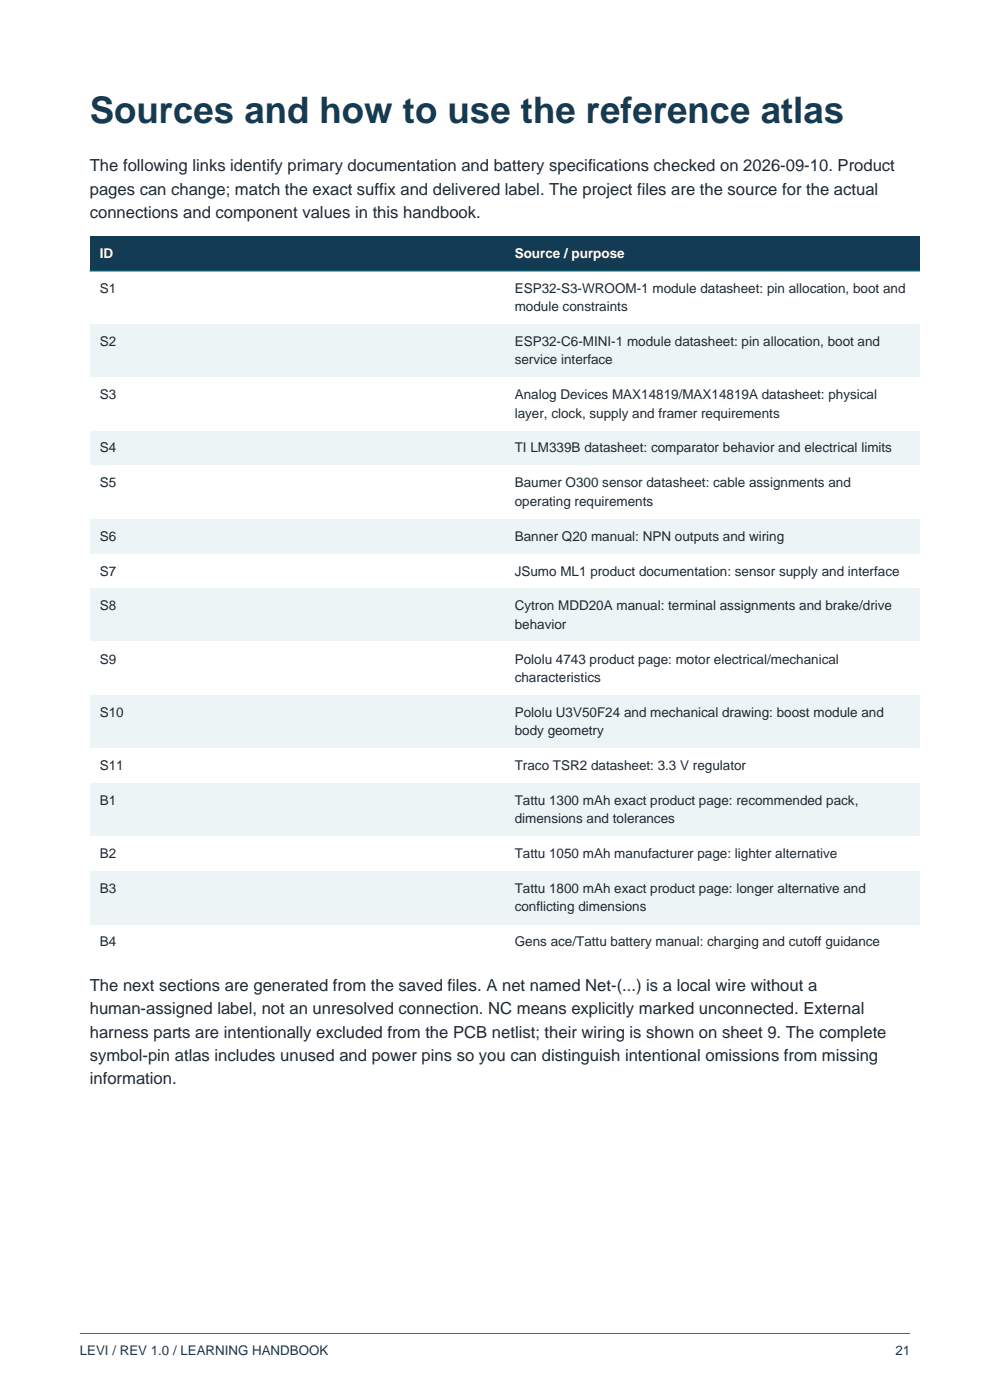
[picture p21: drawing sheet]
<svg xmlns="http://www.w3.org/2000/svg" width="210mm" height="297mm" viewBox="0 0 210 297" stroke-linecap="round" stroke-linejoin="round" font-family="sans-serif">
<defs><g id="words">
<text font-size="7.8" fill="#133b53" x="19" y="26.1">Sources and how to use the reference atlas</text>
<g font-size="3.5" fill="#1f2933">
<text x="19" y="36.3">The following links identify primary documentation and battery specifications checked on 2026-09-10. Product</text>
<text x="19" y="41.3">pages can change; match the exact suffix and delivered label. The project files are the source for the actual</text>
<text x="19" y="46.2">connections and component values in this handbook.</text>
<text x="19" y="210.3">The next sections are generated from the saved files. A net named Net-(...) is a local wire without a</text>
<text x="19" y="215.2">human-assigned label, not an unresolved connection. NC means explicitly marked unconnected. External</text>
<text x="19" y="220.1">harness parts are intentionally excluded from the PCB netlist; their wiring is shown on sheet 9. The complete</text>
<text x="19" y="225.1">symbol-pin atlas includes unused and power pins so you can distinguish intentional omissions from missing</text>
<text x="19" y="230">information.</text>
</g>
<g font-size="2.9" fill="#fff">
<text x="21.2" y="54.7">ID</text>
<text x="109.2" y="54.7">Source / purpose</text>
</g>
<g font-size="2.9" fill="#1f2933">
<text x="21.2" y="62.1">S1</text>
<text x="109.2" y="62.1">ESP32-S3-WROOM-1 module datasheet: pin allocation, boot and</text>
<text x="109.2" y="66">module constraints</text>
<text x="21.2" y="73.4">S2</text>
<text x="109.2" y="73.4">ESP32-C6-MINI-1 module datasheet: pin allocation, boot and</text>
<text x="109.2" y="77.3">service interface</text>
<text x="21.2" y="84.7">S3</text>
<text x="109.2" y="84.7">Analog Devices MAX14819/MAX14819A datasheet: physical</text>
<text x="109.2" y="88.6">layer, clock, supply and framer requirements</text>
<text x="21.2" y="96">S4</text>
<text x="109.2" y="96">TI LM339B datasheet: comparator behavior and electrical limits</text>
<text x="21.2" y="103.4">S5</text>
<text x="109.2" y="103.4">Baumer O300 sensor datasheet: cable assignments and</text>
<text x="109.2" y="107.3">operating requirements</text>
<text x="21.2" y="114.7">S6</text>
<text x="109.2" y="114.7">Banner Q20 manual: NPN outputs and wiring</text>
<text x="21.2" y="122.1">S7</text>
<text x="109.2" y="122.1">JSumo ML1 product documentation: sensor supply and interface</text>
<text x="21.2" y="129.5">S8</text>
<text x="109.2" y="129.5">Cytron MDD20A manual: terminal assignments and brake/drive</text>
<text x="109.2" y="133.4">behavior</text>
<text x="21.2" y="140.8">S9</text>
<text x="109.2" y="140.8">Pololu 4743 product page: motor electrical/mechanical</text>
<text x="109.2" y="144.7">characteristics</text>
<text x="21.2" y="152.1">S10</text>
<text x="109.2" y="152.1">Pololu U3V50F24 and mechanical drawing: boost module and</text>
<text x="109.2" y="156">body geometry</text>
<text x="21.2" y="163.4">S11</text>
<text x="109.2" y="163.4">Traco TSR2 datasheet: 3.3 V regulator</text>
<text x="21.2" y="170.8">B1</text>
<text x="109.2" y="170.8">Tattu 1300 mAh exact product page: recommended pack,</text>
<text x="109.2" y="174.7">dimensions and tolerances</text>
<text x="21.2" y="182.1">B2</text>
<text x="109.2" y="182.1">Tattu 1050 mAh manufacturer page: lighter alternative</text>
<text x="21.2" y="189.5">B3</text>
<text x="109.2" y="189.5">Tattu 1800 mAh exact product page: longer alternative and</text>
<text x="109.2" y="193.4">conflicting dimensions</text>
<text x="21.2" y="200.8">B4</text>
<text x="109.2" y="200.8">Gens ace/Tattu battery manual: charging and cutoff guidance</text>
</g>
<g font-size="2.8" fill="#133b53">
<text x="16.9" y="287.5">LEVI / REV 1.0 / LEARNING HANDBOOK</text>
<text x="189.9" y="287.5">21</text>
</g>
</g></defs>
<path d="M16.9 282.9h176.2" fill="none" stroke="#087f8c" stroke-width=".21"/>
<path d="M19 50.1h176.1v7.4h-176.1z" fill-rule="evenodd" fill="#133b53"/>
<path d="M19 57.5h176.1v11.3h-176.1z" fill-rule="evenodd" fill="#fff"/>
<path d="M19 68.8h176.1v11.3h-176.1z" fill-rule="evenodd" fill="#edf4f6"/>
<path d="M19 80.1h176.1v11.3h-176.1z" fill-rule="evenodd" fill="#fff"/>
<path d="M19 91.4h176.1v7.4h-176.1z" fill-rule="evenodd" fill="#edf4f6"/>
<path d="M19 98.8h176.1v11.3h-176.1z" fill-rule="evenodd" fill="#fff"/>
<path d="M19 110.1h176.1v7.4h-176.1z" fill-rule="evenodd" fill="#edf4f6"/>
<path d="M19 117.5h176.1v7.4h-176.1z" fill-rule="evenodd" fill="#fff"/>
<path d="M19 124.9h176.1v11.3h-176.1z" fill-rule="evenodd" fill="#edf4f6"/>
<path d="M19 136.2h176.1v11.3h-176.1z" fill-rule="evenodd" fill="#fff"/>
<path d="M19 147.5h176.1v11.2h-176.1z" fill-rule="evenodd" fill="#edf4f6"/>
<path d="M19 158.7h176.1v7.5h-176.1z" fill-rule="evenodd" fill="#fff"/>
<path d="M19 166.2h176.1v11.2h-176.1z" fill-rule="evenodd" fill="#edf4f6"/>
<path d="M19 177.4h176.1v7.5h-176.1z" fill-rule="evenodd" fill="#fff"/>
<path d="M19 184.9h176.1v11.2h-176.1z" fill-rule="evenodd" fill="#edf4f6"/>
<path d="M19 196.1h176.1v7.5h-176.1z" fill-rule="evenodd" fill="#fff"/>
<path d="M19 57.5h176.1" fill="none" stroke="#087f8c" stroke-width=".21"/>
<use href="#words"/>
</svg>
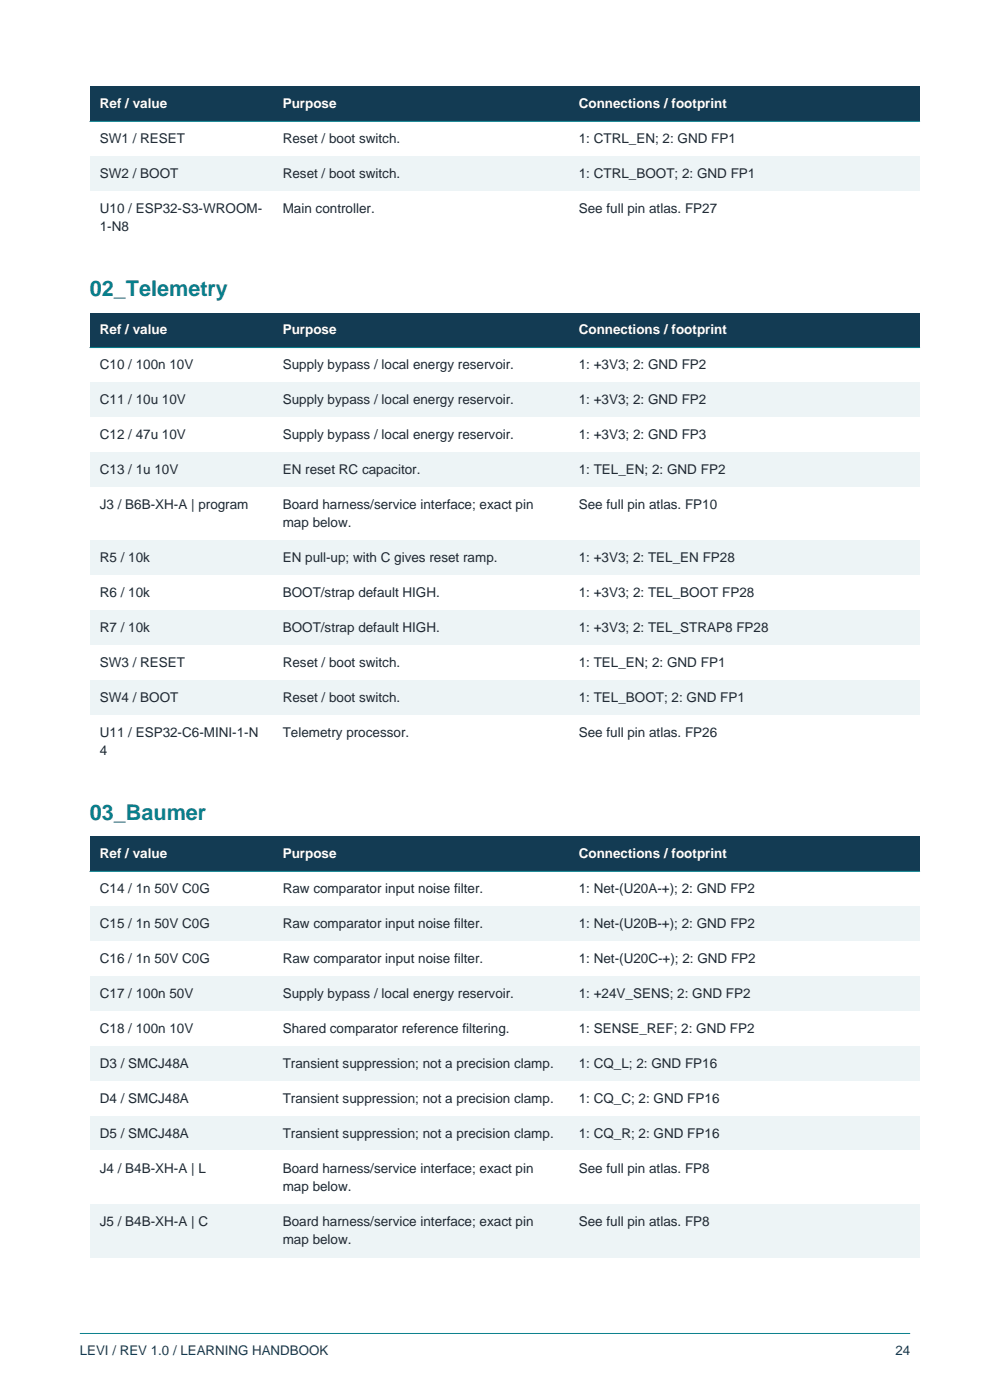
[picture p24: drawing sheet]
<svg xmlns="http://www.w3.org/2000/svg" width="210mm" height="297mm" viewBox="0 0 210 297" stroke-linecap="round" stroke-linejoin="round" font-family="sans-serif">
<defs><g id="words">
<g font-size="4.6" fill="#087f8c">
<text x="19" y="62.8">02_Telemetry</text>
<text x="19" y="173.9">03_Baumer</text>
</g>
<g font-size="2.9" fill="#fff">
<text x="21.2" y="23">Ref / value</text>
<text x="60" y="23">Purpose</text>
<text x="122.8" y="23">Connections / footprint</text>
<text x="21.2" y="70.9">Ref / value</text>
<text x="60" y="70.9">Purpose</text>
<text x="122.8" y="70.9">Connections / footprint</text>
<text x="21.2" y="182.1">Ref / value</text>
<text x="60" y="182.1">Purpose</text>
<text x="122.8" y="182.1">Connections / footprint</text>
</g>
<g font-size="2.9" fill="#1f2933">
<text x="21.2" y="30.4">SW1 / RESET</text>
<text x="60" y="30.4">Reset / boot switch.</text>
<text x="122.8" y="30.4">1: CTRL_EN; 2: GND FP1</text>
<text x="21.2" y="37.8">SW2 / BOOT</text>
<text x="60" y="37.8">Reset / boot switch.</text>
<text x="122.8" y="37.8">1: CTRL_BOOT; 2: GND FP1</text>
<text x="21.2" y="45.2">U10 / ESP32-S3-WROOM-</text>
<text x="60" y="45.2">Main controller.</text>
<text x="122.8" y="45.2">See full pin atlas. FP27</text>
<text x="21.2" y="49.1">1-N8</text>
<text x="21.2" y="78.4">C10 / 100n 10V</text>
<text x="60" y="78.4">Supply bypass / local energy reservoir.</text>
<text x="122.8" y="78.4">1: +3V3; 2: GND FP2</text>
<text x="21.2" y="85.8">C11 / 10u 10V</text>
<text x="60" y="85.8">Supply bypass / local energy reservoir.</text>
<text x="122.8" y="85.8">1: +3V3; 2: GND FP2</text>
<text x="21.2" y="93.2">C12 / 47u 10V</text>
<text x="60" y="93.2">Supply bypass / local energy reservoir.</text>
<text x="122.8" y="93.2">1: +3V3; 2: GND FP3</text>
<text x="21.2" y="100.6">C13 / 1u 10V</text>
<text x="60" y="100.6">EN reset RC capacitor.</text>
<text x="122.8" y="100.6">1: TEL_EN; 2: GND FP2</text>
<text x="21.2" y="108">J3 / B6B-XH-A | program</text>
<text x="60" y="108">Board harness/service interface; exact pin</text>
<text x="122.8" y="108">See full pin atlas. FP10</text>
<text x="60" y="111.9">map below.</text>
<text x="21.2" y="119.3">R5 / 10k</text>
<text x="60" y="119.3">EN pull-up; with C gives reset ramp.</text>
<text x="122.8" y="119.3">1: +3V3; 2: TEL_EN FP28</text>
<text x="21.2" y="126.7">R6 / 10k</text>
<text x="60" y="126.7">BOOT/strap default HIGH.</text>
<text x="122.8" y="126.7">1: +3V3; 2: TEL_BOOT FP28</text>
<text x="21.2" y="134.1">R7 / 10k</text>
<text x="60" y="134.1">BOOT/strap default HIGH.</text>
<text x="122.8" y="134.1">1: +3V3; 2: TEL_STRAP8 FP28</text>
<text x="21.2" y="141.5">SW3 / RESET</text>
<text x="60" y="141.5">Reset / boot switch.</text>
<text x="122.8" y="141.5">1: TEL_EN; 2: GND FP1</text>
<text x="21.2" y="148.9">SW4 / BOOT</text>
<text x="60" y="148.9">Reset / boot switch.</text>
<text x="122.8" y="148.9">1: TEL_BOOT; 2: GND FP1</text>
<text x="21.2" y="156.3">U11 / ESP32-C6-MINI-1-N</text>
<text x="21.2" y="160.2">4</text>
<text x="60" y="156.3">Telemetry processor.</text>
<text x="122.8" y="156.3">See full pin atlas. FP26</text>
<text x="21.2" y="189.5">C14 / 1n 50V C0G</text>
<text x="60" y="189.5">Raw comparator input noise filter.</text>
<text x="122.8" y="189.5">1: Net-(U20A-+); 2: GND FP2</text>
<text x="21.2" y="196.9">C15 / 1n 50V C0G</text>
<text x="60" y="196.9">Raw comparator input noise filter.</text>
<text x="122.8" y="196.9">1: Net-(U20B-+); 2: GND FP2</text>
<text x="21.2" y="204.3">C16 / 1n 50V C0G</text>
<text x="60" y="204.3">Raw comparator input noise filter.</text>
<text x="122.8" y="204.3">1: Net-(U20C-+); 2: GND FP2</text>
<text x="21.2" y="211.7">C17 / 100n 50V</text>
<text x="60" y="211.7">Supply bypass / local energy reservoir.</text>
<text x="122.8" y="211.7">1: +24V_SENS; 2: GND FP2</text>
<text x="21.2" y="219.1">C18 / 100n 10V</text>
<text x="60" y="219.1">Shared comparator reference filtering.</text>
<text x="122.8" y="219.1">1: SENSE_REF; 2: GND FP2</text>
<text x="21.2" y="226.5">D3 / SMCJ48A</text>
<text x="60" y="226.5">Transient suppression; not a precision clamp.</text>
<text x="122.8" y="226.5">1: CQ_L; 2: GND FP16</text>
<text x="21.2" y="233.9">D4 / SMCJ48A</text>
<text x="60" y="233.9">Transient suppression; not a precision clamp.</text>
<text x="122.8" y="233.9">1: CQ_C; 2: GND FP16</text>
<text x="21.2" y="241.3">D5 / SMCJ48A</text>
<text x="60" y="241.3">Transient suppression; not a precision clamp.</text>
<text x="122.8" y="241.3">1: CQ_R; 2: GND FP16</text>
<text x="21.2" y="248.7">J4 / B4B-XH-A | L</text>
<text x="60" y="248.7">Board harness/service interface; exact pin</text>
<text x="122.8" y="248.7">See full pin atlas. FP8</text>
<text x="60" y="252.6">map below.</text>
<text x="21.2" y="260">J5 / B4B-XH-A | C</text>
<text x="60" y="260">Board harness/service interface; exact pin</text>
<text x="60" y="263.9">map below.</text>
<text x="122.8" y="260">See full pin atlas. FP8</text>
</g>
<g font-size="2.8" fill="#133b53">
<text x="16.9" y="287.5">LEVI / REV 1.0 / LEARNING HANDBOOK</text>
<text x="189.9" y="287.5">24</text>
</g>
</g></defs>
<path d="M16.9 282.9h176.2" fill="none" stroke="#087f8c" stroke-width=".21"/>
<path d="M19 18.3h176.1v7.5h-176.1z" fill-rule="evenodd" fill="#133b53"/>
<path d="M19 25.8h176.1v7.4h-176.1z" fill-rule="evenodd" fill="#fff"/>
<path d="M19 33.2h176.1v7.4h-176.1z" fill-rule="evenodd" fill="#edf4f6"/>
<path d="M19 40.6h176.1v11.3h-176.1z" fill-rule="evenodd" fill="#fff"/>
<path d="M19 25.8h176.1" fill="none" stroke="#087f8c" stroke-width=".21"/>
<path d="M19 66.3h176.1v7.4h-176.1z" fill-rule="evenodd" fill="#133b53"/>
<path d="M19 73.7h176.1v7.4h-176.1z" fill-rule="evenodd" fill="#fff"/>
<path d="M19 81.1h176.1v7.4h-176.1z" fill-rule="evenodd" fill="#edf4f6"/>
<path d="M19 88.5h176.1v7.5h-176.1z" fill-rule="evenodd" fill="#fff"/>
<path d="M19 96h176.1v7.4h-176.1z" fill-rule="evenodd" fill="#edf4f6"/>
<path d="M19 103.4h176.1v11.3h-176.1z" fill-rule="evenodd" fill="#fff"/>
<path d="M19 114.7h176.1v7.4h-176.1z" fill-rule="evenodd" fill="#edf4f6"/>
<path d="M19 122.1h176.1v7.4h-176.1z" fill-rule="evenodd" fill="#fff"/>
<path d="M19 129.5h176.1v7.4h-176.1z" fill-rule="evenodd" fill="#edf4f6"/>
<path d="M19 136.9h176.1v7.4h-176.1z" fill-rule="evenodd" fill="#fff"/>
<path d="M19 144.3h176.1v7.4h-176.1z" fill-rule="evenodd" fill="#edf4f6"/>
<path d="M19 151.7h176.1v11.3h-176.1z" fill-rule="evenodd" fill="#fff"/>
<path d="M19 73.7h176.1" fill="none" stroke="#087f8c" stroke-width=".21"/>
<path d="M19 177.4h176.1v7.5h-176.1z" fill-rule="evenodd" fill="#133b53"/>
<path d="M19 184.9h176.1v7.4h-176.1z" fill-rule="evenodd" fill="#fff"/>
<path d="M19 192.3h176.1v7.4h-176.1z" fill-rule="evenodd" fill="#edf4f6"/>
<path d="M19 199.7h176.1v7.4h-176.1z" fill-rule="evenodd" fill="#fff"/>
<path d="M19 207.1h176.1v7.4h-176.1z" fill-rule="evenodd" fill="#edf4f6"/>
<path d="M19 214.5h176.1v7.4h-176.1z" fill-rule="evenodd" fill="#fff"/>
<path d="M19 221.9h176.1v7.4h-176.1z" fill-rule="evenodd" fill="#edf4f6"/>
<path d="M19 229.3h176.1v7.4h-176.1z" fill-rule="evenodd" fill="#fff"/>
<path d="M19 236.7h176.1v7.4h-176.1z" fill-rule="evenodd" fill="#edf4f6"/>
<path d="M19 244.1h176.1v11.3h-176.1z" fill-rule="evenodd" fill="#fff"/>
<path d="M19 255.4h176.1v11.3h-176.1z" fill-rule="evenodd" fill="#edf4f6"/>
<path d="M19 184.9h176.1" fill="none" stroke="#087f8c" stroke-width=".21"/>
<use href="#words"/>
</svg>
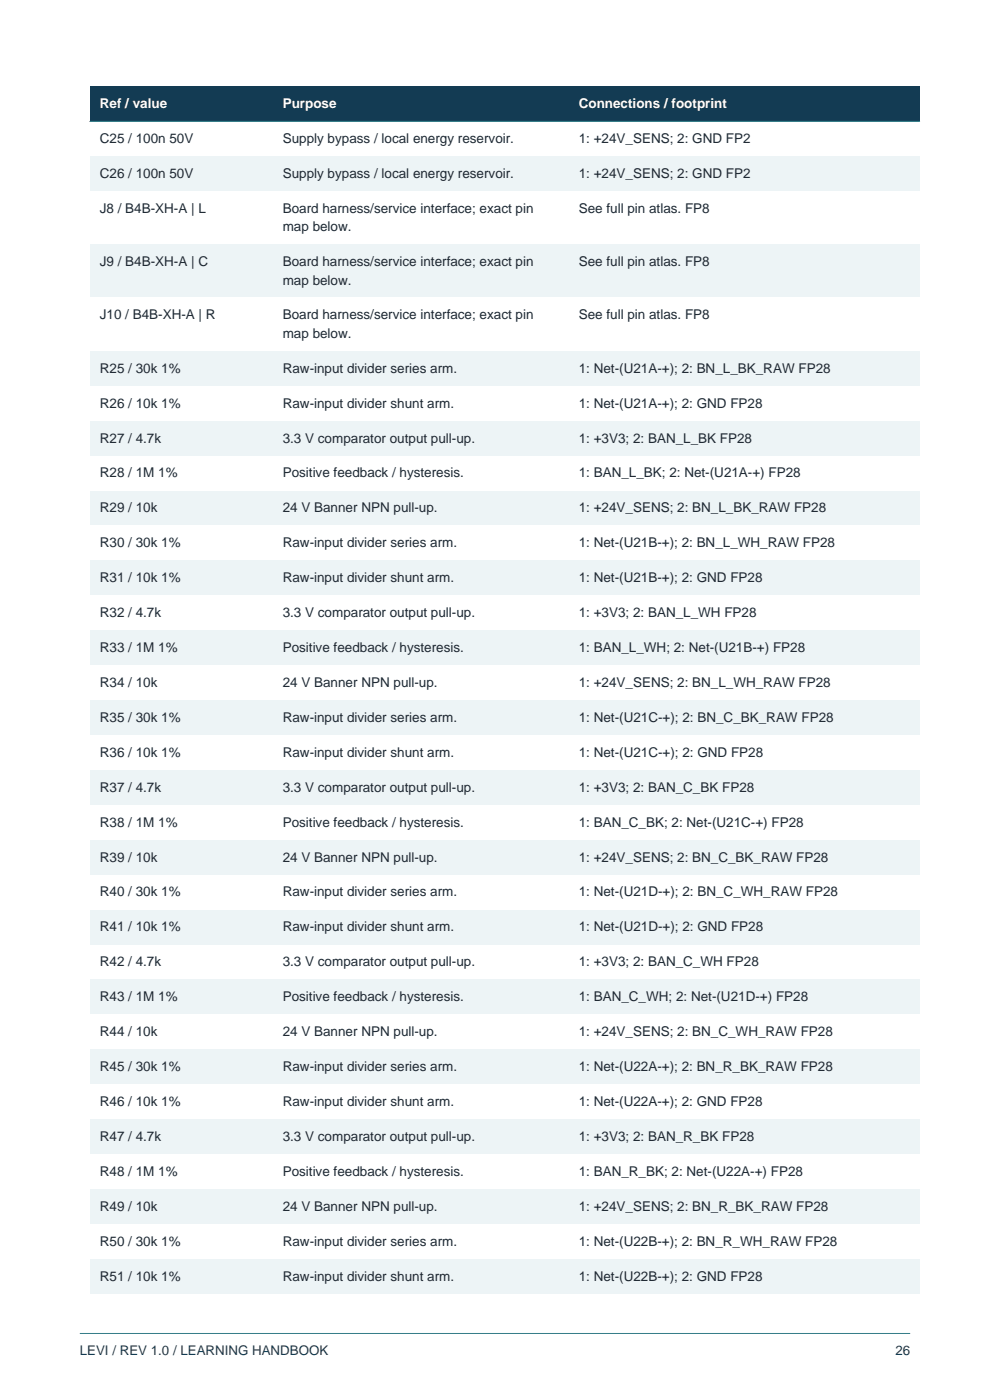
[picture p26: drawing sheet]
<svg xmlns="http://www.w3.org/2000/svg" width="210mm" height="297mm" viewBox="0 0 210 297" stroke-linecap="round" stroke-linejoin="round" font-family="sans-serif">
<defs><g id="words">
<g font-size="2.9" fill="#fff">
<text x="21.2" y="23">Ref / value</text>
<text x="60" y="23">Purpose</text>
<text x="122.8" y="23">Connections / footprint</text>
</g>
<g font-size="2.9" fill="#1f2933">
<text x="21.2" y="30.4">C25 / 100n 50V</text>
<text x="60" y="30.4">Supply bypass / local energy reservoir.</text>
<text x="122.8" y="30.4">1: +24V_SENS; 2: GND FP2</text>
<text x="21.2" y="37.8">C26 / 100n 50V</text>
<text x="60" y="37.8">Supply bypass / local energy reservoir.</text>
<text x="122.8" y="37.8">1: +24V_SENS; 2: GND FP2</text>
<text x="21.2" y="45.2">J8 / B4B-XH-A | L</text>
<text x="60" y="45.2">Board harness/service interface; exact pin</text>
<text x="122.8" y="45.2">See full pin atlas. FP8</text>
<text x="60" y="49.1">map below.</text>
<text x="21.2" y="56.5">J9 / B4B-XH-A | C</text>
<text x="60" y="56.5">Board harness/service interface; exact pin</text>
<text x="122.8" y="56.5">See full pin atlas. FP8</text>
<text x="60" y="60.4">map below.</text>
<text x="21.2" y="67.8">J10 / B4B-XH-A | R</text>
<text x="60" y="67.8">Board harness/service interface; exact pin</text>
<text x="60" y="71.6">map below.</text>
<text x="122.8" y="67.8">See full pin atlas. FP8</text>
<text x="21.2" y="79.1">R25 / 30k 1%</text>
<text x="60" y="79.1">Raw-input divider series arm.</text>
<text x="122.8" y="79.1">1: Net-(U21A-+); 2: BN_L_BK_RAW FP28</text>
<text x="21.2" y="86.5">R26 / 10k 1%</text>
<text x="60" y="86.5">Raw-input divider shunt arm.</text>
<text x="122.8" y="86.5">1: Net-(U21A-+); 2: GND FP28</text>
<text x="21.2" y="93.9">R27 / 4.7k</text>
<text x="60" y="93.9">3.3 V comparator output pull-up.</text>
<text x="122.8" y="93.9">1: +3V3; 2: BAN_L_BK FP28</text>
<text x="21.2" y="101.3">R28 / 1M 1%</text>
<text x="60" y="101.3">Positive feedback / hysteresis.</text>
<text x="122.8" y="101.3">1: BAN_L_BK; 2: Net-(U21A-+) FP28</text>
<text x="21.2" y="108.7">R29 / 10k</text>
<text x="60" y="108.7">24 V Banner NPN pull-up.</text>
<text x="122.8" y="108.7">1: +24V_SENS; 2: BN_L_BK_RAW FP28</text>
<text x="21.2" y="116.1">R30 / 30k 1%</text>
<text x="60" y="116.1">Raw-input divider series arm.</text>
<text x="122.8" y="116.1">1: Net-(U21B-+); 2: BN_L_WH_RAW FP28</text>
<text x="21.2" y="123.5">R31 / 10k 1%</text>
<text x="60" y="123.5">Raw-input divider shunt arm.</text>
<text x="122.8" y="123.5">1: Net-(U21B-+); 2: GND FP28</text>
<text x="21.2" y="130.9">R32 / 4.7k</text>
<text x="60" y="130.9">3.3 V comparator output pull-up.</text>
<text x="122.8" y="130.9">1: +3V3; 2: BAN_L_WH FP28</text>
<text x="21.2" y="138.3">R33 / 1M 1%</text>
<text x="60" y="138.3">Positive feedback / hysteresis.</text>
<text x="122.8" y="138.3">1: BAN_L_WH; 2: Net-(U21B-+) FP28</text>
<text x="21.2" y="145.7">R34 / 10k</text>
<text x="60" y="145.7">24 V Banner NPN pull-up.</text>
<text x="122.8" y="145.7">1: +24V_SENS; 2: BN_L_WH_RAW FP28</text>
<text x="21.2" y="153.1">R35 / 30k 1%</text>
<text x="60" y="153.1">Raw-input divider series arm.</text>
<text x="122.8" y="153.1">1: Net-(U21C-+); 2: BN_C_BK_RAW FP28</text>
<text x="21.2" y="160.5">R36 / 10k 1%</text>
<text x="60" y="160.5">Raw-input divider shunt arm.</text>
<text x="122.8" y="160.5">1: Net-(U21C-+); 2: GND FP28</text>
<text x="21.2" y="168">R37 / 4.7k</text>
<text x="60" y="168">3.3 V comparator output pull-up.</text>
<text x="122.8" y="168">1: +3V3; 2: BAN_C_BK FP28</text>
<text x="21.2" y="175.4">R38 / 1M 1%</text>
<text x="60" y="175.4">Positive feedback / hysteresis.</text>
<text x="122.8" y="175.4">1: BAN_C_BK; 2: Net-(U21C-+) FP28</text>
<text x="21.2" y="182.8">R39 / 10k</text>
<text x="60" y="182.8">24 V Banner NPN pull-up.</text>
<text x="122.8" y="182.8">1: +24V_SENS; 2: BN_C_BK_RAW FP28</text>
<text x="21.2" y="190.2">R40 / 30k 1%</text>
<text x="60" y="190.2">Raw-input divider series arm.</text>
<text x="122.8" y="190.2">1: Net-(U21D-+); 2: BN_C_WH_RAW FP28</text>
<text x="21.2" y="197.6">R41 / 10k 1%</text>
<text x="60" y="197.6">Raw-input divider shunt arm.</text>
<text x="122.8" y="197.6">1: Net-(U21D-+); 2: GND FP28</text>
<text x="21.2" y="205">R42 / 4.7k</text>
<text x="60" y="205">3.3 V comparator output pull-up.</text>
<text x="122.8" y="205">1: +3V3; 2: BAN_C_WH FP28</text>
<text x="21.2" y="212.4">R43 / 1M 1%</text>
<text x="60" y="212.4">Positive feedback / hysteresis.</text>
<text x="122.8" y="212.4">1: BAN_C_WH; 2: Net-(U21D-+) FP28</text>
<text x="21.2" y="219.8">R44 / 10k</text>
<text x="60" y="219.8">24 V Banner NPN pull-up.</text>
<text x="122.8" y="219.8">1: +24V_SENS; 2: BN_C_WH_RAW FP28</text>
<text x="21.2" y="227.2">R45 / 30k 1%</text>
<text x="60" y="227.2">Raw-input divider series arm.</text>
<text x="122.8" y="227.2">1: Net-(U22A-+); 2: BN_R_BK_RAW FP28</text>
<text x="21.2" y="234.6">R46 / 10k 1%</text>
<text x="60" y="234.6">Raw-input divider shunt arm.</text>
<text x="122.8" y="234.6">1: Net-(U22A-+); 2: GND FP28</text>
<text x="21.2" y="242">R47 / 4.7k</text>
<text x="60" y="242">3.3 V comparator output pull-up.</text>
<text x="122.8" y="242">1: +3V3; 2: BAN_R_BK FP28</text>
<text x="21.2" y="249.4">R48 / 1M 1%</text>
<text x="60" y="249.4">Positive feedback / hysteresis.</text>
<text x="122.8" y="249.4">1: BAN_R_BK; 2: Net-(U22A-+) FP28</text>
<text x="21.2" y="256.9">R49 / 10k</text>
<text x="60" y="256.9">24 V Banner NPN pull-up.</text>
<text x="122.8" y="256.9">1: +24V_SENS; 2: BN_R_BK_RAW FP28</text>
<text x="21.2" y="264.3">R50 / 30k 1%</text>
<text x="60" y="264.3">Raw-input divider series arm.</text>
<text x="122.8" y="264.3">1: Net-(U22B-+); 2: BN_R_WH_RAW FP28</text>
<text x="21.2" y="271.7">R51 / 10k 1%</text>
<text x="60" y="271.7">Raw-input divider shunt arm.</text>
<text x="122.8" y="271.7">1: Net-(U22B-+); 2: GND FP28</text>
</g>
<g font-size="2.8" fill="#133b53">
<text x="16.9" y="287.5">LEVI / REV 1.0 / LEARNING HANDBOOK</text>
<text x="189.9" y="287.5">26</text>
</g>
</g></defs>
<path d="M16.9 282.9h176.2" fill="none" stroke="#087f8c" stroke-width=".21"/>
<path d="M19 18.3h176.1v7.5h-176.1z" fill-rule="evenodd" fill="#133b53"/>
<path d="M19 25.8h176.1v7.4h-176.1z" fill-rule="evenodd" fill="#fff"/>
<path d="M19 33.2h176.1v7.4h-176.1z" fill-rule="evenodd" fill="#edf4f6"/>
<path d="M19 40.6h176.1v11.3h-176.1z" fill-rule="evenodd" fill="#fff"/>
<path d="M19 51.9h176.1v11.2h-176.1z" fill-rule="evenodd" fill="#edf4f6"/>
<path d="M19 63.1h176.1v11.3h-176.1z" fill-rule="evenodd" fill="#fff"/>
<path d="M19 74.4h176.1v7.4h-176.1z" fill-rule="evenodd" fill="#edf4f6"/>
<path d="M19 81.8h176.1v7.5h-176.1z" fill-rule="evenodd" fill="#fff"/>
<path d="M19 89.3h176.1v7.4h-176.1z" fill-rule="evenodd" fill="#edf4f6"/>
<path d="M19 96.7h176.1v7.4h-176.1z" fill-rule="evenodd" fill="#fff"/>
<path d="M19 104.1h176.1v7.4h-176.1z" fill-rule="evenodd" fill="#edf4f6"/>
<path d="M19 111.5h176.1v7.4h-176.1z" fill-rule="evenodd" fill="#fff"/>
<path d="M19 118.9h176.1v7.4h-176.1z" fill-rule="evenodd" fill="#edf4f6"/>
<path d="M19 126.3h176.1v7.4h-176.1z" fill-rule="evenodd" fill="#fff"/>
<path d="M19 133.7h176.1v7.4h-176.1z" fill-rule="evenodd" fill="#edf4f6"/>
<path d="M19 141.1h176.1v7.4h-176.1z" fill-rule="evenodd" fill="#fff"/>
<path d="M19 148.5h176.1v7.4h-176.1z" fill-rule="evenodd" fill="#edf4f6"/>
<path d="M19 155.9h176.1v7.4h-176.1z" fill-rule="evenodd" fill="#fff"/>
<path d="M19 163.3h176.1v7.4h-176.1z" fill-rule="evenodd" fill="#edf4f6"/>
<path d="M19 170.7h176.1v7.5h-176.1z" fill-rule="evenodd" fill="#fff"/>
<path d="M19 178.2h176.1v7.4h-176.1z" fill-rule="evenodd" fill="#edf4f6"/>
<path d="M19 185.6h176.1v7.4h-176.1z" fill-rule="evenodd" fill="#fff"/>
<path d="M19 193h176.1v7.4h-176.1z" fill-rule="evenodd" fill="#edf4f6"/>
<path d="M19 200.4h176.1v7.4h-176.1z" fill-rule="evenodd" fill="#fff"/>
<path d="M19 207.8h176.1v7.4h-176.1z" fill-rule="evenodd" fill="#edf4f6"/>
<path d="M19 215.2h176.1v7.4h-176.1z" fill-rule="evenodd" fill="#fff"/>
<path d="M19 222.6h176.1v7.4h-176.1z" fill-rule="evenodd" fill="#edf4f6"/>
<path d="M19 230h176.1v7.4h-176.1z" fill-rule="evenodd" fill="#fff"/>
<path d="M19 237.4h176.1v7.4h-176.1z" fill-rule="evenodd" fill="#edf4f6"/>
<path d="M19 244.8h176.1v7.4h-176.1z" fill-rule="evenodd" fill="#fff"/>
<path d="M19 252.2h176.1v7.4h-176.1z" fill-rule="evenodd" fill="#edf4f6"/>
<path d="M19 259.6h176.1v7.5h-176.1z" fill-rule="evenodd" fill="#fff"/>
<path d="M19 267.1h176.1v7.4h-176.1z" fill-rule="evenodd" fill="#edf4f6"/>
<path d="M19 25.8h176.1" fill="none" stroke="#087f8c" stroke-width=".21"/>
<use href="#words"/>
</svg>
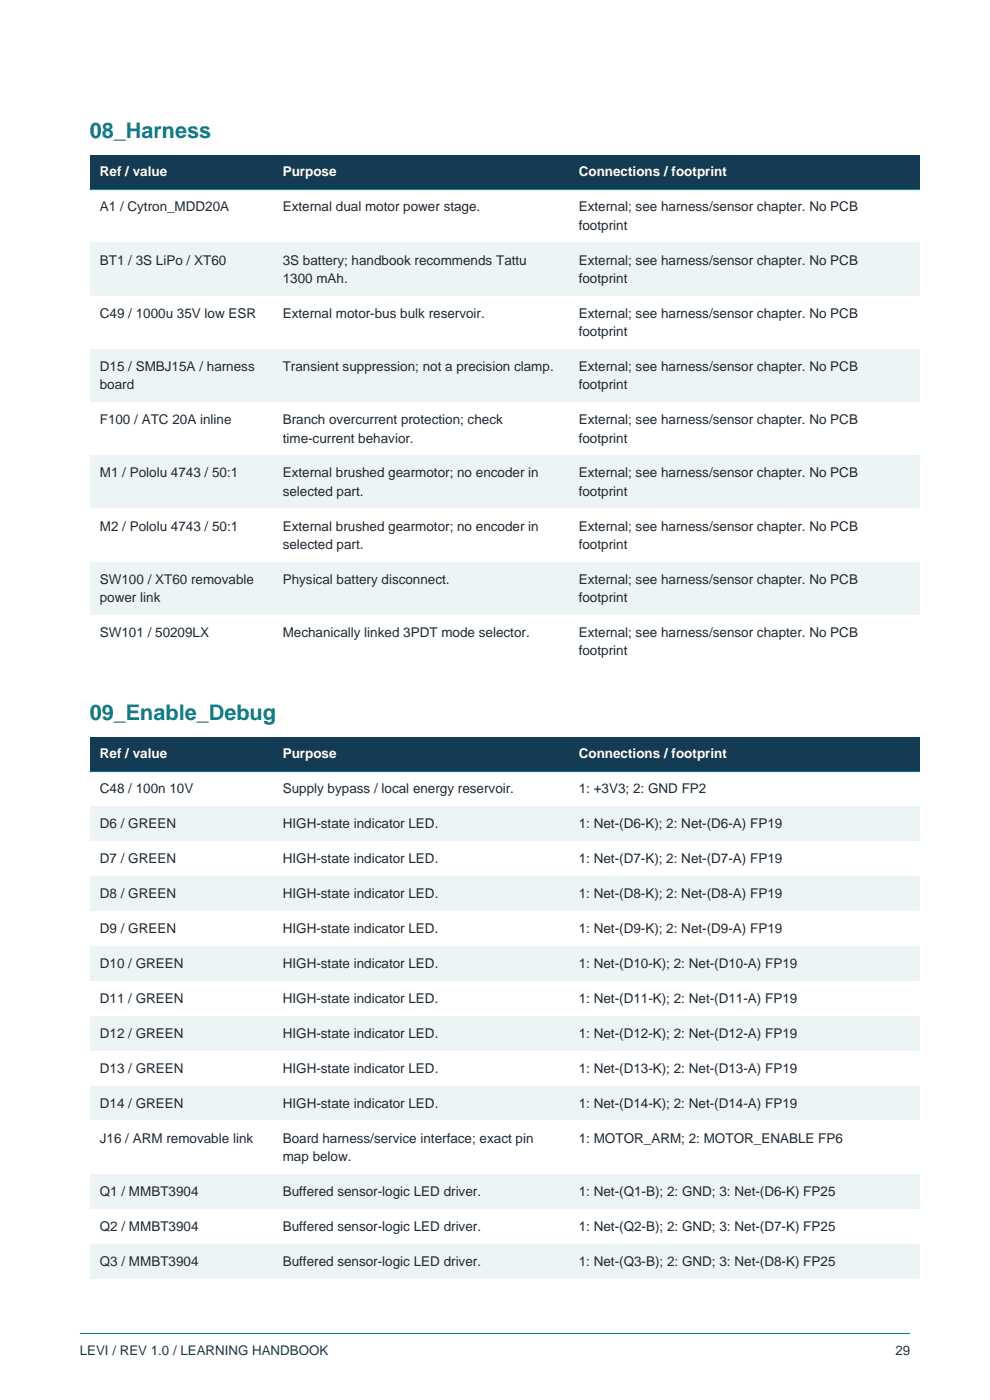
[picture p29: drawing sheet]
<svg xmlns="http://www.w3.org/2000/svg" width="210mm" height="297mm" viewBox="0 0 210 297" stroke-linecap="round" stroke-linejoin="round" font-family="sans-serif">
<defs><g id="words">
<g font-size="4.6" fill="#087f8c">
<text x="19" y="29.3">08_Harness</text>
<text x="19" y="152.8">09_Enable_Debug</text>
</g>
<g font-size="2.9" fill="#fff">
<text x="21.2" y="37.4">Ref / value</text>
<text x="60" y="37.4">Purpose</text>
<text x="122.8" y="37.4">Connections / footprint</text>
<text x="21.2" y="160.9">Ref / value</text>
<text x="60" y="160.9">Purpose</text>
<text x="122.8" y="160.9">Connections / footprint</text>
</g>
<g font-size="2.9" fill="#1f2933">
<text x="21.2" y="44.8">A1 / Cytron_MDD20A</text>
<text x="60" y="44.8">External dual motor power stage.</text>
<text x="122.8" y="44.8">External; see harness/sensor chapter. No PCB</text>
<text x="122.8" y="48.7">footprint</text>
<text x="21.2" y="56.1">BT1 / 3S LiPo / XT60</text>
<text x="60" y="56.1">3S battery; handbook recommends Tattu</text>
<text x="122.8" y="56.1">External; see harness/sensor chapter. No PCB</text>
<text x="60" y="60">1300 mAh.</text>
<text x="122.8" y="60">footprint</text>
<text x="21.2" y="67.4">C49 / 1000u 35V low ESR</text>
<text x="60" y="67.4">External motor-bus bulk reservoir.</text>
<text x="122.8" y="67.4">External; see harness/sensor chapter. No PCB</text>
<text x="122.8" y="71.3">footprint</text>
<text x="21.2" y="78.7">D15 / SMBJ15A / harness</text>
<text x="21.2" y="82.6">board</text>
<text x="60" y="78.7">Transient suppression; not a precision clamp.</text>
<text x="122.8" y="78.7">External; see harness/sensor chapter. No PCB</text>
<text x="122.8" y="82.6">footprint</text>
<text x="21.2" y="90">F100 / ATC 20A inline</text>
<text x="60" y="90">Branch overcurrent protection; check</text>
<text x="122.8" y="90">External; see harness/sensor chapter. No PCB</text>
<text x="60" y="93.9">time-current behavior.</text>
<text x="122.8" y="93.9">footprint</text>
<text x="21.2" y="101.3">M1 / Pololu 4743 / 50:1</text>
<text x="60" y="101.3">External brushed gearmotor; no encoder in</text>
<text x="122.8" y="101.3">External; see harness/sensor chapter. No PCB</text>
<text x="60" y="105.2">selected part.</text>
<text x="122.8" y="105.2">footprint</text>
<text x="21.2" y="112.6">M2 / Pololu 4743 / 50:1</text>
<text x="60" y="112.6">External brushed gearmotor; no encoder in</text>
<text x="122.8" y="112.6">External; see harness/sensor chapter. No PCB</text>
<text x="60" y="116.5">selected part.</text>
<text x="122.8" y="116.5">footprint</text>
<text x="21.2" y="123.9">SW100 / XT60 removable</text>
<text x="60" y="123.9">Physical battery disconnect.</text>
<text x="122.8" y="123.9">External; see harness/sensor chapter. No PCB</text>
<text x="21.2" y="127.7">power link</text>
<text x="122.8" y="127.7">footprint</text>
<text x="21.2" y="135.1">SW101 / 50209LX</text>
<text x="60" y="135.1">Mechanically linked 3PDT mode selector.</text>
<text x="122.8" y="135.1">External; see harness/sensor chapter. No PCB</text>
<text x="122.8" y="139">footprint</text>
<text x="21.2" y="168.3">C48 / 100n 10V</text>
<text x="60" y="168.3">Supply bypass / local energy reservoir.</text>
<text x="122.8" y="168.3">1: +3V3; 2: GND FP2</text>
<text x="21.2" y="175.7">D6 / GREEN</text>
<text x="60" y="175.7">HIGH-state indicator LED.</text>
<text x="122.8" y="175.7">1: Net-(D6-K); 2: Net-(D6-A) FP19</text>
<text x="21.2" y="183.1">D7 / GREEN</text>
<text x="60" y="183.1">HIGH-state indicator LED.</text>
<text x="122.8" y="183.1">1: Net-(D7-K); 2: Net-(D7-A) FP19</text>
<text x="21.2" y="190.5">D8 / GREEN</text>
<text x="60" y="190.5">HIGH-state indicator LED.</text>
<text x="122.8" y="190.5">1: Net-(D8-K); 2: Net-(D8-A) FP19</text>
<text x="21.2" y="197.9">D9 / GREEN</text>
<text x="60" y="197.9">HIGH-state indicator LED.</text>
<text x="122.8" y="197.9">1: Net-(D9-K); 2: Net-(D9-A) FP19</text>
<text x="21.2" y="205.4">D10 / GREEN</text>
<text x="60" y="205.4">HIGH-state indicator LED.</text>
<text x="122.8" y="205.4">1: Net-(D10-K); 2: Net-(D10-A) FP19</text>
<text x="21.2" y="212.8">D11 / GREEN</text>
<text x="60" y="212.8">HIGH-state indicator LED.</text>
<text x="122.8" y="212.8">1: Net-(D11-K); 2: Net-(D11-A) FP19</text>
<text x="21.2" y="220.2">D12 / GREEN</text>
<text x="60" y="220.2">HIGH-state indicator LED.</text>
<text x="122.8" y="220.2">1: Net-(D12-K); 2: Net-(D12-A) FP19</text>
<text x="21.2" y="227.6">D13 / GREEN</text>
<text x="60" y="227.6">HIGH-state indicator LED.</text>
<text x="122.8" y="227.6">1: Net-(D13-K); 2: Net-(D13-A) FP19</text>
<text x="21.2" y="235">D14 / GREEN</text>
<text x="60" y="235">HIGH-state indicator LED.</text>
<text x="122.8" y="235">1: Net-(D14-K); 2: Net-(D14-A) FP19</text>
<text x="21.2" y="242.4">J16 / ARM removable link</text>
<text x="60" y="242.4">Board harness/service interface; exact pin</text>
<text x="122.8" y="242.4">1: MOTOR_ARM; 2: MOTOR_ENABLE FP6</text>
<text x="60" y="246.3">map below.</text>
<text x="21.2" y="253.7">Q1 / MMBT3904</text>
<text x="60" y="253.7">Buffered sensor-logic LED driver.</text>
<text x="122.8" y="253.7">1: Net-(Q1-B); 2: GND; 3: Net-(D6-K) FP25</text>
<text x="21.2" y="261.1">Q2 / MMBT3904</text>
<text x="60" y="261.1">Buffered sensor-logic LED driver.</text>
<text x="122.8" y="261.1">1: Net-(Q2-B); 2: GND; 3: Net-(D7-K) FP25</text>
<text x="21.2" y="268.5">Q3 / MMBT3904</text>
<text x="60" y="268.5">Buffered sensor-logic LED driver.</text>
<text x="122.8" y="268.5">1: Net-(Q3-B); 2: GND; 3: Net-(D8-K) FP25</text>
</g>
<g font-size="2.8" fill="#133b53">
<text x="16.9" y="287.5">LEVI / REV 1.0 / LEARNING HANDBOOK</text>
<text x="189.9" y="287.5">29</text>
</g>
</g></defs>
<path d="M16.9 282.9h176.2" fill="none" stroke="#087f8c" stroke-width=".21"/>
<path d="M19 32.8h176.1v7.4h-176.1z" fill-rule="evenodd" fill="#133b53"/>
<path d="M19 40.2h176.1v11.3h-176.1z" fill-rule="evenodd" fill="#fff"/>
<path d="M19 51.5h176.1v11.3h-176.1z" fill-rule="evenodd" fill="#edf4f6"/>
<path d="M19 62.8h176.1v11.3h-176.1z" fill-rule="evenodd" fill="#fff"/>
<path d="M19 74.1h176.1v11.3h-176.1z" fill-rule="evenodd" fill="#edf4f6"/>
<path d="M19 85.4h176.1v11.3h-176.1z" fill-rule="evenodd" fill="#fff"/>
<path d="M19 96.7h176.1v11.2h-176.1z" fill-rule="evenodd" fill="#edf4f6"/>
<path d="M19 107.9h176.1v11.3h-176.1z" fill-rule="evenodd" fill="#fff"/>
<path d="M19 119.2h176.1v11.3h-176.1z" fill-rule="evenodd" fill="#edf4f6"/>
<path d="M19 130.5h176.1v11.3h-176.1z" fill-rule="evenodd" fill="#fff"/>
<path d="M19 40.2h176.1" fill="none" stroke="#087f8c" stroke-width=".21"/>
<path d="M19 156.3h176.1v7.4h-176.1z" fill-rule="evenodd" fill="#133b53"/>
<path d="M19 163.7h176.1v7.4h-176.1z" fill-rule="evenodd" fill="#fff"/>
<path d="M19 171.1h176.1v7.4h-176.1z" fill-rule="evenodd" fill="#edf4f6"/>
<path d="M19 178.5h176.1v7.4h-176.1z" fill-rule="evenodd" fill="#fff"/>
<path d="M19 185.9h176.1v7.4h-176.1z" fill-rule="evenodd" fill="#edf4f6"/>
<path d="M19 193.3h176.1v7.4h-176.1z" fill-rule="evenodd" fill="#fff"/>
<path d="M19 200.7h176.1v7.4h-176.1z" fill-rule="evenodd" fill="#edf4f6"/>
<path d="M19 208.1h176.1v7.4h-176.1z" fill-rule="evenodd" fill="#fff"/>
<path d="M19 215.5h176.1v7.5h-176.1z" fill-rule="evenodd" fill="#edf4f6"/>
<path d="M19 223h176.1v7.4h-176.1z" fill-rule="evenodd" fill="#fff"/>
<path d="M19 230.4h176.1v7.4h-176.1z" fill-rule="evenodd" fill="#edf4f6"/>
<path d="M19 237.8h176.1v11.3h-176.1z" fill-rule="evenodd" fill="#fff"/>
<path d="M19 249.1h176.1v7.4h-176.1z" fill-rule="evenodd" fill="#edf4f6"/>
<path d="M19 256.5h176.1v7.4h-176.1z" fill-rule="evenodd" fill="#fff"/>
<path d="M19 263.9h176.1v7.4h-176.1z" fill-rule="evenodd" fill="#edf4f6"/>
<path d="M19 163.7h176.1" fill="none" stroke="#087f8c" stroke-width=".21"/>
<use href="#words"/>
</svg>
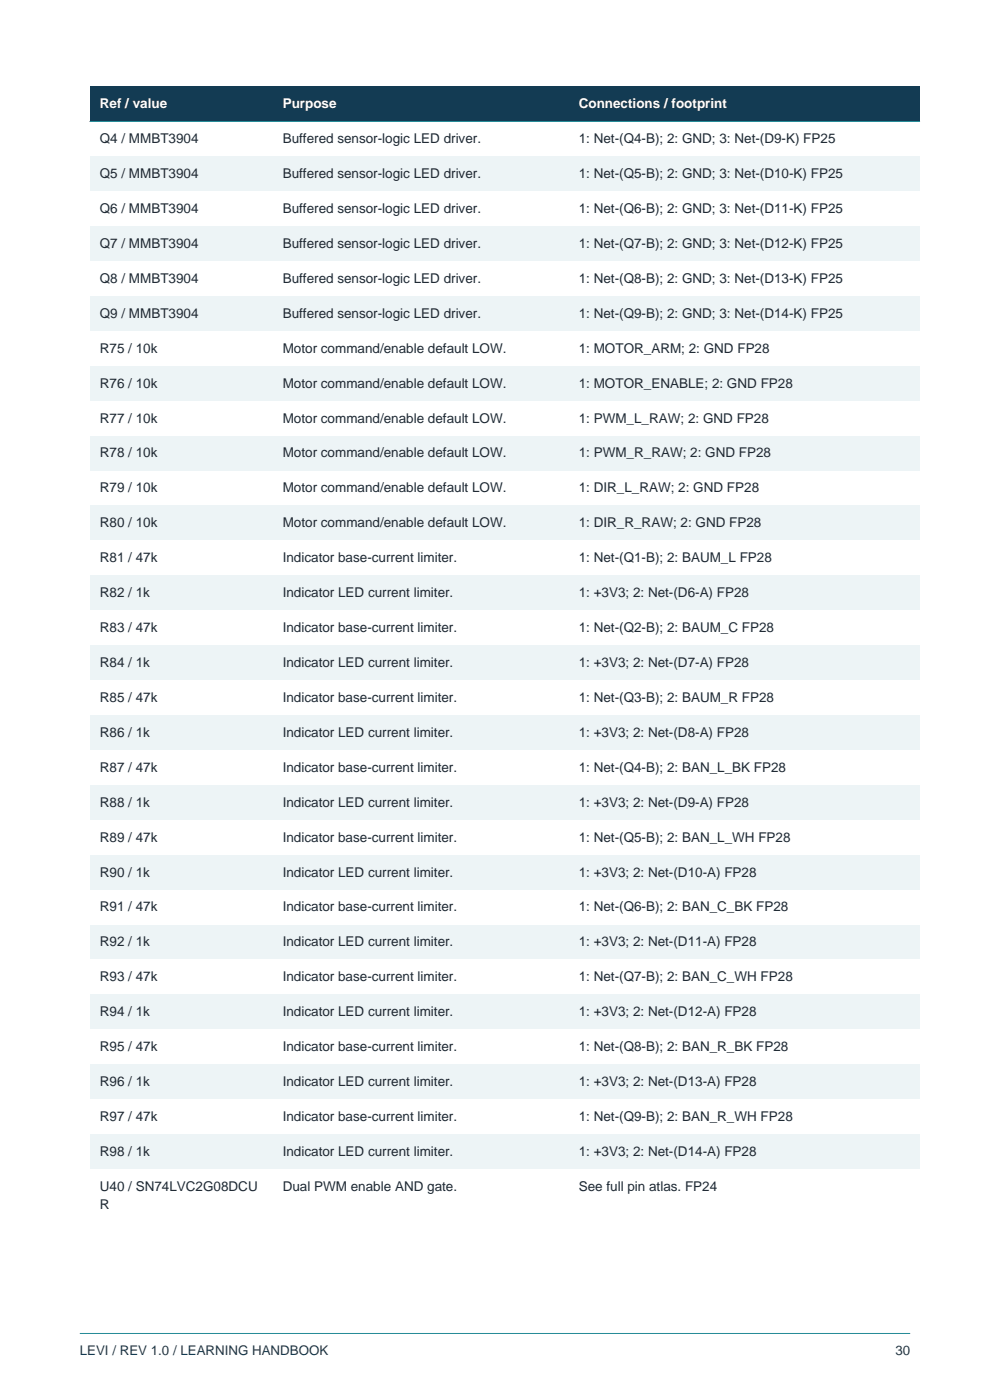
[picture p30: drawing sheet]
<svg xmlns="http://www.w3.org/2000/svg" width="210mm" height="297mm" viewBox="0 0 210 297" stroke-linecap="round" stroke-linejoin="round" font-family="sans-serif">
<defs><g id="words">
<g font-size="2.9" fill="#fff">
<text x="21.2" y="23">Ref / value</text>
<text x="60" y="23">Purpose</text>
<text x="122.8" y="23">Connections / footprint</text>
</g>
<g font-size="2.9" fill="#1f2933">
<text x="21.2" y="30.4">Q4 / MMBT3904</text>
<text x="60" y="30.4">Buffered sensor-logic LED driver.</text>
<text x="122.8" y="30.4">1: Net-(Q4-B); 2: GND; 3: Net-(D9-K) FP25</text>
<text x="21.2" y="37.8">Q5 / MMBT3904</text>
<text x="60" y="37.8">Buffered sensor-logic LED driver.</text>
<text x="122.8" y="37.8">1: Net-(Q5-B); 2: GND; 3: Net-(D10-K) FP25</text>
<text x="21.2" y="45.2">Q6 / MMBT3904</text>
<text x="60" y="45.2">Buffered sensor-logic LED driver.</text>
<text x="122.8" y="45.2">1: Net-(Q6-B); 2: GND; 3: Net-(D11-K) FP25</text>
<text x="21.2" y="52.6">Q7 / MMBT3904</text>
<text x="60" y="52.6">Buffered sensor-logic LED driver.</text>
<text x="122.8" y="52.6">1: Net-(Q7-B); 2: GND; 3: Net-(D12-K) FP25</text>
<text x="21.2" y="60">Q8 / MMBT3904</text>
<text x="60" y="60">Buffered sensor-logic LED driver.</text>
<text x="122.8" y="60">1: Net-(Q8-B); 2: GND; 3: Net-(D13-K) FP25</text>
<text x="21.2" y="67.4">Q9 / MMBT3904</text>
<text x="60" y="67.4">Buffered sensor-logic LED driver.</text>
<text x="122.8" y="67.4">1: Net-(Q9-B); 2: GND; 3: Net-(D14-K) FP25</text>
<text x="21.2" y="74.8">R75 / 10k</text>
<text x="60" y="74.8">Motor command/enable default LOW.</text>
<text x="122.8" y="74.8">1: MOTOR_ARM; 2: GND FP28</text>
<text x="21.2" y="82.2">R76 / 10k</text>
<text x="60" y="82.2">Motor command/enable default LOW.</text>
<text x="122.8" y="82.2">1: MOTOR_ENABLE; 2: GND FP28</text>
<text x="21.2" y="89.6">R77 / 10k</text>
<text x="60" y="89.6">Motor command/enable default LOW.</text>
<text x="122.8" y="89.6">1: PWM_L_RAW; 2: GND FP28</text>
<text x="21.2" y="97">R78 / 10k</text>
<text x="60" y="97">Motor command/enable default LOW.</text>
<text x="122.8" y="97">1: PWM_R_RAW; 2: GND FP28</text>
<text x="21.2" y="104.5">R79 / 10k</text>
<text x="60" y="104.5">Motor command/enable default LOW.</text>
<text x="122.8" y="104.5">1: DIR_L_RAW; 2: GND FP28</text>
<text x="21.2" y="111.9">R80 / 10k</text>
<text x="60" y="111.9">Motor command/enable default LOW.</text>
<text x="122.8" y="111.9">1: DIR_R_RAW; 2: GND FP28</text>
<text x="21.2" y="119.3">R81 / 47k</text>
<text x="60" y="119.3">Indicator base-current limiter.</text>
<text x="122.8" y="119.3">1: Net-(Q1-B); 2: BAUM_L FP28</text>
<text x="21.2" y="126.7">R82 / 1k</text>
<text x="60" y="126.7">Indicator LED current limiter.</text>
<text x="122.8" y="126.7">1: +3V3; 2: Net-(D6-A) FP28</text>
<text x="21.2" y="134.1">R83 / 47k</text>
<text x="60" y="134.1">Indicator base-current limiter.</text>
<text x="122.8" y="134.1">1: Net-(Q2-B); 2: BAUM_C FP28</text>
<text x="21.2" y="141.5">R84 / 1k</text>
<text x="60" y="141.5">Indicator LED current limiter.</text>
<text x="122.8" y="141.5">1: +3V3; 2: Net-(D7-A) FP28</text>
<text x="21.2" y="148.9">R85 / 47k</text>
<text x="60" y="148.9">Indicator base-current limiter.</text>
<text x="122.8" y="148.9">1: Net-(Q3-B); 2: BAUM_R FP28</text>
<text x="21.2" y="156.3">R86 / 1k</text>
<text x="60" y="156.3">Indicator LED current limiter.</text>
<text x="122.8" y="156.3">1: +3V3; 2: Net-(D8-A) FP28</text>
<text x="21.2" y="163.7">R87 / 47k</text>
<text x="60" y="163.7">Indicator base-current limiter.</text>
<text x="122.8" y="163.7">1: Net-(Q4-B); 2: BAN_L_BK FP28</text>
<text x="21.2" y="171.1">R88 / 1k</text>
<text x="60" y="171.1">Indicator LED current limiter.</text>
<text x="122.8" y="171.1">1: +3V3; 2: Net-(D9-A) FP28</text>
<text x="21.2" y="178.5">R89 / 47k</text>
<text x="60" y="178.5">Indicator base-current limiter.</text>
<text x="122.8" y="178.5">1: Net-(Q5-B); 2: BAN_L_WH FP28</text>
<text x="21.2" y="185.9">R90 / 1k</text>
<text x="60" y="185.9">Indicator LED current limiter.</text>
<text x="122.8" y="185.9">1: +3V3; 2: Net-(D10-A) FP28</text>
<text x="21.2" y="193.4">R91 / 47k</text>
<text x="60" y="193.4">Indicator base-current limiter.</text>
<text x="122.8" y="193.4">1: Net-(Q6-B); 2: BAN_C_BK FP28</text>
<text x="21.2" y="200.8">R92 / 1k</text>
<text x="60" y="200.8">Indicator LED current limiter.</text>
<text x="122.8" y="200.8">1: +3V3; 2: Net-(D11-A) FP28</text>
<text x="21.2" y="208.2">R93 / 47k</text>
<text x="60" y="208.2">Indicator base-current limiter.</text>
<text x="122.8" y="208.2">1: Net-(Q7-B); 2: BAN_C_WH FP28</text>
<text x="21.2" y="215.6">R94 / 1k</text>
<text x="60" y="215.6">Indicator LED current limiter.</text>
<text x="122.8" y="215.6">1: +3V3; 2: Net-(D12-A) FP28</text>
<text x="21.2" y="223">R95 / 47k</text>
<text x="60" y="223">Indicator base-current limiter.</text>
<text x="122.8" y="223">1: Net-(Q8-B); 2: BAN_R_BK FP28</text>
<text x="21.2" y="230.4">R96 / 1k</text>
<text x="60" y="230.4">Indicator LED current limiter.</text>
<text x="122.8" y="230.4">1: +3V3; 2: Net-(D13-A) FP28</text>
<text x="21.2" y="237.8">R97 / 47k</text>
<text x="60" y="237.8">Indicator base-current limiter.</text>
<text x="122.8" y="237.8">1: Net-(Q9-B); 2: BAN_R_WH FP28</text>
<text x="21.2" y="245.2">R98 / 1k</text>
<text x="60" y="245.2">Indicator LED current limiter.</text>
<text x="122.8" y="245.2">1: +3V3; 2: Net-(D14-A) FP28</text>
<text x="21.2" y="252.6">U40 / SN74LVC2G08DCU</text>
<text x="21.2" y="256.5">R</text>
<text x="60" y="252.6">Dual PWM enable AND gate.</text>
<text x="122.8" y="252.6">See full pin atlas. FP24</text>
</g>
<g font-size="2.8" fill="#133b53">
<text x="16.9" y="287.5">LEVI / REV 1.0 / LEARNING HANDBOOK</text>
<text x="189.9" y="287.5">30</text>
</g>
</g></defs>
<path d="M16.9 282.9h176.2" fill="none" stroke="#087f8c" stroke-width=".21"/>
<path d="M19 18.3h176.1v7.5h-176.1z" fill-rule="evenodd" fill="#133b53"/>
<path d="M19 25.8h176.1v7.4h-176.1z" fill-rule="evenodd" fill="#fff"/>
<path d="M19 33.2h176.1v7.4h-176.1z" fill-rule="evenodd" fill="#edf4f6"/>
<path d="M19 40.6h176.1v7.4h-176.1z" fill-rule="evenodd" fill="#fff"/>
<path d="M19 48h176.1v7.4h-176.1z" fill-rule="evenodd" fill="#edf4f6"/>
<path d="M19 55.4h176.1v7.4h-176.1z" fill-rule="evenodd" fill="#fff"/>
<path d="M19 62.8h176.1v7.4h-176.1z" fill-rule="evenodd" fill="#edf4f6"/>
<path d="M19 70.2h176.1v7.4h-176.1z" fill-rule="evenodd" fill="#fff"/>
<path d="M19 77.6h176.1v7.4h-176.1z" fill-rule="evenodd" fill="#edf4f6"/>
<path d="M19 85h176.1v7.4h-176.1z" fill-rule="evenodd" fill="#fff"/>
<path d="M19 92.4h176.1v7.4h-176.1z" fill-rule="evenodd" fill="#edf4f6"/>
<path d="M19 99.8h176.1v7.4h-176.1z" fill-rule="evenodd" fill="#fff"/>
<path d="M19 107.2h176.1v7.5h-176.1z" fill-rule="evenodd" fill="#edf4f6"/>
<path d="M19 114.7h176.1v7.4h-176.1z" fill-rule="evenodd" fill="#fff"/>
<path d="M19 122.1h176.1v7.4h-176.1z" fill-rule="evenodd" fill="#edf4f6"/>
<path d="M19 129.5h176.1v7.4h-176.1z" fill-rule="evenodd" fill="#fff"/>
<path d="M19 136.9h176.1v7.4h-176.1z" fill-rule="evenodd" fill="#edf4f6"/>
<path d="M19 144.3h176.1v7.4h-176.1z" fill-rule="evenodd" fill="#fff"/>
<path d="M19 151.7h176.1v7.4h-176.1z" fill-rule="evenodd" fill="#edf4f6"/>
<path d="M19 159.1h176.1v7.4h-176.1z" fill-rule="evenodd" fill="#fff"/>
<path d="M19 166.5h176.1v7.4h-176.1z" fill-rule="evenodd" fill="#edf4f6"/>
<path d="M19 173.9h176.1v7.4h-176.1z" fill-rule="evenodd" fill="#fff"/>
<path d="M19 181.3h176.1v7.4h-176.1z" fill-rule="evenodd" fill="#edf4f6"/>
<path d="M19 188.7h176.1v7.4h-176.1z" fill-rule="evenodd" fill="#fff"/>
<path d="M19 196.1h176.1v7.5h-176.1z" fill-rule="evenodd" fill="#edf4f6"/>
<path d="M19 203.6h176.1v7.4h-176.1z" fill-rule="evenodd" fill="#fff"/>
<path d="M19 211h176.1v7.4h-176.1z" fill-rule="evenodd" fill="#edf4f6"/>
<path d="M19 218.4h176.1v7.4h-176.1z" fill-rule="evenodd" fill="#fff"/>
<path d="M19 225.8h176.1v7.4h-176.1z" fill-rule="evenodd" fill="#edf4f6"/>
<path d="M19 233.2h176.1v7.4h-176.1z" fill-rule="evenodd" fill="#fff"/>
<path d="M19 240.6h176.1v7.4h-176.1z" fill-rule="evenodd" fill="#edf4f6"/>
<path d="M19 248h176.1v11.3h-176.1z" fill-rule="evenodd" fill="#fff"/>
<path d="M19 25.8h176.1" fill="none" stroke="#087f8c" stroke-width=".21"/>
<use href="#words"/>
</svg>
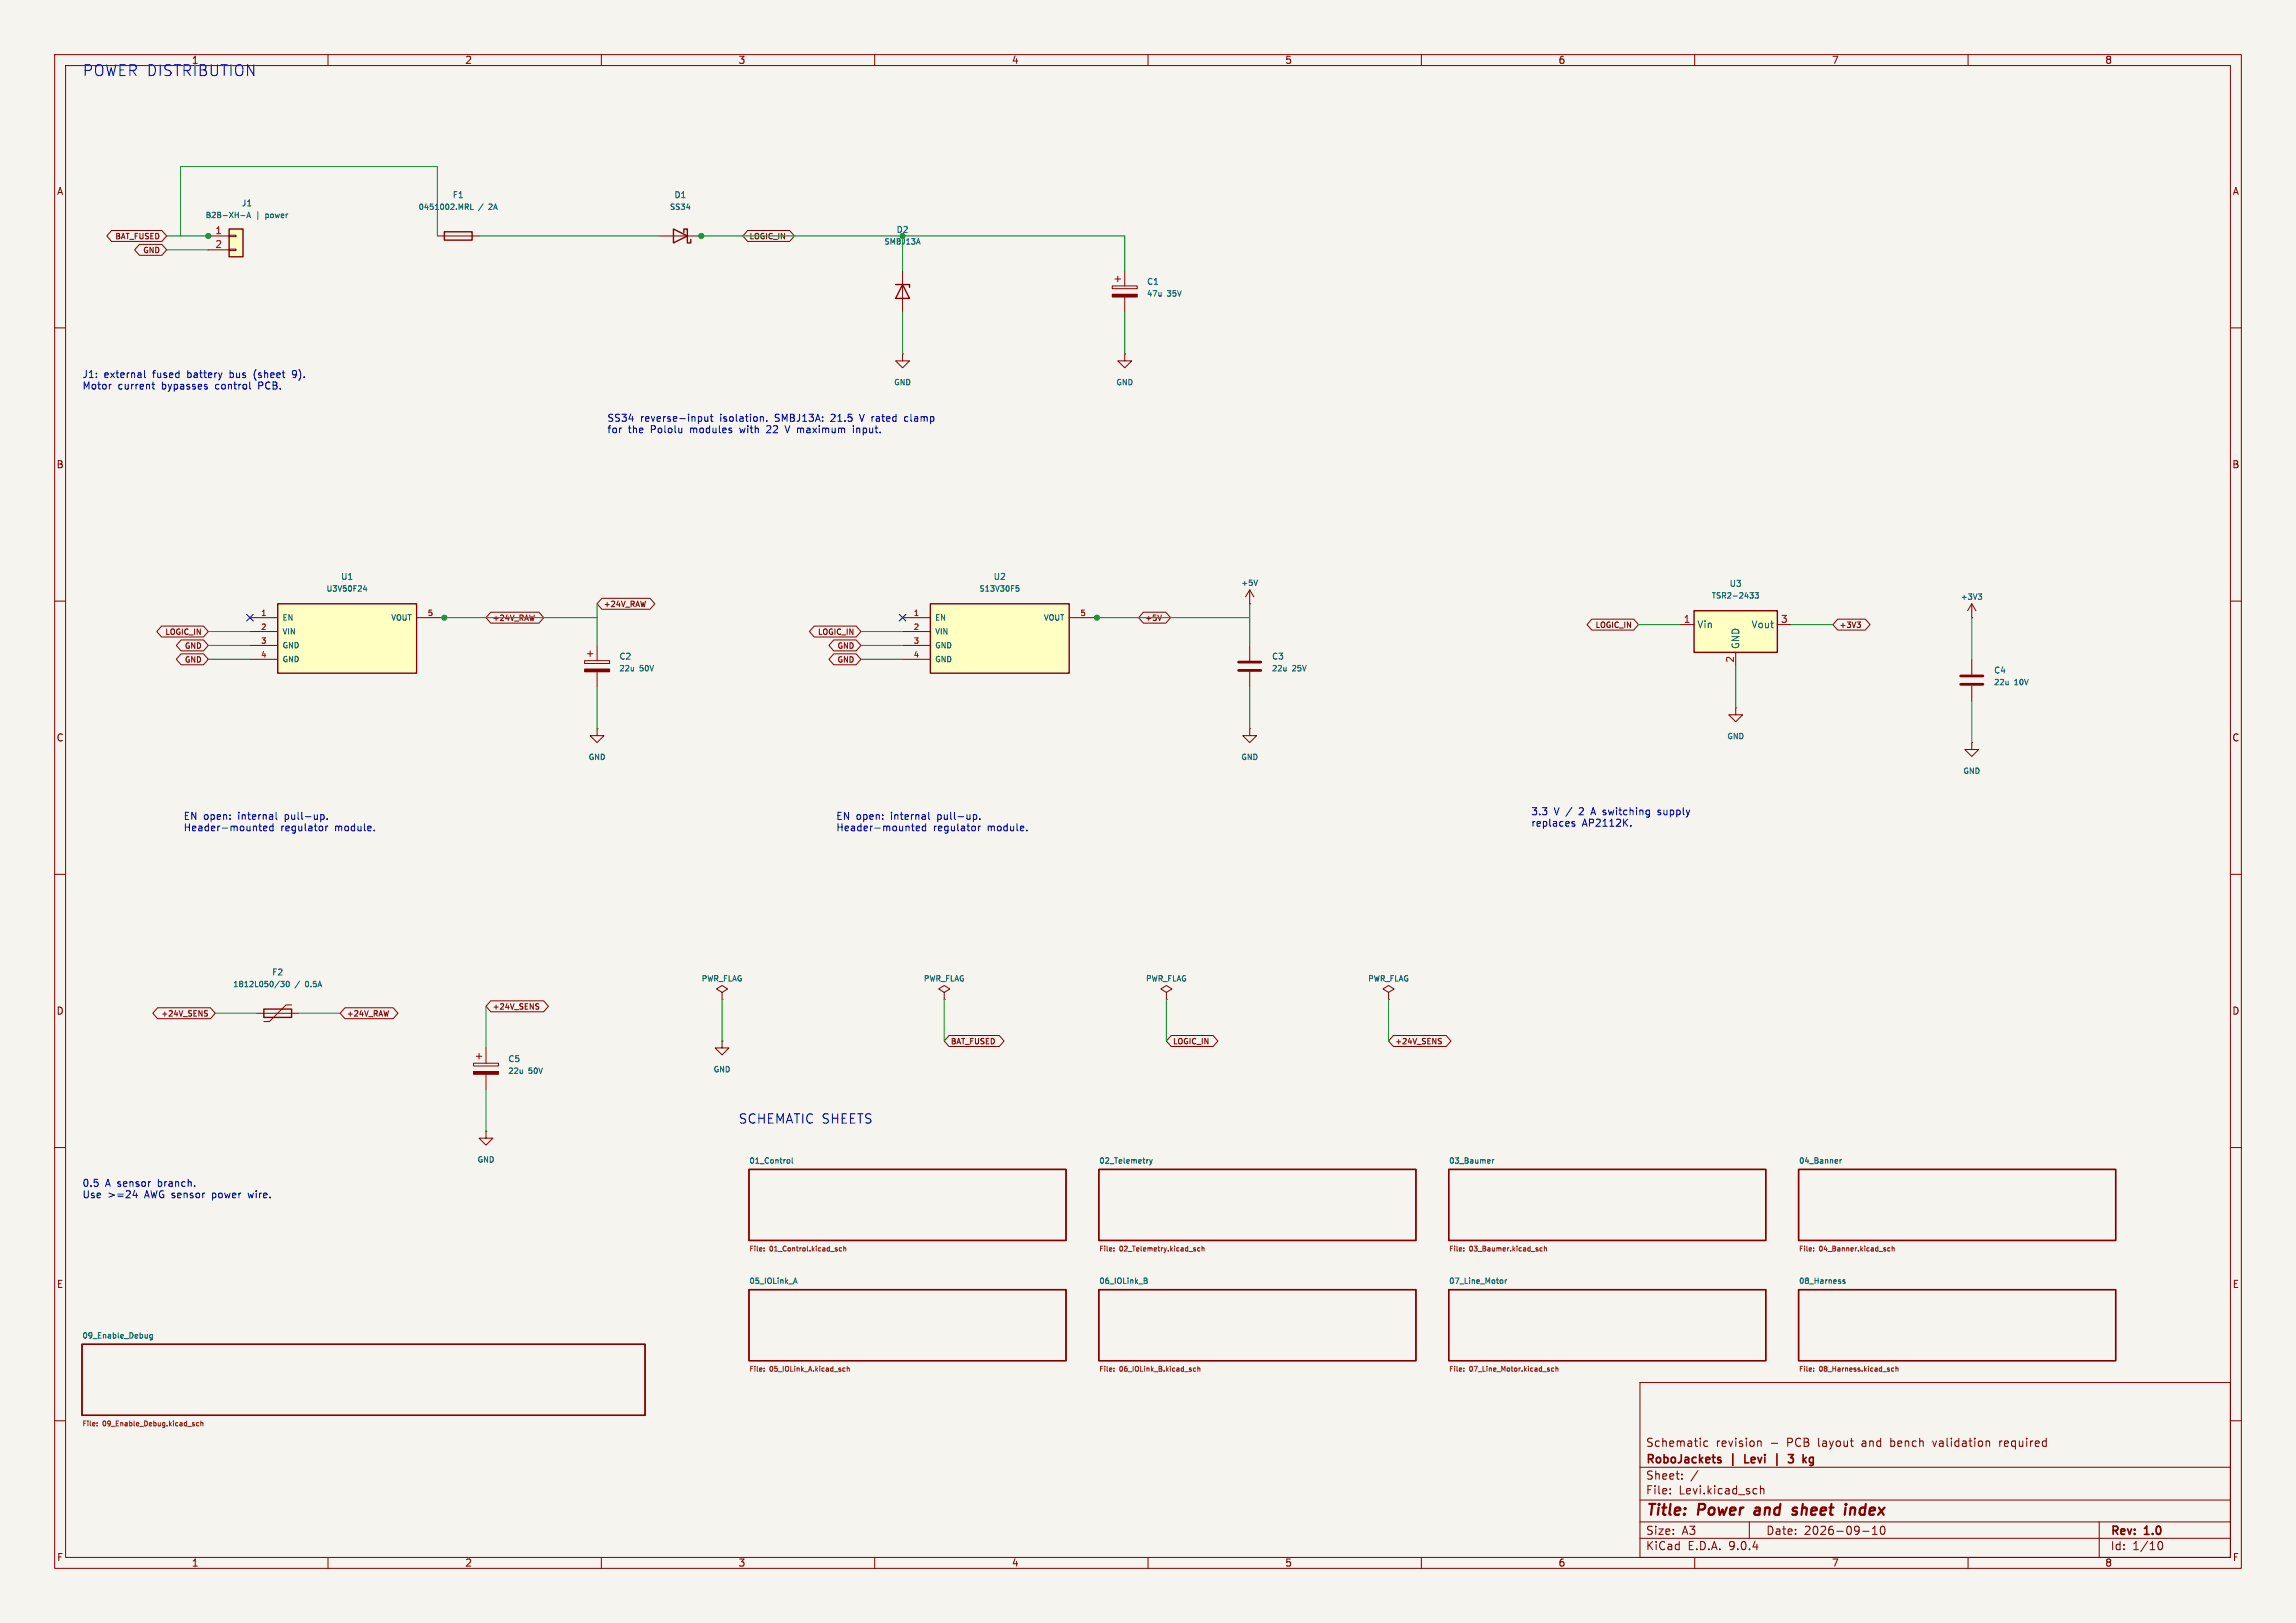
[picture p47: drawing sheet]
(kicad_sch
 (version 20250114)
 (generator "eeschema")
 (generator_version "9.0")
 (paper "A3")
 (title_block
  (title "Power and sheet index")
  (date "2026-09-10")
  (rev "1.0")
  (company "RoboJackets | Levi | 3 kg")
  (comment 1 "Schematic revision - PCB layout and bench validation required"))
 (lib_symbols
  (symbol "Connector_Generic:Conn_01x02"
   (pin_names
    (offset 1.016) (hide yes)) (exclude_from_sim no) (in_bom yes) (on_board yes)
   (property "Reference" "J" (at 0 2.54 0) (effects (font (size 1.27 1.27))))
   (property "Value" "Conn_01x02" (at 0 -5.08 0) (effects (font (size 1.27 1.27))))
   (property "Footprint" "" (at 0 0 0) (effects (font (size 1.27 1.27)) (hide yes)))
   (property "Datasheet" "~" (at 0 0 0) (effects (font (size 1.27 1.27)) (hide yes)))
   (property "Description" "Generic connector, single row, 01x02, script generated (kicad-library-utils/schlib/autogen/connector/)" (at 0 0 0) (effects (font (size 1.27 1.27)) (hide yes)))
   (symbol "Conn_01x02_1_1"
    (rectangle (start -1.27 1.27) (end 1.27 -3.81) (stroke (width 0.254) (type default)) (fill (type background)))
    (rectangle (start -1.27 0.127) (end 0 -0.127) (stroke (width 0.1524) (type default)) (fill (type none)))
    (rectangle (start -1.27 -2.413) (end 0 -2.667) (stroke (width 0.1524) (type default)) (fill (type none)))
    (pin passive line (at -5.08 0 0) (length 3.81) (name "Pin_1" (effects (font (size 1.27 1.27)))) (number "1" (effects (font (size 1.27 1.27)))))
    (pin passive line (at -5.08 -2.54 0) (length 3.81) (name "Pin_2" (effects (font (size 1.27 1.27)))) (number "2" (effects (font (size 1.27 1.27))))))
   (embedded_fonts no))
  (symbol "Device:C"
   (pin_numbers (hide yes))
   (pin_names
    (offset 0.254)) (exclude_from_sim no) (in_bom yes) (on_board yes)
   (property "Reference" "C" (at 0.635 2.54 0) (effects (font (size 1.27 1.27)) (justify left)))
   (property "Value" "C" (at 0.635 -2.54 0) (effects (font (size 1.27 1.27)) (justify left)))
   (property "Footprint" "" (at 0.9652 -3.81 0) (effects (font (size 1.27 1.27)) (hide yes)))
   (property "Datasheet" "~" (at 0 0 0) (effects (font (size 1.27 1.27)) (hide yes)))
   (property "Description" "Unpolarized capacitor" (at 0 0 0) (effects (font (size 1.27 1.27)) (hide yes)))
   (symbol "C_0_1"
    (polyline (pts (xy -2.032 0.762) (xy 2.032 0.762)) (stroke (width 0.508) (type default)) (fill (type none)))
    (polyline (pts (xy -2.032 -0.762) (xy 2.032 -0.762)) (stroke (width 0.508) (type default)) (fill (type none))))
   (symbol "C_1_1"
    (pin passive line (at 0 3.81 270) (length 2.794) (name "~" (effects (font (size 1.27 1.27)))) (number "1" (effects (font (size 1.27 1.27)))))
    (pin passive line (at 0 -3.81 90) (length 2.794) (name "~" (effects (font (size 1.27 1.27)))) (number "2" (effects (font (size 1.27 1.27))))))
   (embedded_fonts no))
  (symbol "Device:C_Polarized"
   (pin_numbers (hide yes))
   (pin_names
    (offset 0.254)) (exclude_from_sim no) (in_bom yes) (on_board yes)
   (property "Reference" "C" (at 0.635 2.54 0) (effects (font (size 1.27 1.27)) (justify left)))
   (property "Value" "C_Polarized" (at 0.635 -2.54 0) (effects (font (size 1.27 1.27)) (justify left)))
   (property "Footprint" "" (at 0.9652 -3.81 0) (effects (font (size 1.27 1.27)) (hide yes)))
   (property "Datasheet" "~" (at 0 0 0) (effects (font (size 1.27 1.27)) (hide yes)))
   (property "Description" "Polarized capacitor" (at 0 0 0) (effects (font (size 1.27 1.27)) (hide yes)))
   (symbol "C_Polarized_0_1"
    (rectangle (start -2.286 0.508) (end 2.286 1.016) (stroke (width 0) (type default)) (fill (type none)))
    (polyline (pts (xy -1.778 2.286) (xy -0.762 2.286)) (stroke (width 0) (type default)) (fill (type none)))
    (polyline (pts (xy -1.27 2.794) (xy -1.27 1.778)) (stroke (width 0) (type default)) (fill (type none)))
    (rectangle (start 2.286 -0.508) (end -2.286 -1.016) (stroke (width 0) (type default)) (fill (type outline))))
   (symbol "C_Polarized_1_1"
    (pin passive line (at 0 3.81 270) (length 2.794) (name "~" (effects (font (size 1.27 1.27)))) (number "1" (effects (font (size 1.27 1.27)))))
    (pin passive line (at 0 -3.81 90) (length 2.794) (name "~" (effects (font (size 1.27 1.27)))) (number "2" (effects (font (size 1.27 1.27))))))
   (embedded_fonts no))
  (symbol "Device:D_Schottky"
   (pin_numbers (hide yes))
   (pin_names
    (offset 1.016) (hide yes)) (exclude_from_sim no) (in_bom yes) (on_board yes)
   (property "Reference" "D" (at 0 2.54 0) (effects (font (size 1.27 1.27))))
   (property "Value" "D_Schottky" (at 0 -2.54 0) (effects (font (size 1.27 1.27))))
   (property "Footprint" "" (at 0 0 0) (effects (font (size 1.27 1.27)) (hide yes)))
   (property "Datasheet" "~" (at 0 0 0) (effects (font (size 1.27 1.27)) (hide yes)))
   (property "Description" "Schottky diode" (at 0 0 0) (effects (font (size 1.27 1.27)) (hide yes)))
   (symbol "D_Schottky_0_1"
    (polyline (pts (xy -1.905 0.635) (xy -1.905 1.27) (xy -1.27 1.27) (xy -1.27 -1.27) (xy -0.635 -1.27) (xy -0.635 -0.635)) (stroke (width 0.254) (type default)) (fill (type none)))
    (polyline (pts (xy 1.27 1.27) (xy 1.27 -1.27) (xy -1.27 0) (xy 1.27 1.27)) (stroke (width 0.254) (type default)) (fill (type none)))
    (polyline (pts (xy 1.27 0) (xy -1.27 0)) (stroke (width 0) (type default)) (fill (type none))))
   (symbol "D_Schottky_1_1"
    (pin passive line (at -3.81 0 0) (length 2.54) (name "K" (effects (font (size 1.27 1.27)))) (number "1" (effects (font (size 1.27 1.27)))))
    (pin passive line (at 3.81 0 180) (length 2.54) (name "A" (effects (font (size 1.27 1.27)))) (number "2" (effects (font (size 1.27 1.27))))))
   (embedded_fonts no))
  (symbol "Device:D_Zener"
   (pin_numbers (hide yes))
   (pin_names
    (offset 1.016) (hide yes)) (exclude_from_sim no) (in_bom yes) (on_board yes)
   (property "Reference" "D" (at 0 2.54 0) (effects (font (size 1.27 1.27))))
   (property "Value" "D_Zener" (at 0 -2.54 0) (effects (font (size 1.27 1.27))))
   (property "Footprint" "" (at 0 0 0) (effects (font (size 1.27 1.27)) (hide yes)))
   (property "Datasheet" "~" (at 0 0 0) (effects (font (size 1.27 1.27)) (hide yes)))
   (property "Description" "Zener diode" (at 0 0 0) (effects (font (size 1.27 1.27)) (hide yes)))
   (symbol "D_Zener_0_1"
    (polyline (pts (xy -1.27 -1.27) (xy -1.27 1.27) (xy -0.762 1.27)) (stroke (width 0.254) (type default)) (fill (type none)))
    (polyline (pts (xy 1.27 0) (xy -1.27 0)) (stroke (width 0) (type default)) (fill (type none)))
    (polyline (pts (xy 1.27 -1.27) (xy 1.27 1.27) (xy -1.27 0) (xy 1.27 -1.27)) (stroke (width 0.254) (type default)) (fill (type none))))
   (symbol "D_Zener_1_1"
    (pin passive line (at -3.81 0 0) (length 2.54) (name "K" (effects (font (size 1.27 1.27)))) (number "1" (effects (font (size 1.27 1.27)))))
    (pin passive line (at 3.81 0 180) (length 2.54) (name "A" (effects (font (size 1.27 1.27)))) (number "2" (effects (font (size 1.27 1.27))))))
   (embedded_fonts no))
  (symbol "Device:Fuse"
   (pin_numbers (hide yes))
   (pin_names
    (offset 0)) (exclude_from_sim no) (in_bom yes) (on_board yes)
   (property "Reference" "F" (at 2.032 0 90) (effects (font (size 1.27 1.27))))
   (property "Value" "Fuse" (at -1.905 0 90) (effects (font (size 1.27 1.27))))
   (property "Footprint" "" (at -1.778 0 90) (effects (font (size 1.27 1.27)) (hide yes)))
   (property "Datasheet" "~" (at 0 0 0) (effects (font (size 1.27 1.27)) (hide yes)))
   (property "Description" "Fuse" (at 0 0 0) (effects (font (size 1.27 1.27)) (hide yes)))
   (symbol "Fuse_0_1"
    (rectangle (start -0.762 -2.54) (end 0.762 2.54) (stroke (width 0.254) (type default)) (fill (type none)))
    (polyline (pts (xy 0 2.54) (xy 0 -2.54)) (stroke (width 0) (type default)) (fill (type none))))
   (symbol "Fuse_1_1"
    (pin passive line (at 0 3.81 270) (length 1.27) (name "~" (effects (font (size 1.27 1.27)))) (number "1" (effects (font (size 1.27 1.27)))))
    (pin passive line (at 0 -3.81 90) (length 1.27) (name "~" (effects (font (size 1.27 1.27)))) (number "2" (effects (font (size 1.27 1.27))))))
   (embedded_fonts no))
  (symbol "Device:Polyfuse"
   (pin_numbers (hide yes))
   (pin_names
    (offset 0)) (exclude_from_sim no) (in_bom yes) (on_board yes)
   (property "Reference" "F" (at -2.54 0 90) (effects (font (size 1.27 1.27))))
   (property "Value" "Polyfuse" (at 2.54 0 90) (effects (font (size 1.27 1.27))))
   (property "Footprint" "" (at 1.27 -5.08 0) (effects (font (size 1.27 1.27)) (justify left) (hide yes)))
   (property "Datasheet" "~" (at 0 0 0) (effects (font (size 1.27 1.27)) (hide yes)))
   (property "Description" "Resettable fuse, polymeric positive temperature coefficient" (at 0 0 0) (effects (font (size 1.27 1.27)) (hide yes)))
   (symbol "Polyfuse_0_1"
    (polyline (pts (xy -1.524 2.54) (xy -1.524 1.524) (xy 1.524 -1.524) (xy 1.524 -2.54)) (stroke (width 0) (type default)) (fill (type none)))
    (rectangle (start -0.762 2.54) (end 0.762 -2.54) (stroke (width 0.254) (type default)) (fill (type none)))
    (polyline (pts (xy 0 2.54) (xy 0 -2.54)) (stroke (width 0) (type default)) (fill (type none))))
   (symbol "Polyfuse_1_1"
    (pin passive line (at 0 3.81 270) (length 1.27) (name "~" (effects (font (size 1.27 1.27)))) (number "1" (effects (font (size 1.27 1.27)))))
    (pin passive line (at 0 -3.81 90) (length 1.27) (name "~" (effects (font (size 1.27 1.27)))) (number "2" (effects (font (size 1.27 1.27))))))
   (embedded_fonts no))
  (symbol "Levi:S13V30F5"
   (pin_names
    (offset 0.8)) (in_bom yes) (on_board yes)
   (property "Reference" "U" (at 0 0 0) (effects (font (size 1.1 1.1))))
   (property "Value" "S13V30F5" (at 0 0 0) (effects (font (size 1.1 1.1))))
   (property "Footprint" "Levi:Pololu_S13V_5pin" (at 0 0 0) (effects (font (size 1.1 1.1))))
   (property "Datasheet" "https://www.pololu.com/product/4082" (at 0 0 0) (effects (font (size 1.1 1.1))))
   (property "Description" "Pololu module: EN VIN GND GND VOUT; duplicate same-net header pads." (at 0 0 0) (effects (font (size 1.1 1.1))))
   (symbol "S13V30F5_1_1"
    (rectangle (start -12.7 6.35) (end 12.7 -6.35) (stroke (width 0.254) (type default)) (fill (type background)))
    (pin input line (at -17.78 3.81 0) (length 5.08) (name "EN" (effects (font (size 1 1)))) (number "1" (effects (font (size 1 1)))))
    (pin power_in line (at -17.78 1.27 0) (length 5.08) (name "VIN" (effects (font (size 1 1)))) (number "2" (effects (font (size 1 1)))))
    (pin power_in line (at -17.78 -1.27 0) (length 5.08) (name "GND" (effects (font (size 1 1)))) (number "3" (effects (font (size 1 1)))))
    (pin passive line (at -17.78 -3.81 0) (length 5.08) (name "GND" (effects (font (size 1 1)))) (number "4" (effects (font (size 1 1)))))
    (pin power_out line (at 17.78 3.81 180) (length 5.08) (name "VOUT" (effects (font (size 1 1)))) (number "5" (effects (font (size 1 1)))))))
  (symbol "Levi:U3V50F24"
   (pin_names
    (offset 0.8)) (in_bom yes) (on_board yes)
   (property "Reference" "U" (at 0 0 0) (effects (font (size 1.1 1.1))))
   (property "Value" "U3V50F24" (at 0 0 0) (effects (font (size 1.1 1.1))))
   (property "Footprint" "Levi:Pololu_U3V50" (at 0 0 0) (effects (font (size 1.1 1.1))))
   (property "Datasheet" "https://www.pololu.com/product/2569" (at 0 0 0) (effects (font (size 1.1 1.1))))
   (property "Description" "Pololu module: EN VIN GND GND VOUT; duplicate same-net header pads." (at 0 0 0) (effects (font (size 1.1 1.1))))
   (symbol "U3V50F24_1_1"
    (rectangle (start -12.7 6.35) (end 12.7 -6.35) (stroke (width 0.254) (type default)) (fill (type background)))
    (pin input line (at -17.78 3.81 0) (length 5.08) (name "EN" (effects (font (size 1 1)))) (number "1" (effects (font (size 1 1)))))
    (pin power_in line (at -17.78 1.27 0) (length 5.08) (name "VIN" (effects (font (size 1 1)))) (number "2" (effects (font (size 1 1)))))
    (pin power_in line (at -17.78 -1.27 0) (length 5.08) (name "GND" (effects (font (size 1 1)))) (number "3" (effects (font (size 1 1)))))
    (pin passive line (at -17.78 -3.81 0) (length 5.08) (name "GND" (effects (font (size 1 1)))) (number "4" (effects (font (size 1 1)))))
    (pin power_out line (at 17.78 3.81 180) (length 5.08) (name "VOUT" (effects (font (size 1 1)))) (number "5" (effects (font (size 1 1)))))))
  (symbol "Regulator_Switching:TSR2-2433"
   (property "Reference" "U" (at -7.62 6.35 0) (effects (font (size 1.27 1.27)) (justify left)))
   (property "Value" "TSR2-2433" (at 2.032 6.35 0) (effects (font (size 1.27 1.27))))
   (property "Footprint" "Converter_DCDC:Converter_DCDC_TRACO_TSR2-xxxx_THT" (at 0 -6.096 0) (effects (font (size 1.27 1.27)
    (italic yes)) (hide yes)))
   (property "Datasheet" "https://www.tracopower.com/products/tsr2.pdf" (at 0 -3.81 0) (effects (font (size 1.27 1.27)) (hide yes)))
   (property "Description" "2A step-down regulator, fixed 3.3V output voltage, 4.75-36V input voltage, TO-220 compatible LM78xx replacement, SIP-3" (at 0 0 0) (effects (font (size 1.27 1.27)) (hide yes)))
   (symbol "TSR2-2433_0_1"
    (rectangle (start -7.62 5.08) (end 7.62 -2.54) (stroke (width 0.254) (type default)) (fill (type background))))
   (symbol "TSR2-2433_1_1"
    (pin power_in line (at -10.16 2.54 0) (length 2.54) (name "Vin" (effects (font (size 1.27 1.27)))) (number "1" (effects (font (size 1.27 1.27)))))
    (pin power_in line (at 0 -5.08 90) (length 2.54) (name "GND" (effects (font (size 1.27 1.27)))) (number "2" (effects (font (size 1.27 1.27)))))
    (pin power_out line (at 10.16 2.54 180) (length 2.54) (name "Vout" (effects (font (size 1.27 1.27)))) (number "3" (effects (font (size 1.27 1.27))))))
   (embedded_fonts no))
  (symbol "power:+3V3"
   (power)
   (pin_numbers (hide yes))
   (pin_names
    (offset 0) (hide yes)) (exclude_from_sim no) (in_bom yes) (on_board yes)
   (property "Reference" "#PWR" (at 0 -3.81 0) (effects (font (size 1.27 1.27)) (hide yes)))
   (property "Value" "+3V3" (at 0 3.556 0) (effects (font (size 1.27 1.27))))
   (property "Footprint" "" (at 0 0 0) (effects (font (size 1.27 1.27)) (hide yes)))
   (property "Datasheet" "" (at 0 0 0) (effects (font (size 1.27 1.27)) (hide yes)))
   (property "Description" "Power symbol creates a global label with name \"+3V3\"" (at 0 0 0) (effects (font (size 1.27 1.27)) (hide yes)))
   (symbol "+3V3_0_1"
    (polyline (pts (xy -0.762 1.27) (xy 0 2.54)) (stroke (width 0) (type default)) (fill (type none)))
    (polyline (pts (xy 0 2.54) (xy 0.762 1.27)) (stroke (width 0) (type default)) (fill (type none)))
    (polyline (pts (xy 0 0) (xy 0 2.54)) (stroke (width 0) (type default)) (fill (type none))))
   (symbol "+3V3_1_1"
    (pin power_in line (at 0 0 90) (length 0) (name "~" (effects (font (size 1.27 1.27)))) (number "1" (effects (font (size 1.27 1.27))))))
   (embedded_fonts no))
  (symbol "power:+5V"
   (power)
   (pin_numbers (hide yes))
   (pin_names
    (offset 0) (hide yes)) (exclude_from_sim no) (in_bom yes) (on_board yes)
   (property "Reference" "#PWR" (at 0 -3.81 0) (effects (font (size 1.27 1.27)) (hide yes)))
   (property "Value" "+5V" (at 0 3.556 0) (effects (font (size 1.27 1.27))))
   (property "Footprint" "" (at 0 0 0) (effects (font (size 1.27 1.27)) (hide yes)))
   (property "Datasheet" "" (at 0 0 0) (effects (font (size 1.27 1.27)) (hide yes)))
   (property "Description" "Power symbol creates a global label with name \"+5V\"" (at 0 0 0) (effects (font (size 1.27 1.27)) (hide yes)))
   (symbol "+5V_0_1"
    (polyline (pts (xy -0.762 1.27) (xy 0 2.54)) (stroke (width 0) (type default)) (fill (type none)))
    (polyline (pts (xy 0 2.54) (xy 0.762 1.27)) (stroke (width 0) (type default)) (fill (type none)))
    (polyline (pts (xy 0 0) (xy 0 2.54)) (stroke (width 0) (type default)) (fill (type none))))
   (symbol "+5V_1_1"
    (pin power_in line (at 0 0 90) (length 0) (name "~" (effects (font (size 1.27 1.27)))) (number "1" (effects (font (size 1.27 1.27))))))
   (embedded_fonts no))
  (symbol "power:GND"
   (power)
   (pin_numbers (hide yes))
   (pin_names
    (offset 0) (hide yes)) (exclude_from_sim no) (in_bom yes) (on_board yes)
   (property "Reference" "#PWR" (at 0 -6.35 0) (effects (font (size 1.27 1.27)) (hide yes)))
   (property "Value" "GND" (at 0 -3.81 0) (effects (font (size 1.27 1.27))))
   (property "Footprint" "" (at 0 0 0) (effects (font (size 1.27 1.27)) (hide yes)))
   (property "Datasheet" "" (at 0 0 0) (effects (font (size 1.27 1.27)) (hide yes)))
   (property "Description" "Power symbol creates a global label with name \"GND\" , ground" (at 0 0 0) (effects (font (size 1.27 1.27)) (hide yes)))
   (symbol "GND_0_1"
    (polyline (pts (xy 0 0) (xy 0 -1.27) (xy 1.27 -1.27) (xy 0 -2.54) (xy -1.27 -1.27) (xy 0 -1.27)) (stroke (width 0) (type default)) (fill (type none))))
   (symbol "GND_1_1"
    (pin power_in line (at 0 0 270) (length 0) (name "~" (effects (font (size 1.27 1.27)))) (number "1" (effects (font (size 1.27 1.27))))))
   (embedded_fonts no))
  (symbol "power:PWR_FLAG"
   (power)
   (pin_numbers (hide yes))
   (pin_names
    (offset 0) (hide yes)) (exclude_from_sim no) (in_bom yes) (on_board yes)
   (property "Reference" "#FLG" (at 0 1.905 0) (effects (font (size 1.27 1.27)) (hide yes)))
   (property "Value" "PWR_FLAG" (at 0 3.81 0) (effects (font (size 1.27 1.27))))
   (property "Footprint" "" (at 0 0 0) (effects (font (size 1.27 1.27)) (hide yes)))
   (property "Datasheet" "~" (at 0 0 0) (effects (font (size 1.27 1.27)) (hide yes)))
   (property "Description" "Special symbol for telling ERC where power comes from" (at 0 0 0) (effects (font (size 1.27 1.27)) (hide yes)))
   (symbol "PWR_FLAG_0_0"
    (pin power_out line (at 0 0 90) (length 0) (name "~" (effects (font (size 1.27 1.27)))) (number "1" (effects (font (size 1.27 1.27))))))
   (symbol "PWR_FLAG_0_1"
    (polyline (pts (xy 0 0) (xy 0 1.27) (xy -1.016 1.905) (xy 0 2.54) (xy 1.016 1.905) (xy 0 1.27)) (stroke (width 0) (type default)) (fill (type none))))
   (embedded_fonts no)))
 (text "POWER DISTRIBUTION"
  (at 15 12 0)
  (effects (font (size 2 2)) (justify left top)))
 (global_label "GND"
  (shape bidirectional)
  (at 30.48 45.72 180)
  (effects (font (size 1 1)) (justify right))
  (property "Intersheetrefs" "${INTERSHEET_REFS}" (at 30.48 45.72 0) (effects (font (size 1 1)) (hide yes))))
 (global_label "BAT_FUSED"
  (shape bidirectional)
  (at 30.48 43.18 180)
  (effects (font (size 1 1)) (justify right))
  (property "Intersheetrefs" "${INTERSHEET_REFS}" (at 30.48 43.18 0) (effects (font (size 1 1)) (hide yes))))
 (junction
  (at 38.1 43.18)
  (diameter 0)
  (color 0 0 0 0))
 (global_label "LOGIC_IN"
  (shape bidirectional)
  (at 135.89 43.18 0)
  (effects (font (size 1 1)) (justify left))
  (property "Intersheetrefs" "${INTERSHEET_REFS}" (at 135.89 43.18 0) (effects (font (size 1 1)) (hide yes))))
 (junction
  (at 128.27 43.18)
  (diameter 0)
  (color 0 0 0 0))
 (junction
  (at 165.1 43.18)
  (diameter 0)
  (color 0 0 0 0))
 (text "J1: external fused battery bus (sheet 9).\nMotor current bypasses control PCB."
  (at 15 68 0)
  (effects (font (size 1.3 1.3)) (justify left top)))
 (text "SS34 reverse-input isolation. SMBJ13A: 21.5 V rated clamp\nfor the Pololu modules with 22 V maximum input."
  (at 111 76 0)
  (effects (font (size 1.3 1.3)) (justify left top)))
 (no_connect
  (at 45.72 113.03))
 (global_label "LOGIC_IN"
  (shape bidirectional)
  (at 38.1 115.57 180)
  (effects (font (size 1 1)) (justify right))
  (property "Intersheetrefs" "${INTERSHEET_REFS}" (at 38.1 115.57 0) (effects (font (size 1 1)) (hide yes))))
 (global_label "GND"
  (shape bidirectional)
  (at 38.1 118.11 180)
  (effects (font (size 1 1)) (justify right))
  (property "Intersheetrefs" "${INTERSHEET_REFS}" (at 38.1 118.11 0) (effects (font (size 1 1)) (hide yes))))
 (global_label "GND"
  (shape bidirectional)
  (at 38.1 120.65 180)
  (effects (font (size 1 1)) (justify right))
  (property "Intersheetrefs" "${INTERSHEET_REFS}" (at 38.1 120.65 0) (effects (font (size 1 1)) (hide yes))))
 (global_label "+24V_RAW"
  (shape bidirectional)
  (at 88.9 113.03 0)
  (effects (font (size 1 1)) (justify left))
  (property "Intersheetrefs" "${INTERSHEET_REFS}" (at 88.9 113.03 0) (effects (font (size 1 1)) (hide yes))))
 (global_label "+24V_RAW"
  (shape bidirectional)
  (at 109.22 110.49 0)
  (effects (font (size 1 1)) (justify left))
  (property "Intersheetrefs" "${INTERSHEET_REFS}" (at 109.22 110.49 0) (effects (font (size 1 1)) (hide yes))))
 (junction
  (at 81.28 113.03)
  (diameter 0)
  (color 0 0 0 0))
 (text "EN open: internal pull-up.\nHeader-mounted regulator module."
  (at 33.5 148.84 0)
  (effects (font (size 1.3 1.3)) (justify left top)))
 (no_connect
  (at 165.1 113.03))
 (global_label "LOGIC_IN"
  (shape bidirectional)
  (at 157.48 115.57 180)
  (effects (font (size 1 1)) (justify right))
  (property "Intersheetrefs" "${INTERSHEET_REFS}" (at 157.48 115.57 0) (effects (font (size 1 1)) (hide yes))))
 (global_label "GND"
  (shape bidirectional)
  (at 157.48 118.11 180)
  (effects (font (size 1 1)) (justify right))
  (property "Intersheetrefs" "${INTERSHEET_REFS}" (at 157.48 118.11 0) (effects (font (size 1 1)) (hide yes))))
 (global_label "GND"
  (shape bidirectional)
  (at 157.48 120.65 180)
  (effects (font (size 1 1)) (justify right))
  (property "Intersheetrefs" "${INTERSHEET_REFS}" (at 157.48 120.65 0) (effects (font (size 1 1)) (hide yes))))
 (global_label "+5V"
  (shape bidirectional)
  (at 208.28 113.03 0)
  (effects (font (size 1 1)) (justify left))
  (property "Intersheetrefs" "${INTERSHEET_REFS}" (at 208.28 113.03 0) (effects (font (size 1 1)) (hide yes))))
 (junction
  (at 200.66 113.03)
  (diameter 0)
  (color 0 0 0 0))
 (text "EN open: internal pull-up.\nHeader-mounted regulator module."
  (at 152.88 148.84 0)
  (effects (font (size 1.3 1.3)) (justify left top)))
 (global_label "LOGIC_IN"
  (shape bidirectional)
  (at 299.72 114.3 180)
  (effects (font (size 1 1)) (justify right))
  (property "Intersheetrefs" "${INTERSHEET_REFS}" (at 299.72 114.3 0) (effects (font (size 1 1)) (hide yes))))
 (global_label "+3V3"
  (shape bidirectional)
  (at 335.28 114.3 0)
  (effects (font (size 1 1)) (justify left))
  (property "Intersheetrefs" "${INTERSHEET_REFS}" (at 335.28 114.3 0) (effects (font (size 1 1)) (hide yes))))
 (text "3.3 V / 2 A switching supply\nreplaces AP2112K."
  (at 280 148 0)
  (effects (font (size 1.3 1.3)) (justify left top)))
 (global_label "+24V_RAW"
  (shape bidirectional)
  (at 62.23 185.42 0)
  (effects (font (size 1 1)) (justify left))
  (property "Intersheetrefs" "${INTERSHEET_REFS}" (at 62.23 185.42 0) (effects (font (size 1 1)) (hide yes))))
 (global_label "+24V_SENS"
  (shape bidirectional)
  (at 39.37 185.42 180)
  (effects (font (size 1 1)) (justify right))
  (property "Intersheetrefs" "${INTERSHEET_REFS}" (at 39.37 185.42 0) (effects (font (size 1 1)) (hide yes))))
 (global_label "+24V_SENS"
  (shape bidirectional)
  (at 88.9 184.15 0)
  (effects (font (size 1 1)) (justify left))
  (property "Intersheetrefs" "${INTERSHEET_REFS}" (at 88.9 184.15 0) (effects (font (size 1 1)) (hide yes))))
 (text "0.5 A sensor branch.\nUse >=24 AWG sensor power wire."
  (at 15 216 0)
  (effects (font (size 1.3 1.3)) (justify left top)))
 (global_label "BAT_FUSED"
  (shape bidirectional)
  (at 172.72 190.5 0)
  (effects (font (size 1 1)) (justify left))
  (property "Intersheetrefs" "${INTERSHEET_REFS}" (at 172.72 190.5 0) (effects (font (size 1 1)) (hide yes))))
 (global_label "LOGIC_IN"
  (shape bidirectional)
  (at 213.36 190.5 0)
  (effects (font (size 1 1)) (justify left))
  (property "Intersheetrefs" "${INTERSHEET_REFS}" (at 213.36 190.5 0) (effects (font (size 1 1)) (hide yes))))
 (global_label "+24V_SENS"
  (shape bidirectional)
  (at 254 190.5 0)
  (effects (font (size 1 1)) (justify left))
  (property "Intersheetrefs" "${INTERSHEET_REFS}" (at 254 190.5 0) (effects (font (size 1 1)) (hide yes))))
 (text "SCHEMATIC SHEETS"
  (at 135 204 0)
  (effects (font (size 1.7 1.7)) (justify left top)))
 (sheet
  (at 137 214)
  (size 58 13)
  (stroke (width 0.254) (type default))
  (fill (color 0 0 0 0))
  (property "Sheetname" "01_Control" (at 137 213 0) (effects (font (size 1 1)) (justify left bottom)))
  (property "Sheetfile" "01_Control.kicad_sch" (at 137 228 0) (effects (font (size 0.9 0.9)) (justify left top))))
 (sheet
  (at 201 214)
  (size 58 13)
  (stroke (width 0.254) (type default))
  (fill (color 0 0 0 0))
  (property "Sheetname" "02_Telemetry" (at 201 213 0) (effects (font (size 1 1)) (justify left bottom)))
  (property "Sheetfile" "02_Telemetry.kicad_sch" (at 201 228 0) (effects (font (size 0.9 0.9)) (justify left top))))
 (sheet
  (at 265 214)
  (size 58 13)
  (stroke (width 0.254) (type default))
  (fill (color 0 0 0 0))
  (property "Sheetname" "03_Baumer" (at 265 213 0) (effects (font (size 1 1)) (justify left bottom)))
  (property "Sheetfile" "03_Baumer.kicad_sch" (at 265 228 0) (effects (font (size 0.9 0.9)) (justify left top))))
 (sheet
  (at 329 214)
  (size 58 13)
  (stroke (width 0.254) (type default))
  (fill (color 0 0 0 0))
  (property "Sheetname" "04_Banner" (at 329 213 0) (effects (font (size 1 1)) (justify left bottom)))
  (property "Sheetfile" "04_Banner.kicad_sch" (at 329 228 0) (effects (font (size 0.9 0.9)) (justify left top))))
 (sheet
  (at 137 236)
  (size 58 13)
  (stroke (width 0.254) (type default))
  (fill (color 0 0 0 0))
  (property "Sheetname" "05_IOLink_A" (at 137 235 0) (effects (font (size 1 1)) (justify left bottom)))
  (property "Sheetfile" "05_IOLink_A.kicad_sch" (at 137 250 0) (effects (font (size 0.9 0.9)) (justify left top))))
 (sheet
  (at 201 236)
  (size 58 13)
  (stroke (width 0.254) (type default))
  (fill (color 0 0 0 0))
  (property "Sheetname" "06_IOLink_B" (at 201 235 0) (effects (font (size 1 1)) (justify left bottom)))
  (property "Sheetfile" "06_IOLink_B.kicad_sch" (at 201 250 0) (effects (font (size 0.9 0.9)) (justify left top))))
 (sheet
  (at 265 236)
  (size 58 13)
  (stroke (width 0.254) (type default))
  (fill (color 0 0 0 0))
  (property "Sheetname" "07_Line_Motor" (at 265 235 0) (effects (font (size 1 1)) (justify left bottom)))
  (property "Sheetfile" "07_Line_Motor.kicad_sch" (at 265 250 0) (effects (font (size 0.9 0.9)) (justify left top))))
 (sheet
  (at 329 236)
  (size 58 13)
  (stroke (width 0.254) (type default))
  (fill (color 0 0 0 0))
  (property "Sheetname" "08_Harness" (at 329 235 0) (effects (font (size 1 1)) (justify left bottom)))
  (property "Sheetfile" "08_Harness.kicad_sch" (at 329 250 0) (effects (font (size 0.9 0.9)) (justify left top))))
 (sheet
  (at 15 246)
  (size 103 13)
  (stroke (width 0.254) (type default))
  (fill (color 0 0 0 0))
  (property "Sheetname" "09_Enable_Debug" (at 15 245 0) (effects (font (size 1 1)) (justify left bottom)))
  (property "Sheetfile" "09_Enable_Debug.kicad_sch" (at 15 260 0) (effects (font (size 0.9 0.9)) (justify left top))))
 (wire
  (pts (xy 38.1 45.72) (xy 30.48 45.72))
  (stroke (width 0) (type default)))
 (wire
  (pts (xy 38.1 43.18) (xy 33.02 43.18))
  (stroke (width 0) (type default)))
 (wire
  (pts (xy 33.02 43.18) (xy 30.48 43.18))
  (stroke (width 0) (type default)))
 (wire
  (pts (xy 33.02 43.18) (xy 33.02 30.48))
  (stroke (width 0) (type default)))
 (wire
  (pts (xy 33.02 30.48) (xy 80.01 30.48))
  (stroke (width 0) (type default)))
 (wire
  (pts (xy 80.01 30.48) (xy 80.01 43.18))
  (stroke (width 0) (type default)))
 (wire
  (pts (xy 87.63 43.18) (xy 120.65 43.18))
  (stroke (width 0) (type default)))
 (wire
  (pts (xy 128.27 43.18) (xy 135.89 43.18))
  (stroke (width 0) (type default)))
 (wire
  (pts (xy 165.1 57.15) (xy 165.1 64.77))
  (stroke (width 0) (type default)))
 (wire
  (pts (xy 135.89 43.18) (xy 165.1 43.18))
  (stroke (width 0) (type default)))
 (wire
  (pts (xy 165.1 43.18) (xy 165.1 49.53))
  (stroke (width 0) (type default)))
 (wire
  (pts (xy 205.74 57.15) (xy 205.74 64.77))
  (stroke (width 0) (type default)))
 (wire
  (pts (xy 165.1 43.18) (xy 205.74 43.18))
  (stroke (width 0) (type default)))
 (wire
  (pts (xy 205.74 43.18) (xy 205.74 49.53))
  (stroke (width 0) (type default)))
 (wire
  (pts (xy 45.72 115.57) (xy 38.1 115.57))
  (stroke (width 0) (type default)))
 (wire
  (pts (xy 45.72 118.11) (xy 38.1 118.11))
  (stroke (width 0) (type default)))
 (wire
  (pts (xy 45.72 120.65) (xy 38.1 120.65))
  (stroke (width 0) (type default)))
 (wire
  (pts (xy 81.28 113.03) (xy 88.9 113.03))
  (stroke (width 0) (type default)))
 (wire
  (pts (xy 109.22 118.11) (xy 109.22 113.03))
  (stroke (width 0) (type default)))
 (wire
  (pts (xy 109.22 113.03) (xy 109.22 110.49))
  (stroke (width 0) (type default)))
 (wire
  (pts (xy 109.22 125.73) (xy 109.22 133.35))
  (stroke (width 0) (type default)))
 (wire
  (pts (xy 88.9 113.03) (xy 109.22 113.03))
  (stroke (width 0) (type default)))
 (wire
  (pts (xy 165.1 115.57) (xy 157.48 115.57))
  (stroke (width 0) (type default)))
 (wire
  (pts (xy 165.1 118.11) (xy 157.48 118.11))
  (stroke (width 0) (type default)))
 (wire
  (pts (xy 165.1 120.65) (xy 157.48 120.65))
  (stroke (width 0) (type default)))
 (wire
  (pts (xy 200.66 113.03) (xy 208.28 113.03))
  (stroke (width 0) (type default)))
 (wire
  (pts (xy 228.6 118.11) (xy 228.6 113.03))
  (stroke (width 0) (type default)))
 (wire
  (pts (xy 228.6 113.03) (xy 228.6 110.49))
  (stroke (width 0) (type default)))
 (wire
  (pts (xy 228.6 125.73) (xy 228.6 133.35))
  (stroke (width 0) (type default)))
 (wire
  (pts (xy 208.28 113.03) (xy 228.6 113.03))
  (stroke (width 0) (type default)))
 (wire
  (pts (xy 307.34 114.3) (xy 299.72 114.3))
  (stroke (width 0) (type default)))
 (wire
  (pts (xy 317.5 121.92) (xy 317.5 129.54))
  (stroke (width 0) (type default)))
 (wire
  (pts (xy 327.66 114.3) (xy 335.28 114.3))
  (stroke (width 0) (type default)))
 (wire
  (pts (xy 360.68 120.65) (xy 360.68 113.03))
  (stroke (width 0) (type default)))
 (wire
  (pts (xy 360.68 128.27) (xy 360.68 135.89))
  (stroke (width 0) (type default)))
 (wire
  (pts (xy 54.61 185.42) (xy 62.23 185.42))
  (stroke (width 0) (type default)))
 (wire
  (pts (xy 46.99 185.42) (xy 39.37 185.42))
  (stroke (width 0) (type default)))
 (wire
  (pts (xy 88.9 191.77) (xy 88.9 184.15))
  (stroke (width 0) (type default)))
 (wire
  (pts (xy 88.9 199.39) (xy 88.9 207.01))
  (stroke (width 0) (type default)))
 (wire
  (pts (xy 132.08 182.88) (xy 132.08 190.5))
  (stroke (width 0) (type default)))
 (wire
  (pts (xy 172.72 182.88) (xy 172.72 190.5))
  (stroke (width 0) (type default)))
 (wire
  (pts (xy 213.36 182.88) (xy 213.36 190.5))
  (stroke (width 0) (type default)))
 (wire
  (pts (xy 254 182.88) (xy 254 190.5))
  (stroke (width 0) (type default)))
 (symbol
  (lib_id "Connector_Generic:Conn_01x02")
  (at 43.18 43.18 0)
  (unit 1)
  (exclude_from_sim no)
  (in_bom yes)
  (on_board yes)
  (dnp no)
  (property "Reference" "J1" (at 45.18 37.18 0) (effects (font (size 1.1 1.1))))
  (property "Value" "B2B-XH-A | power" (at 45.18 39.38 0) (effects (font (size 1 1))))
  (property "Footprint" "Connector_JST:JST_XH_B2B-XH-A_1x02_P2.50mm_Vertical" (at 43.18 43.18 0) (effects (font (size 1.1 1.1)) (hide yes)))
  (property "Datasheet" "~" (at 43.18 43.18 0) (effects (font (size 1.1 1.1)) (hide yes)))
  (pin "1")
  (pin "2"))
 (symbol
  (lib_id "Device:Fuse")
  (at 83.82 43.18 270)
  (unit 1)
  (exclude_from_sim no)
  (in_bom yes)
  (on_board yes)
  (dnp no)
  (property "Reference" "F1" (at 83.82 35.68 90) (effects (font (size 1.1 1.1))))
  (property "Value" "0451002.MRL / 2A" (at 83.82 37.88 90) (effects (font (size 1 1))))
  (property "Footprint" "Fuse:Fuse_Littelfuse-NANO2-451_453" (at 83.82 43.18 90) (effects (font (size 1.1 1.1)) (hide yes)))
  (property "Datasheet" "~" (at 83.82 43.18 90) (effects (font (size 1.1 1.1)) (hide yes)))
  (pin "1")
  (pin "2"))
 (symbol
  (lib_id "Device:D_Schottky")
  (at 124.46 43.18 180)
  (unit 1)
  (exclude_from_sim no)
  (in_bom yes)
  (on_board yes)
  (dnp no)
  (property "Reference" "D1" (at 124.46 35.68 0) (effects (font (size 1.1 1.1))))
  (property "Value" "SS34" (at 124.46 37.88 0) (effects (font (size 1 1))))
  (property "Footprint" "Diode_SMD:D_SMA" (at 124.46 43.18 0) (effects (font (size 1.1 1.1)) (hide yes)))
  (property "Datasheet" "~" (at 124.46 43.18 0) (effects (font (size 1.1 1.1)) (hide yes)))
  (pin "1")
  (pin "2"))
 (symbol
  (lib_id "Device:D_Zener")
  (at 165.1 53.34 270)
  (unit 1)
  (exclude_from_sim no)
  (in_bom yes)
  (on_board yes)
  (dnp no)
  (property "Reference" "D2" (at 165.1 42.03 90) (effects (font (size 1.1 1.1))))
  (property "Value" "SMBJ13A" (at 165.1 44.23 90) (effects (font (size 1 1))))
  (property "Footprint" "Diode_SMD:D_SMB" (at 165.1 53.34 90) (effects (font (size 1.1 1.1)) (hide yes)))
  (property "Datasheet" "~" (at 165.1 53.34 90) (effects (font (size 1.1 1.1)) (hide yes)))
  (pin "1")
  (pin "2"))
 (symbol
  (lib_id "power:GND")
  (at 165.1 64.77 0)
  (unit 1)
  (exclude_from_sim no)
  (in_bom no)
  (on_board no)
  (dnp no)
  (property "Reference" "#PWR1" (at 165.1 67.77 0) (effects (font (size 1.1 1.1)) (hide yes)))
  (property "Value" "GND" (at 165.1 69.97 0) (effects (font (size 1 1))))
  (property "Footprint" "" (at 165.1 64.77 0) (effects (font (size 1.1 1.1)) (hide yes)))
  (property "Datasheet" "" (at 165.1 64.77 0) (effects (font (size 1.1 1.1)) (hide yes)))
  (pin "1"))
 (symbol
  (lib_id "Device:C_Polarized")
  (at 205.74 53.34 0)
  (unit 1)
  (exclude_from_sim no)
  (in_bom yes)
  (on_board yes)
  (dnp no)
  (property "Reference" "C1" (at 209.74 51.54 0) (effects (font (size 1.1 1.1)) (justify left)))
  (property "Value" "47u 35V" (at 209.74 53.74 0) (effects (font (size 1 1)) (justify left)))
  (property "Footprint" "Capacitor_THT:CP_Radial_D6.3mm_P2.50mm" (at 205.74 53.34 0) (effects (font (size 1.1 1.1)) (hide yes) (justify left)))
  (property "Datasheet" "~" (at 205.74 53.34 0) (effects (font (size 1.1 1.1)) (hide yes) (justify left)))
  (pin "1")
  (pin "2"))
 (symbol
  (lib_id "power:GND")
  (at 205.74 64.77 0)
  (unit 1)
  (exclude_from_sim no)
  (in_bom no)
  (on_board no)
  (dnp no)
  (property "Reference" "#PWR2" (at 205.74 67.77 0) (effects (font (size 1.1 1.1)) (hide yes)))
  (property "Value" "GND" (at 205.74 69.97 0) (effects (font (size 1 1))))
  (property "Footprint" "" (at 205.74 64.77 0) (effects (font (size 1.1 1.1)) (hide yes)))
  (property "Datasheet" "" (at 205.74 64.77 0) (effects (font (size 1.1 1.1)) (hide yes)))
  (pin "1"))
 (symbol
  (lib_id "Levi:U3V50F24")
  (at 63.5 116.84 0)
  (unit 1)
  (exclude_from_sim no)
  (in_bom yes)
  (on_board yes)
  (dnp no)
  (property "Reference" "U1" (at 63.5 105.53 0) (effects (font (size 1.1 1.1))))
  (property "Value" "U3V50F24" (at 63.5 107.73 0) (effects (font (size 1 1))))
  (property "Footprint" "Levi:Pololu_U3V50" (at 63.5 116.84 0) (effects (font (size 1.1 1.1)) (hide yes)))
  (property "Datasheet" "https://www.pololu.com/product/2569" (at 63.5 116.84 0) (effects (font (size 1.1 1.1)) (hide yes)))
  (pin "1")
  (pin "2")
  (pin "3")
  (pin "4")
  (pin "5"))
 (symbol
  (lib_id "Device:C_Polarized")
  (at 109.22 121.92 0)
  (unit 1)
  (exclude_from_sim no)
  (in_bom yes)
  (on_board yes)
  (dnp no)
  (property "Reference" "C2" (at 113.22 120.12 0) (effects (font (size 1.1 1.1)) (justify left)))
  (property "Value" "22u 50V" (at 113.22 122.32 0) (effects (font (size 1 1)) (justify left)))
  (property "Footprint" "Capacitor_THT:CP_Radial_D8.0mm_P3.50mm" (at 109.22 121.92 0) (effects (font (size 1.1 1.1)) (hide yes) (justify left)))
  (property "Datasheet" "~" (at 109.22 121.92 0) (effects (font (size 1.1 1.1)) (hide yes) (justify left)))
  (pin "1")
  (pin "2"))
 (symbol
  (lib_id "power:GND")
  (at 109.22 133.35 0)
  (unit 1)
  (exclude_from_sim no)
  (in_bom no)
  (on_board no)
  (dnp no)
  (property "Reference" "#PWR3" (at 109.22 136.35 0) (effects (font (size 1.1 1.1)) (hide yes)))
  (property "Value" "GND" (at 109.22 138.55 0) (effects (font (size 1 1))))
  (property "Footprint" "" (at 109.22 133.35 0) (effects (font (size 1.1 1.1)) (hide yes)))
  (property "Datasheet" "" (at 109.22 133.35 0) (effects (font (size 1.1 1.1)) (hide yes)))
  (pin "1"))
 (symbol
  (lib_id "Levi:S13V30F5")
  (at 182.88 116.84 0)
  (unit 1)
  (exclude_from_sim no)
  (in_bom yes)
  (on_board yes)
  (dnp no)
  (property "Reference" "U2" (at 182.88 105.53 0) (effects (font (size 1.1 1.1))))
  (property "Value" "S13V30F5" (at 182.88 107.73 0) (effects (font (size 1 1))))
  (property "Footprint" "Levi:Pololu_S13V_5pin" (at 182.88 116.84 0) (effects (font (size 1.1 1.1)) (hide yes)))
  (property "Datasheet" "https://www.pololu.com/product/4082" (at 182.88 116.84 0) (effects (font (size 1.1 1.1)) (hide yes)))
  (pin "1")
  (pin "2")
  (pin "3")
  (pin "4")
  (pin "5"))
 (symbol
  (lib_id "Device:C")
  (at 228.6 121.92 0)
  (unit 1)
  (exclude_from_sim no)
  (in_bom yes)
  (on_board yes)
  (dnp no)
  (property "Reference" "C3" (at 232.6 120.12 0) (effects (font (size 1.1 1.1)) (justify left)))
  (property "Value" "22u 25V" (at 232.6 122.32 0) (effects (font (size 1 1)) (justify left)))
  (property "Footprint" "Capacitor_SMD:C_0805_2012Metric" (at 228.6 121.92 0) (effects (font (size 1.1 1.1)) (hide yes) (justify left)))
  (property "Datasheet" "~" (at 228.6 121.92 0) (effects (font (size 1.1 1.1)) (hide yes) (justify left)))
  (pin "1")
  (pin "2"))
 (symbol
  (lib_id "power:+5V")
  (at 228.6 110.49 0)
  (unit 1)
  (exclude_from_sim no)
  (in_bom no)
  (on_board no)
  (dnp no)
  (property "Reference" "#PWR4" (at 228.6 104.49 0) (effects (font (size 1.1 1.1)) (hide yes)))
  (property "Value" "+5V" (at 228.6 106.69 0) (effects (font (size 1 1))))
  (property "Footprint" "" (at 228.6 110.49 0) (effects (font (size 1.1 1.1)) (hide yes)))
  (property "Datasheet" "" (at 228.6 110.49 0) (effects (font (size 1.1 1.1)) (hide yes)))
  (pin "1"))
 (symbol
  (lib_id "power:GND")
  (at 228.6 133.35 0)
  (unit 1)
  (exclude_from_sim no)
  (in_bom no)
  (on_board no)
  (dnp no)
  (property "Reference" "#PWR5" (at 228.6 136.35 0) (effects (font (size 1.1 1.1)) (hide yes)))
  (property "Value" "GND" (at 228.6 138.55 0) (effects (font (size 1 1))))
  (property "Footprint" "" (at 228.6 133.35 0) (effects (font (size 1.1 1.1)) (hide yes)))
  (property "Datasheet" "" (at 228.6 133.35 0) (effects (font (size 1.1 1.1)) (hide yes)))
  (pin "1"))
 (symbol
  (lib_id "Regulator_Switching:TSR2-2433")
  (at 317.5 116.84 0)
  (unit 1)
  (exclude_from_sim no)
  (in_bom yes)
  (on_board yes)
  (dnp no)
  (property "Reference" "U3" (at 317.5 106.8 0) (effects (font (size 1.1 1.1))))
  (property "Value" "TSR2-2433" (at 317.5 109 0) (effects (font (size 1 1))))
  (property "Footprint" "Converter_DCDC:Converter_DCDC_TRACO_TSR2-xxxx_THT" (at 317.5 116.84 0) (effects (font (size 1.1 1.1)) (hide yes)))
  (property "Datasheet" "https://www.tracopower.com/sites/default/files/products/datasheets/tsr2_datasheet.pdf" (at 317.5 116.84 0) (effects (font (size 1.1 1.1)) (hide yes)))
  (pin "1")
  (pin "2")
  (pin "3"))
 (symbol
  (lib_id "power:GND")
  (at 317.5 129.54 0)
  (unit 1)
  (exclude_from_sim no)
  (in_bom no)
  (on_board no)
  (dnp no)
  (property "Reference" "#PWR6" (at 317.5 132.54 0) (effects (font (size 1.1 1.1)) (hide yes)))
  (property "Value" "GND" (at 317.5 134.74 0) (effects (font (size 1 1))))
  (property "Footprint" "" (at 317.5 129.54 0) (effects (font (size 1.1 1.1)) (hide yes)))
  (property "Datasheet" "" (at 317.5 129.54 0) (effects (font (size 1.1 1.1)) (hide yes)))
  (pin "1"))
 (symbol
  (lib_id "Device:C")
  (at 360.68 124.46 0)
  (unit 1)
  (exclude_from_sim no)
  (in_bom yes)
  (on_board yes)
  (dnp no)
  (property "Reference" "C4" (at 364.68 122.66 0) (effects (font (size 1.1 1.1)) (justify left)))
  (property "Value" "22u 10V" (at 364.68 124.86 0) (effects (font (size 1 1)) (justify left)))
  (property "Footprint" "Capacitor_SMD:C_0805_2012Metric" (at 360.68 124.46 0) (effects (font (size 1.1 1.1)) (hide yes) (justify left)))
  (property "Datasheet" "~" (at 360.68 124.46 0) (effects (font (size 1.1 1.1)) (hide yes) (justify left)))
  (pin "1")
  (pin "2"))
 (symbol
  (lib_id "power:+3V3")
  (at 360.68 113.03 0)
  (unit 1)
  (exclude_from_sim no)
  (in_bom no)
  (on_board no)
  (dnp no)
  (property "Reference" "#PWR7" (at 360.68 107.03 0) (effects (font (size 1.1 1.1)) (hide yes)))
  (property "Value" "+3V3" (at 360.68 109.23 0) (effects (font (size 1 1))))
  (property "Footprint" "" (at 360.68 113.03 0) (effects (font (size 1.1 1.1)) (hide yes)))
  (property "Datasheet" "" (at 360.68 113.03 0) (effects (font (size 1.1 1.1)) (hide yes)))
  (pin "1"))
 (symbol
  (lib_id "power:GND")
  (at 360.68 135.89 0)
  (unit 1)
  (exclude_from_sim no)
  (in_bom no)
  (on_board no)
  (dnp no)
  (property "Reference" "#PWR8" (at 360.68 138.89 0) (effects (font (size 1.1 1.1)) (hide yes)))
  (property "Value" "GND" (at 360.68 141.09 0) (effects (font (size 1 1))))
  (property "Footprint" "" (at 360.68 135.89 0) (effects (font (size 1.1 1.1)) (hide yes)))
  (property "Datasheet" "" (at 360.68 135.89 0) (effects (font (size 1.1 1.1)) (hide yes)))
  (pin "1"))
 (symbol
  (lib_id "Device:Polyfuse")
  (at 50.8 185.42 270)
  (unit 1)
  (exclude_from_sim no)
  (in_bom yes)
  (on_board yes)
  (dnp no)
  (property "Reference" "F2" (at 50.8 177.92 90) (effects (font (size 1.1 1.1))))
  (property "Value" "1812L050/30 / 0.5A" (at 50.8 180.12 90) (effects (font (size 1 1))))
  (property "Footprint" "Fuse:Fuse_1812_4532Metric" (at 50.8 185.42 90) (effects (font (size 1.1 1.1)) (hide yes)))
  (property "Datasheet" "~" (at 50.8 185.42 90) (effects (font (size 1.1 1.1)) (hide yes)))
  (pin "1")
  (pin "2"))
 (symbol
  (lib_id "Device:C_Polarized")
  (at 88.9 195.58 0)
  (unit 1)
  (exclude_from_sim no)
  (in_bom yes)
  (on_board yes)
  (dnp no)
  (property "Reference" "C5" (at 92.9 193.78 0) (effects (font (size 1.1 1.1)) (justify left)))
  (property "Value" "22u 50V" (at 92.9 195.98 0) (effects (font (size 1 1)) (justify left)))
  (property "Footprint" "Capacitor_THT:CP_Radial_D8.0mm_P3.50mm" (at 88.9 195.58 0) (effects (font (size 1.1 1.1)) (hide yes) (justify left)))
  (property "Datasheet" "~" (at 88.9 195.58 0) (effects (font (size 1.1 1.1)) (hide yes) (justify left)))
  (pin "1")
  (pin "2"))
 (symbol
  (lib_id "power:GND")
  (at 88.9 207.01 0)
  (unit 1)
  (exclude_from_sim no)
  (in_bom no)
  (on_board no)
  (dnp no)
  (property "Reference" "#PWR9" (at 88.9 210.01 0) (effects (font (size 1.1 1.1)) (hide yes)))
  (property "Value" "GND" (at 88.9 212.21 0) (effects (font (size 1 1))))
  (property "Footprint" "" (at 88.9 207.01 0) (effects (font (size 1.1 1.1)) (hide yes)))
  (property "Datasheet" "" (at 88.9 207.01 0) (effects (font (size 1.1 1.1)) (hide yes)))
  (pin "1"))
 (symbol
  (lib_id "power:PWR_FLAG")
  (at 132.08 182.88 0)
  (unit 1)
  (exclude_from_sim no)
  (in_bom no)
  (on_board no)
  (dnp no)
  (property "Reference" "#FLG1" (at 132.08 176.88 0) (effects (font (size 1.1 1.1)) (hide yes)))
  (property "Value" "PWR_FLAG" (at 132.08 179.08 0) (effects (font (size 1 1))))
  (property "Footprint" "" (at 132.08 182.88 0) (effects (font (size 1.1 1.1)) (hide yes)))
  (property "Datasheet" "~" (at 132.08 182.88 0) (effects (font (size 1.1 1.1)) (hide yes)))
  (pin "1"))
 (symbol
  (lib_id "power:GND")
  (at 132.08 190.5 0)
  (unit 1)
  (exclude_from_sim no)
  (in_bom no)
  (on_board no)
  (dnp no)
  (property "Reference" "#PWR10" (at 132.08 193.5 0) (effects (font (size 1.1 1.1)) (hide yes)))
  (property "Value" "GND" (at 132.08 195.7 0) (effects (font (size 1 1))))
  (property "Footprint" "" (at 132.08 190.5 0) (effects (font (size 1.1 1.1)) (hide yes)))
  (property "Datasheet" "" (at 132.08 190.5 0) (effects (font (size 1.1 1.1)) (hide yes)))
  (pin "1"))
 (symbol
  (lib_id "power:PWR_FLAG")
  (at 172.72 182.88 0)
  (unit 1)
  (exclude_from_sim no)
  (in_bom no)
  (on_board no)
  (dnp no)
  (property "Reference" "#FLG2" (at 172.72 176.88 0) (effects (font (size 1.1 1.1)) (hide yes)))
  (property "Value" "PWR_FLAG" (at 172.72 179.08 0) (effects (font (size 1 1))))
  (property "Footprint" "" (at 172.72 182.88 0) (effects (font (size 1.1 1.1)) (hide yes)))
  (property "Datasheet" "~" (at 172.72 182.88 0) (effects (font (size 1.1 1.1)) (hide yes)))
  (pin "1"))
 (symbol
  (lib_id "power:PWR_FLAG")
  (at 213.36 182.88 0)
  (unit 1)
  (exclude_from_sim no)
  (in_bom no)
  (on_board no)
  (dnp no)
  (property "Reference" "#FLG3" (at 213.36 176.88 0) (effects (font (size 1.1 1.1)) (hide yes)))
  (property "Value" "PWR_FLAG" (at 213.36 179.08 0) (effects (font (size 1 1))))
  (property "Footprint" "" (at 213.36 182.88 0) (effects (font (size 1.1 1.1)) (hide yes)))
  (property "Datasheet" "~" (at 213.36 182.88 0) (effects (font (size 1.1 1.1)) (hide yes)))
  (pin "1"))
 (symbol
  (lib_id "power:PWR_FLAG")
  (at 254 182.88 0)
  (unit 1)
  (exclude_from_sim no)
  (in_bom no)
  (on_board no)
  (dnp no)
  (property "Reference" "#FLG4" (at 254 176.88 0) (effects (font (size 1.1 1.1)) (hide yes)))
  (property "Value" "PWR_FLAG" (at 254 179.08 0) (effects (font (size 1 1))))
  (property "Footprint" "" (at 254 182.88 0) (effects (font (size 1.1 1.1)) (hide yes)))
  (property "Datasheet" "~" (at 254 182.88 0) (effects (font (size 1.1 1.1)) (hide yes)))
  (pin "1"))
 (sheet_instances
  (path ""
   (page "1")))
 (embedded_fonts no))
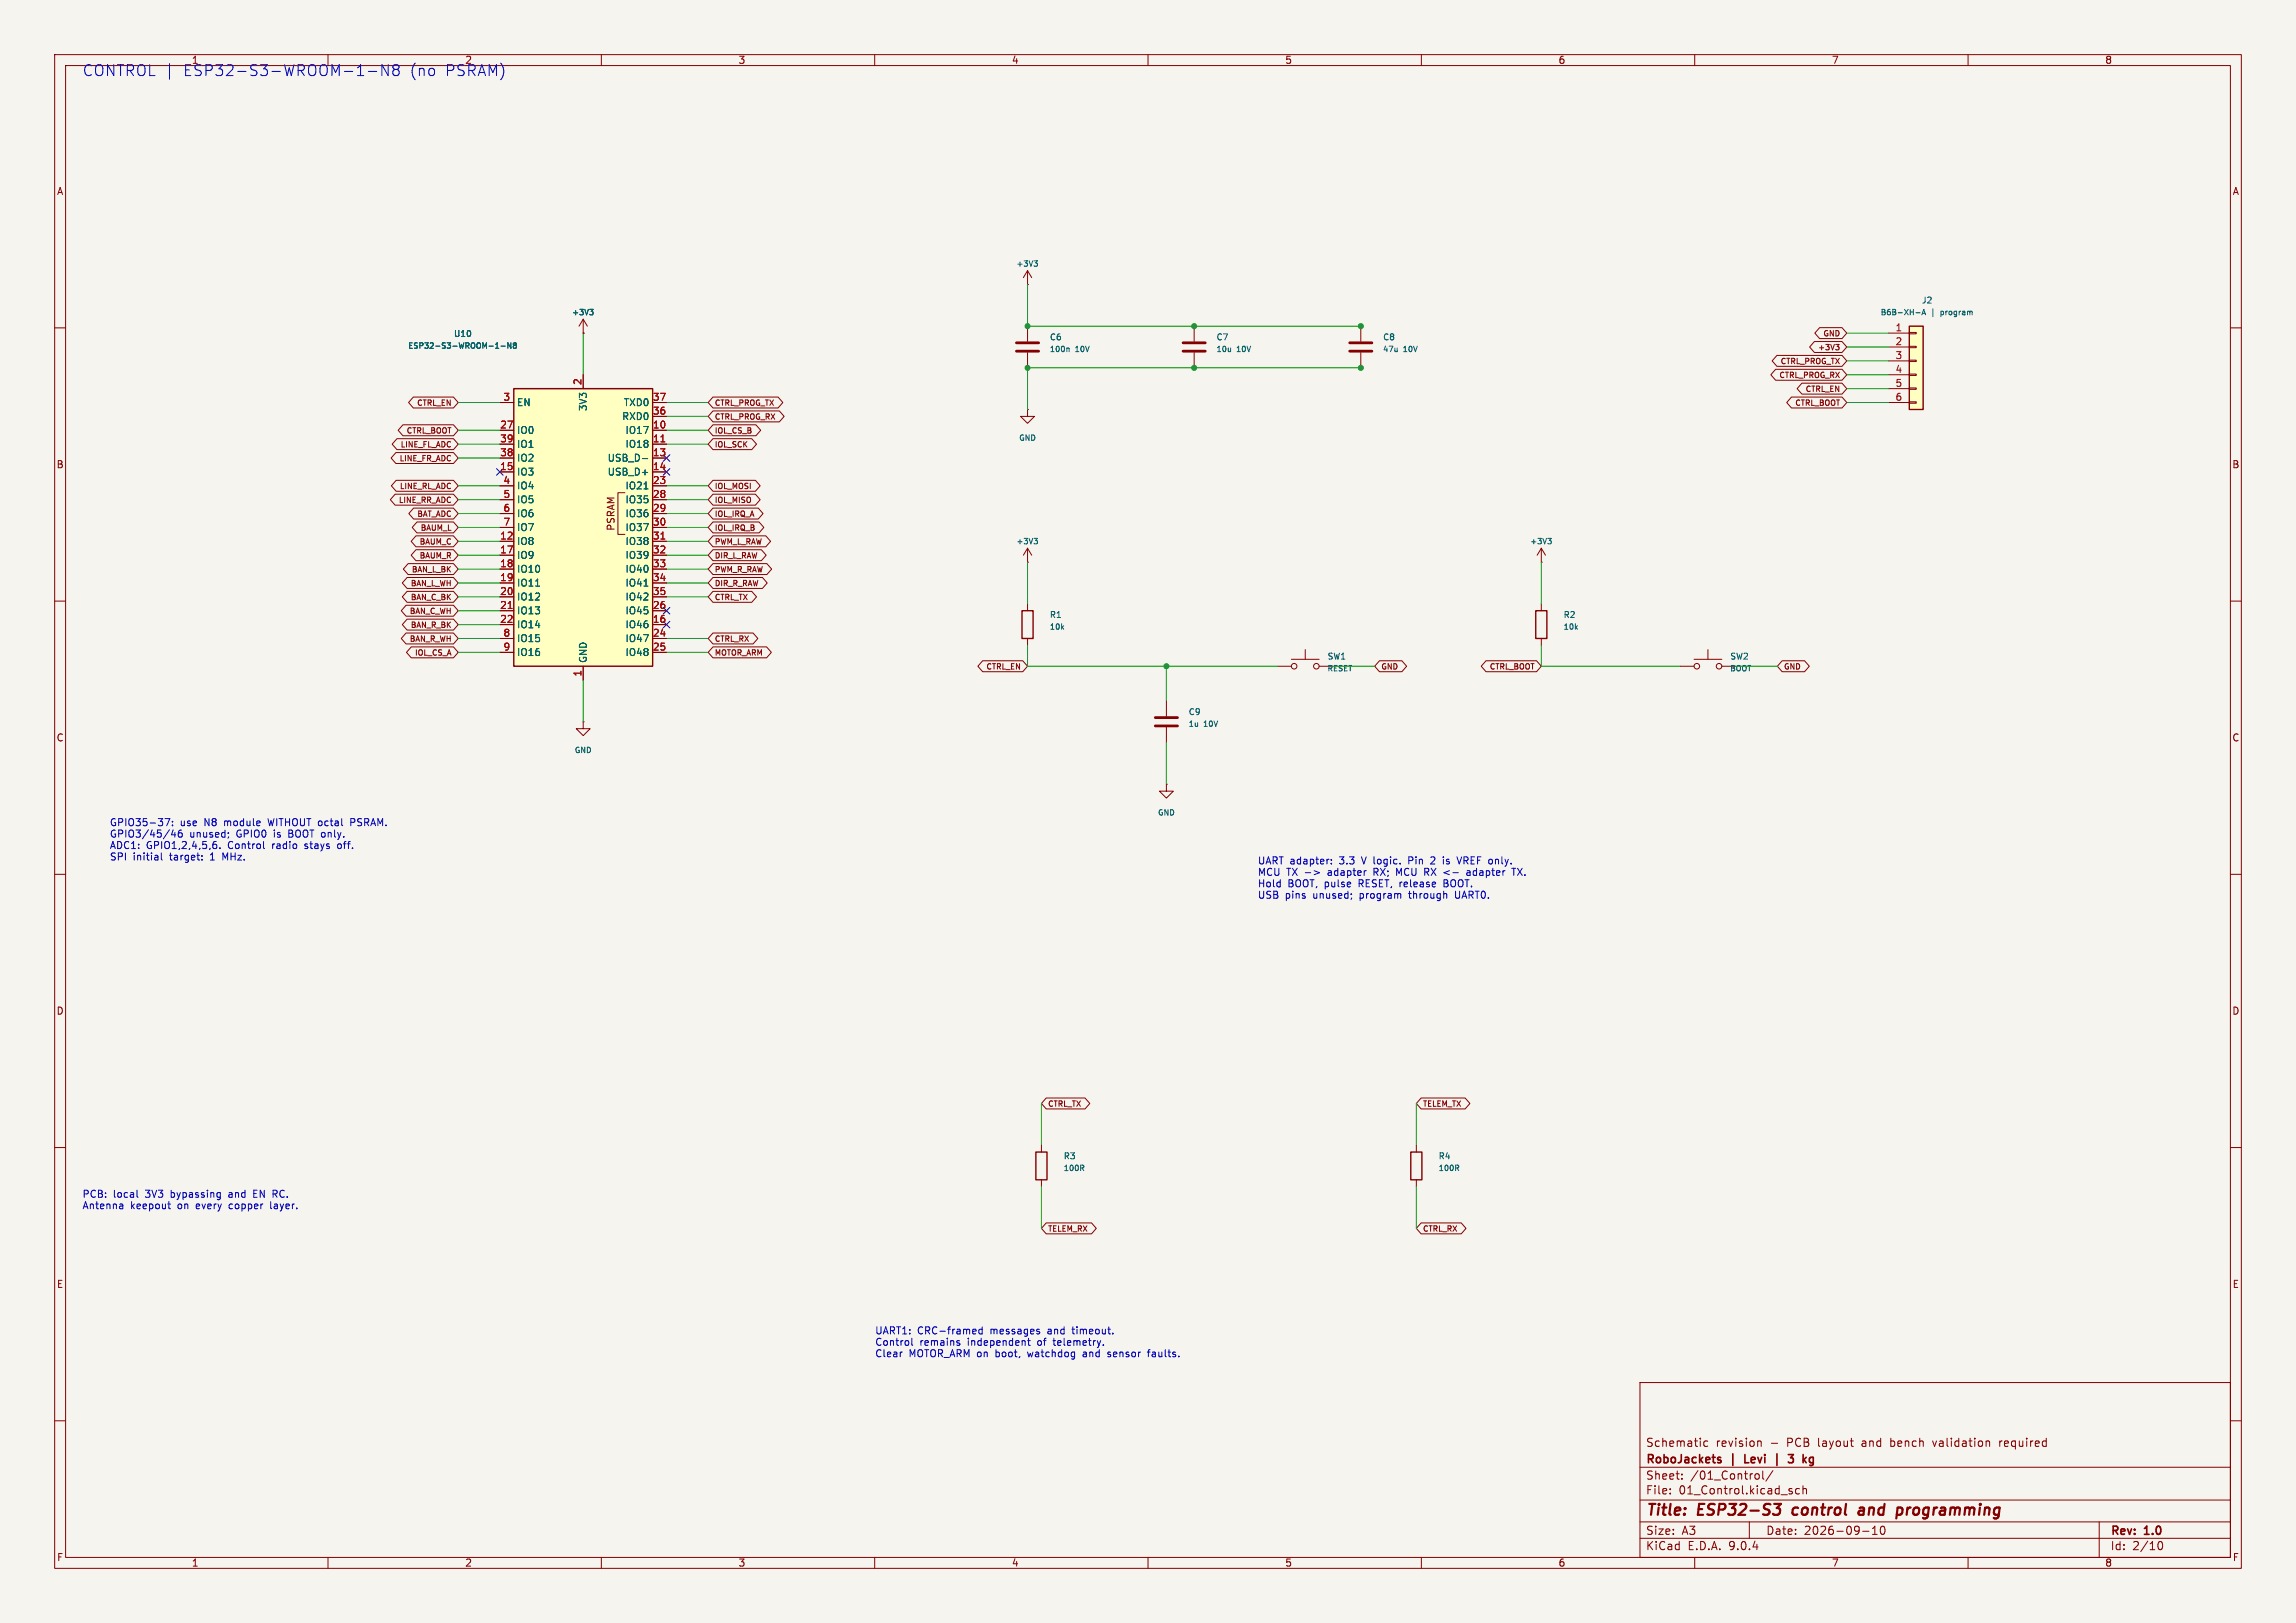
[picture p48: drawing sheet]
(kicad_sch
 (version 20250114)
 (generator "eeschema")
 (generator_version "9.0")
 (paper "A3")
 (title_block
  (title "ESP32-S3 control and programming")
  (date "2026-09-10")
  (rev "1.0")
  (company "RoboJackets | Levi | 3 kg")
  (comment 1 "Schematic revision - PCB layout and bench validation required"))
 (lib_symbols
  (symbol "Connector_Generic:Conn_01x06"
   (pin_names
    (offset 1.016) (hide yes)) (exclude_from_sim no) (in_bom yes) (on_board yes)
   (property "Reference" "J" (at 0 7.62 0) (effects (font (size 1.27 1.27))))
   (property "Value" "Conn_01x06" (at 0 -10.16 0) (effects (font (size 1.27 1.27))))
   (property "Footprint" "" (at 0 0 0) (effects (font (size 1.27 1.27)) (hide yes)))
   (property "Datasheet" "~" (at 0 0 0) (effects (font (size 1.27 1.27)) (hide yes)))
   (property "Description" "Generic connector, single row, 01x06, script generated (kicad-library-utils/schlib/autogen/connector/)" (at 0 0 0) (effects (font (size 1.27 1.27)) (hide yes)))
   (symbol "Conn_01x06_1_1"
    (rectangle (start -1.27 6.35) (end 1.27 -8.89) (stroke (width 0.254) (type default)) (fill (type background)))
    (rectangle (start -1.27 5.207) (end 0 4.953) (stroke (width 0.1524) (type default)) (fill (type none)))
    (rectangle (start -1.27 2.667) (end 0 2.413) (stroke (width 0.1524) (type default)) (fill (type none)))
    (rectangle (start -1.27 0.127) (end 0 -0.127) (stroke (width 0.1524) (type default)) (fill (type none)))
    (rectangle (start -1.27 -2.413) (end 0 -2.667) (stroke (width 0.1524) (type default)) (fill (type none)))
    (rectangle (start -1.27 -4.953) (end 0 -5.207) (stroke (width 0.1524) (type default)) (fill (type none)))
    (rectangle (start -1.27 -7.493) (end 0 -7.747) (stroke (width 0.1524) (type default)) (fill (type none)))
    (pin passive line (at -5.08 5.08 0) (length 3.81) (name "Pin_1" (effects (font (size 1.27 1.27)))) (number "1" (effects (font (size 1.27 1.27)))))
    (pin passive line (at -5.08 2.54 0) (length 3.81) (name "Pin_2" (effects (font (size 1.27 1.27)))) (number "2" (effects (font (size 1.27 1.27)))))
    (pin passive line (at -5.08 0 0) (length 3.81) (name "Pin_3" (effects (font (size 1.27 1.27)))) (number "3" (effects (font (size 1.27 1.27)))))
    (pin passive line (at -5.08 -2.54 0) (length 3.81) (name "Pin_4" (effects (font (size 1.27 1.27)))) (number "4" (effects (font (size 1.27 1.27)))))
    (pin passive line (at -5.08 -5.08 0) (length 3.81) (name "Pin_5" (effects (font (size 1.27 1.27)))) (number "5" (effects (font (size 1.27 1.27)))))
    (pin passive line (at -5.08 -7.62 0) (length 3.81) (name "Pin_6" (effects (font (size 1.27 1.27)))) (number "6" (effects (font (size 1.27 1.27))))))
   (embedded_fonts no))
  (symbol "Device:C"
   (pin_numbers (hide yes))
   (pin_names
    (offset 0.254)) (exclude_from_sim no) (in_bom yes) (on_board yes)
   (property "Reference" "C" (at 0.635 2.54 0) (effects (font (size 1.27 1.27)) (justify left)))
   (property "Value" "C" (at 0.635 -2.54 0) (effects (font (size 1.27 1.27)) (justify left)))
   (property "Footprint" "" (at 0.9652 -3.81 0) (effects (font (size 1.27 1.27)) (hide yes)))
   (property "Datasheet" "~" (at 0 0 0) (effects (font (size 1.27 1.27)) (hide yes)))
   (property "Description" "Unpolarized capacitor" (at 0 0 0) (effects (font (size 1.27 1.27)) (hide yes)))
   (symbol "C_0_1"
    (polyline (pts (xy -2.032 0.762) (xy 2.032 0.762)) (stroke (width 0.508) (type default)) (fill (type none)))
    (polyline (pts (xy -2.032 -0.762) (xy 2.032 -0.762)) (stroke (width 0.508) (type default)) (fill (type none))))
   (symbol "C_1_1"
    (pin passive line (at 0 3.81 270) (length 2.794) (name "~" (effects (font (size 1.27 1.27)))) (number "1" (effects (font (size 1.27 1.27)))))
    (pin passive line (at 0 -3.81 90) (length 2.794) (name "~" (effects (font (size 1.27 1.27)))) (number "2" (effects (font (size 1.27 1.27))))))
   (embedded_fonts no))
  (symbol "Device:R"
   (pin_numbers (hide yes))
   (pin_names
    (offset 0)) (exclude_from_sim no) (in_bom yes) (on_board yes)
   (property "Reference" "R" (at 2.032 0 90) (effects (font (size 1.27 1.27))))
   (property "Value" "R" (at 0 0 90) (effects (font (size 1.27 1.27))))
   (property "Footprint" "" (at -1.778 0 90) (effects (font (size 1.27 1.27)) (hide yes)))
   (property "Datasheet" "~" (at 0 0 0) (effects (font (size 1.27 1.27)) (hide yes)))
   (property "Description" "Resistor" (at 0 0 0) (effects (font (size 1.27 1.27)) (hide yes)))
   (symbol "R_0_1"
    (rectangle (start -1.016 -2.54) (end 1.016 2.54) (stroke (width 0.254) (type default)) (fill (type none))))
   (symbol "R_1_1"
    (pin passive line (at 0 3.81 270) (length 1.27) (name "~" (effects (font (size 1.27 1.27)))) (number "1" (effects (font (size 1.27 1.27)))))
    (pin passive line (at 0 -3.81 90) (length 1.27) (name "~" (effects (font (size 1.27 1.27)))) (number "2" (effects (font (size 1.27 1.27))))))
   (embedded_fonts no))
  (symbol "RF_Module:ESP32-S3-WROOM-1" (exclude_from_sim no) (in_bom yes) (on_board yes)
   (property "Reference" "U" (at -12.7 26.67 0) (effects (font (size 1.27 1.27))))
   (property "Value" "ESP32-S3-WROOM-1" (at 12.7 26.67 0) (effects (font (size 1.27 1.27))))
   (property "Footprint" "RF_Module:ESP32-S3-WROOM-1" (at 0 2.54 0) (effects (font (size 1.27 1.27)) (hide yes)))
   (property "Datasheet" "https://www.espressif.com/sites/default/files/documentation/esp32-s3-wroom-1_wroom-1u_datasheet_en.pdf" (at 0 0 0) (effects (font (size 1.27 1.27)) (hide yes)))
   (property "Description" "RF Module, ESP32-S3 SoC, Wi-Fi 802.11b/g/n, Bluetooth, BLE, 32-bit, 3.3V, onboard antenna, SMD" (at 0 0 0) (effects (font (size 1.27 1.27)) (hide yes)))
   (symbol "ESP32-S3-WROOM-1_0_0"
    (rectangle (start -12.7 25.4) (end 12.7 -25.4) (stroke (width 0.254) (type default)) (fill (type background)))
    (text "PSRAM" (at 5.08 2.54 900) (effects (font (size 1.27 1.27)))))
   (symbol "ESP32-S3-WROOM-1_0_1"
    (polyline (pts (xy 7.62 -1.27) (xy 6.35 -1.27) (xy 6.35 6.35) (xy 7.62 6.35)) (stroke (width 0) (type default)) (fill (type none))))
   (symbol "ESP32-S3-WROOM-1_1_1"
    (pin input line (at -15.24 22.86 0) (length 2.54) (name "EN" (effects (font (size 1.27 1.27)))) (number "3" (effects (font (size 1.27 1.27)))))
    (pin bidirectional line (at -15.24 17.78 0) (length 2.54) (name "IO0" (effects (font (size 1.27 1.27)))) (number "27" (effects (font (size 1.27 1.27)))))
    (pin bidirectional line (at -15.24 15.24 0) (length 2.54) (name "IO1" (effects (font (size 1.27 1.27)))) (number "39" (effects (font (size 1.27 1.27)))))
    (pin bidirectional line (at -15.24 12.7 0) (length 2.54) (name "IO2" (effects (font (size 1.27 1.27)))) (number "38" (effects (font (size 1.27 1.27)))))
    (pin bidirectional line (at -15.24 10.16 0) (length 2.54) (name "IO3" (effects (font (size 1.27 1.27)))) (number "15" (effects (font (size 1.27 1.27)))))
    (pin bidirectional line (at -15.24 7.62 0) (length 2.54) (name "IO4" (effects (font (size 1.27 1.27)))) (number "4" (effects (font (size 1.27 1.27)))))
    (pin bidirectional line (at -15.24 5.08 0) (length 2.54) (name "IO5" (effects (font (size 1.27 1.27)))) (number "5" (effects (font (size 1.27 1.27)))))
    (pin bidirectional line (at -15.24 2.54 0) (length 2.54) (name "IO6" (effects (font (size 1.27 1.27)))) (number "6" (effects (font (size 1.27 1.27)))))
    (pin bidirectional line (at -15.24 0 0) (length 2.54) (name "IO7" (effects (font (size 1.27 1.27)))) (number "7" (effects (font (size 1.27 1.27)))))
    (pin bidirectional line (at -15.24 -2.54 0) (length 2.54) (name "IO8" (effects (font (size 1.27 1.27)))) (number "12" (effects (font (size 1.27 1.27)))))
    (pin bidirectional line (at -15.24 -5.08 0) (length 2.54) (name "IO9" (effects (font (size 1.27 1.27)))) (number "17" (effects (font (size 1.27 1.27)))))
    (pin bidirectional line (at -15.24 -7.62 0) (length 2.54) (name "IO10" (effects (font (size 1.27 1.27)))) (number "18" (effects (font (size 1.27 1.27)))))
    (pin bidirectional line (at -15.24 -10.16 0) (length 2.54) (name "IO11" (effects (font (size 1.27 1.27)))) (number "19" (effects (font (size 1.27 1.27)))))
    (pin bidirectional line (at -15.24 -12.7 0) (length 2.54) (name "IO12" (effects (font (size 1.27 1.27)))) (number "20" (effects (font (size 1.27 1.27)))))
    (pin bidirectional line (at -15.24 -15.24 0) (length 2.54) (name "IO13" (effects (font (size 1.27 1.27)))) (number "21" (effects (font (size 1.27 1.27)))))
    (pin bidirectional line (at -15.24 -17.78 0) (length 2.54) (name "IO14" (effects (font (size 1.27 1.27)))) (number "22" (effects (font (size 1.27 1.27)))))
    (pin bidirectional line (at -15.24 -20.32 0) (length 2.54) (name "IO15" (effects (font (size 1.27 1.27)))) (number "8" (effects (font (size 1.27 1.27)))))
    (pin bidirectional line (at -15.24 -22.86 0) (length 2.54) (name "IO16" (effects (font (size 1.27 1.27)))) (number "9" (effects (font (size 1.27 1.27)))))
    (pin power_in line (at 0 27.94 270) (length 2.54) (name "3V3" (effects (font (size 1.27 1.27)))) (number "2" (effects (font (size 1.27 1.27)))))
    (pin power_in line (at 0 -27.94 90) (length 2.54) (name "GND" (effects (font (size 1.27 1.27)))) (number "1" (effects (font (size 1.27 1.27)))))
    (pin passive line (at 0 -27.94 90) (length 2.54) (hide yes) (name "GND" (effects (font (size 1.27 1.27)))) (number "40" (effects (font (size 1.27 1.27)))))
    (pin passive line (at 0 -27.94 90) (length 2.54) (hide yes) (name "GND" (effects (font (size 1.27 1.27)))) (number "41" (effects (font (size 1.27 1.27)))))
    (pin bidirectional line (at 15.24 22.86 180) (length 2.54) (name "TXD0" (effects (font (size 1.27 1.27)))) (number "37" (effects (font (size 1.27 1.27)))))
    (pin bidirectional line (at 15.24 20.32 180) (length 2.54) (name "RXD0" (effects (font (size 1.27 1.27)))) (number "36" (effects (font (size 1.27 1.27)))))
    (pin bidirectional line (at 15.24 17.78 180) (length 2.54) (name "IO17" (effects (font (size 1.27 1.27)))) (number "10" (effects (font (size 1.27 1.27)))))
    (pin bidirectional line (at 15.24 15.24 180) (length 2.54) (name "IO18" (effects (font (size 1.27 1.27)))) (number "11" (effects (font (size 1.27 1.27)))))
    (pin bidirectional line (at 15.24 12.7 180) (length 2.54) (name "USB_D-" (effects (font (size 1.27 1.27)))) (number "13" (effects (font (size 1.27 1.27))))
    (alternate "IO19" bidirectional line))
    (pin bidirectional line (at 15.24 10.16 180) (length 2.54) (name "USB_D+" (effects (font (size 1.27 1.27)))) (number "14" (effects (font (size 1.27 1.27))))
    (alternate "IO20" bidirectional line))
    (pin bidirectional line (at 15.24 7.62 180) (length 2.54) (name "IO21" (effects (font (size 1.27 1.27)))) (number "23" (effects (font (size 1.27 1.27)))))
    (pin bidirectional line (at 15.24 5.08 180) (length 2.54) (name "IO35" (effects (font (size 1.27 1.27)))) (number "28" (effects (font (size 1.27 1.27)))))
    (pin bidirectional line (at 15.24 2.54 180) (length 2.54) (name "IO36" (effects (font (size 1.27 1.27)))) (number "29" (effects (font (size 1.27 1.27)))))
    (pin bidirectional line (at 15.24 0 180) (length 2.54) (name "IO37" (effects (font (size 1.27 1.27)))) (number "30" (effects (font (size 1.27 1.27)))))
    (pin bidirectional line (at 15.24 -2.54 180) (length 2.54) (name "IO38" (effects (font (size 1.27 1.27)))) (number "31" (effects (font (size 1.27 1.27)))))
    (pin bidirectional line (at 15.24 -5.08 180) (length 2.54) (name "IO39" (effects (font (size 1.27 1.27)))) (number "32" (effects (font (size 1.27 1.27)))))
    (pin bidirectional line (at 15.24 -7.62 180) (length 2.54) (name "IO40" (effects (font (size 1.27 1.27)))) (number "33" (effects (font (size 1.27 1.27)))))
    (pin bidirectional line (at 15.24 -10.16 180) (length 2.54) (name "IO41" (effects (font (size 1.27 1.27)))) (number "34" (effects (font (size 1.27 1.27)))))
    (pin bidirectional line (at 15.24 -12.7 180) (length 2.54) (name "IO42" (effects (font (size 1.27 1.27)))) (number "35" (effects (font (size 1.27 1.27)))))
    (pin bidirectional line (at 15.24 -15.24 180) (length 2.54) (name "IO45" (effects (font (size 1.27 1.27)))) (number "26" (effects (font (size 1.27 1.27)))))
    (pin bidirectional line (at 15.24 -17.78 180) (length 2.54) (name "IO46" (effects (font (size 1.27 1.27)))) (number "16" (effects (font (size 1.27 1.27)))))
    (pin bidirectional line (at 15.24 -20.32 180) (length 2.54) (name "IO47" (effects (font (size 1.27 1.27)))) (number "24" (effects (font (size 1.27 1.27)))))
    (pin bidirectional line (at 15.24 -22.86 180) (length 2.54) (name "IO48" (effects (font (size 1.27 1.27)))) (number "25" (effects (font (size 1.27 1.27))))))
   (embedded_fonts no))
  (symbol "Switch:SW_Push"
   (pin_numbers (hide yes))
   (pin_names
    (offset 1.016) (hide yes)) (exclude_from_sim no) (in_bom yes) (on_board yes)
   (property "Reference" "SW" (at 1.27 2.54 0) (effects (font (size 1.27 1.27)) (justify left)))
   (property "Value" "SW_Push" (at 0 -1.524 0) (effects (font (size 1.27 1.27))))
   (property "Footprint" "" (at 0 5.08 0) (effects (font (size 1.27 1.27)) (hide yes)))
   (property "Datasheet" "~" (at 0 5.08 0) (effects (font (size 1.27 1.27)) (hide yes)))
   (property "Description" "Push button switch, generic, two pins" (at 0 0 0) (effects (font (size 1.27 1.27)) (hide yes)))
   (symbol "SW_Push_0_1"
    (circle (center -2.032 0) (radius 0.508) (stroke (width 0) (type default)) (fill (type none)))
    (polyline (pts (xy 0 1.27) (xy 0 3.048)) (stroke (width 0) (type default)) (fill (type none)))
    (circle (center 2.032 0) (radius 0.508) (stroke (width 0) (type default)) (fill (type none)))
    (polyline (pts (xy 2.54 1.27) (xy -2.54 1.27)) (stroke (width 0) (type default)) (fill (type none)))
    (pin passive line (at -5.08 0 0) (length 2.54) (name "1" (effects (font (size 1.27 1.27)))) (number "1" (effects (font (size 1.27 1.27)))))
    (pin passive line (at 5.08 0 180) (length 2.54) (name "2" (effects (font (size 1.27 1.27)))) (number "2" (effects (font (size 1.27 1.27))))))
   (embedded_fonts no))
  (symbol "power:+3V3"
   (power)
   (pin_numbers (hide yes))
   (pin_names
    (offset 0) (hide yes)) (exclude_from_sim no) (in_bom yes) (on_board yes)
   (property "Reference" "#PWR" (at 0 -3.81 0) (effects (font (size 1.27 1.27)) (hide yes)))
   (property "Value" "+3V3" (at 0 3.556 0) (effects (font (size 1.27 1.27))))
   (property "Footprint" "" (at 0 0 0) (effects (font (size 1.27 1.27)) (hide yes)))
   (property "Datasheet" "" (at 0 0 0) (effects (font (size 1.27 1.27)) (hide yes)))
   (property "Description" "Power symbol creates a global label with name \"+3V3\"" (at 0 0 0) (effects (font (size 1.27 1.27)) (hide yes)))
   (symbol "+3V3_0_1"
    (polyline (pts (xy -0.762 1.27) (xy 0 2.54)) (stroke (width 0) (type default)) (fill (type none)))
    (polyline (pts (xy 0 2.54) (xy 0.762 1.27)) (stroke (width 0) (type default)) (fill (type none)))
    (polyline (pts (xy 0 0) (xy 0 2.54)) (stroke (width 0) (type default)) (fill (type none))))
   (symbol "+3V3_1_1"
    (pin power_in line (at 0 0 90) (length 0) (name "~" (effects (font (size 1.27 1.27)))) (number "1" (effects (font (size 1.27 1.27))))))
   (embedded_fonts no))
  (symbol "power:GND"
   (power)
   (pin_numbers (hide yes))
   (pin_names
    (offset 0) (hide yes)) (exclude_from_sim no) (in_bom yes) (on_board yes)
   (property "Reference" "#PWR" (at 0 -6.35 0) (effects (font (size 1.27 1.27)) (hide yes)))
   (property "Value" "GND" (at 0 -3.81 0) (effects (font (size 1.27 1.27))))
   (property "Footprint" "" (at 0 0 0) (effects (font (size 1.27 1.27)) (hide yes)))
   (property "Datasheet" "" (at 0 0 0) (effects (font (size 1.27 1.27)) (hide yes)))
   (property "Description" "Power symbol creates a global label with name \"GND\" , ground" (at 0 0 0) (effects (font (size 1.27 1.27)) (hide yes)))
   (symbol "GND_0_1"
    (polyline (pts (xy 0 0) (xy 0 -1.27) (xy 1.27 -1.27) (xy 0 -2.54) (xy -1.27 -1.27) (xy 0 -1.27)) (stroke (width 0) (type default)) (fill (type none))))
   (symbol "GND_1_1"
    (pin power_in line (at 0 0 270) (length 0) (name "~" (effects (font (size 1.27 1.27)))) (number "1" (effects (font (size 1.27 1.27))))))
   (embedded_fonts no)))
 (text "CONTROL | ESP32-S3-WROOM-1-N8 (no PSRAM)"
  (at 15 12 0)
  (effects (font (size 2 2)) (justify left top)))
 (global_label "CTRL_EN"
  (shape bidirectional)
  (at 83.82 73.66 180)
  (effects (font (size 1 1)) (justify right))
  (property "Intersheetrefs" "${INTERSHEET_REFS}" (at 83.82 73.66 0) (effects (font (size 1 1)) (hide yes))))
 (global_label "CTRL_BOOT"
  (shape bidirectional)
  (at 83.82 78.74 180)
  (effects (font (size 1 1)) (justify right))
  (property "Intersheetrefs" "${INTERSHEET_REFS}" (at 83.82 78.74 0) (effects (font (size 1 1)) (hide yes))))
 (global_label "LINE_FL_ADC"
  (shape bidirectional)
  (at 83.82 81.28 180)
  (effects (font (size 1 1)) (justify right))
  (property "Intersheetrefs" "${INTERSHEET_REFS}" (at 83.82 81.28 0) (effects (font (size 1 1)) (hide yes))))
 (global_label "LINE_FR_ADC"
  (shape bidirectional)
  (at 83.82 83.82 180)
  (effects (font (size 1 1)) (justify right))
  (property "Intersheetrefs" "${INTERSHEET_REFS}" (at 83.82 83.82 0) (effects (font (size 1 1)) (hide yes))))
 (no_connect
  (at 91.44 86.36))
 (global_label "LINE_RL_ADC"
  (shape bidirectional)
  (at 83.82 88.9 180)
  (effects (font (size 1 1)) (justify right))
  (property "Intersheetrefs" "${INTERSHEET_REFS}" (at 83.82 88.9 0) (effects (font (size 1 1)) (hide yes))))
 (global_label "LINE_RR_ADC"
  (shape bidirectional)
  (at 83.82 91.44 180)
  (effects (font (size 1 1)) (justify right))
  (property "Intersheetrefs" "${INTERSHEET_REFS}" (at 83.82 91.44 0) (effects (font (size 1 1)) (hide yes))))
 (global_label "BAT_ADC"
  (shape bidirectional)
  (at 83.82 93.98 180)
  (effects (font (size 1 1)) (justify right))
  (property "Intersheetrefs" "${INTERSHEET_REFS}" (at 83.82 93.98 0) (effects (font (size 1 1)) (hide yes))))
 (global_label "BAUM_L"
  (shape bidirectional)
  (at 83.82 96.52 180)
  (effects (font (size 1 1)) (justify right))
  (property "Intersheetrefs" "${INTERSHEET_REFS}" (at 83.82 96.52 0) (effects (font (size 1 1)) (hide yes))))
 (global_label "BAUM_C"
  (shape bidirectional)
  (at 83.82 99.06 180)
  (effects (font (size 1 1)) (justify right))
  (property "Intersheetrefs" "${INTERSHEET_REFS}" (at 83.82 99.06 0) (effects (font (size 1 1)) (hide yes))))
 (global_label "BAUM_R"
  (shape bidirectional)
  (at 83.82 101.6 180)
  (effects (font (size 1 1)) (justify right))
  (property "Intersheetrefs" "${INTERSHEET_REFS}" (at 83.82 101.6 0) (effects (font (size 1 1)) (hide yes))))
 (global_label "BAN_L_BK"
  (shape bidirectional)
  (at 83.82 104.14 180)
  (effects (font (size 1 1)) (justify right))
  (property "Intersheetrefs" "${INTERSHEET_REFS}" (at 83.82 104.14 0) (effects (font (size 1 1)) (hide yes))))
 (global_label "BAN_L_WH"
  (shape bidirectional)
  (at 83.82 106.68 180)
  (effects (font (size 1 1)) (justify right))
  (property "Intersheetrefs" "${INTERSHEET_REFS}" (at 83.82 106.68 0) (effects (font (size 1 1)) (hide yes))))
 (global_label "BAN_C_BK"
  (shape bidirectional)
  (at 83.82 109.22 180)
  (effects (font (size 1 1)) (justify right))
  (property "Intersheetrefs" "${INTERSHEET_REFS}" (at 83.82 109.22 0) (effects (font (size 1 1)) (hide yes))))
 (global_label "BAN_C_WH"
  (shape bidirectional)
  (at 83.82 111.76 180)
  (effects (font (size 1 1)) (justify right))
  (property "Intersheetrefs" "${INTERSHEET_REFS}" (at 83.82 111.76 0) (effects (font (size 1 1)) (hide yes))))
 (global_label "BAN_R_BK"
  (shape bidirectional)
  (at 83.82 114.3 180)
  (effects (font (size 1 1)) (justify right))
  (property "Intersheetrefs" "${INTERSHEET_REFS}" (at 83.82 114.3 0) (effects (font (size 1 1)) (hide yes))))
 (global_label "BAN_R_WH"
  (shape bidirectional)
  (at 83.82 116.84 180)
  (effects (font (size 1 1)) (justify right))
  (property "Intersheetrefs" "${INTERSHEET_REFS}" (at 83.82 116.84 0) (effects (font (size 1 1)) (hide yes))))
 (global_label "IOL_CS_A"
  (shape bidirectional)
  (at 83.82 119.38 180)
  (effects (font (size 1 1)) (justify right))
  (property "Intersheetrefs" "${INTERSHEET_REFS}" (at 83.82 119.38 0) (effects (font (size 1 1)) (hide yes))))
 (global_label "CTRL_PROG_TX"
  (shape bidirectional)
  (at 129.54 73.66 0)
  (effects (font (size 1 1)) (justify left))
  (property "Intersheetrefs" "${INTERSHEET_REFS}" (at 129.54 73.66 0) (effects (font (size 1 1)) (hide yes))))
 (global_label "CTRL_PROG_RX"
  (shape bidirectional)
  (at 129.54 76.2 0)
  (effects (font (size 1 1)) (justify left))
  (property "Intersheetrefs" "${INTERSHEET_REFS}" (at 129.54 76.2 0) (effects (font (size 1 1)) (hide yes))))
 (global_label "IOL_CS_B"
  (shape bidirectional)
  (at 129.54 78.74 0)
  (effects (font (size 1 1)) (justify left))
  (property "Intersheetrefs" "${INTERSHEET_REFS}" (at 129.54 78.74 0) (effects (font (size 1 1)) (hide yes))))
 (global_label "IOL_SCK"
  (shape bidirectional)
  (at 129.54 81.28 0)
  (effects (font (size 1 1)) (justify left))
  (property "Intersheetrefs" "${INTERSHEET_REFS}" (at 129.54 81.28 0) (effects (font (size 1 1)) (hide yes))))
 (no_connect
  (at 121.92 83.82))
 (no_connect
  (at 121.92 86.36))
 (global_label "IOL_MOSI"
  (shape bidirectional)
  (at 129.54 88.9 0)
  (effects (font (size 1 1)) (justify left))
  (property "Intersheetrefs" "${INTERSHEET_REFS}" (at 129.54 88.9 0) (effects (font (size 1 1)) (hide yes))))
 (global_label "IOL_MISO"
  (shape bidirectional)
  (at 129.54 91.44 0)
  (effects (font (size 1 1)) (justify left))
  (property "Intersheetrefs" "${INTERSHEET_REFS}" (at 129.54 91.44 0) (effects (font (size 1 1)) (hide yes))))
 (global_label "IOL_IRQ_A"
  (shape bidirectional)
  (at 129.54 93.98 0)
  (effects (font (size 1 1)) (justify left))
  (property "Intersheetrefs" "${INTERSHEET_REFS}" (at 129.54 93.98 0) (effects (font (size 1 1)) (hide yes))))
 (global_label "IOL_IRQ_B"
  (shape bidirectional)
  (at 129.54 96.52 0)
  (effects (font (size 1 1)) (justify left))
  (property "Intersheetrefs" "${INTERSHEET_REFS}" (at 129.54 96.52 0) (effects (font (size 1 1)) (hide yes))))
 (global_label "PWM_L_RAW"
  (shape bidirectional)
  (at 129.54 99.06 0)
  (effects (font (size 1 1)) (justify left))
  (property "Intersheetrefs" "${INTERSHEET_REFS}" (at 129.54 99.06 0) (effects (font (size 1 1)) (hide yes))))
 (global_label "DIR_L_RAW"
  (shape bidirectional)
  (at 129.54 101.6 0)
  (effects (font (size 1 1)) (justify left))
  (property "Intersheetrefs" "${INTERSHEET_REFS}" (at 129.54 101.6 0) (effects (font (size 1 1)) (hide yes))))
 (global_label "PWM_R_RAW"
  (shape bidirectional)
  (at 129.54 104.14 0)
  (effects (font (size 1 1)) (justify left))
  (property "Intersheetrefs" "${INTERSHEET_REFS}" (at 129.54 104.14 0) (effects (font (size 1 1)) (hide yes))))
 (global_label "DIR_R_RAW"
  (shape bidirectional)
  (at 129.54 106.68 0)
  (effects (font (size 1 1)) (justify left))
  (property "Intersheetrefs" "${INTERSHEET_REFS}" (at 129.54 106.68 0) (effects (font (size 1 1)) (hide yes))))
 (global_label "CTRL_TX"
  (shape bidirectional)
  (at 129.54 109.22 0)
  (effects (font (size 1 1)) (justify left))
  (property "Intersheetrefs" "${INTERSHEET_REFS}" (at 129.54 109.22 0) (effects (font (size 1 1)) (hide yes))))
 (no_connect
  (at 121.92 111.76))
 (no_connect
  (at 121.92 114.3))
 (global_label "CTRL_RX"
  (shape bidirectional)
  (at 129.54 116.84 0)
  (effects (font (size 1 1)) (justify left))
  (property "Intersheetrefs" "${INTERSHEET_REFS}" (at 129.54 116.84 0) (effects (font (size 1 1)) (hide yes))))
 (global_label "MOTOR_ARM"
  (shape bidirectional)
  (at 129.54 119.38 0)
  (effects (font (size 1 1)) (justify left))
  (property "Intersheetrefs" "${INTERSHEET_REFS}" (at 129.54 119.38 0) (effects (font (size 1 1)) (hide yes))))
 (text "GPIO35-37: use N8 module WITHOUT octal PSRAM.\nGPIO3/45/46 unused; GPIO0 is BOOT only.\nADC1: GPIO1,2,4,5,6. Control radio stays off.\nSPI initial target: 1 MHz."
  (at 20 150 0)
  (effects (font (size 1.3 1.3)) (justify left top)))
 (junction
  (at 218.44 59.69)
  (diameter 0)
  (color 0 0 0 0))
 (junction
  (at 248.92 59.69)
  (diameter 0)
  (color 0 0 0 0))
 (junction
  (at 218.44 67.31)
  (diameter 0)
  (color 0 0 0 0))
 (junction
  (at 248.92 67.31)
  (diameter 0)
  (color 0 0 0 0))
 (junction
  (at 187.96 59.69)
  (diameter 0)
  (color 0 0 0 0))
 (junction
  (at 187.96 67.31)
  (diameter 0)
  (color 0 0 0 0))
 (global_label "GND"
  (shape bidirectional)
  (at 251.46 121.92 0)
  (effects (font (size 1 1)) (justify left))
  (property "Intersheetrefs" "${INTERSHEET_REFS}" (at 251.46 121.92 0) (effects (font (size 1 1)) (hide yes))))
 (junction
  (at 213.36 121.92)
  (diameter 0)
  (color 0 0 0 0))
 (global_label "CTRL_EN"
  (shape bidirectional)
  (at 187.96 121.92 180)
  (effects (font (size 1 1)) (justify right))
  (property "Intersheetrefs" "${INTERSHEET_REFS}" (at 187.96 121.92 0) (effects (font (size 1 1)) (hide yes))))
 (global_label "GND"
  (shape bidirectional)
  (at 325.12 121.92 0)
  (effects (font (size 1 1)) (justify left))
  (property "Intersheetrefs" "${INTERSHEET_REFS}" (at 325.12 121.92 0) (effects (font (size 1 1)) (hide yes))))
 (global_label "CTRL_BOOT"
  (shape bidirectional)
  (at 281.94 121.92 180)
  (effects (font (size 1 1)) (justify right))
  (property "Intersheetrefs" "${INTERSHEET_REFS}" (at 281.94 121.92 0) (effects (font (size 1 1)) (hide yes))))
 (global_label "GND"
  (shape bidirectional)
  (at 337.82 60.96 180)
  (effects (font (size 1 1)) (justify right))
  (property "Intersheetrefs" "${INTERSHEET_REFS}" (at 337.82 60.96 0) (effects (font (size 1 1)) (hide yes))))
 (global_label "+3V3"
  (shape bidirectional)
  (at 337.82 63.5 180)
  (effects (font (size 1 1)) (justify right))
  (property "Intersheetrefs" "${INTERSHEET_REFS}" (at 337.82 63.5 0) (effects (font (size 1 1)) (hide yes))))
 (global_label "CTRL_PROG_TX"
  (shape bidirectional)
  (at 337.82 66.04 180)
  (effects (font (size 1 1)) (justify right))
  (property "Intersheetrefs" "${INTERSHEET_REFS}" (at 337.82 66.04 0) (effects (font (size 1 1)) (hide yes))))
 (global_label "CTRL_PROG_RX"
  (shape bidirectional)
  (at 337.82 68.58 180)
  (effects (font (size 1 1)) (justify right))
  (property "Intersheetrefs" "${INTERSHEET_REFS}" (at 337.82 68.58 0) (effects (font (size 1 1)) (hide yes))))
 (global_label "CTRL_EN"
  (shape bidirectional)
  (at 337.82 71.12 180)
  (effects (font (size 1 1)) (justify right))
  (property "Intersheetrefs" "${INTERSHEET_REFS}" (at 337.82 71.12 0) (effects (font (size 1 1)) (hide yes))))
 (global_label "CTRL_BOOT"
  (shape bidirectional)
  (at 337.82 73.66 180)
  (effects (font (size 1 1)) (justify right))
  (property "Intersheetrefs" "${INTERSHEET_REFS}" (at 337.82 73.66 0) (effects (font (size 1 1)) (hide yes))))
 (text "UART adapter: 3.3 V logic. Pin 2 is VREF only.\nMCU TX -> adapter RX; MCU RX <- adapter TX.\nHold BOOT, pulse RESET, release BOOT.\nUSB pins unused; program through UART0."
  (at 230 157 0)
  (effects (font (size 1.3 1.3)) (justify left top)))
 (global_label "CTRL_TX"
  (shape bidirectional)
  (at 190.5 201.93 0)
  (effects (font (size 1 1)) (justify left))
  (property "Intersheetrefs" "${INTERSHEET_REFS}" (at 190.5 201.93 0) (effects (font (size 1 1)) (hide yes))))
 (global_label "TELEM_RX"
  (shape bidirectional)
  (at 190.5 224.79 0)
  (effects (font (size 1 1)) (justify left))
  (property "Intersheetrefs" "${INTERSHEET_REFS}" (at 190.5 224.79 0) (effects (font (size 1 1)) (hide yes))))
 (global_label "TELEM_TX"
  (shape bidirectional)
  (at 259.08 201.93 0)
  (effects (font (size 1 1)) (justify left))
  (property "Intersheetrefs" "${INTERSHEET_REFS}" (at 259.08 201.93 0) (effects (font (size 1 1)) (hide yes))))
 (global_label "CTRL_RX"
  (shape bidirectional)
  (at 259.08 224.79 0)
  (effects (font (size 1 1)) (justify left))
  (property "Intersheetrefs" "${INTERSHEET_REFS}" (at 259.08 224.79 0) (effects (font (size 1 1)) (hide yes))))
 (text "UART1: CRC-framed messages and timeout.\nControl remains independent of telemetry.\nClear MOTOR_ARM on boot, watchdog and sensor faults."
  (at 160 243 0)
  (effects (font (size 1.3 1.3)) (justify left top)))
 (text "PCB: local 3V3 bypassing and EN RC.\nAntenna keepout on every copper layer."
  (at 15 218 0)
  (effects (font (size 1.3 1.3)) (justify left top)))
 (wire
  (pts (xy 91.44 73.66) (xy 83.82 73.66))
  (stroke (width 0) (type default)))
 (wire
  (pts (xy 91.44 78.74) (xy 83.82 78.74))
  (stroke (width 0) (type default)))
 (wire
  (pts (xy 91.44 81.28) (xy 83.82 81.28))
  (stroke (width 0) (type default)))
 (wire
  (pts (xy 91.44 83.82) (xy 83.82 83.82))
  (stroke (width 0) (type default)))
 (wire
  (pts (xy 91.44 88.9) (xy 83.82 88.9))
  (stroke (width 0) (type default)))
 (wire
  (pts (xy 91.44 91.44) (xy 83.82 91.44))
  (stroke (width 0) (type default)))
 (wire
  (pts (xy 91.44 93.98) (xy 83.82 93.98))
  (stroke (width 0) (type default)))
 (wire
  (pts (xy 91.44 96.52) (xy 83.82 96.52))
  (stroke (width 0) (type default)))
 (wire
  (pts (xy 91.44 99.06) (xy 83.82 99.06))
  (stroke (width 0) (type default)))
 (wire
  (pts (xy 91.44 101.6) (xy 83.82 101.6))
  (stroke (width 0) (type default)))
 (wire
  (pts (xy 91.44 104.14) (xy 83.82 104.14))
  (stroke (width 0) (type default)))
 (wire
  (pts (xy 91.44 106.68) (xy 83.82 106.68))
  (stroke (width 0) (type default)))
 (wire
  (pts (xy 91.44 109.22) (xy 83.82 109.22))
  (stroke (width 0) (type default)))
 (wire
  (pts (xy 91.44 111.76) (xy 83.82 111.76))
  (stroke (width 0) (type default)))
 (wire
  (pts (xy 91.44 114.3) (xy 83.82 114.3))
  (stroke (width 0) (type default)))
 (wire
  (pts (xy 91.44 116.84) (xy 83.82 116.84))
  (stroke (width 0) (type default)))
 (wire
  (pts (xy 91.44 119.38) (xy 83.82 119.38))
  (stroke (width 0) (type default)))
 (wire
  (pts (xy 106.68 68.58) (xy 106.68 60.96))
  (stroke (width 0) (type default)))
 (wire
  (pts (xy 106.68 124.46) (xy 106.68 132.08))
  (stroke (width 0) (type default)))
 (wire
  (pts (xy 121.92 73.66) (xy 129.54 73.66))
  (stroke (width 0) (type default)))
 (wire
  (pts (xy 121.92 76.2) (xy 129.54 76.2))
  (stroke (width 0) (type default)))
 (wire
  (pts (xy 121.92 78.74) (xy 129.54 78.74))
  (stroke (width 0) (type default)))
 (wire
  (pts (xy 121.92 81.28) (xy 129.54 81.28))
  (stroke (width 0) (type default)))
 (wire
  (pts (xy 121.92 88.9) (xy 129.54 88.9))
  (stroke (width 0) (type default)))
 (wire
  (pts (xy 121.92 91.44) (xy 129.54 91.44))
  (stroke (width 0) (type default)))
 (wire
  (pts (xy 121.92 93.98) (xy 129.54 93.98))
  (stroke (width 0) (type default)))
 (wire
  (pts (xy 121.92 96.52) (xy 129.54 96.52))
  (stroke (width 0) (type default)))
 (wire
  (pts (xy 121.92 99.06) (xy 129.54 99.06))
  (stroke (width 0) (type default)))
 (wire
  (pts (xy 121.92 101.6) (xy 129.54 101.6))
  (stroke (width 0) (type default)))
 (wire
  (pts (xy 121.92 104.14) (xy 129.54 104.14))
  (stroke (width 0) (type default)))
 (wire
  (pts (xy 121.92 106.68) (xy 129.54 106.68))
  (stroke (width 0) (type default)))
 (wire
  (pts (xy 121.92 109.22) (xy 129.54 109.22))
  (stroke (width 0) (type default)))
 (wire
  (pts (xy 121.92 116.84) (xy 129.54 116.84))
  (stroke (width 0) (type default)))
 (wire
  (pts (xy 121.92 119.38) (xy 129.54 119.38))
  (stroke (width 0) (type default)))
 (wire
  (pts (xy 187.96 59.69) (xy 218.44 59.69))
  (stroke (width 0) (type default)))
 (wire
  (pts (xy 218.44 59.69) (xy 248.92 59.69))
  (stroke (width 0) (type default)))
 (wire
  (pts (xy 187.96 67.31) (xy 218.44 67.31))
  (stroke (width 0) (type default)))
 (wire
  (pts (xy 218.44 67.31) (xy 248.92 67.31))
  (stroke (width 0) (type default)))
 (wire
  (pts (xy 187.96 59.69) (xy 187.96 52.07))
  (stroke (width 0) (type default)))
 (wire
  (pts (xy 187.96 67.31) (xy 187.96 74.93))
  (stroke (width 0) (type default)))
 (wire
  (pts (xy 187.96 110.49) (xy 187.96 102.87))
  (stroke (width 0) (type default)))
 (wire
  (pts (xy 213.36 135.89) (xy 213.36 143.51))
  (stroke (width 0) (type default)))
 (wire
  (pts (xy 243.84 121.92) (xy 251.46 121.92))
  (stroke (width 0) (type default)))
 (wire
  (pts (xy 187.96 118.11) (xy 187.96 121.92))
  (stroke (width 0) (type default)))
 (wire
  (pts (xy 187.96 121.92) (xy 213.36 121.92))
  (stroke (width 0) (type default)))
 (wire
  (pts (xy 213.36 121.92) (xy 233.68 121.92))
  (stroke (width 0) (type default)))
 (wire
  (pts (xy 213.36 121.92) (xy 213.36 128.27))
  (stroke (width 0) (type default)))
 (wire
  (pts (xy 281.94 110.49) (xy 281.94 102.87))
  (stroke (width 0) (type default)))
 (wire
  (pts (xy 317.5 121.92) (xy 325.12 121.92))
  (stroke (width 0) (type default)))
 (wire
  (pts (xy 281.94 118.11) (xy 281.94 121.92))
  (stroke (width 0) (type default)))
 (wire
  (pts (xy 281.94 121.92) (xy 307.34 121.92))
  (stroke (width 0) (type default)))
 (wire
  (pts (xy 345.44 60.96) (xy 337.82 60.96))
  (stroke (width 0) (type default)))
 (wire
  (pts (xy 345.44 63.5) (xy 337.82 63.5))
  (stroke (width 0) (type default)))
 (wire
  (pts (xy 345.44 66.04) (xy 337.82 66.04))
  (stroke (width 0) (type default)))
 (wire
  (pts (xy 345.44 68.58) (xy 337.82 68.58))
  (stroke (width 0) (type default)))
 (wire
  (pts (xy 345.44 71.12) (xy 337.82 71.12))
  (stroke (width 0) (type default)))
 (wire
  (pts (xy 345.44 73.66) (xy 337.82 73.66))
  (stroke (width 0) (type default)))
 (wire
  (pts (xy 190.5 209.55) (xy 190.5 201.93))
  (stroke (width 0) (type default)))
 (wire
  (pts (xy 190.5 217.17) (xy 190.5 224.79))
  (stroke (width 0) (type default)))
 (wire
  (pts (xy 259.08 209.55) (xy 259.08 201.93))
  (stroke (width 0) (type default)))
 (wire
  (pts (xy 259.08 217.17) (xy 259.08 224.79))
  (stroke (width 0) (type default)))
 (symbol
  (lib_id "RF_Module:ESP32-S3-WROOM-1")
  (at 106.68 96.52 0)
  (unit 1)
  (exclude_from_sim no)
  (in_bom yes)
  (on_board yes)
  (dnp no)
  (property "Reference" "U10" (at 84.68 61.08 0) (effects (font (size 1.1 1.1))))
  (property "Value" "ESP32-S3-WROOM-1-N8" (at 84.68 63.28 0) (effects (font (size 1 1))))
  (property "Footprint" "RF_Module:ESP32-S3-WROOM-1" (at 106.68 96.52 0) (effects (font (size 1.1 1.1)) (hide yes)))
  (property "Datasheet" "https://www.espressif.com/sites/default/files/documentation/esp32-s3-wroom-1_wroom-1u_datasheet_en.pdf" (at 106.68 96.52 0) (effects (font (size 1.1 1.1)) (hide yes)))
  (pin "3")
  (pin "27")
  (pin "39")
  (pin "38")
  (pin "15")
  (pin "4")
  (pin "5")
  (pin "6")
  (pin "7")
  (pin "12")
  (pin "17")
  (pin "18")
  (pin "19")
  (pin "20")
  (pin "21")
  (pin "22")
  (pin "8")
  (pin "9")
  (pin "2")
  (pin "1")
  (pin "40")
  (pin "41")
  (pin "37")
  (pin "36")
  (pin "10")
  (pin "11")
  (pin "13")
  (pin "14")
  (pin "23")
  (pin "28")
  (pin "29")
  (pin "30")
  (pin "31")
  (pin "32")
  (pin "33")
  (pin "34")
  (pin "35")
  (pin "26")
  (pin "16")
  (pin "24")
  (pin "25"))
 (symbol
  (lib_id "power:+3V3")
  (at 106.68 60.96 0)
  (unit 1)
  (exclude_from_sim no)
  (in_bom no)
  (on_board no)
  (dnp no)
  (property "Reference" "#PWR11" (at 106.68 54.96 0) (effects (font (size 1.1 1.1)) (hide yes)))
  (property "Value" "+3V3" (at 106.68 57.16 0) (effects (font (size 1 1))))
  (property "Footprint" "" (at 106.68 60.96 0) (effects (font (size 1.1 1.1)) (hide yes)))
  (property "Datasheet" "" (at 106.68 60.96 0) (effects (font (size 1.1 1.1)) (hide yes)))
  (pin "1"))
 (symbol
  (lib_id "power:GND")
  (at 106.68 132.08 0)
  (unit 1)
  (exclude_from_sim no)
  (in_bom no)
  (on_board no)
  (dnp no)
  (property "Reference" "#PWR12" (at 106.68 135.08 0) (effects (font (size 1.1 1.1)) (hide yes)))
  (property "Value" "GND" (at 106.68 137.28 0) (effects (font (size 1 1))))
  (property "Footprint" "" (at 106.68 132.08 0) (effects (font (size 1.1 1.1)) (hide yes)))
  (property "Datasheet" "" (at 106.68 132.08 0) (effects (font (size 1.1 1.1)) (hide yes)))
  (pin "1"))
 (symbol
  (lib_id "Device:C")
  (at 187.96 63.5 0)
  (unit 1)
  (exclude_from_sim no)
  (in_bom yes)
  (on_board yes)
  (dnp no)
  (property "Reference" "C6" (at 191.96 61.7 0) (effects (font (size 1.1 1.1)) (justify left)))
  (property "Value" "100n 10V" (at 191.96 63.9 0) (effects (font (size 1 1)) (justify left)))
  (property "Footprint" "Capacitor_SMD:C_0805_2012Metric" (at 187.96 63.5 0) (effects (font (size 1.1 1.1)) (hide yes) (justify left)))
  (property "Datasheet" "~" (at 187.96 63.5 0) (effects (font (size 1.1 1.1)) (hide yes) (justify left)))
  (pin "1")
  (pin "2"))
 (symbol
  (lib_id "Device:C")
  (at 218.44 63.5 0)
  (unit 1)
  (exclude_from_sim no)
  (in_bom yes)
  (on_board yes)
  (dnp no)
  (property "Reference" "C7" (at 222.44 61.7 0) (effects (font (size 1.1 1.1)) (justify left)))
  (property "Value" "10u 10V" (at 222.44 63.9 0) (effects (font (size 1 1)) (justify left)))
  (property "Footprint" "Capacitor_SMD:C_0805_2012Metric" (at 218.44 63.5 0) (effects (font (size 1.1 1.1)) (hide yes) (justify left)))
  (property "Datasheet" "~" (at 218.44 63.5 0) (effects (font (size 1.1 1.1)) (hide yes) (justify left)))
  (pin "1")
  (pin "2"))
 (symbol
  (lib_id "Device:C")
  (at 248.92 63.5 0)
  (unit 1)
  (exclude_from_sim no)
  (in_bom yes)
  (on_board yes)
  (dnp no)
  (property "Reference" "C8" (at 252.92 61.7 0) (effects (font (size 1.1 1.1)) (justify left)))
  (property "Value" "47u 10V" (at 252.92 63.9 0) (effects (font (size 1 1)) (justify left)))
  (property "Footprint" "Capacitor_SMD:C_1210_3225Metric" (at 248.92 63.5 0) (effects (font (size 1.1 1.1)) (hide yes) (justify left)))
  (property "Datasheet" "~" (at 248.92 63.5 0) (effects (font (size 1.1 1.1)) (hide yes) (justify left)))
  (pin "1")
  (pin "2"))
 (symbol
  (lib_id "power:+3V3")
  (at 187.96 52.07 0)
  (unit 1)
  (exclude_from_sim no)
  (in_bom no)
  (on_board no)
  (dnp no)
  (property "Reference" "#PWR13" (at 187.96 46.07 0) (effects (font (size 1.1 1.1)) (hide yes)))
  (property "Value" "+3V3" (at 187.96 48.27 0) (effects (font (size 1 1))))
  (property "Footprint" "" (at 187.96 52.07 0) (effects (font (size 1.1 1.1)) (hide yes)))
  (property "Datasheet" "" (at 187.96 52.07 0) (effects (font (size 1.1 1.1)) (hide yes)))
  (pin "1"))
 (symbol
  (lib_id "power:GND")
  (at 187.96 74.93 0)
  (unit 1)
  (exclude_from_sim no)
  (in_bom no)
  (on_board no)
  (dnp no)
  (property "Reference" "#PWR14" (at 187.96 77.93 0) (effects (font (size 1.1 1.1)) (hide yes)))
  (property "Value" "GND" (at 187.96 80.13 0) (effects (font (size 1 1))))
  (property "Footprint" "" (at 187.96 74.93 0) (effects (font (size 1.1 1.1)) (hide yes)))
  (property "Datasheet" "" (at 187.96 74.93 0) (effects (font (size 1.1 1.1)) (hide yes)))
  (pin "1"))
 (symbol
  (lib_id "Device:R")
  (at 187.96 114.3 0)
  (unit 1)
  (exclude_from_sim no)
  (in_bom yes)
  (on_board yes)
  (dnp no)
  (property "Reference" "R1" (at 191.96 112.5 0) (effects (font (size 1.1 1.1)) (justify left)))
  (property "Value" "10k" (at 191.96 114.7 0) (effects (font (size 1 1)) (justify left)))
  (property "Footprint" "Resistor_SMD:R_0805_2012Metric" (at 187.96 114.3 0) (effects (font (size 1.1 1.1)) (hide yes) (justify left)))
  (property "Datasheet" "~" (at 187.96 114.3 0) (effects (font (size 1.1 1.1)) (hide yes) (justify left)))
  (pin "1")
  (pin "2"))
 (symbol
  (lib_id "power:+3V3")
  (at 187.96 102.87 0)
  (unit 1)
  (exclude_from_sim no)
  (in_bom no)
  (on_board no)
  (dnp no)
  (property "Reference" "#PWR15" (at 187.96 96.87 0) (effects (font (size 1.1 1.1)) (hide yes)))
  (property "Value" "+3V3" (at 187.96 99.07 0) (effects (font (size 1 1))))
  (property "Footprint" "" (at 187.96 102.87 0) (effects (font (size 1.1 1.1)) (hide yes)))
  (property "Datasheet" "" (at 187.96 102.87 0) (effects (font (size 1.1 1.1)) (hide yes)))
  (pin "1"))
 (symbol
  (lib_id "Device:C")
  (at 213.36 132.08 0)
  (unit 1)
  (exclude_from_sim no)
  (in_bom yes)
  (on_board yes)
  (dnp no)
  (property "Reference" "C9" (at 217.36 130.28 0) (effects (font (size 1.1 1.1)) (justify left)))
  (property "Value" "1u 10V" (at 217.36 132.48 0) (effects (font (size 1 1)) (justify left)))
  (property "Footprint" "Capacitor_SMD:C_0805_2012Metric" (at 213.36 132.08 0) (effects (font (size 1.1 1.1)) (hide yes) (justify left)))
  (property "Datasheet" "~" (at 213.36 132.08 0) (effects (font (size 1.1 1.1)) (hide yes) (justify left)))
  (pin "1")
  (pin "2"))
 (symbol
  (lib_id "power:GND")
  (at 213.36 143.51 0)
  (unit 1)
  (exclude_from_sim no)
  (in_bom no)
  (on_board no)
  (dnp no)
  (property "Reference" "#PWR16" (at 213.36 146.51 0) (effects (font (size 1.1 1.1)) (hide yes)))
  (property "Value" "GND" (at 213.36 148.71 0) (effects (font (size 1 1))))
  (property "Footprint" "" (at 213.36 143.51 0) (effects (font (size 1.1 1.1)) (hide yes)))
  (property "Datasheet" "" (at 213.36 143.51 0) (effects (font (size 1.1 1.1)) (hide yes)))
  (pin "1"))
 (symbol
  (lib_id "Switch:SW_Push")
  (at 238.76 121.92 0)
  (unit 1)
  (exclude_from_sim no)
  (in_bom yes)
  (on_board yes)
  (dnp no)
  (property "Reference" "SW1" (at 242.76 120.12 0) (effects (font (size 1.1 1.1)) (justify left)))
  (property "Value" "RESET" (at 242.76 122.32 0) (effects (font (size 1 1)) (justify left)))
  (property "Footprint" "Button_Switch_SMD:SW_SPST_TL3342" (at 238.76 121.92 0) (effects (font (size 1.1 1.1)) (hide yes) (justify left)))
  (property "Datasheet" "~" (at 238.76 121.92 0) (effects (font (size 1.1 1.1)) (hide yes) (justify left)))
  (pin "1")
  (pin "2"))
 (symbol
  (lib_id "Device:R")
  (at 281.94 114.3 0)
  (unit 1)
  (exclude_from_sim no)
  (in_bom yes)
  (on_board yes)
  (dnp no)
  (property "Reference" "R2" (at 285.94 112.5 0) (effects (font (size 1.1 1.1)) (justify left)))
  (property "Value" "10k" (at 285.94 114.7 0) (effects (font (size 1 1)) (justify left)))
  (property "Footprint" "Resistor_SMD:R_0805_2012Metric" (at 281.94 114.3 0) (effects (font (size 1.1 1.1)) (hide yes) (justify left)))
  (property "Datasheet" "~" (at 281.94 114.3 0) (effects (font (size 1.1 1.1)) (hide yes) (justify left)))
  (pin "1")
  (pin "2"))
 (symbol
  (lib_id "power:+3V3")
  (at 281.94 102.87 0)
  (unit 1)
  (exclude_from_sim no)
  (in_bom no)
  (on_board no)
  (dnp no)
  (property "Reference" "#PWR17" (at 281.94 96.87 0) (effects (font (size 1.1 1.1)) (hide yes)))
  (property "Value" "+3V3" (at 281.94 99.07 0) (effects (font (size 1 1))))
  (property "Footprint" "" (at 281.94 102.87 0) (effects (font (size 1.1 1.1)) (hide yes)))
  (property "Datasheet" "" (at 281.94 102.87 0) (effects (font (size 1.1 1.1)) (hide yes)))
  (pin "1"))
 (symbol
  (lib_id "Switch:SW_Push")
  (at 312.42 121.92 0)
  (unit 1)
  (exclude_from_sim no)
  (in_bom yes)
  (on_board yes)
  (dnp no)
  (property "Reference" "SW2" (at 316.42 120.12 0) (effects (font (size 1.1 1.1)) (justify left)))
  (property "Value" "BOOT" (at 316.42 122.32 0) (effects (font (size 1 1)) (justify left)))
  (property "Footprint" "Button_Switch_SMD:SW_SPST_TL3342" (at 312.42 121.92 0) (effects (font (size 1.1 1.1)) (hide yes) (justify left)))
  (property "Datasheet" "~" (at 312.42 121.92 0) (effects (font (size 1.1 1.1)) (hide yes) (justify left)))
  (pin "1")
  (pin "2"))
 (symbol
  (lib_id "Connector_Generic:Conn_01x06")
  (at 350.52 66.04 0)
  (unit 1)
  (exclude_from_sim no)
  (in_bom yes)
  (on_board yes)
  (dnp no)
  (property "Reference" "J2" (at 352.52 54.96 0) (effects (font (size 1.1 1.1))))
  (property "Value" "B6B-XH-A | program" (at 352.52 57.16 0) (effects (font (size 1 1))))
  (property "Footprint" "Connector_JST:JST_XH_B6B-XH-A_1x06_P2.50mm_Vertical" (at 350.52 66.04 0) (effects (font (size 1.1 1.1)) (hide yes)))
  (property "Datasheet" "~" (at 350.52 66.04 0) (effects (font (size 1.1 1.1)) (hide yes)))
  (pin "1")
  (pin "2")
  (pin "3")
  (pin "4")
  (pin "5")
  (pin "6"))
 (symbol
  (lib_id "Device:R")
  (at 190.5 213.36 0)
  (unit 1)
  (exclude_from_sim no)
  (in_bom yes)
  (on_board yes)
  (dnp no)
  (property "Reference" "R3" (at 194.5 211.56 0) (effects (font (size 1.1 1.1)) (justify left)))
  (property "Value" "100R" (at 194.5 213.76 0) (effects (font (size 1 1)) (justify left)))
  (property "Footprint" "Resistor_SMD:R_0805_2012Metric" (at 190.5 213.36 0) (effects (font (size 1.1 1.1)) (hide yes) (justify left)))
  (property "Datasheet" "~" (at 190.5 213.36 0) (effects (font (size 1.1 1.1)) (hide yes) (justify left)))
  (pin "1")
  (pin "2"))
 (symbol
  (lib_id "Device:R")
  (at 259.08 213.36 0)
  (unit 1)
  (exclude_from_sim no)
  (in_bom yes)
  (on_board yes)
  (dnp no)
  (property "Reference" "R4" (at 263.08 211.56 0) (effects (font (size 1.1 1.1)) (justify left)))
  (property "Value" "100R" (at 263.08 213.76 0) (effects (font (size 1 1)) (justify left)))
  (property "Footprint" "Resistor_SMD:R_0805_2012Metric" (at 259.08 213.36 0) (effects (font (size 1.1 1.1)) (hide yes) (justify left)))
  (property "Datasheet" "~" (at 259.08 213.36 0) (effects (font (size 1.1 1.1)) (hide yes) (justify left)))
  (pin "1")
  (pin "2"))
 (embedded_fonts no))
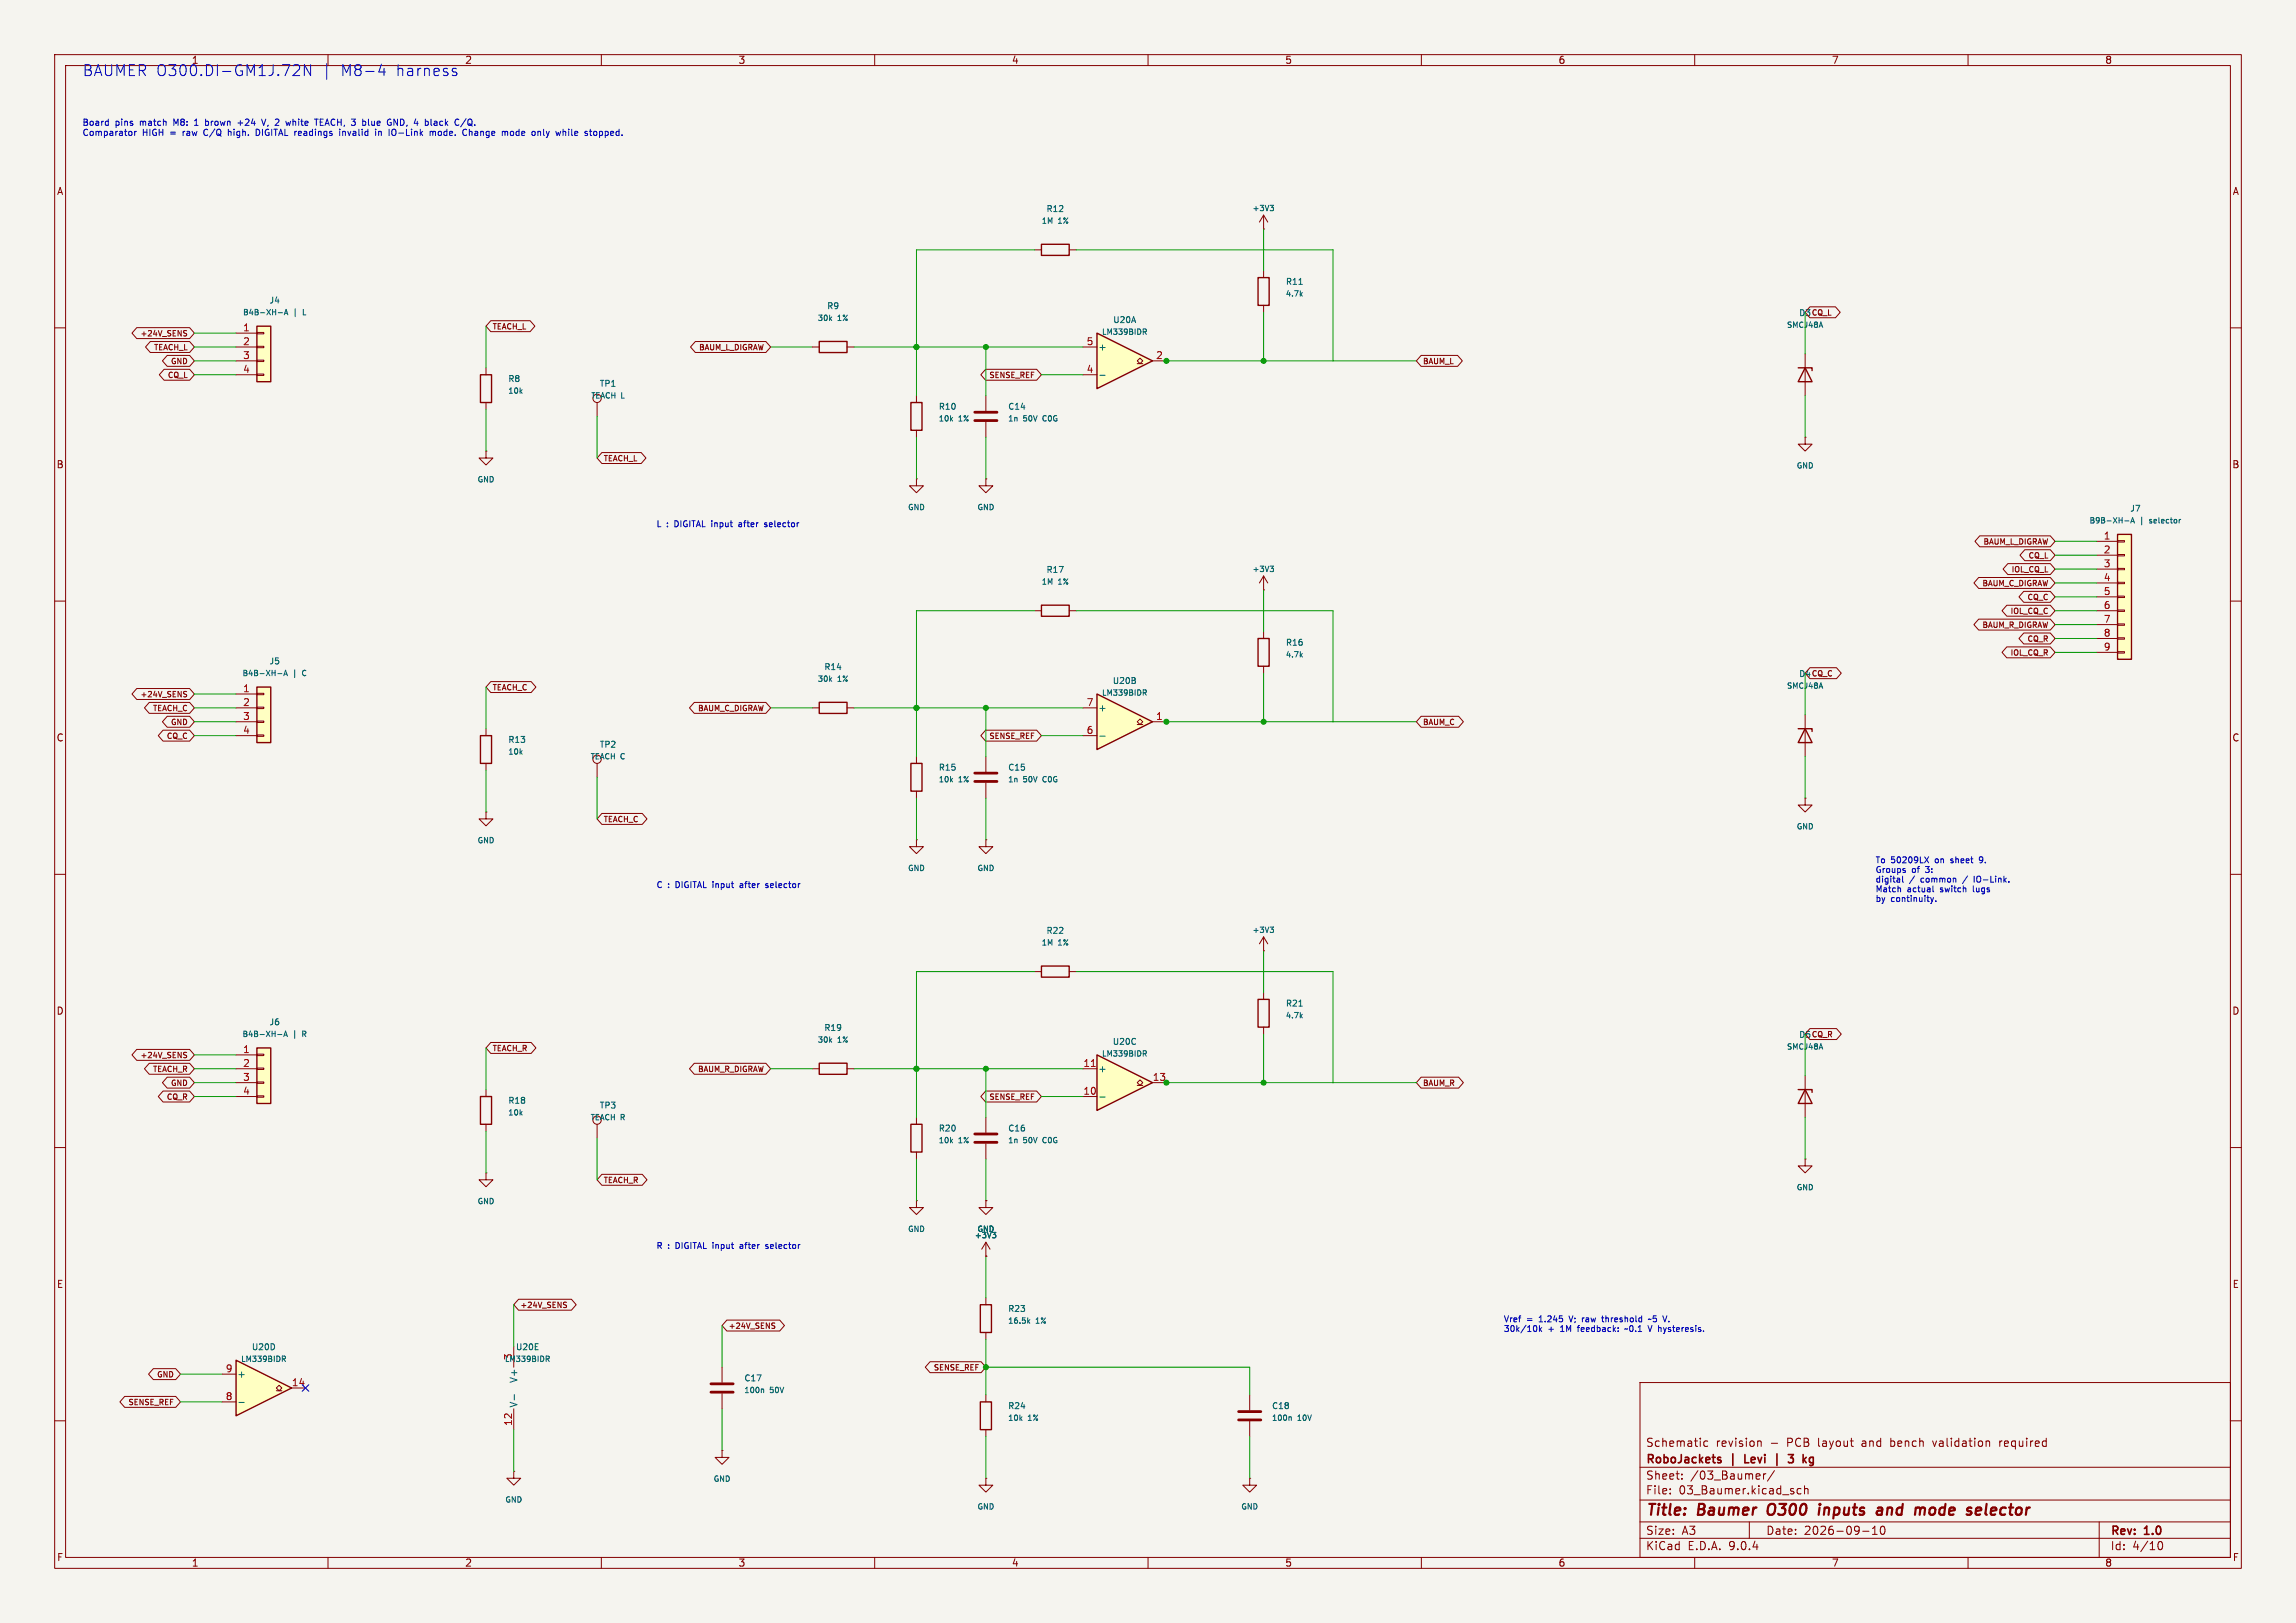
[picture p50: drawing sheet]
<svg xmlns="http://www.w3.org/2000/svg" width="420mm" height="297mm" viewBox="0 0 420 297" stroke-linecap="round" stroke-linejoin="round" font-family="sans-serif">
<defs><g id="words">
<text font-size="2.7" fill="#0000c2" x="15" y="13.8">BAUMER O300.DI-GM1J.72N | M8-4 harness</text>
<text font-size="2.7" fill="#840000" x="301" y="277.3">Title: Baumer O300 inputs and mode selector</text>
<g font-size="2" fill="#840000">
<text x="301" y="267.8">RoboJackets | Levi | 3 kg</text>
<text x="301" y="264.8">Schematic revision - PCB layout and bench validation required</text>
<text x="301" y="273.5">File: 03_Baumer.kicad_sch</text>
<text x="301" y="270.8">Sheet: /03_Baumer/</text>
<text x="301" y="280.9">Size: A3</text>
<text x="323" y="280.9">Date: 2026-09-10</text>
<text x="386" y="280.9">Rev: 1.0</text>
<text x="301" y="283.7">KiCad E.D.A. 9.0.4</text>
<text x="386" y="283.7">Id: 4/10</text>
</g>
<text font-size="1.7" fill="#0000c2" x="35" y="11.6">1</text>
<g font-size="1.7" fill="#840000">
<text x="85" y="11.6">2</text>
<text x="135" y="11.6">3</text>
<text x="185" y="11.6">4</text>
<text x="235" y="11.6">5</text>
<text x="285" y="11.6">6</text>
<text x="335" y="11.6">7</text>
<text x="385" y="11.6">8</text>
<text x="10.4" y="35.6">A</text>
<text x="408.4" y="35.6">A</text>
<text x="10.4" y="85.7">B</text>
<text x="408.4" y="85.7">B</text>
<text x="10.4" y="135.6">C</text>
<text x="408.4" y="135.6">C</text>
<text x="10.4" y="185.6">D</text>
<text x="408.4" y="185.6">D</text>
<text x="10.5" y="235.6">E</text>
<text x="408.5" y="235.6">E</text>
<text x="10.5" y="285.6">F</text>
<text x="35" y="286.7">1</text>
<text x="85" y="286.7">2</text>
<text x="135" y="286.7">3</text>
<text x="185" y="286.7">4</text>
<text x="235" y="286.7">5</text>
<text x="285" y="286.7">6</text>
<text x="335" y="286.7">7</text>
<text x="385" y="286.7">8</text>
<text x="408.5" y="285.6">F</text>
</g>
<g font-size="1.7" fill="#a90000">
<text x="44.7" y="60.7">1</text>
<text x="44.7" y="63.2">2</text>
<text x="44.7" y="65.8">3</text>
<text x="199" y="63.2">5</text>
<text x="211.7" y="65.8">2</text>
<text x="44.7" y="68.3">4</text>
<text x="199" y="68.3">4</text>
<text x="385" y="98.8">1</text>
<text x="385" y="101.3">2</text>
<text x="385" y="103.9">3</text>
<text x="385" y="106.4">4</text>
<text x="385" y="109">5</text>
<text x="385" y="111.5">6</text>
<text x="385" y="114">7</text>
<text x="385" y="116.6">8</text>
<text x="385" y="119.1">9</text>
<text x="44.7" y="126.7">1</text>
<text x="44.7" y="129.3">2</text>
<text x="44.7" y="131.8">3</text>
<text x="199" y="129.3">7</text>
<text x="211.7" y="131.8">1</text>
<text x="44.7" y="134.4">4</text>
<text x="199" y="134.4">6</text>
<text x="44.7" y="192.8">1</text>
<text x="44.7" y="195.3">2</text>
<text x="44.7" y="197.9">3</text>
<text x="198.5" y="195.3">11</text>
<text x="211.2" y="197.9">13</text>
<text x="44.7" y="200.4">4</text>
<text x="198.5" y="200.4">10</text>
<text x="41.5" y="251.2">9</text>
<text x="41.5" y="256.3">8</text>
<text x="53.8" y="253.7">14</text>
<text x="93.7" y="260.6" transform="rotate(-90 93.7 260.6)">12</text>
</g>
<g font-size="1.7" fill="#006464">
<text x="200.8" y="64.1">+</text>
<text x="200.8" y="130.2">+</text>
<text x="200.8" y="196.2">+</text>
<text x="93.7" y="248.7" transform="rotate(-90 93.7 248.7)">3</text>
<text x="43.3" y="252.1">+</text>
<text x="94.6" y="257.7" transform="rotate(-90 94.6 257.7)">V-</text>
<text x="94.6" y="252.5" transform="rotate(-90 94.6 252.5)">V+</text>
</g>
<g font-size="1.5" fill="#0000c2">
<text x="15" y="22.9">Board pins match M8: 1 brown +24 V, 2 white TEACH, 3 blue GND, 4 black C/Q.</text>
<text x="15" y="24.8">Comparator HIGH = raw C/Q high. DIGITAL readings invalid in IO-Link mode. Change mode only while stopped.</text>
<text x="120" y="96.4">L : DIGITAL input after selector</text>
<text x="343" y="157.9">To 50209LX on sheet 9.</text>
<text x="343" y="159.6">Groups of 3:</text>
<text x="343" y="161.4">digital / common / IO-Link.</text>
<text x="120" y="162.4">C : DIGITAL input after selector</text>
<text x="343" y="163.2">Match actual switch lugs</text>
<text x="343" y="164.9">by continuity.</text>
<text x="120" y="228.4">R : DIGITAL input after selector</text>
<text x="275" y="241.9">Vref = 1.245 V; raw threshold ~5 V.</text>
<text x="275" y="243.6">30k/10k + 1M feedback: ~0.1 V hysteresis.</text>
</g>
<g font-size="1.5" fill="#006464">
<text x="191.8" y="38.8">R12</text>
<text x="235.6" y="52.1">R11</text>
<text x="49.6" y="55.5">J4</text>
<text x="151.5" y="56.5">R9</text>
<text x="203.9" y="59.1">U20A</text>
<text x="93.2" y="69.9">R8</text>
<text x="110" y="70.7">TP1</text>
<text x="172.1" y="74.9">R10</text>
<text x="184.8" y="74.9">C14</text>
<text x="390" y="93.6">J7</text>
<text x="191.8" y="104.8">R17</text>
<text x="235.6" y="118.1">R16</text>
<text x="49.6" y="121.6">J5</text>
<text x="151.2" y="122.6">R14</text>
<text x="204" y="125.1">U20B</text>
<text x="93.4" y="135.9">R13</text>
<text x="110" y="136.8">TP2</text>
<text x="172.1" y="141">R15</text>
<text x="184.8" y="141">C15</text>
<text x="191.8" y="170.9">R22</text>
<text x="235.6" y="184.2">R21</text>
<text x="49.6" y="187.6">J6</text>
<text x="151.2" y="188.6">R19</text>
<text x="204" y="191.2">U20C</text>
<text x="93.4" y="202">R18</text>
<text x="110" y="202.8">TP3</text>
<text x="172.1" y="207">R20</text>
<text x="184.8" y="207">C16</text>
<text x="184.8" y="240.1">R23</text>
<text x="46.5" y="247">U20D</text>
<text x="94.8" y="247.1">U20E</text>
<text x="136.6" y="252.7">C17</text>
<text x="184.8" y="257.8">R24</text>
<text x="233.1" y="257.8">C18</text>
</g>
<g font-size="1.5" fill="#840000">
<text x="329.3" y="57.8">D3 CQ_L</text>
<text x="329.3" y="123.9">D4 CQ_C</text>
<text x="329.3" y="189.9">D5 CQ_R</text>
</g>
<g font-size="1.3" fill="#006464">
<text x="191.1" y="40.9">1M 1%</text>
<text x="229.6" y="38.6">+3V3</text>
<text x="46.3" y="57.7">B4B-XH-A | L</text>
<text x="150.3" y="58.7">30k 1%</text>
<text x="235.7" y="54.2">4.7k</text>
<text x="327.4" y="60">SMCJ48A</text>
<text x="202.1" y="61.2">LM339BIDR</text>
<text x="93.3" y="72">10k</text>
<text x="108.4" y="72.9">TEACH L</text>
<text x="172.5" y="77.1">10k 1%</text>
<text x="185.6" y="77.1">1n 50V C0G</text>
<text x="87.5" y="88.2">GND</text>
<text x="328.8" y="85.7">GND</text>
<text x="166.2" y="93.3">GND</text>
<text x="178.9" y="93.3">GND</text>
<text x="385" y="95.8">B9B-XH-A | selector</text>
<text x="191.1" y="107">1M 1%</text>
<text x="229.6" y="104.6">+3V3</text>
<text x="46.2" y="123.7">B4B-XH-A | C</text>
<text x="150.3" y="124.7">30k 1%</text>
<text x="235.7" y="120.3">4.7k</text>
<text x="202.1" y="127.3">LM339BIDR</text>
<text x="327.4" y="126">SMCJ48A</text>
<text x="93.3" y="138.1">10k</text>
<text x="108.4" y="138.9">TEACH C</text>
<text x="172.5" y="143.1">10k 1%</text>
<text x="185.6" y="143.1">1n 50V C0G</text>
<text x="87.5" y="154.3">GND</text>
<text x="328.8" y="151.7">GND</text>
<text x="166.2" y="159.4">GND</text>
<text x="178.9" y="159.4">GND</text>
<text x="191.1" y="173">1M 1%</text>
<text x="229.6" y="170.7">+3V3</text>
<text x="46.2" y="189.7">B4B-XH-A | R</text>
<text x="150.3" y="190.8">30k 1%</text>
<text x="235.7" y="186.3">4.7k</text>
<text x="202.1" y="193.3">LM339BIDR</text>
<text x="327.4" y="192">SMCJ48A</text>
<text x="93.3" y="204.1">10k</text>
<text x="108.4" y="205">TEACH R</text>
<text x="172.5" y="209.2">10k 1%</text>
<text x="185.6" y="209.2">1n 50V C0G</text>
<text x="87.5" y="220.3">GND</text>
<text x="328.8" y="217.8">GND</text>
<text x="166.2" y="225.4">GND</text>
<text x="178.8" y="226.6">+3V3</text>
<text x="178.9" y="225.4">GND</text>
<text x="185.4" y="242.2">16.5k 1%</text>
<text x="44.7" y="249.2">LM339BIDR</text>
<text x="92.9" y="249.2">LM339BIDR</text>
<text x="137.2" y="254.9">100n 50V</text>
<text x="185.2" y="260">10k 1%</text>
<text x="233.7" y="260">100n 10V</text>
<text x="92.5" y="274.9">GND</text>
<text x="130.6" y="271.1">GND</text>
<text x="178.9" y="276.2">GND</text>
<text x="227.2" y="276.2">GND</text>
</g>
<g font-size="1.3" fill="#840000">
<text x="27.5" y="61.5">+24V_SENS</text>
<text x="28.5" y="64.1">TEACH_L</text>
<text x="90" y="60.3">TEACH_L</text>
<text x="128.2" y="64.1">BAUM_L_DIGRAW</text>
<text x="31.1" y="69.2">CQ_L</text>
<text x="31.5" y="66.6">GND</text>
<text x="182.2" y="69.2">SENSE_REF</text>
<text x="260.2" y="66.6">BAUM_L</text>
<text x="110.3" y="84.4">TEACH_L</text>
<text x="363.2" y="99.6">BAUM_L_DIGRAW</text>
<text x="363.1" y="107.3">BAUM_C_DIGRAW</text>
<text x="368.6" y="104.7">IOL_CQ_L</text>
<text x="371.5" y="102.2">CQ_L</text>
<text x="368.5" y="112.3">IOL_CQ_C</text>
<text x="371.4" y="109.8">CQ_C</text>
<text x="363.1" y="114.9">BAUM_R_DIGRAW</text>
<text x="368.5" y="120">IOL_CQ_R</text>
<text x="371.4" y="117.4">CQ_R</text>
<text x="27.5" y="127.6">+24V_SENS</text>
<text x="28.4" y="130.1">TEACH_C</text>
<text x="90" y="126.3">TEACH_C</text>
<text x="128.1" y="130.1">BAUM_C_DIGRAW</text>
<text x="31" y="135.2">CQ_C</text>
<text x="31.5" y="132.7">GND</text>
<text x="182.2" y="135.2">SENSE_REF</text>
<text x="260.2" y="132.7">BAUM_C</text>
<text x="110.3" y="150.4">TEACH_C</text>
<text x="27.5" y="193.6">+24V_SENS</text>
<text x="28.4" y="196.2">TEACH_R</text>
<text x="90" y="192.3">TEACH_R</text>
<text x="128.1" y="196.2">BAUM_R_DIGRAW</text>
<text x="31" y="201.2">CQ_R</text>
<text x="31.5" y="198.7">GND</text>
<text x="182.2" y="201.2">SENSE_REF</text>
<text x="260.2" y="198.7">BAUM_R</text>
<text x="110.3" y="216.5">TEACH_R</text>
<text x="95.1" y="239.3">+24V_SENS</text>
<text x="133.2" y="243.1">+24V_SENS</text>
<text x="172" y="250.8">SENSE_REF</text>
<text x="24.7" y="257.1">SENSE_REF</text>
<text x="29" y="252">GND</text>
</g>
</g></defs>
<path d="M0 0h420v297h-420z" fill="#f5f4ef"/>
<path d="M0 0h420v297h-420z" fill="none" stroke="#f5f4ef" stroke-width=".18"/>
<g fill="none" stroke="#840000" stroke-width=".18">
<path d="M10 10h400v277h-400zM12 12h396v273h-396zM60 10v2M110 10v2M160 10v2M210 10v2M260 10v2M310 10v2M360 10v2M10 60h2M408 60h2M148.6 63.5h1.3"/>
<path d="M154.9 63.5h1.3M10 110h2M408 110h2M10 160h2M180.3 153.7v1.2h1.3l-1.3 1.3-1.2-1.3h1.2M180.3 153.7h.1M408 160h2M10 210h2M408 210h2M10 260h2M300 253h108v32h-108zM408 260h2"/>
<path d="M180.3 270.5v1.3h1.3l-1.3 1.2-1.2-1.2h1.2M180.3 270.5h.1M300 278.5h108M300 274.5h108M300 268.5h108M308.2 279.3l.5 1.5M309.1 279.3h.9l-.5 .6 .4 .1v.6l-.2 .2h-.4l-.2-.2M317.9 269.7l.1 .9 .4 .1 .2-.2M318.6 269.7v1M319.3 269.8l.4-.1 .2 .2M319.3 269.7v1M319.9 269.9l.3-.2 .3 .1 .1 .9"/>
<path d="M319.9 269.9v.8M320 278.5v3M321.2 270.2l.7-.2v-.2l-.5-.1-.2 .2 .1 .7h.6M322.6 269.7v1M323 269.7l-.3 .1-.1 .2M323.7 273.2l.2 .2 .5-.1M323.7 272.5h.6l.1 .9M324.4 272.7l-.5 .1-.2 .2M324.6 269.1l-1.3 1.9M325.7 272.5l-.4-.1-.3 .3v.4l.2 .2h.5M325.7 271.9v1.5M326.1 273.5h1.1"/>
<path d="M328.1 272.5l-.4-.1-.2 .2 .1 .2 .5 .2v.3h-.6M329.4 272.5l-.4-.1-.3 .3v.4l.2 .2h.5M330.1 272.5l.2-.1 .4 .1v.9M330.1 271.9v1.5M337.8 279.9l.1-.5 .3-.1a.8 .8 0 0 1 .5 .7 .8 .8 0 0 1-.5 .8l-.3-.2-.1-.4M340.1 279.9l-.3 .3h-.3l-.3-.3 .2-.5 .4-.1 .2 .1a.99 .99 0 0 1-.3 1.4h-.3M342.5 279.7l.4-.4v1.5M344.1 279.4l.2-.1a.8 .8 0 0 1 .5 .7 .8 .8 0 0 1-.5 .8l-.2-.2-.2-.4zM353.5 263.7l.4 1 .3-1M354.8 263.8h.6v.9M355.4 264l-.5 .1a.29 .29 0 0 0-.2 .3 .29 .29 0 0 0 .2 .3l.5-.1M356.2 263.2v1.3l.2 .2"/>
<path d="M356.9 263.2v.1M356.9 263.7v1M358.3 263.8l-.4-.1-.3 .3v.4l.1 .2h.6M358.3 263.2v1.5M359 263.8h.6l.1 .9M359.7 264l-.5 .1a.29 .29 0 0 0-.3 .3 .29 .29 0 0 0 .3 .3l.5-.1M360.2 263.7h.5M360.4 263.2v1.3l.3 .2M361.2 263.2v.1M361.2 263.7v1M361.9 263.8l.3-.1 .4 .1 .1 .6-.2 .2-.3 .1-.3-.2zM363.3 263.8l.2-.1 .4 .1v.9"/>
<path d="M363.3 263.7v1M365.8 263.7v1M366.2 263.7l-.3 .1-.1 .2M366.7 264.2l.7-.2-.1-.2-.4-.1-.2 .2v.7h.6M368.7 263.8l-.5-.1-.3 .3v.4l.2 .2h.6M368.7 263.7v1.5M369.4 263.7v.9l.4 .1 .2-.2M370 263.7v1M370.7 263.2v.1M370.7 263.7v1M371.4 263.7v1M371.9 263.7l-.3 .1-.2 .2"/>
<path d="M372.3 264.2l.7-.2-.1-.2-.4-.1-.2 .2 .1 .7h.5M374.3 263.8l-.4-.1-.3 .3v.4l.1 .2h.6M374.3 263.2v1.5M384 278.5v6.5M60 285v2M110 285v2M160 285v2M210 285v2M260 285v2M300 281.5h108M307.9 280.4h.7M310 285v2"/>
<path d="M317.9 283.4v.2M318.7 282.2l.2-.1a.8 .8 0 0 1 .5 .7 .8 .8 0 0 1-.5 .8l-.2-.2-.2-.4zM320 283.4v.2M321 282l-.3 1.1h.9M321.4 282.6v1M340.7 280.2h1.2M342.5 280.8h.9M360 285v2M393.3 283.6h.9M393.3 282.5l.4-.4v1.5M394.9 282.2l.2-.1a.8 .8 0 0 1 .5 .7 .8 .8 0 0 1-.5 .8l-.2-.2-.2-.4z"/>
</g>
<path d="M321.5 266.7l.4 1 .4-1M322.8 266.2v.1M322.8 266.7v1M325 266v2.2M327.1 266.2h.9l-.5 .6 .5 .1v.6l-.2 .2h-.5l-.2-.2M329.8 266.2v1.5M330 267.1l.4 .6M330.4 266.7l-.6 .6M331.7 266.8l-.4-.1-.3 .3v.4l.1 .2h.6M331.7 266.7v1.2l-.3 .3-.4-.1M394.5 279.4l.3-.1a.8 .8 0 0 1 .5 .7 .8 .8 0 0 1-.5 .8l-.3-.2-.1-.4zM393.8 280.6v.2" fill="none" stroke="#840000" stroke-width=".3"/>
<g fill="none" stroke="#840000" stroke-width=".4">
<path d="M350.5 276l.5-.1 .3 .3M351.3 276.2a.5 .5 0 0 1 .8-.2l-.1 1.2M351.3 276.2l-.2 1M353.1 276.1a.52 .52 0 0 1 .5-.2 .52 .52 0 0 1 .4 .4v.5a.55 .55 0 0 1-.6 .4 .55 .55 0 0 1-.5-.4zM355.8 276a.66 .66 0 0 0-1 .3l-.1 .5 .2 .3 .1 .1 .6-.1M355.9 275.2l-.3 2M356.6 276.5l.9-.2v-.3l-.2-.1-.6 .1-.2 .9 .3 .3 .5-.1M360.6 276a.49 .49 0 0 0-.8 .3l.1 .1 .6 .2 .1 .3-.3 .3-.6-.1M361.4 276.5l1-.2-.1-.3-.1-.1-.6 .1-.2 .9 .2 .3 .6-.1M363.4 275.2l-.2 1.7 .2 .3M364.2 276.5l1-.2-.1-.3-.2-.1-.6 .1-.2 .9 .3 .3 .6-.1M366.9 276a.66 .66 0 0 0-1 .3v.5l.1 .3 .2 .1 .6-.1"/>
<path d="M367.5 275.9h.8M367.9 275.2l-.2 1.7v.2l.4 .1M368.9 276.1a.52 .52 0 0 1 .5-.2 .52 .52 0 0 1 .4 .4v.5a.55 .55 0 0 1-.6 .4 .55 .55 0 0 1-.5-.4zM370.7 275.9l-.1 1.3M371.3 275.9l-.4 .1-.2 .3"/>
</g>
<path d="M149.9 62.5h5v2h-5z" fill="none" stroke="#840000" stroke-width=".25"/>
<path d="M149.8 57.7h.6M149.8 58.6l.4 .1M154.8 58.4l.2 .1-.2 .1M155 57.7l-.8 1" fill="none" stroke="#006464" stroke-width=".18"/>
<path d="M43.2 248.9l10.1 5.1-10.1 5.1z" fill="#ffffc2"/>
<path d="M230.1 50.8h2.1v5.1h-2.1zM43.2 248.9l10.1 5.1-10.1 5.1zM179.3 256.5h2.1v5.1h-2.1z" fill="none" stroke="#840000" stroke-width=".25"/>
<path d="M231.1 49.5v1.3M231.1 55.9v1.2M40.6 251.5h2.6M40.6 256.5h2.6M50.5 254.5h.6l-.6-.5 .6-.5 .5 .5-.5 .5h.5M53.3 254h2.6M180.3 255.3v1.2M180.3 261.6v1.3" fill="none" stroke="#840000" stroke-width=".18"/>
<path d="M43.7 256.6h1M184.6 259.9h.6M184.9 258.9l-.3 .3M189.6 259.7l.2 .1-.2 .1M189.8 258.9l-.8 1" fill="none" stroke="#006464" stroke-width=".18"/>
<path d="M200.7 61l10.1 5-10.1 5.1z" fill="#ffffc2"/>
<path d="M200.7 61l10.1 5-10.1 5.1z" fill="none" stroke="#840000" stroke-width=".25"/>
<path d="M198.1 63.5h2.6M198.1 68.6h2.6M208 66.5h.5l-.5-.5 .5-.5 .5 .5-.5 .5h.5M210.8 66h2.6" fill="none" stroke="#840000" stroke-width=".18"/>
<path d="M201.2 68.7h1" fill="none" stroke="#006464" stroke-width=".18"/>
<path d="M387.3 97.8h2.6v22.8h-2.6z" fill="#ffffc2"/>
<path d="M190.5 44.7h5.1v2h-5.1zM387.3 97.8h2.6v22.8h-2.6z" fill="none" stroke="#840000" stroke-width=".25"/>
<g fill="none" stroke="#840000" stroke-width=".18">
<path d="M231.1 39.4l-.7 1.2M231.1 39.4l.8 1.2M231.1 39.4v2.5M189.2 45.7h1.3M195.6 45.7h1.2M231.1 41.9h.1M109.2 73.7v2.5M180.3 72.4v2.8M180.3 77.2v2.8M180.3 87.6v1.3h1.3l-1.3 1.3-1.2-1.3h1.2M180.3 87.6h.1M383.5 99.1h3.8"/>
<path d="M387.3 98.9h1.3v.3h-1.3zM231.1 107.9h.1M231.1 105.4v2.5M231.1 105.4l-.7 1.3M231.1 105.4l.8 1.3M383.5 101.6h3.8M383.5 104.1h3.8M383.5 106.7h3.8M383.5 109.2h3.8M383.5 111.8h3.8M383.5 114.3h3.8M383.5 116.8h3.8"/>
<path d="M383.5 119.4h3.8M387.3 101.5h1.3v.2h-1.3zM387.3 104h1.3v.3h-1.3zM387.3 106.6h1.3v.2h-1.3zM387.3 109.1h1.3v.2h-1.3zM387.3 111.6h1.3v.3h-1.3zM387.3 114.2h1.3v.2h-1.3zM387.3 116.7h1.3v.3h-1.3zM387.3 119.3h1.3v.2h-1.3z"/>
<circle cx="109.2" cy="72.9" r=".76"/>
</g>
<g fill="none" stroke="#006464" stroke-width=".18">
<path d="M184.6 77.1h.6M184.6 76.3l.3-.2v1M193.1 76.6h.2v.4l-.3 .1-.2-.2M193.3 76.1h-.3l-.2 .1M382.5 94.7h.3l.2 .2-.2 .3 .2 .1v.2l-.1 .2h-.4zM382.5 95.2h.3M384 95.1l-.2 .2h-.3v-.5l.3-.1 .2 .2v.6l-.2 .2h-.3M384.4 95.2h.4M384.8 94.7h-.4v1h.4M397 95h.4M397.1 94.7v.9l.3 .1M397.7 95.1l.2-.1 .2 .1v.6l-.4-.1z"/>
<path d="M398.6 95v.7M398.9 95l-.3 .2"/>
</g>
<path d="M178.3 75.4h4.1M178.3 77h4.1" fill="none" stroke="#840000" stroke-width=".51"/>
<path d="M200.7 127l10.1 5.1-10.1 5.1z" fill="#ffffc2"/>
<path d="M87.9 68.6h2v5.1h-2zM166.6 73.7h2.1v5h-2.1zM328.9 67.3h2.6v.5M330.2 67.3l1.3 2.5h-2.6zM190.5 110.7h5.1v2.1h-5.1zM230.1 116.8h2.1v5.1h-2.1zM200.7 127l10.1 5.1-10.1 5.1zM149.9 194.6h5v2h-5zM328.9 199.4h2.6v.5M330.2 199.4l1.3 2.5h-2.6z" fill="none" stroke="#840000" stroke-width=".25"/>
<g fill="none" stroke="#840000" stroke-width=".18">
<path d="M88.9 67.3v1.3M88.9 73.7v1.2M167.6 72.4v1.3M167.6 78.7v1.3M330.2 64.8v7.6M88.9 82.5v1.3h1.3l-1.3 1.3-1.3-1.3h1.3M88.9 82.5h.1M167.6 87.6v1.3h1.3l-1.3 1.3-1.2-1.3h1.2M167.6 87.6h.1M330.2 80v1.3h1.3l-1.3 1.2-1.3-1.2h1.3M330.2 80h.1M189.2 111.8h1.3"/>
<path d="M195.6 111.8h1.2M231.1 115.6v1.2M180.3 138.4v2.8M198.1 129.5h2.6M198.1 134.6h2.6M208 132.6h.5l-.5-.5 .5-.5 .5 .5-.5 .5h.5M210.8 132.1h2.6M231.1 121.9v1.3M180.3 143.3v2.7M330.2 146v1.3h1.3l-1.3 1.3-1.3-1.3h1.3M330.2 146h.1M148.6 195.6h1.3"/>
<path d="M154.9 195.6h1.3M330.2 196.8v7.7M109.2 205.7v2.6M330.2 212.1v1.3h1.3l-1.3 1.2-1.3-1.2h1.3M330.2 212.1h.1M94 246.4v3.8M94 257.8v3.8M132.1 250.2v2.8M132.1 255v2.8M94 269.2v1.3h1.2l-1.2 1.3-1.3-1.3h1.3M94 269.2h.1M132.1 265.4v1.3h1.2l-1.2 1.3-1.3-1.3h1.3"/>
<path d="M132.1 265.4h.1"/>
<circle cx="109.2" cy="205" r=".76"/>
</g>
<g fill="none" stroke="#006464" stroke-width=".18">
<path d="M171.9 77.1h.6M172.2 76.1l-.3 .2M176.9 76.8l.2 .1-.2 .1M177.1 76.1l-.8 1M201.2 134.7h1M184.6 143.1h.6M184.6 142.4l.3-.3v1M193.1 142.7h.2v.3l-.3 .1-.2-.1M193.3 142.1h-.3l-.2 .1M149.8 189.7h.6M149.8 190.6l.4 .1M154.8 190.5l.2 .1-.2 .1"/>
<path d="M155 189.7l-.8 1M94.1 255.2v1M136.4 254.9h.5M136.4 254.1l.2-.2v1M142.7 253.9l.3 1 .4-1"/>
</g>
<path d="M178.3 141.5h4.1M178.3 143h4.1M130 253.2h4.1M130 254.8h4.1" fill="none" stroke="#840000" stroke-width=".51"/>
<path d="M47 125.7h2.5v10.2h-2.5z" fill="#ffffc2"/>
<path d="M47 125.7h2.5v10.2h-2.5zM87.9 134.6h2v5.1h-2zM149.9 128.5h5v2.1h-5zM166.6 139.7h2.1v5.1h-2.1zM166.6 205.7h2.1v5.1h-2.1z" fill="none" stroke="#840000" stroke-width=".25"/>
<g fill="none" stroke="#840000" stroke-width=".18">
<path d="M43.2 127h3.8M43.2 129.5h3.8M43.2 132.1h3.8M43.2 134.6h3.8M47 126.9h1.3v.2h-1.3zM47 129.4h1.3v.3h-1.3zM47 132h1.3v.2h-1.3zM47 134.5h1.3v.2h-1.3zM88.9 133.4v1.2M88.9 139.7v1.3M109.2 139.7v2.5M148.6 129.5h1.3"/>
<path d="M154.9 129.5h1.3M167.6 138.4v1.3M88.9 148.6v1.3h1.3l-1.3 1.2-1.3-1.2h1.3M88.9 148.6h.1M167.6 144.8v1.3M167.6 219.7v1.3h1.3l-1.3 1.3-1.2-1.3h1.2M167.6 219.7h.1M167.6 204.5v1.2M167.6 210.8v1.3M180.3 204.5v2.8M180.3 209.3v2.8M180.3 229.9h.1"/>
<path d="M180.3 227.3v2.6M180.3 227.3l-.7 1.3M180.3 227.3l.8 1.3"/>
<circle cx="109.2" cy="138.9" r=".76"/>
</g>
<g fill="none" stroke="#006464" stroke-width=".18">
<path d="M44.6 122.7h.4l.1 .1-.1 .3 .1 .1 .1 .3-.2 .2h-.4zM44.6 123.1h.4M45.8 122.6l-.2 .7h.6M56 122.7a.44 .44 0 0 0-.7 .5 .44 .44 0 0 0 .7 .4M149.8 123.7h.6M149.8 124.6l.4 .1M154.8 124.5l.2 .1h-.2M155 123.7l-.8 1M171.9 143.1h.6M172.2 142.1l-.3 .3M176.9 142.9l.2 .1h-.2M177.1 142.1l-.8 1"/>
<path d="M171.9 209.1h.6M172.2 208.1l-.3 .3M176.9 208.9l.2 .1-.2 .1M177.1 208.1l-.8 1M184.6 209.1h.6M184.6 208.4l.3-.3v1M193.1 208.7h.2v.4h-.3l-.2-.1M193.3 208.2l-.3-.1-.2 .2"/>
</g>
<path d="M178.3 207.5h4.1M178.3 209h4.1" fill="none" stroke="#840000" stroke-width=".51"/>
<path d="M47 59.7h2.5v10.2h-2.5z" fill="#ffffc2"/>
<path d="M47 59.7h2.5v10.2h-2.5z" fill="none" stroke="#840000" stroke-width=".25"/>
<path d="M43.2 61h3.8M43.2 63.5h3.8M43.2 66h3.8M43.2 68.6h3.8M47 60.8h1.3v.3h-1.3zM47 63.4h1.3v.2h-1.3zM47 65.9h1.3v.3h-1.3zM47 68.5h1.3v.2h-1.3z" fill="none" stroke="#840000" stroke-width=".18"/>
<path d="M44.7 56.6h.3l.2 .2-.2 .3 .2 .1 .1 .2-.2 .2h-.4zM44.7 57.1h.3M45.9 56.6l-.2 .7h.6M55.5 56.6v1h.5" fill="none" stroke="#006464" stroke-width=".18"/>
<path d="M47 191.8h2.5v10.1h-2.5z" fill="#ffffc2"/>
<path d="M328.9 133.4h2.6v.5M330.2 133.4l1.3 2.5h-2.6zM190.5 176.8h5.1v2h-5.1zM47 191.8h2.5v10.1h-2.5zM230.1 182.9h2.1v5.1h-2.1zM87.9 200.7h2v5h-2zM179.3 238.8h2.1v5h-2.1z" fill="none" stroke="#840000" stroke-width=".25"/>
<g fill="none" stroke="#840000" stroke-width=".18">
<path d="M330.2 130.8v7.6M167.6 153.7v1.2h1.3l-1.3 1.3-1.2-1.3h1.2M167.6 153.7h.1M189.2 177.8h1.3M195.6 177.8h1.2M231.1 174h.1M231.1 171.5l-.7 1.2M231.1 171.5l.8 1.2M231.1 171.5v2.5M43.2 193h3.8M43.2 195.6h3.8M43.2 198.1h3.8"/>
<path d="M47 192.9h1.3v.3h-1.3zM47 195.5h1.3v.2h-1.3zM47 198h1.3v.2h-1.3zM88.9 199.4v1.3M231.1 181.6v1.3M231.1 188v1.2M43.2 200.7h3.8M47 200.5h1.3v.3h-1.3zM88.9 214.6v1.3h1.3l-1.3 1.3-1.3-1.3h1.3M88.9 214.6h.1M88.9 205.7v1.3M180.3 219.7v1.3h1.3l-1.3 1.3-1.2-1.3h1.2"/>
<path d="M180.3 219.7h.1M180.3 237.5v1.3M180.3 243.8v1.3M228.6 255.3v2.8M228.6 270.5v1.3h1.3l-1.3 1.2-1.3-1.2h1.3M228.6 270.5h.1M228.6 260.1v2.8"/>
</g>
<g fill="none" stroke="#006464" stroke-width=".18">
<path d="M44.6 188.7h.4l.1 .2-.1 .3 .1 .1 .1 .2-.2 .2h-.4zM44.6 189.2h.4M45.8 188.6l-.2 .8h.6M55.4 189.2h.5v-.4l-.5-.1v1M55.6 189.2l.4 .5M184.6 242.2h.6M184.6 241.4l.3-.2v1M191.2 241.2l-.7 1M232.9 259.9h.5M232.9 259.2l.3-.3v1M239.2 258.9l.3 1 .4-1"/>
<circle cx="191.1" cy="242" r=".14"/>
</g>
<path d="M226.6 258.3h4M226.6 259.8h4" fill="none" stroke="#840000" stroke-width=".51"/>
<path d="M200.7 193l10.1 5.1-10.1 5.1z" fill="#ffffc2"/>
<path d="M200.7 193l10.1 5.1-10.1 5.1z" fill="none" stroke="#840000" stroke-width=".25"/>
<g fill="none" stroke="#840000" stroke-width=".18">
<path d="M25 60h9.7l.9 1-.9 1h-9.7l-.9-1zM89.8 58.7h7.2l.8 1-.8 1h-7.2l-.9-1zM331.1 56.1h4.6l.9 1.1-.9 1h-4.6l-.9-1zM26 61.1h.7M26.3 60.7v.8M27.5 62.5h7.2l.9 1-.9 1h-7.2l-.9-1zM30 67.6h4.7l.9 1-.9 1h-4.7l-.9-1zM30.6 65h4.1l.9 1-.9 1h-4.1l-.9-1zM127.2 62.5h12.9l.9 1-.9 1h-12.9l-.9-1zM180.3 67.6h9.3l.9 1-.9 1h-9.3l-.9-1zM181.8 68.2h-.6v.3l.5 .2 .1 .2-.2 .2h-.4M260 65h6.6l.9 1-.9 1h-6.6l-.9-1z"/>
<path d="M110.1 82.8h7.2l.9 1-.9 1h-7.2l-.9-1zM362.1 98.1h12.9l.9 1-.9 1h-12.9l-.8-1zM361.9 105.7h13.1l.9 1-.9 1h-13.1l-.8-1zM361.9 113.3h13.1l.9 1-.9 1h-13.1l-.8-1zM367.1 110.8h7.9l.9 1-.9 1h-7.9l-.9-1zM367.1 118.4h7.9l.9 1-.9 1h-7.9l-.9-1zM367.3 103.1h7.7l.9 1-.9 1h-7.7l-.9-1zM368 111.3v1M368 118.9v1M370.2 108.2h4.8l.9 1-.9 1h-4.8l-.9-1zM370.2 115.8h4.8l.9 1-.9 1h-4.8l-.9-1zM370.4 100.6h4.6l.9 1-.9 1h-4.6l-.9-1z"/>
<path d="M25 126h9.7l.9 1-.9 1h-9.7l-.9-1zM26 127.1h.7M26.3 126.8v.7M27.3 128.5h7.4l.9 1-.9 1h-7.4l-.9-1zM29.8 133.6h4.9l.9 1-.9 1h-4.9l-.8-1zM30.6 131.1h4.1l.9 1-.9 1h-4.1l-.9-1zM89.8 124.7h7.4l.8 1-.8 1h-7.4l-.9-1zM127 128.5h13.1l.9 1-.9 1h-13.1l-.9-1zM180.3 133.6h9.3l.9 1-.9 1h-9.3l-.9-1zM181.8 134.2h-.6v.3l.5 .2 .1 .3-.2 .1h-.4M260 131.1h6.8l.9 1-.9 1h-6.8l-.9-1zM331.1 122.2h4.8l.9 1-.9 1h-4.8l-.9-1z"/>
<path d="M110.1 148.9h7.4l.9 1-.9 1h-7.4l-.9-1zM25 192h9.7l.9 1-.9 1h-9.7l-.9-1zM26 193.2h.7M26.3 192.8v.8M27.3 194.6h7.4l.9 1-.9 1h-7.4l-.9-1zM29.8 199.7h4.9l.9 1-.9 1h-4.9l-.8-1zM30.6 197.1h4.1l.9 1-.9 1h-4.1l-.9-1zM89.8 190.8h7.4l.8 1-.8 1h-7.4l-.9-1zM127 194.6h13.1l.9 1-.9 1h-13.1l-.9-1zM180.3 199.7h9.3l.9 1-.9 1h-9.3l-.9-1zM198.1 195.6h2.6M208 198.6h.5l-.5-.5 .5-.5 .5 .5-.5 .5h.5"/>
<path d="M210.8 198.1h2.6M260 197.1h6.8l.9 1-.9 1h-6.8l-.9-1zM331.1 188.2h4.8l.9 1-.9 1h-4.8l-.9-1zM110.1 214.9h7.4l.9 1-.9 1h-7.4l-.9-1zM180.3 219.7h.1M181.8 200.2l-.6 .1v.3l.5 .2 .1 .2-.2 .2-.4-.1M198.1 200.7h2.6M94.9 237.8h9.6l.9 1-.9 1h-9.6l-.9-1zM102.1 238.3l.5 1v-1M103.6 238.3l-.5 .1v.3l.4 .2 .1 .2-.2 .2-.3-.1M180.3 229.9h.1M22.8 255.5h9.3l.9 1-.9 1h-9.3l-.9-1z"/>
<path d="M24.3 256.1l-.6 .1v.2l.5 .2 .1 .3-.2 .2-.4-.1M28 250.5h4.1l.9 1-.9 1h-4.1l-.8-1zM133 241.6h9.6l.9 1-.9 1h-9.6l-.9-1zM140.2 242.1l.5 1v-1M141.7 242.1l-.5 .1v.3l.4 .2 .1 .2-.2 .2-.3-.1M170.1 249.2h9.4l.8 1-.8 1h-9.4l-.8-1zM171.6 249.8h-.5v.3l.4 .2 .1 .2-.2 .2h-.4"/>
</g>
<path d="M201.2 200.8h1" fill="none" stroke="#006464" stroke-width=".18"/>
<g fill="none" stroke="#009600" stroke-width=".18">
<path d="M88.9 59.7v7.6M189.2 45.7h-21.6v26.7M196.8 45.7h47v20.3M231.1 41.9v7.6M231.1 57.2v8.8M330.2 57.2v7.6M35.6 68.6h7.6M35.6 63.5h7.6M35.6 66h7.6M35.6 61h7.6M88.9 74.9v7.7M109.2 76.2v7.6"/>
<path d="M141 63.5h7.6M156.2 63.5h41.9M180.3 63.5v8.9M190.5 68.6h7.6M213.4 66h45.7M330.2 72.4v7.6M167.6 80v7.6M180.3 80v7.6M375.9 99.1h7.6M189.2 111.8h-21.6v26.6M196.8 111.8h47v20.3M231.1 108v7.6"/>
<path d="M375.9 101.6h7.6M375.9 104.1h7.6M375.9 106.7h7.6M375.9 109.2h7.6M375.9 111.8h7.6M375.9 114.3h7.6M375.9 116.8h7.6M375.9 119.4h7.6M35.6 127h7.6M35.6 129.5h7.6M35.6 132.1h7.6M35.6 134.6h7.6"/>
<path d="M88.9 125.7v7.7M141 129.5h7.6M156.2 129.5h41.9M180.3 129.5v8.9M190.5 134.6h7.6M213.4 132.1h45.7M231.1 123.2v8.9M330.2 123.2v7.6M330.2 138.4v7.7M88.9 141v7.6M109.2 142.2v7.7M167.6 146.1v7.6"/>
<path d="M180.3 146.1v7.6M189.2 177.8h-21.6v26.7M196.8 177.8h47v20.3M231.1 174v7.6M35.6 198.1h7.6M35.6 193h7.6M35.6 195.6h7.6M88.9 191.8v7.6M141 195.6h7.6M156.2 195.6h41.9M180.3 195.6v8.9M213.4 198.1h45.7"/>
<path d="M231.1 189.2v8.9M330.2 189.2v7.7M35.6 200.7h7.6M88.9 207v7.6M109.2 208.3v7.6M167.6 212.1v7.6M180.3 212.1v7.6M190.5 200.7h7.6M330.2 204.5v7.6M94 238.8v7.6M180.3 229.9v7.6M33 251.5h7.6"/>
<path d="M33 256.5h7.6M132.1 242.6v7.6M132.1 257.8v7.6M180.3 245.1v10.2M180.3 250.2h48.3v5.1M94 261.6v7.6M180.3 262.9v7.6M228.6 262.9v7.6"/>
</g>
<path d="M55.3 253.4l1.2 1.2M56.5 253.4l-1.2 1.2" fill="none" stroke="#000084" stroke-width=".18"/>
<g fill="none" stroke="#0000c2" stroke-width=".18">
<path d="M66.9 13.1h1.5M69.8 11.7l-.5 1.5h1.2M70.2 12.5v1.3M72.8 11.8v2M72.8 12.7a.5 .5 0 0 1 .9 .1v1M74.6 12.6l.2-.1 .6 .1 .1 1.2M75.5 13l-.7 .1a.39 .39 0 0 0-.3 .4 .39 .39 0 0 0 .3 .3l.7-.1M76.4 12.5v1.3M77 12.5l-.4 .1-.2 .3M77.7 12.7a.5 .5 0 0 1 .8 .1v1M77.7 12.5v1.3M79.4 13.2l.9-.2-.1-.4-.5-.1-.3 .3 .1 .9 .2 .1 .5-.1"/>
<path d="M81.9 12.6l-.5-.1-.3 .3 .1 .3 .7 .2 .1 .2-.1 .2-.2 .1-.6-.1M83.5 12.6l-.5-.1-.3 .3 .1 .3 .7 .2 .1 .2-.1 .2-.2 .1-.6-.1M66.5 22.2h.3l.1 .2v.4l-.4 .1M67.4 21.8v1l.2 .1M68 22.2l.1 .7 .4-.1M68.5 22.2v.7M69 22.6l.5-.1v-.3h-.3l-.2 .1v.6h.5M71.5 21.9a.52 .52 0 0 0-.7 .5 .52 .52 0 0 0 .8 .4v-.3h-.3M72.7 21.8v1.1l-.6-1.1v1.1M73.3 21.8a.58 .58 0 0 1 .6 .6 .58 .58 0 0 1-.6 .5zM74.5 22.9l-.1 .2M76.1 21.7l-.3 .9h.7"/>
<path d="M76.3 22.2v.7M77.8 22.2h.3l.3 .2-.2 .5h-.4M77.8 21.8v1.1M78.8 21.8v1l.2 .1M79.4 22.2h.5v.7M79.9 22.5h-.3l-.2 .2 .2 .2h.3M81 22.2h-.3l-.3 .2 .1 .5h.5M81.5 21.8v1.1M81.6 22.5l.3 .4M81.9 22.2l-.4 .4M83.9 21.9a.51 .51 0 0 0-.7 .5 .51 .51 0 0 0 .7 .4M85.3 21.7l-1 1.5"/>
<path d="M85.6 22l.3-.2a.39 .39 0 0 1 .4 .4v.4a.38 .38 0 0 1-.3 .4 .38 .38 0 0 1-.4-.4zM85.8 22.7l.6 .4M86.8 22.8v.1M86.9 24.1h.4l.1 .7M87.4 24.3l-.4 .1-.2 .1 .2 .3 .4-.1M87.9 24.1h.5v.7M87.9 24v.8M89.5 24.1l-.4-.1-.2 .3 .1 .4h.5M89.5 24v1l-.3 .2-.2-.1M90 24.4l.5-.1v-.2l-.4-.1-.1 .2v.5h.5M91.9 24.1l.3-.1 .2 .2M91.9 24v.8"/>
<path d="M92.4 24.2l.1-.2 .3 .1 .1 .7M92.4 24.2v.6M93.5 24.1l.2-.1 .3 .3v.3l-.3 .2-.3-.2zM94.9 24.1l-.3-.1-.2 .3 .1 .4h.4M94.9 23.6v1.2M95.4 24.4l.6-.1-.1-.2-.3-.1-.2 .2 .1 .5h.4M97.4 24.1l.3-.1 .2 .3v.3l-.2 .2-.4-.2zM98.4 24.1h.4l.1 .7M98.4 24v.8M99.4 23.6v1l.2 .2M99.9 24l.3 .8M100.2 24.8l-.3 .4"/>
<path d="M100.5 24l-.3 .8M101.7 24l.2 .8 .2-.5 .2 .5 .3-.8M103 24.1h.4l.1 .7M103 23.6v1.2M104 23.6v.2M104 24v.8M104.6 23.6v1l.1 .2M105.1 24.4l.6-.1-.1-.2-.3-.1-.2 .2 .1 .5h.4M107.4 24.1l-.2-.1-.2 .2v.2l.4 .1v.2h-.4M107.8 24h.5M108 23.6v1l.3 .2M108.7 24.1l.3-.1 .2 .3v.3l-.2 .2-.4-.2z"/>
<path d="M109.7 24.1l.3-.1 .2 .3-.1 .4h-.4M109.7 24v1.2M110.7 24.1l.3-.1 .3 .3-.1 .4h-.5M110.7 24v1.2M111.7 24.4l.5-.1v-.2l-.3-.1-.2 .2 .1 .5h.4M113.2 24.1l-.3-.1-.2 .3 .1 .4h.4M113.2 23.6v1.2M113.8 24.7v.1M139.8 95.9l.5 .3-.1 .2-.4-.1M140.3 95.7h-.3l-.2 .1M140.7 96l.6-.1-.1-.2h-.3l-.2 .1 .1 .5h.4M141.7 95.3v.9l.2 .2"/>
<path d="M142.3 96l.5-.1-.1-.2h-.3l-.1 .1v.5h.4M143.7 95.7h-.3l-.2 .2 .1 .4h.4M144 95.7h.5M144.2 95.3v.9l.3 .2M144.9 95.7h.2l.2 .2v.3l-.2 .2-.3-.2zM145.8 95.7v.7M146.1 95.7l-.3 .2M350.7 158.9h.4M351.1 158.6l-.2 .1v1M352.2 158.6h.7l-.4 .4 .3 .1v.5l-.1 .1-.5-.1M353.4 159v.1M353.4 159.6v.1"/>
<path d="M357.8 156.8v1.1M357.8 157.3l.4-.1v.7M358.7 157.5l.5-.1v-.2h-.3l-.2 .1 .1 .5h.4M359.7 157.5l.5-.1-.1-.2h-.3l-.1 .1v.5h.4M360.5 157.2h.4M360.6 156.8v.9l.3 .2M362.7 157.3l-.2 .2-.3-.1-.1-.5 .4-.1 .2 .2-.1 .6-.1 .2-.3 .1M363.2 157.8v.1M140.5 161.8l-.3-.1-.1 .2v.1l.4 .1v.3h-.4M140.9 162.1l.6-.1-.1-.2-.3-.1-.2 .2 .1 .5h.4M141.9 161.3v1l.2 .1M142.5 162.1l.5-.1-.1-.2-.3-.1-.1 .2v.5h.4"/>
<path d="M143.9 161.8l-.3-.1-.2 .2 .1 .5h.4M144.2 161.7h.5M144.4 161.3v1l.3 .1M145.1 161.8l.2-.1 .3 .2v.3l-.3 .2-.3-.2zM146 161.7v.7M146.3 161.7l-.3 .2M351.6 164.2v.8M351.6 164.9h-.1M352.1 164.2v.8M352.5 164.2h.4M352.6 163.9v.9l.3 .2M353.2 164.2l.2 .8"/>
<path d="M353.4 165l-.2 .3M353.7 164.2l-.3 .8M354.1 164.9v.1M358.7 162.5h-.4l-.2 .2 .1 .5h.5M359.1 162.6l.4-.1 .1 .7M359.1 162.1v1.1M359.9 160.3l-.9 1.4M361 162.1v.9l.1 .2M361.1 160.3v1.1M361.5 162.5l.1 .7 .4-.1M361.7 160.4l.2-.1a.37 .37 0 0 1 .4 .4v.4a.37 .37 0 0 1-.3 .4 .37 .37 0 0 1-.4-.4zM362 162.5v.7"/>
<path d="M362.8 161h.8M363 162.5v.9l-.2 .2-.3-.1M363 162.5h-.3l-.2 .2 .1 .5h.4M363.9 162.5h-.3l-.1 .1v.2l.4 .1v.3h-.4M364.2 160.3v1.1h.5M365 160.3v.1M365 160.7v.7M365.6 160.7v.7M365.6 160.8h.4v.6M366.6 160.3v1.1M366.7 161l.3 .4M367 160.7l-.4 .4"/>
<path d="M367.5 161.3v.1M140.5 227.8l-.3-.1-.1 .2v.2l.4 .1v.2h-.4M140.9 228.1l.6-.1-.1-.2-.3-.1-.2 .2 .1 .5h.4M141.9 227.4v.9l.2 .2M142.5 228.1l.5-.1-.1-.2-.3-.1-.1 .2v.5h.4M143.9 227.8l-.3-.1-.2 .3 .1 .4h.4M144.2 227.7h.5M144.4 227.4v.9l.3 .2M145.1 227.8l.2-.1 .3 .3v.3l-.3 .2-.3-.2zM146 227.7v.8M146.3 227.7l-.3 .3M297.3 240.8v1.1"/>
<path d="M297.3 241.3l.4-.1v.7M298.3 241.2h.3l.2 .2v.3l-.2 .2-.4-.2zM299.2 240.8v.9l.2 .2M300.3 241.2h-.3l-.2 .2 .1 .4h.4M300.3 240.8v1.1M301.4 242.6l.4 1.1 .4-1.1M302 241.4l-.5 .1M303 240.8h-.6v.5h.5l.1 .5-.2 .1-.4-.1M303.4 243h.4l.1 .7M303.4 242.6v1.1M304.2 240.8l.3 1.1 .4-1.1M304.3 242.9l.2 .8"/>
<path d="M304.5 243.7l-.2 .3M304.8 242.9l-.3 .8M305.3 241.8v.1M305.6 243l-.3-.1-.1 .2v.1l.4 .2v.2h-.4M306 242.9h.4M306.1 242.6v.9l.3 .2M306.7 243.3l.5-.1v-.2l-.4-.1-.1 .2v.5h.5M307.7 242.9v.8M308 242.9l-.3 .2M308.3 243.3l.5-.1v-.2l-.3-.1-.2 .2 .1 .5h.4M309.7 243l-.3-.1-.1 .2v.1l.4 .2v.2h-.4M310.2 242.6v.1"/>
<path d="M310.2 242.9v.8M311.1 243l-.3-.1-.1 .2v.1l.4 .2v.2h-.4M311.6 243.6v.1"/>
</g>
<circle cx="167.6" cy="63.5" r=".46" fill="#009600"/>
<circle cx="167.6" cy="63.5" r=".46" fill="none" stroke="#009600" stroke-width=".18"/>
<circle cx="167.6" cy="63.5" r=".46" fill="#009600"/>
<circle cx="167.6" cy="63.5" r=".46" fill="none" stroke="#009600" stroke-width=".18"/>
<circle cx="167.6" cy="129.5" r=".46" fill="#009600"/>
<circle cx="167.6" cy="129.5" r=".46" fill="none" stroke="#009600" stroke-width=".18"/>
<circle cx="167.6" cy="129.5" r=".46" fill="#009600"/>
<circle cx="167.6" cy="129.5" r=".46" fill="none" stroke="#009600" stroke-width=".18"/>
<circle cx="167.6" cy="195.6" r=".46" fill="#009600"/>
<circle cx="167.6" cy="195.6" r=".46" fill="none" stroke="#009600" stroke-width=".18"/>
<circle cx="180.3" cy="195.6" r=".46" fill="#009600"/>
<circle cx="180.3" cy="195.6" r=".46" fill="none" stroke="#009600" stroke-width=".18"/>
<circle cx="167.6" cy="195.6" r=".46" fill="#009600"/>
<circle cx="167.6" cy="195.6" r=".46" fill="none" stroke="#009600" stroke-width=".18"/>
<circle cx="180.3" cy="63.5" r=".46" fill="#009600"/>
<circle cx="180.3" cy="63.5" r=".46" fill="none" stroke="#009600" stroke-width=".18"/>
<circle cx="213.4" cy="198.1" r=".46" fill="#009600"/>
<circle cx="213.4" cy="198.1" r=".46" fill="none" stroke="#009600" stroke-width=".18"/>
<circle cx="180.3" cy="129.5" r=".46" fill="#009600"/>
<circle cx="180.3" cy="129.5" r=".46" fill="none" stroke="#009600" stroke-width=".18"/>
<circle cx="213.4" cy="66" r=".46" fill="#009600"/>
<circle cx="213.4" cy="66" r=".46" fill="none" stroke="#009600" stroke-width=".18"/>
<circle cx="213.4" cy="132.1" r=".46" fill="#009600"/>
<circle cx="213.4" cy="132.1" r=".46" fill="none" stroke="#009600" stroke-width=".18"/>
<circle cx="231.1" cy="132.1" r=".46" fill="#009600"/>
<circle cx="231.1" cy="132.1" r=".46" fill="none" stroke="#009600" stroke-width=".18"/>
<circle cx="231.1" cy="66" r=".46" fill="#009600"/>
<circle cx="231.1" cy="66" r=".46" fill="none" stroke="#009600" stroke-width=".18"/>
<circle cx="231.1" cy="198.1" r=".46" fill="#009600"/>
<circle cx="231.1" cy="198.1" r=".46" fill="none" stroke="#009600" stroke-width=".18"/>
<circle cx="180.3" cy="250.2" r=".46" fill="#009600"/>
<circle cx="180.3" cy="250.2" r=".46" fill="none" stroke="#009600" stroke-width=".18"/>
<use href="#words"/>
</svg>
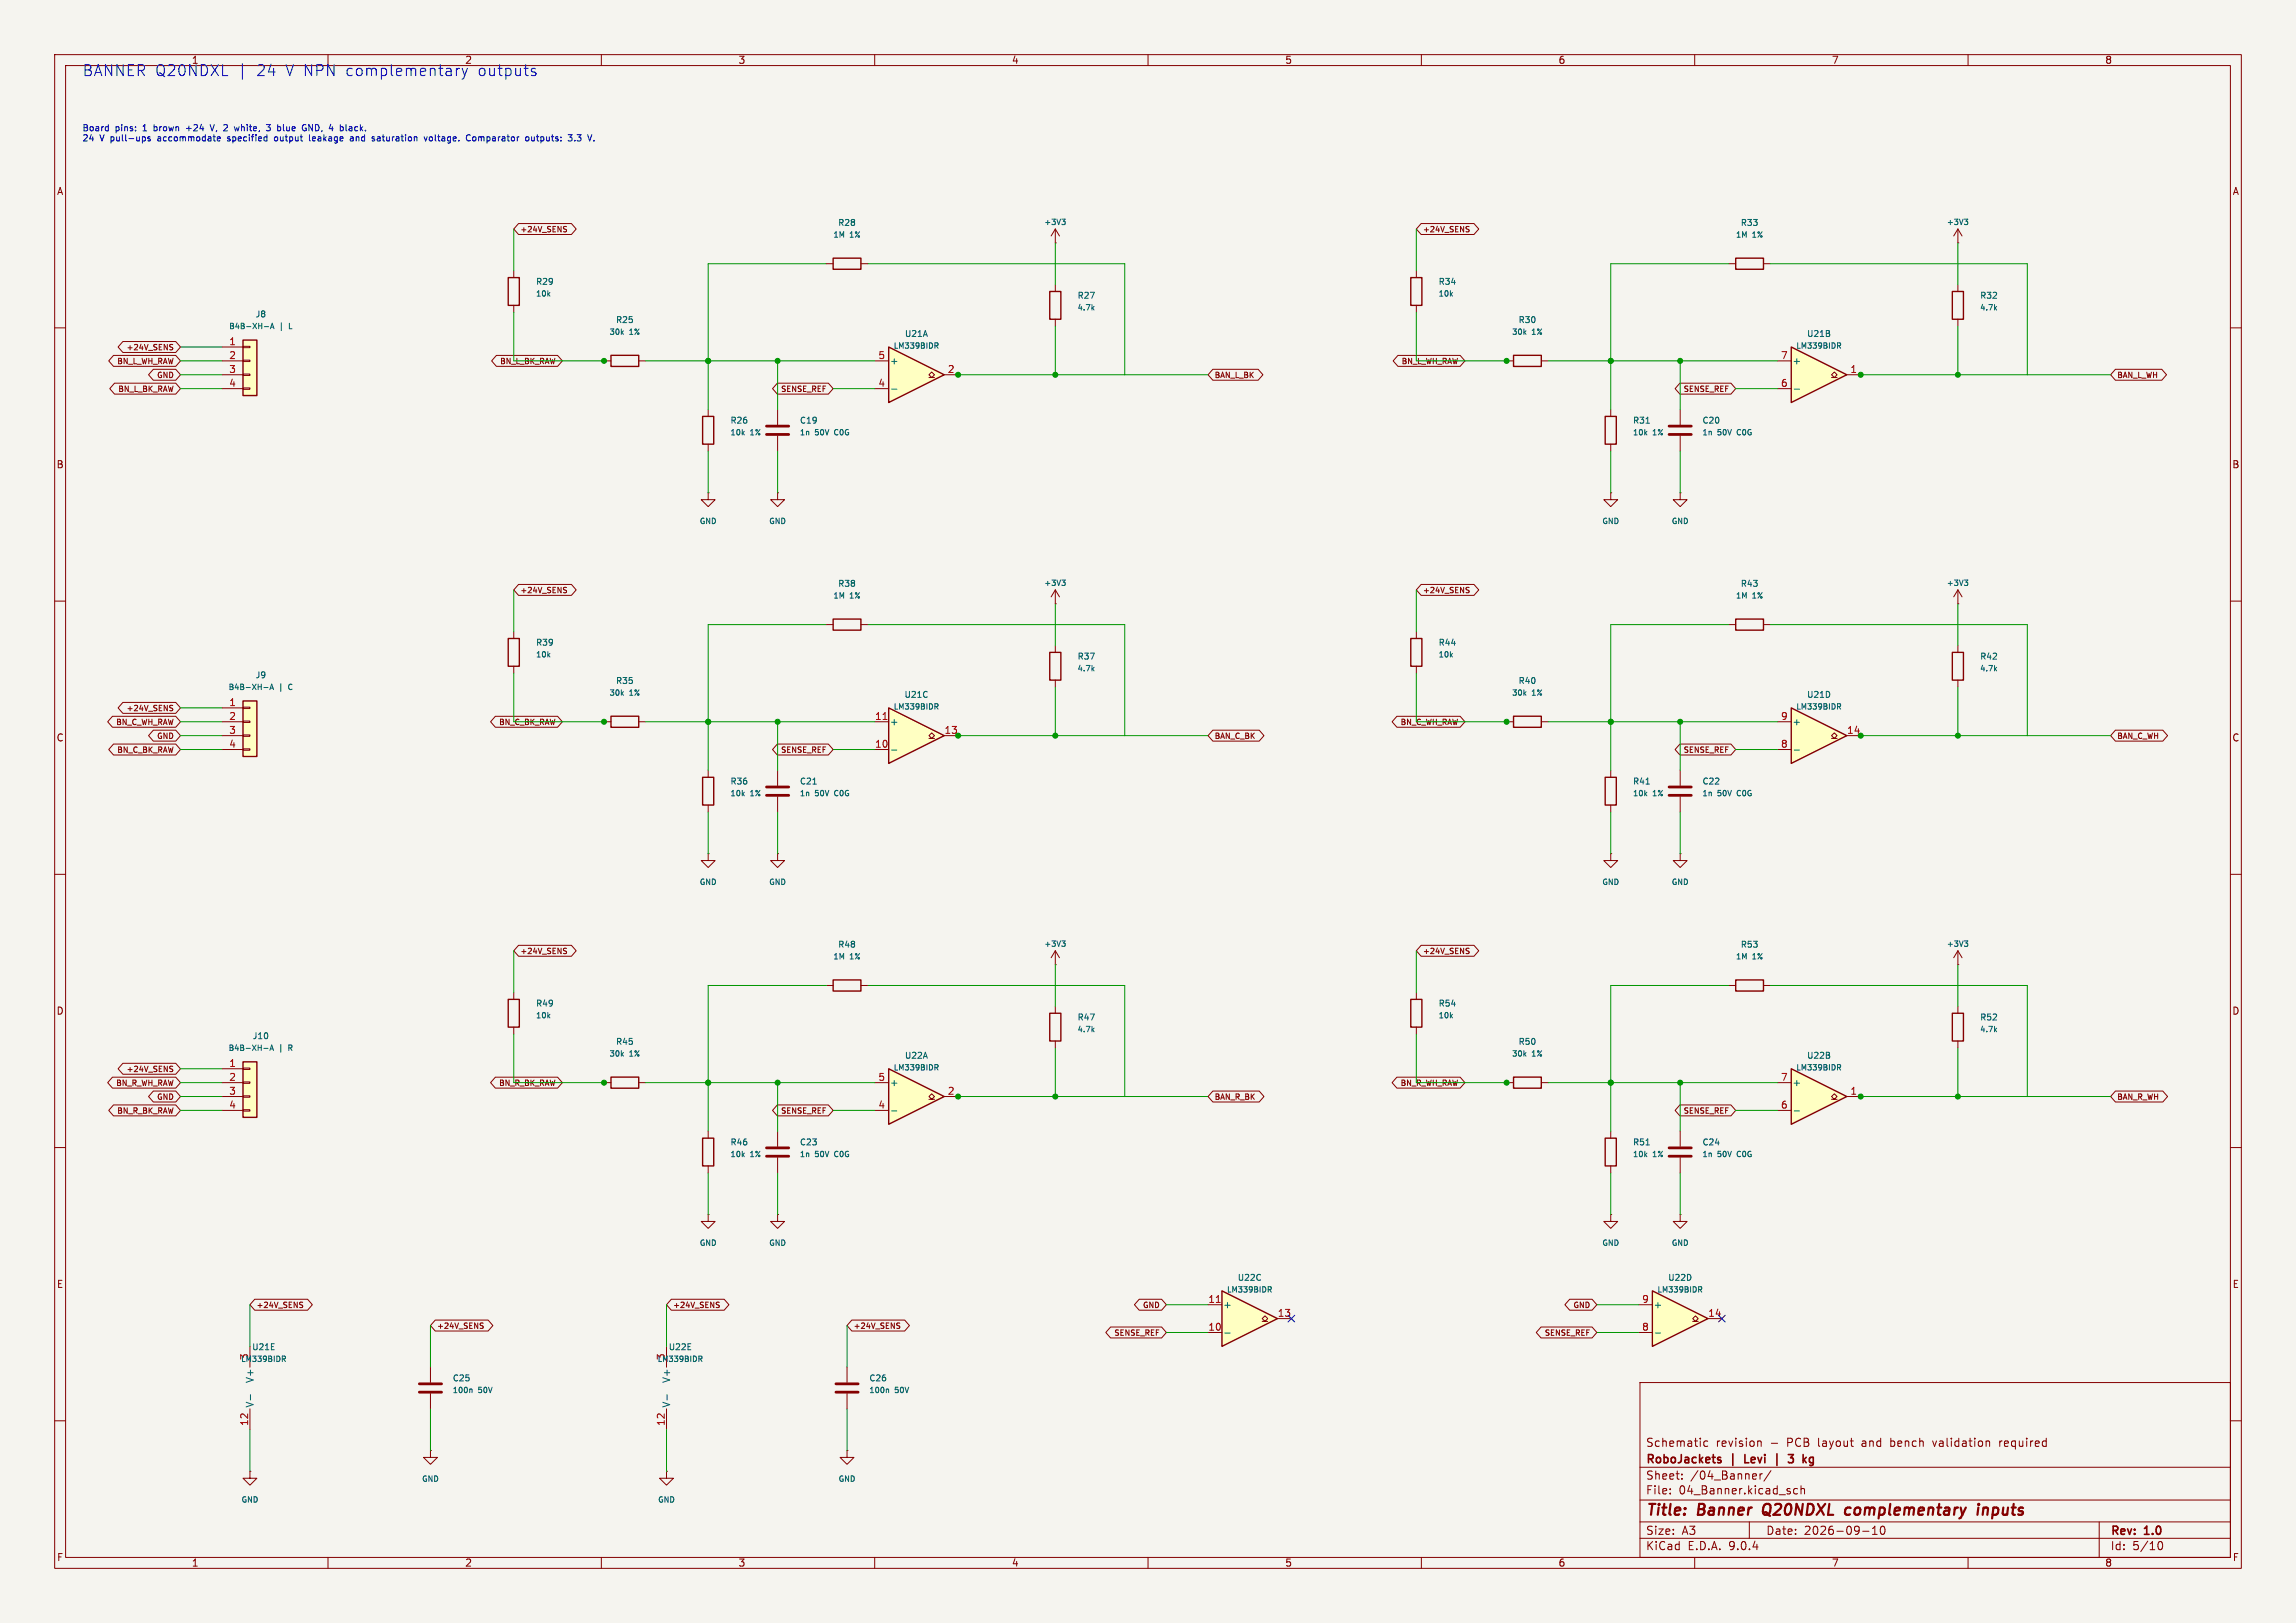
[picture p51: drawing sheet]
<svg xmlns="http://www.w3.org/2000/svg" width="420mm" height="297mm" viewBox="0 0 420 297" stroke-linecap="round" stroke-linejoin="round" font-family="sans-serif">
<defs><g id="words">
<text font-size="2.7" fill="#0000c2" x="15" y="13.8">BANNER Q20NDXL | 24 V NPN complementary outputs</text>
<text font-size="2.7" fill="#840000" x="301" y="277.3">Title: Banner Q20NDXL complementary inputs</text>
<g font-size="2" fill="#840000">
<text x="301" y="267.8">RoboJackets | Levi | 3 kg</text>
<text x="301" y="264.8">Schematic revision - PCB layout and bench validation required</text>
<text x="301" y="273.5">File: 04_Banner.kicad_sch</text>
<text x="301" y="270.8">Sheet: /04_Banner/</text>
<text x="301" y="280.9">Size: A3</text>
<text x="323" y="280.9">Date: 2026-09-10</text>
<text x="386" y="280.9">Rev: 1.0</text>
<text x="301" y="283.7">KiCad E.D.A. 9.0.4</text>
<text x="386" y="283.7">Id: 5/10</text>
</g>
<g font-size="1.7" fill="#840000">
<text x="35" y="11.6">1</text>
<text x="85" y="11.6">2</text>
<text x="135" y="11.6">3</text>
<text x="185" y="11.6">4</text>
<text x="235" y="11.6">5</text>
<text x="285" y="11.6">6</text>
<text x="335" y="11.6">7</text>
<text x="385" y="11.6">8</text>
<text x="10.4" y="35.6">A</text>
<text x="408.4" y="35.6">A</text>
<text x="10.4" y="85.7">B</text>
<text x="408.4" y="85.7">B</text>
<text x="10.4" y="135.6">C</text>
<text x="408.4" y="135.6">C</text>
<text x="10.4" y="185.6">D</text>
<text x="408.4" y="185.6">D</text>
<text x="10.5" y="235.6">E</text>
<text x="408.5" y="235.6">E</text>
<text x="10.5" y="285.6">F</text>
<text x="35" y="286.7">1</text>
<text x="85" y="286.7">2</text>
<text x="135" y="286.7">3</text>
<text x="185" y="286.7">4</text>
<text x="235" y="286.7">5</text>
<text x="285" y="286.7">6</text>
<text x="335" y="286.7">7</text>
<text x="385" y="286.7">8</text>
<text x="408.5" y="285.6">F</text>
</g>
<g font-size="1.7" fill="#a90000">
<text x="42.1" y="63.2">1</text>
<text x="42.1" y="65.8">2</text>
<text x="160.9" y="65.8">5</text>
<text x="326" y="65.8">7</text>
<text x="42.1" y="68.3">3</text>
<text x="42.1" y="70.9">4</text>
<text x="160.9" y="70.9">4</text>
<text x="173.6" y="68.3">2</text>
<text x="326" y="70.9">6</text>
<text x="338.7" y="68.3">1</text>
<text x="42.1" y="129.3">1</text>
<text x="42.1" y="131.8">2</text>
<text x="160.4" y="131.8">11</text>
<text x="326" y="131.8">9</text>
<text x="42.1" y="134.4">3</text>
<text x="42.1" y="136.9">4</text>
<text x="160.4" y="136.9">10</text>
<text x="173.1" y="134.4">13</text>
<text x="326" y="136.9">8</text>
<text x="338.2" y="134.4">14</text>
<text x="42.1" y="195.3">1</text>
<text x="42.1" y="197.9">2</text>
<text x="160.9" y="197.9">5</text>
<text x="326" y="197.9">7</text>
<text x="42.1" y="200.4">3</text>
<text x="42.1" y="202.9">4</text>
<text x="160.9" y="202.9">4</text>
<text x="173.6" y="200.4">2</text>
<text x="326" y="202.9">6</text>
<text x="338.7" y="200.4">1</text>
<text x="221.4" y="238.5">11</text>
<text x="300.6" y="238.5">9</text>
<text x="221.4" y="243.6">10</text>
<text x="234.1" y="241">13</text>
<text x="300.6" y="243.6">8</text>
<text x="312.8" y="241">14</text>
<text x="45.5" y="260.6" transform="rotate(-90 45.5 260.6)">12</text>
<text x="121.7" y="260.6" transform="rotate(-90 121.7 260.6)">12</text>
</g>
<g font-size="1.7" fill="#006464">
<text x="162.7" y="66.7">+</text>
<text x="327.8" y="66.7">+</text>
<text x="162.7" y="132.7">+</text>
<text x="327.8" y="132.7">+</text>
<text x="162.7" y="198.8">+</text>
<text x="327.8" y="198.8">+</text>
<text x="223.6" y="239.4">+</text>
<text x="302.4" y="239.4">+</text>
<text x="45.5" y="248.7" transform="rotate(-90 45.5 248.7)">3</text>
<text x="121.7" y="248.7" transform="rotate(-90 121.7 248.7)">3</text>
<text x="46.4" y="257.7" transform="rotate(-90 46.4 257.7)">V-</text>
<text x="46.4" y="252.5" transform="rotate(-90 46.4 252.5)">V+</text>
<text x="122.6" y="257.7" transform="rotate(-90 122.6 257.7)">V-</text>
<text x="122.6" y="252.5" transform="rotate(-90 122.6 252.5)">V+</text>
</g>
<g font-size="1.5" fill="#0000c2">
<text x="15" y="23.9">Board pins: 1 brown +24 V, 2 white, 3 blue GND, 4 black.</text>
<text x="15" y="25.8">24 V pull-ups accommodate specified output leakage and saturation voltage. Comparator outputs: 3.3 V.</text>
</g>
<g font-size="1.5" fill="#006464">
<text x="153.7" y="41.3">R28</text>
<text x="318.8" y="41.3">R33</text>
<text x="98.5" y="52.1">R29</text>
<text x="263.6" y="52.1">R34</text>
<text x="47.1" y="58.1">J8</text>
<text x="113.1" y="59.1">R25</text>
<text x="197.5" y="54.6">R27</text>
<text x="278.2" y="59.1">R30</text>
<text x="362.6" y="54.6">R32</text>
<text x="165.8" y="61.6">U21A</text>
<text x="331" y="61.6">U21B</text>
<text x="134" y="77.5">R26</text>
<text x="146.7" y="77.5">C19</text>
<text x="299.1" y="77.5">R31</text>
<text x="311.8" y="77.5">C20</text>
<text x="153.7" y="107.4">R38</text>
<text x="318.8" y="107.4">R43</text>
<text x="98.5" y="118.1">R39</text>
<text x="263.6" y="118.1">R44</text>
<text x="47.1" y="124.1">J9</text>
<text x="113.1" y="125.1">R35</text>
<text x="197.5" y="120.7">R37</text>
<text x="278.2" y="125.1">R40</text>
<text x="362.6" y="120.7">R42</text>
<text x="165.9" y="127.7">U21C</text>
<text x="330.9" y="127.7">U21D</text>
<text x="134" y="143.5">R36</text>
<text x="146.7" y="143.5">C21</text>
<text x="299.1" y="143.5">R41</text>
<text x="311.8" y="143.5">C22</text>
<text x="153.7" y="173.4">R48</text>
<text x="318.8" y="173.4">R53</text>
<text x="98.5" y="184.2">R49</text>
<text x="263.6" y="184.2">R54</text>
<text x="46.7" y="190.1">J10</text>
<text x="113.1" y="191.2">R45</text>
<text x="197.5" y="186.7">R47</text>
<text x="278.2" y="191.2">R50</text>
<text x="362.6" y="186.7">R52</text>
<text x="165.8" y="193.7">U22A</text>
<text x="331" y="193.7">U22B</text>
<text x="134" y="209.6">R46</text>
<text x="146.7" y="209.6">C23</text>
<text x="299.1" y="209.6">R51</text>
<text x="311.8" y="209.6">C24</text>
<text x="226.8" y="234.3">U22C</text>
<text x="305.5" y="234.4">U22D</text>
<text x="46.5" y="247">U21E</text>
<text x="122.7" y="247.1">U22E</text>
<text x="83.2" y="252.7">C25</text>
<text x="159.4" y="252.7">C26</text>
</g>
<g font-size="1.3" fill="#006464">
<text x="191.5" y="41.2">+3V3</text>
<text x="356.6" y="41.2">+3V3</text>
<text x="153" y="43.5">1M 1%</text>
<text x="318.1" y="43.5">1M 1%</text>
<text x="98.4" y="54.2">10k</text>
<text x="197.6" y="56.8">4.7k</text>
<text x="263.5" y="54.2">10k</text>
<text x="362.7" y="56.8">4.7k</text>
<text x="43.7" y="60.2">B4B-XH-A | L</text>
<text x="112.2" y="61.2">30k 1%</text>
<text x="164" y="63.8">LM339BIDR</text>
<text x="277.3" y="61.2">30k 1%</text>
<text x="329.1" y="63.8">LM339BIDR</text>
<text x="134.4" y="79.6">10k 1%</text>
<text x="147.5" y="79.6">1n 50V C0G</text>
<text x="299.5" y="79.6">10k 1%</text>
<text x="312.6" y="79.6">1n 50V C0G</text>
<text x="128.1" y="95.9">GND</text>
<text x="140.8" y="95.9">GND</text>
<text x="293.2" y="95.9">GND</text>
<text x="305.9" y="95.9">GND</text>
<text x="191.5" y="107.2">+3V3</text>
<text x="356.6" y="107.2">+3V3</text>
<text x="153" y="109.5">1M 1%</text>
<text x="318.1" y="109.5">1M 1%</text>
<text x="98.4" y="120.3">10k</text>
<text x="197.6" y="122.8">4.7k</text>
<text x="263.5" y="120.3">10k</text>
<text x="362.7" y="122.8">4.7k</text>
<text x="43.7" y="126.2">B4B-XH-A | C</text>
<text x="112.2" y="127.3">30k 1%</text>
<text x="164" y="129.8">LM339BIDR</text>
<text x="277.3" y="127.3">30k 1%</text>
<text x="329.1" y="129.8">LM339BIDR</text>
<text x="134.4" y="145.7">10k 1%</text>
<text x="147.5" y="145.7">1n 50V C0G</text>
<text x="299.5" y="145.7">10k 1%</text>
<text x="312.6" y="145.7">1n 50V C0G</text>
<text x="128.1" y="161.9">GND</text>
<text x="140.8" y="161.9">GND</text>
<text x="293.2" y="161.9">GND</text>
<text x="305.9" y="161.9">GND</text>
<text x="191.5" y="173.2">+3V3</text>
<text x="356.6" y="173.2">+3V3</text>
<text x="153" y="175.5">1M 1%</text>
<text x="318.1" y="175.5">1M 1%</text>
<text x="98.4" y="186.3">10k</text>
<text x="197.6" y="188.9">4.7k</text>
<text x="263.5" y="186.3">10k</text>
<text x="362.7" y="188.9">4.7k</text>
<text x="43.7" y="192.3">B4B-XH-A | R</text>
<text x="112.2" y="193.3">30k 1%</text>
<text x="164" y="195.9">LM339BIDR</text>
<text x="277.3" y="193.3">30k 1%</text>
<text x="329.1" y="195.9">LM339BIDR</text>
<text x="134.4" y="211.7">10k 1%</text>
<text x="147.5" y="211.7">1n 50V C0G</text>
<text x="299.5" y="211.7">10k 1%</text>
<text x="312.6" y="211.7">1n 50V C0G</text>
<text x="128.1" y="228">GND</text>
<text x="140.8" y="228">GND</text>
<text x="293.2" y="228">GND</text>
<text x="305.9" y="228">GND</text>
<text x="225" y="236.5">LM339BIDR</text>
<text x="303.7" y="236.5">LM339BIDR</text>
<text x="44.7" y="249.2">LM339BIDR</text>
<text x="120.9" y="249.2">LM339BIDR</text>
<text x="83.8" y="254.9">100n 50V</text>
<text x="160" y="254.9">100n 50V</text>
<text x="44.3" y="274.9">GND</text>
<text x="77.3" y="271.1">GND</text>
<text x="120.5" y="274.9">GND</text>
<text x="153.5" y="271.1">GND</text>
</g>
<g font-size="1.3" fill="#840000">
<text x="95.1" y="42.5">+24V_SENS</text>
<text x="260.2" y="42.5">+24V_SENS</text>
<text x="24.9" y="64.1">+24V_SENS</text>
<text x="21.9" y="66.6">BN_L_WH_RAW</text>
<text x="22.3" y="71.7">BN_L_BK_RAW</text>
<text x="29" y="69.2">GND</text>
<text x="92.1" y="66.6">BN_L_BK_RAW</text>
<text x="144.1" y="71.7">SENSE_REF</text>
<text x="222.1" y="69.2">BAN_L_BK</text>
<text x="256.8" y="66.6">BN_L_WH_RAW</text>
<text x="309.2" y="71.7">SENSE_REF</text>
<text x="387.2" y="69.2">BAN_L_WH</text>
<text x="95.1" y="108.5">+24V_SENS</text>
<text x="260.2" y="108.5">+24V_SENS</text>
<text x="24.9" y="130.1">+24V_SENS</text>
<text x="21.8" y="132.7">BN_C_WH_RAW</text>
<text x="22.2" y="137.7">BN_C_BK_RAW</text>
<text x="29" y="135.2">GND</text>
<text x="92" y="132.7">BN_C_BK_RAW</text>
<text x="144.1" y="137.7">SENSE_REF</text>
<text x="222.1" y="135.2">BAN_C_BK</text>
<text x="256.8" y="132.7">BN_C_WH_RAW</text>
<text x="309.2" y="137.7">SENSE_REF</text>
<text x="387.2" y="135.2">BAN_C_WH</text>
<text x="95.1" y="174.6">+24V_SENS</text>
<text x="260.2" y="174.6">+24V_SENS</text>
<text x="24.9" y="196.2">+24V_SENS</text>
<text x="21.8" y="198.7">BN_R_WH_RAW</text>
<text x="22.2" y="203.8">BN_R_BK_RAW</text>
<text x="29" y="201.2">GND</text>
<text x="92" y="198.7">BN_R_BK_RAW</text>
<text x="144.1" y="203.8">SENSE_REF</text>
<text x="222.1" y="201.2">BAN_R_BK</text>
<text x="256.8" y="198.7">BN_R_WH_RAW</text>
<text x="309.2" y="203.8">SENSE_REF</text>
<text x="387.2" y="201.2">BAN_R_WH</text>
<text x="46.8" y="239.3">+24V_SENS</text>
<text x="123" y="239.3">+24V_SENS</text>
<text x="209.3" y="239.3">GND</text>
<text x="288.1" y="239.3">GND</text>
<text x="79.9" y="243.1">+24V_SENS</text>
<text x="156.1" y="243.1">+24V_SENS</text>
<text x="205" y="244.4">SENSE_REF</text>
<text x="283.8" y="244.4">SENSE_REF</text>
</g>
</g></defs>
<path d="M0 0h420v297h-420z" fill="#f5f4ef"/>
<path d="M0 0h420v297h-420z" fill="none" stroke="#f5f4ef" stroke-width=".18"/>
<g fill="none" stroke="#840000" stroke-width=".18">
<path d="M10 10h400v277h-400zM12 12h396v273h-396zM60 10v2M110 10v2M160 10v2M210 10v2M260 10v2M310 10v2M360 10v2M10 60h2M408 60h2M275.6 66h1.3"/>
<path d="M281.9 66h1.3M10 110h2M408 110h2M275.6 132.1h1.3M281.9 132.1h1.3M10 160h2M142.2 141v2.8M142.2 145.8v2.8M408 160h2M10 210h2M408 210h2M10 260h2"/>
<path d="M300 253h108v32h-108zM408 260h2M300 278.5h108M300 274.5h108M300 268.5h108M308.2 279.3l.5 1.5M309.1 279.3h.9l-.5 .6 .4 .1v.6l-.2 .2h-.4l-.2-.2M317 269.7l.2 .2v.8M317.2 270.6l-.1 .1M317.2 270l-.1 .1M317.9 269.7v1M317.9 269.8l.3-.1 .3 .1 .1 .9"/>
<path d="M319.3 269.8l.2-.1 .4 .1v.9M319.3 269.7v1M320 278.5v3M320.6 270.2l.7-.2-.1-.2-.4-.1-.2 .2 .1 .7h.5M321.9 269.7v1M322.4 269.7l-.3 .1-.2 .2M323.1 272.5h.6v.9M323.1 273.3h.6M323.7 272.7l-.6 .2M323.9 269.1l-1.2 1.9M325.1 272.5l-.4-.1-.3 .3v.4l.1 .2h.6M325.1 271.9v1.5"/>
<path d="M325.4 273.5h1.2M327.4 272.5l-.3-.1-.2 .2v.2l.5 .2v.3h-.5M328.8 272.5l-.4-.1-.3 .3v.4l.1 .2h.6M329.4 272.5l.3-.1 .3 .1 .1 .9M329.4 271.9v1.5M337.8 279.9l.1-.5 .3-.1a.8 .8 0 0 1 .5 .7 .8 .8 0 0 1-.5 .8l-.3-.2-.1-.4M340.1 279.9l-.3 .3h-.3l-.3-.3 .2-.5 .4-.1 .2 .1a.99 .99 0 0 1-.3 1.4h-.3M342.5 279.7l.4-.4v1.5M344.1 279.4l.2-.1a.8 .8 0 0 1 .5 .7 .8 .8 0 0 1-.5 .8l-.2-.2-.2-.4zM353.5 263.7l.4 1 .3-1M354.8 263.8h.6v.9M355.4 264l-.5 .1a.29 .29 0 0 0-.2 .3 .29 .29 0 0 0 .2 .3l.5-.1"/>
<path d="M356.2 263.2v1.3l.2 .2M356.9 263.2v.1M356.9 263.7v1M358.3 263.8l-.4-.1-.3 .3v.4l.1 .2h.6M358.3 263.2v1.5M359 263.8h.6l.1 .9M359.7 264l-.5 .1a.29 .29 0 0 0-.3 .3 .29 .29 0 0 0 .3 .3l.5-.1M360.2 263.7h.5M360.4 263.2v1.3l.3 .2M361.2 263.2v.1M361.2 263.7v1M361.9 263.8l.3-.1 .4 .1 .1 .6-.2 .2-.3 .1-.3-.2z"/>
<path d="M363.3 263.8l.2-.1 .4 .1v.9M363.3 263.7v1M365.8 263.7v1M366.2 263.7l-.3 .1-.1 .2M366.7 264.2l.7-.2-.1-.2-.4-.1-.2 .2v.7h.6M368.7 263.8l-.5-.1-.3 .3v.4l.2 .2h.6M368.7 263.7v1.5M369.4 263.7v.9l.4 .1 .2-.2M370 263.7v1M370.7 263.2v.1M370.7 263.7v1M371.4 263.7v1"/>
<path d="M371.9 263.7l-.3 .1-.2 .2M372.3 264.2l.7-.2-.1-.2-.4-.1-.2 .2 .1 .7h.5M374.3 263.8l-.4-.1-.3 .3v.4l.1 .2h.6M374.3 263.2v1.5M384 278.5v6.5M60 285v2M110 285v2M160 285v2M210 285v2M260 285v2M300 281.5h108M307.9 280.4h.7"/>
<path d="M310 285v2M317.9 283.4v.2M318.7 282.2l.2-.1a.8 .8 0 0 1 .5 .7 .8 .8 0 0 1-.5 .8l-.2-.2-.2-.4zM320 283.4v.2M321 282l-.3 1.1h.9M321.4 282.6v1M340.7 280.2h1.2M342.5 280.8h.9M360 285v2M393.3 283.6h.9M393.3 282.5l.4-.4v1.5M394.9 282.2l.2-.1a.8 .8 0 0 1 .5 .7 .8 .8 0 0 1-.5 .8l-.2-.2-.2-.4z"/>
</g>
<path d="M321.5 266.7l.4 1 .4-1M322.8 266.2v.1M322.8 266.7v1M325 266v2.2M327.1 266.2h.9l-.5 .6 .5 .1v.6l-.2 .2h-.5l-.2-.2M329.8 266.2v1.5M330 267.1l.4 .6M330.4 266.7l-.6 .6M331.7 266.8l-.4-.1-.3 .3v.4l.1 .2h.6M331.7 266.7v1.2l-.3 .3-.4-.1M394.5 279.4l.3-.1a.8 .8 0 0 1 .5 .7 .8 .8 0 0 1-.5 .8l-.3-.2-.1-.4zM393.8 280.6v.2" fill="none" stroke="#840000" stroke-width=".3"/>
<g fill="none" stroke="#840000" stroke-width=".4">
<path d="M352.9 276l.2-.1 .5 .1-.1 1.2M354.4 275.9h.7M354.7 275.2l-.2 1.7 .1 .2 .4 .1M355.8 276l.2-.1 .5 .1v1.2M356.6 276.3l-.7 .1a.4 .4 0 0 0-.3 .4 .4 .4 0 0 0 .2 .4l.7-.1M357.6 275.9l-.2 1.3M358.2 275.9l-.4 .1-.3 .3M358.6 275.9l.4 1.3M359 277.2l-.3 .5-.3 .2M359.6 275.9l-.6 1.3M361.9 275.9l-.2 1.3M362 275.2l-.1 .2"/>
<path d="M362 275.2l-.1 .1v.1M362 275.2v.1l-.1 .1M362.8 276.1a.49 .49 0 0 1 .9 .1l-.2 1M362.8 275.9l-.1 1.3M364.6 276l.2-.1 .6 .1 .1 .3v.5a.66 .66 0 0 1-1 .3M364.6 275.9l-.2 2M366.5 275.9l-.1 1.2a.57 .57 0 0 0 .8-.1M367.3 275.9l-.2 1.3M368 275.9h.7M368.3 275.2l-.2 1.7 .1 .2 .4 .1M370.1 276a.49 .49 0 0 0-.8 .3v.1l.7 .2v.3l-.3 .3-.5-.1"/>
</g>
<path d="M276.9 65h5v2.1h-5zM276.9 131.1h5v2h-5z" fill="none" stroke="#840000" stroke-width=".25"/>
<path d="M276.8 60.2h.6M276.8 61.1l.4 .1M281.8 61l.2 .1h-.2M282 60.2l-.8 1M276.8 126.2h.6M276.8 127.1l.4 .1M281.8 127l.2 .1-.2 .1M282 126.2l-.8 1M146.5 145.6h.6M146.5 144.9l.3-.3v1M155 145.2h.2v.4h-.3l-.2-.1M155.2 144.7l-.3-.1-.2 .2" fill="none" stroke="#006464" stroke-width=".18"/>
<path d="M140.2 144h4.1M140.2 145.5h4.1" fill="none" stroke="#840000" stroke-width=".51"/>
<path d="M162.6 63.5l10.1 5.1-10.1 5.1z" fill="#ffffc2"/>
<path d="M162.6 63.5l10.1 5.1-10.1 5.1z" fill="none" stroke="#840000" stroke-width=".25"/>
<path d="M160 66h2.6M160 71.1h2.6M169.9 69.1h.5l-.5-.5 .5-.5 .5 .5-.5 .5h.5M172.7 68.6h2.6" fill="none" stroke="#840000" stroke-width=".18"/>
<path d="M163.1 71.2h1" fill="none" stroke="#006464" stroke-width=".18"/>
<path d="M162.6 195.6l10.1 5.1-10.1 5z" fill="#ffffc2"/>
<path d="M162.6 195.6l10.1 5.1-10.1 5z" fill="none" stroke="#840000" stroke-width=".25"/>
<path d="M160 198.1h2.6M160 203.2h2.6M169.9 201.2h.5l-.5-.5 .5-.5 .5 .5-.5 .5h.5M172.7 200.7h2.6M154.9 250.2v2.8M154.9 255v2.8M78.7 265.4v1.3h1.3l-1.3 1.3-1.2-1.3h1.2M78.7 265.4h.1" fill="none" stroke="#840000" stroke-width=".18"/>
<path d="M163.1 203.3h1M159.2 254.9h.6M159.2 254.1l.3-.2v1M165.6 253.9l.3 1 .3-1" fill="none" stroke="#006464" stroke-width=".18"/>
<path d="M152.9 253.2h4.1M152.9 254.8h4.1" fill="none" stroke="#840000" stroke-width=".51"/>
<path d="M223.5 236.2l10.2 5.1-10.2 5.1z" fill="#ffffc2"/>
<path d="M192 53.3h2.1v5.1h-2.1zM317.5 47.2h5.1v2.1h-5.1zM293.6 76.2h2.1v5.1h-2.1zM317.5 113.3h5.1v2h-5.1zM111.8 131.1h5v2h-5zM293.6 142.2h2.1v5.1h-2.1zM258.1 182.9h2v5.1h-2zM128.5 208.3h2.1v5.1h-2.1zM223.5 236.2l10.2 5.1-10.2 5.1z" fill="none" stroke="#840000" stroke-width=".25"/>
<g fill="none" stroke="#840000" stroke-width=".18">
<path d="M193 44.5h.1M193 41.9v2.6M193 52.1v1.2M193 58.4v1.3M193 41.9l-.7 1.3M193 41.9l.8 1.3M316.2 48.3h1.3M322.6 48.3h1.2M358.1 44.5h.1M358.1 41.9v2.6M358.1 41.9l-.7 1.3M358.1 41.9l.8 1.3"/>
<path d="M294.6 74.9v1.3M307.3 74.9v2.8M307.3 79.8v2.8M129.5 90.2v1.2h1.3l-1.3 1.3-1.2-1.3h1.2M129.5 90.2h.1M142.2 90.2v1.2h1.3l-1.3 1.3-1.2-1.3h1.2M142.2 90.2h.1M294.6 90.2v1.2h1.3l-1.3 1.3-1.2-1.3h1.2M294.6 90.2h.1M294.6 81.3v1.3M307.3 90.2v1.2h1.3l-1.3 1.3-1.2-1.3h1.2M307.3 90.2h.1"/>
<path d="M193 110.5h.1M193 107.9l-.7 1.3M193 107.9l.8 1.3M193 107.9v2.6M316.2 114.3h1.3M322.6 114.3h1.2M358.1 110.5h.1M358.1 107.9l-.7 1.3M358.1 107.9l.8 1.3M358.1 107.9v2.6M110.5 132.1h1.3M116.8 132.1h1.3"/>
<path d="M294.6 156.2v1.3h1.3l-1.3 1.3-1.2-1.3h1.2M294.6 156.2h.1M294.6 141v1.2M294.6 147.3v1.3M307.3 156.2v1.3h1.3l-1.3 1.3-1.2-1.3h1.2M307.3 156.2h.1M259.1 181.6v1.3M259.1 188v1.2M129.5 207v1.3M129.5 213.4v1.2M142.2 207v2.8M142.2 211.8v2.8"/>
<path d="M307.3 207v2.8M307.3 211.8v2.8M129.5 222.3v1.2h1.3l-1.3 1.3-1.2-1.3h1.2M129.5 222.3h.1M142.2 222.3v1.2h1.3l-1.3 1.3-1.2-1.3h1.2M142.2 222.3h.1M221 238.8h2.5M45.7 246.4v3.8M45.7 257.8v3.8M78.7 250.2v2.8M78.7 255v2.8M121.9 257.8v3.8"/>
<path d="M121.9 246.4v3.8M221 243.8h2.5M230.9 241.8h.5l-.5-.5 .5-.5 .5 .5-.5 .5h.5M233.7 241.3h2.5M45.7 269.2v1.3h1.3l-1.3 1.3-1.3-1.3h1.3M45.7 269.2h.1M121.9 269.2v1.3h1.3l-1.3 1.3-1.3-1.3h1.3M121.9 269.2h.1M154.9 265.4v1.3h1.3l-1.3 1.3-1.2-1.3h1.2M154.9 265.4h.1"/>
</g>
<g fill="none" stroke="#006464" stroke-width=".18">
<path d="M298.9 79.6h.6M299.2 78.6l-.3 .3M303.9 79.4l.2 .1h-.2M304.1 78.6l-.8 1M311.6 79.6h.6M311.6 78.9l.3-.3v1M320.1 79.2h.2v.3l-.3 .1-.2-.1M320.3 78.6h-.3l-.2 .1M111.7 126.2h.6M111.7 127.1l.4 .1M116.7 127l.2 .1-.2 .1M116.9 126.2l-.8 1"/>
<path d="M298.9 145.6h.6M299.2 144.6l-.3 .3M303.9 145.4l.2 .1-.2 .1M304.1 144.6l-.8 1M133.8 211.7h.6M134.1 210.7l-.3 .3M138.8 211.4l.2 .1-.2 .1M139 210.7l-.8 1M146.5 211.7h.6M146.5 211l.3-.3v1M155 211.2h.2v.4l-.3 .1-.2-.2M155.2 210.7h-.3l-.2 .1"/>
<path d="M311.6 211.7h.6M311.6 211l.3-.3v1M320.1 211.2h.2v.4l-.3 .1-.2-.2M320.3 210.7h-.3l-.2 .1M45.8 255.2v1M83 254.9h.6M83 254.1l.3-.2v1M89.4 253.9l.3 1 .3-1M122 255.2v1M224 243.9h1"/>
</g>
<path d="M305.3 78h4.1M305.3 79.5h4.1M140.2 210.1h4.1M140.2 211.6h4.1M305.3 210.1h4.1M305.3 211.6h4.1M76.7 253.2h4.1M76.7 254.8h4.1" fill="none" stroke="#840000" stroke-width=".51"/>
<path d="M327.7 63.5l10.1 5.1-10.1 5.1z" fill="#ffffc2"/>
<path d="M152.4 47.2h5.1v2.1h-5.1zM357.1 53.3h2.1v5.1h-2.1zM128.5 76.2h2.1v5.1h-2.1zM327.7 63.5l10.1 5.1-10.1 5.1zM93 116.8h2v5.1h-2zM152.4 113.3h5.1v2h-5.1zM317.5 179.3h5.1v2.1h-5.1zM192 185.4h2.1v5.1h-2.1z" fill="none" stroke="#840000" stroke-width=".25"/>
<g fill="none" stroke="#840000" stroke-width=".18">
<path d="M151.1 48.3h1.3M157.5 48.3h1.2M358.1 52.1v1.2M358.1 58.4v1.3M129.5 74.9v1.3M142.2 74.9v2.8M142.2 79.8v2.8M325.1 66h2.6M325.1 71.1h2.6M335 69.1h.5l-.5-.5 .5-.5 .5 .5-.5 .5h.5M337.8 68.6h2.6M129.5 81.3v1.3"/>
<path d="M94 115.6v1.2M151.1 114.3h1.3M157.5 114.3h1.2M94 121.9v1.3M307.3 141v2.8M307.3 145.8v2.8M193 176.5h.1M193 174v2.5M193 174l-.7 1.3M193 174l.8 1.3M358.1 176.5h.1M358.1 174v2.5"/>
<path d="M358.1 174l-.7 1.3M358.1 174l.8 1.3M193 184.2v1.2M193 190.5v1.3M316.2 180.3h1.3M322.6 180.3h1.2"/>
</g>
<g fill="none" stroke="#006464" stroke-width=".18">
<path d="M133.8 79.6h.6M134.1 78.6l-.3 .3M138.8 79.4l.2 .1h-.2M139 78.6l-.8 1M146.5 79.6h.6M146.5 78.9l.3-.3v1M155 79.2h.2v.3l-.3 .1-.2-.1M155.2 78.6h-.3l-.2 .1M328.2 71.2h1M311.6 145.6h.6M311.6 144.9l.3-.3v1M320.1 145.2h.2v.4h-.3l-.2-.1"/>
<path d="M320.3 144.7l-.3-.1-.2 .2"/>
</g>
<path d="M140.2 78h4.1M140.2 79.5h4.1M305.3 144h4.1M305.3 145.5h4.1" fill="none" stroke="#840000" stroke-width=".51"/>
<path d="M44.4 194.3h2.6v10.2h-2.6z" fill="#ffffc2"/>
<path d="M93 50.8h2v5.1h-2zM111.8 65h5v2.1h-5zM44.4 194.3h2.6v10.2h-2.6zM293.6 208.3h2.1v5.1h-2.1z" fill="none" stroke="#840000" stroke-width=".25"/>
<g fill="none" stroke="#840000" stroke-width=".18">
<path d="M94 49.5v1.3M94 55.9v1.3M110.5 66h1.3M116.8 66h1.3M40.6 195.6h3.8M40.6 198.1h3.8M44.4 195.5h1.3v.2h-1.3zM44.4 198h1.3v.2h-1.3zM40.6 200.7h3.8M40.6 203.2h3.8M44.4 200.5h1.3v.3h-1.3zM44.4 203.1h1.3v.2h-1.3z"/>
<path d="M294.6 207v1.3M294.6 213.4v1.2"/>
</g>
<g fill="none" stroke="#006464" stroke-width=".18">
<path d="M111.7 60.2h.6M111.7 61.1l.4 .1M116.7 61l.2 .1h-.2M116.9 60.2l-.8 1M42.1 191.2h.3l.2 .2-.2 .3 .2 .1v.2l-.1 .2h-.4zM42.1 191.7h.3M43.3 191.2l-.3 .7h.6M52.8 191.8l.5-.1 .1-.4-.6-.1v1M53.1 191.8l.3 .4M298.9 211.7h.6M299.2 210.7l-.3 .3M303.9 211.4l.2 .1-.2 .1"/>
<path d="M304.1 210.7l-.8 1"/>
</g>
<path d="M44.4 128.3h2.6v10.1h-2.6z" fill="#ffffc2"/>
<path d="M44.4 128.3h2.6v10.1h-2.6z" fill="none" stroke="#840000" stroke-width=".25"/>
<path d="M40.6 129.5h3.8M40.6 132.1h3.8M40.6 134.6h3.8M40.6 137.2h3.8M44.4 129.4h1.3v.3h-1.3zM44.4 132h1.3v.2h-1.3zM44.4 134.5h1.3v.2h-1.3zM44.4 137h1.3v.3h-1.3z" fill="none" stroke="#840000" stroke-width=".18"/>
<path d="M42.1 125.2h.3l.2 .2-.2 .3 .2 .1v.2l-.1 .2h-.4zM42.1 125.7h.3M43.3 125.1l-.3 .8h.6M53.4 125.3a.44 .44 0 0 0-.6 .4 .44 .44 0 0 0 .6 .4" fill="none" stroke="#006464" stroke-width=".18"/>
<path d="M327.7 129.5l10.1 5.1-10.1 5.1z" fill="#ffffc2"/>
<path d="M357.1 119.4h2.1v5.1h-2.1zM327.7 129.5l10.1 5.1-10.1 5.1z" fill="none" stroke="#840000" stroke-width=".25"/>
<path d="M358.1 118.1v1.3M325.1 132.1h2.6M325.1 137.2h2.6M335 135.1h.5l-.5-.5 .5-.5 .5 .5-.5 .5h.5M337.8 134.6h2.6M358.1 124.5v1.2M294.6 222.3v1.2h1.3l-1.3 1.3-1.2-1.3h1.2M294.6 222.3h.1" fill="none" stroke="#840000" stroke-width=".18"/>
<path d="M328.2 137.3h1" fill="none" stroke="#006464" stroke-width=".18"/>
<path d="M302.3 236.2l10.1 5.1-10.1 5.1z" fill="#ffffc2"/>
<path d="M302.3 236.2l10.1 5.1-10.1 5.1z" fill="none" stroke="#840000" stroke-width=".25"/>
<path d="M299.7 238.8h2.6M307.3 222.3v1.2h1.3l-1.3 1.3-1.2-1.3h1.2M307.3 222.3h.1M299.7 243.8h2.6M309.6 241.8h.5l-.5-.5 .5-.5 .5 .5-.5 .5h.5M312.4 241.3h2.6" fill="none" stroke="#840000" stroke-width=".18"/>
<path d="M302.8 243.9h1" fill="none" stroke="#006464" stroke-width=".18"/>
<path d="M44.4 62.2h2.6v10.2h-2.6z" fill="#ffffc2"/>
<path d="M44.4 62.2h2.6v10.2h-2.6zM128.5 142.2h2.1v5.1h-2.1zM152.4 179.3h5.1v2.1h-5.1zM276.9 197.1h5v2h-5zM357.1 185.4h2.1v5.1h-2.1z" fill="none" stroke="#840000" stroke-width=".25"/>
<g fill="none" stroke="#840000" stroke-width=".18">
<path d="M40.6 63.5h3.8M40.6 66h3.8M40.6 68.6h3.8M40.6 71.1h3.8M44.4 63.4h1.3v.2h-1.3zM44.4 65.9h1.3v.3h-1.3zM44.4 68.5h1.3v.2h-1.3zM44.4 71h1.3v.2h-1.3zM129.5 156.2v1.3h1.3l-1.3 1.3-1.2-1.3h1.2M129.5 156.2h.1M129.5 141v1.2M129.5 147.3v1.3"/>
<path d="M142.2 156.2v1.3h1.3l-1.3 1.3-1.2-1.3h1.2M142.2 156.2h.1M151.1 180.3h1.3M157.5 180.3h1.2M275.6 198.1h1.3M281.9 198.1h1.3M358.1 184.2v1.2M358.1 190.5v1.3"/>
</g>
<path d="M42.2 59.2h.3l.2 .1-.2 .3 .2 .1v.3l-.1 .2h-.4zM42.2 59.6h.3M43.4 59.1l-.3 .7h.6M52.9 59.2v1h.5M133.8 145.6h.6M134.1 144.6l-.3 .3M138.8 145.4l.2 .1-.2 .1M139 144.6l-.8 1M276.8 192.3h.6M276.8 193.2l.4 .1M281.8 193l.2 .1-.2 .1M282 192.3l-.8 1" fill="none" stroke="#006464" stroke-width=".18"/>
<path d="M327.7 195.6l10.1 5.1-10.1 5z" fill="#ffffc2"/>
<path d="M192 119.4h2.1v5.1h-2.1zM258.1 116.8h2v5.1h-2zM327.7 195.6l10.1 5.1-10.1 5z" fill="none" stroke="#840000" stroke-width=".25"/>
<path d="M193 118.1v1.3M259.1 115.6v1.2M193 124.5v1.2M259.1 121.9v1.3M325.1 198.1h2.6M325.1 203.2h2.6M335 201.2h.5l-.5-.5 .5-.5 .5 .5-.5 .5h.5M337.8 200.7h2.6" fill="none" stroke="#840000" stroke-width=".18"/>
<path d="M328.2 203.3h1" fill="none" stroke="#006464" stroke-width=".18"/>
<path d="M162.6 129.5l10.1 5.1-10.1 5.1z" fill="#ffffc2"/>
<path d="M258.1 50.8h2v5.1h-2zM162.6 129.5l10.1 5.1-10.1 5.1zM93 182.9h2v5.1h-2zM111.8 197.1h5v2h-5z" fill="none" stroke="#840000" stroke-width=".25"/>
<g fill="none" stroke="#840000" stroke-width=".18">
<path d="M94.9 40.9h9.6l.9 1-.9 1h-9.6l-.9-1zM102.1 41.4l.5 1v-1M103.6 41.5h-.5v.3l.4 .2 .1 .2-.2 .2h-.3M259.1 49.5v1.3M259.1 55.9v1.3M260 40.9h9.6l.9 1-.9 1h-9.6l-.9-1zM267.2 41.4l.5 1v-1M268.7 41.5h-.5v.3l.4 .2 .1 .2-.2 .2h-.3M20.8 65h11.3l.9 1-.9 1h-11.3l-.9-1zM21 70.1h11.1l.9 1-.9 1h-11.1l-.9-1zM22.5 62.5h9.6l.9 1-.9 1h-9.6l-.9-1zM23.4 63.6h.8"/>
<path d="M23.8 63.3v.7M28 67.6h4.1l.9 1-.9 1h-4.1l-.8-1zM90.8 65h11.2l.9 1-.9 1h-11.2l-.9-1zM142.2 70.1h9.3l.9 1-.9 1h-9.3l-.9-1zM143.7 70.7h-.6v.3l.5 .2 .1 .3-.2 .1h-.4M221.9 67.6h8.2l.9 1-.9 1h-8.2l-.9-1zM255.7 65h11.4l.9 1-.9 1h-11.4l-.9-1zM307.3 70.1h9.3l.9 1-.9 1h-9.3l-.9-1zM308.8 70.7h-.6v.3l.5 .2 .1 .3-.2 .1h-.4M387 67.6h8.4l.9 1-.9 1h-8.4l-.9-1zM94.9 106.9h9.6l.9 1.1-.9 1h-9.6l-.9-1zM102.1 107.5l.5 1v-1"/>
<path d="M103.6 107.5l-.5 .1v.3l.4 .1 .1 .3-.2 .2-.3-.1M260 106.9h9.6l.9 1.1-.9 1h-9.6l-.9-1zM267.2 107.5l.5 1v-1M268.7 107.5l-.5 .1v.3l.4 .1 .1 .3-.2 .2-.3-.1M20.6 131.1h11.5l.9 1-.9 1h-11.5l-.9-1zM20.8 136.2h11.3l.9 1-.9 1h-11.3l-.9-1zM21.7 137.2h.3M22 136.7h-.3v1h.4M22.5 128.5h9.6l.9 1-.9 1h-9.6l-.9-1zM23.4 129.7h.8M23.8 129.3v.8M28 133.6h4.1l.9 1-.9 1h-4.1l-.8-1z"/>
<path d="M90.6 131.1h11.4l.9 1-.9 1h-11.4l-.9-1zM91.5 132.1h.4M91.9 131.6h-.4v1h.4M142.2 136.2h9.3l.9 1-.9 1h-9.3l-.9-1zM143.7 136.7l-.6 .1v.3l.5 .2 .1 .2-.2 .2-.4-.1M160 132.1h2.6M160 137.2h2.6M169.9 135.1h.5l-.5-.5 .5-.5 .5 .5-.5 .5h.5M172.7 134.6h2.6M221.9 133.6h8.4l.9 1-.9 1h-8.4l-.9-1zM255.5 131.1h11.6l.9 1-.9 1h-11.6l-.9-1zM307.3 136.2h9.3l.9 1-.9 1h-9.3l-.9-1z"/>
<path d="M308.8 136.7l-.6 .1v.3l.5 .2 .1 .2-.2 .2-.4-.1M387 133.6h8.6l.9 1-.9 1h-8.6l-.9-1zM94.9 173h9.6l.9 1-.9 1h-9.6l-.9-1zM102.1 173.5l.5 1v-1M103.6 173.6h-.5v.3l.4 .2 .1 .2-.2 .2h-.3M260 173h9.6l.9 1-.9 1h-9.6l-.9-1zM267.2 173.5l.5 1v-1M268.7 173.6h-.5v.3l.4 .2 .1 .2-.2 .2h-.3M20.6 197.1h11.5l.9 1-.9 1h-11.5l-.9-1zM22.5 194.6h9.6l.9 1-.9 1h-9.6l-.9-1zM23.4 195.7h.8M23.8 195.3v.8"/>
<path d="M28 199.7h4.1l.9 1-.9 1h-4.1l-.8-1zM90.6 197.1h11.4l.9 1-.9 1h-11.4l-.9-1zM91.5 198.1h.4M91.9 197.6h-.4v1h.4M94 181.6v1.3M94 188v1.2M110.5 198.1h1.3M116.8 198.1h1.3M221.9 199.7h8.4l.9 1-.9 1h-8.4l-.9-1zM255.5 197.1h11.6l.9 1-.9 1h-11.6l-.9-1zM387 199.7h8.6l.9 1-.9 1h-8.6l-.9-1zM20.8 202.2h11.3l.9 1-.9 1h-11.3l-.9-1z"/>
<path d="M21.7 203.2h.3M22 202.7h-.3v1h.4M142.2 202.2h9.3l.9 1-.9 1h-9.3l-.9-1zM143.7 202.8h-.6v.3l.5 .2 .1 .2-.2 .2h-.4M307.3 202.2h9.3l.9 1-.9 1h-9.3l-.9-1zM308.8 202.8h-.6v.3l.5 .2 .1 .2-.2 .2h-.4M46.6 237.8h9.7l.8 1-.8 1h-9.7l-.9-1zM53.8 238.3l.6 1v-1M55.4 238.3l-.6 .1v.3l.5 .2 .1 .2-.2 .2-.4-.1M122.8 237.8h9.7l.8 1-.8 1h-9.7l-.9-1zM130 238.3l.6 1v-1M131.6 238.3l-.6 .1v.3l.5 .2 .1 .2-.2 .2-.4-.1"/>
<path d="M208.4 237.8h4.1l.9 1-.9 1h-4.1l-.9-1zM287.1 237.8h4.1l.9 1-.9 1h-4.1l-.8-1zM79.6 241.6h9.7l.9 1-.9 1h-9.7l-.9-1zM86.8 242.1l.6 1v-1M88.4 242.1l-.5 .1v.3l.4 .2 .1 .2-.2 .2-.4-.1M155.8 241.6h9.7l.9 1-.9 1h-9.7l-.9-1zM163 242.1l.6 1v-1M164.6 242.1l-.5 .1v.3l.4 .2 .1 .2-.2 .2-.4-.1M203.1 242.8h9.4l.9 1-.9 1h-9.4l-.8-1zM204.6 243.4l-.5 .1v.2l.4 .2 .1 .3-.2 .2-.4-.1M281.9 242.8h9.3l.9 1-.9 1h-9.3l-.9-1zM283.4 243.4l-.6 .1v.2l.5 .2 .1 .3-.2 .2-.4-.1"/>
</g>
<path d="M163.1 137.3h1M111.7 192.3h.6M111.7 193.2l.4 .1M116.7 193l.2 .1-.2 .1M116.9 192.3l-.8 1" fill="none" stroke="#006464" stroke-width=".18"/>
<g fill="none" stroke="#009600" stroke-width=".18">
<path d="M94 57.2v8.8h16.5M94 41.9v7.6M151.1 48.3h-21.6v26.6M158.7 48.3h47v20.3M193 44.5v7.6M193 59.7v8.9M259.1 41.9v7.6M259.1 57.2v8.8h16.5M316.2 48.3h-21.6v26.6M323.8 48.3h47v20.3M358.1 44.5v7.6M358.1 59.7v8.9"/>
<path d="M33 68.6h7.6M33 66h7.6M33 71.1h7.6M33 63.5h7.6M118.1 66h41.9M142.2 66v8.9M152.4 71.1h7.6M175.3 68.6h45.7M283.2 66h41.9M307.3 66v8.9M317.5 71.1h7.6M340.4 68.6h45.7"/>
<path d="M129.5 82.6v7.6M142.2 82.6v7.6M294.6 82.6v7.6M307.3 82.6v7.6M94 108v7.6M151.1 114.3h-21.6v26.7M158.7 114.3h47v20.3M193 110.5v7.6M259.1 108v7.6M316.2 114.3h-21.6v26.7M323.8 114.3h47v20.3M358.1 110.5v7.6"/>
<path d="M33 134.6h7.6M33 132.1h7.6M33 137.2h7.6M33 129.5h7.6M94 123.2v8.9h16.5M118.1 132.1h41.9M142.2 132.1v8.9M152.4 137.2h7.6M175.3 134.6h45.7M193 125.7v8.9M259.1 123.2v8.9h16.5M283.2 132.1h41.9"/>
<path d="M307.3 132.1v8.9M317.5 137.2h7.6M340.4 134.6h45.7M358.1 125.7v8.9M129.5 148.6v7.6M142.2 148.6v7.6M294.6 148.6v7.6M307.3 148.6v7.6M94 174v7.6M193 176.5v7.7M259.1 174v7.6M358.1 176.5v7.7"/>
<path d="M33 198.1h7.6M33 195.6h7.6M94 189.2v8.9h16.5M118.1 198.1h41.9M142.2 198.1v8.9M151.1 180.3h-21.6v26.7M158.7 180.3h47v20.4M193 191.8v8.9M259.1 189.2v8.9h16.5M283.2 198.1h41.9M307.3 198.1v8.9M316.2 180.3h-21.6v26.7"/>
<path d="M323.8 180.3h47v20.4M358.1 191.8v8.9M33 203.2h7.6M33 200.7h7.6M129.5 214.6v7.7M142.2 214.6v7.7M152.4 203.2h7.6M175.3 200.7h45.7M294.6 214.6v7.7M307.3 214.6v7.7M317.5 203.2h7.6M340.4 200.7h45.7"/>
<path d="M45.7 238.8v7.6M121.9 238.8v7.6M213.4 238.8h7.6M292.1 238.8h7.6M78.7 242.6v7.6M78.7 257.8v7.6M154.9 242.6v7.6M154.9 257.8v7.6M213.4 243.8h7.6M292.1 243.8h7.6M45.7 261.6v7.6M121.9 261.6v7.6"/>
</g>
<path d="M235.6 240.7l1.2 1.2M236.8 240.7l-1.2 1.2M314.4 240.7l1.2 1.2M315.6 240.7l-1.2 1.2" fill="none" stroke="#000084" stroke-width=".18"/>
<g fill="none" stroke="#0000c2" stroke-width=".18">
<path d="M78.7 12.5v1.3M78.7 12.7a.5 .5 0 0 1 .9 .1v1M80.2 12.5h.8M80.5 11.8v1.8l.1 .1 .4 .1M81.7 12.6l.2-.1 .5 .1 .1 1.2M82.5 13l-.6 .1a.39 .39 0 0 0-.3 .4 .39 .39 0 0 0 .3 .3l.6-.1M83.5 12.5v1.3M84.1 12.5l-.4 .1-.2 .3M84.5 12.5l.5 1.3M85 13.8l-.2 .5-.3 .2M85.5 12.5l-.5 1.3M87.8 12.7a.54 .54 0 0 1 .5-.2 .54 .54 0 0 1 .4 .4v.6a.54 .54 0 0 1-.5 .4 .54 .54 0 0 1-.5-.4z"/>
<path d="M89.6 12.5l.1 1.2a.54 .54 0 0 0 .7-.1M90.4 12.5v1.3M91.1 12.5h.8M91.4 11.8v1.8l.1 .1 .4 .1M92.5 12.6l.6-.1 .4 .4v.6l-.2 .2-.2 .1-.6-.1M92.5 12.5v2M94.3 12.5l.1 1.2a.54 .54 0 0 0 .8-.1M95.2 12.5v1.3M95.9 12.5h.7M96.1 11.8v1.8l.1 .1 .4 .1M98 12.6l-.5-.1-.3 .3 .1 .3 .7 .2 .1 .2-.1 .2-.2 .1-.6-.1M51.8 22.8v1l.2 .1"/>
<path d="M52.4 23.2l.1 .7 .4-.1M52.9 23.2v.7M53.4 23.6l.6-.1-.1-.3h-.3l-.2 .1 .1 .6h.4M56 22.9a.52 .52 0 0 0-.7 .5 .52 .52 0 0 0 .7 .4v-.3h-.2M57.2 22.8v1.1l-.7-1.1v1.1M57.7 22.8a.58 .58 0 0 1 .7 .6 .58 .58 0 0 1-.7 .5zM58.9 23.9l-.1 .2M60.5 22.7l-.3 .9h.7M60.8 23.2v.7M62.3 23.2h.3l.2 .2-.1 .5h-.4M62.3 22.8v1.1M63.3 22.8v1l.2 .1"/>
<path d="M63.9 23.2h.4l.1 .7M64.4 23.5h-.4l-.2 .2 .2 .2h.4M65.4 23.2h-.3l-.2 .2 .1 .5h.4M65.9 22.8v1.1M66 23.5l.4 .4M66.4 23.2l-.5 .4M66.9 23.8v.1M79.6 24.6v1l.2 .2M80 25h.5M80.2 24.6v1l.3 .2M80.9 25.1h.4l.1 .7M81.4 25.3l-.4 .1-.2 .1 .2 .3 .4-.1"/>
<path d="M82.4 25.1l-.3-.1-.2 .3 .1 .4h.4M82.4 25v1l-.2 .2-.3-.1M82.9 25.4l.5-.1v-.2l-.3-.1-.2 .2 .1 .5h.4M83.9 25.7v.1M86 24.8a.51 .51 0 0 0-.7 .4 .51 .51 0 0 0 .7 .5M86.6 25.1l.2-.1 .3 .3v.3l-.3 .2-.3-.2zM87.6 25.1l.3-.1 .1 .2M87.6 25v.8M88 25.2l.2-.2 .3 .1v.7M88 25.2v.6M89.1 25.1l.3-.1 .2 .3-.1 .4h-.4M89.1 25v1.2"/>
<path d="M90.1 25.1h.5v.7M90.6 25.3l-.4 .1-.1 .1 .1 .3 .4-.1M91.2 25v.8M91.5 25l-.3 .3M91.9 25.1h.4l.1 .7M92.4 25.3l-.4 .1-.2 .1 .2 .3 .4-.1M92.8 25h.4M92.9 24.6v1l.3 .2M93.6 25.1l.3-.1 .2 .3v.3l-.2 .2-.4-.2zM94.6 25v.8M94.9 25l-.3 .3M96.3 25.1l.2-.1 .3 .3v.3l-.3 .2-.4-.2z"/>
<path d="M97.2 25l.1 .7h.4M97.7 25v.8M98.1 25h.5M98.3 24.6v1l.3 .2M98.9 25.1l.4-.1 .2 .3-.1 .4h-.5M98.9 25v1.2M100 25v.7h.5M100.5 25v.8M100.9 25h.4M101 24.6v1l.3 .2M102.1 25.1l-.3-.1-.2 .2 .1 .2 .4 .1v.2h-.5M102.6 25.7v.1"/>
<path d="M102.6 25.1v.1M103.9 24.6h.7l-.3 .5 .3 .1v.5l-.2 .1-.5-.1M105.1 25.7v.1M105.6 24.6h.7l-.4 .5 .3 .1v.5l-.1 .1-.5-.1M107.5 24.6l.4 1.2 .4-1.2M108.6 25.7v.1"/>
</g>
<circle cx="142.2" cy="66" r=".46" fill="#009600"/>
<circle cx="142.2" cy="66" r=".46" fill="none" stroke="#009600" stroke-width=".18"/>
<circle cx="175.3" cy="68.6" r=".46" fill="#009600"/>
<circle cx="175.3" cy="68.6" r=".46" fill="none" stroke="#009600" stroke-width=".18"/>
<circle cx="193" cy="68.6" r=".46" fill="#009600"/>
<circle cx="193" cy="68.6" r=".46" fill="none" stroke="#009600" stroke-width=".18"/>
<circle cx="294.6" cy="66" r=".46" fill="#009600"/>
<circle cx="294.6" cy="66" r=".46" fill="none" stroke="#009600" stroke-width=".18"/>
<circle cx="294.6" cy="66" r=".46" fill="#009600"/>
<circle cx="294.6" cy="66" r=".46" fill="none" stroke="#009600" stroke-width=".18"/>
<circle cx="275.6" cy="66" r=".46" fill="#009600"/>
<circle cx="275.6" cy="66" r=".46" fill="none" stroke="#009600" stroke-width=".18"/>
<circle cx="193" cy="134.6" r=".46" fill="#009600"/>
<circle cx="193" cy="134.6" r=".46" fill="none" stroke="#009600" stroke-width=".18"/>
<circle cx="294.6" cy="132.1" r=".46" fill="#009600"/>
<circle cx="294.6" cy="132.1" r=".46" fill="none" stroke="#009600" stroke-width=".18"/>
<circle cx="294.6" cy="132.1" r=".46" fill="#009600"/>
<circle cx="294.6" cy="132.1" r=".46" fill="none" stroke="#009600" stroke-width=".18"/>
<circle cx="275.6" cy="132.1" r=".46" fill="#009600"/>
<circle cx="275.6" cy="132.1" r=".46" fill="none" stroke="#009600" stroke-width=".18"/>
<circle cx="307.3" cy="198.1" r=".46" fill="#009600"/>
<circle cx="307.3" cy="198.1" r=".46" fill="none" stroke="#009600" stroke-width=".18"/>
<circle cx="307.3" cy="132.1" r=".46" fill="#009600"/>
<circle cx="307.3" cy="132.1" r=".46" fill="none" stroke="#009600" stroke-width=".18"/>
<circle cx="294.6" cy="198.1" r=".46" fill="#009600"/>
<circle cx="294.6" cy="198.1" r=".46" fill="none" stroke="#009600" stroke-width=".18"/>
<circle cx="294.6" cy="198.1" r=".46" fill="#009600"/>
<circle cx="294.6" cy="198.1" r=".46" fill="none" stroke="#009600" stroke-width=".18"/>
<circle cx="275.6" cy="198.1" r=".46" fill="#009600"/>
<circle cx="275.6" cy="198.1" r=".46" fill="none" stroke="#009600" stroke-width=".18"/>
<circle cx="307.3" cy="66" r=".46" fill="#009600"/>
<circle cx="307.3" cy="66" r=".46" fill="none" stroke="#009600" stroke-width=".18"/>
<circle cx="358.1" cy="68.6" r=".46" fill="#009600"/>
<circle cx="358.1" cy="68.6" r=".46" fill="none" stroke="#009600" stroke-width=".18"/>
<circle cx="340.4" cy="68.6" r=".46" fill="#009600"/>
<circle cx="340.4" cy="68.6" r=".46" fill="none" stroke="#009600" stroke-width=".18"/>
<circle cx="358.1" cy="134.6" r=".46" fill="#009600"/>
<circle cx="358.1" cy="134.6" r=".46" fill="none" stroke="#009600" stroke-width=".18"/>
<circle cx="340.4" cy="134.6" r=".46" fill="#009600"/>
<circle cx="340.4" cy="134.6" r=".46" fill="none" stroke="#009600" stroke-width=".18"/>
<circle cx="358.1" cy="200.7" r=".46" fill="#009600"/>
<circle cx="358.1" cy="200.7" r=".46" fill="none" stroke="#009600" stroke-width=".18"/>
<circle cx="340.4" cy="200.7" r=".46" fill="#009600"/>
<circle cx="340.4" cy="200.7" r=".46" fill="none" stroke="#009600" stroke-width=".18"/>
<circle cx="175.3" cy="134.6" r=".46" fill="#009600"/>
<circle cx="175.3" cy="134.6" r=".46" fill="none" stroke="#009600" stroke-width=".18"/>
<circle cx="193" cy="200.7" r=".46" fill="#009600"/>
<circle cx="193" cy="200.7" r=".46" fill="none" stroke="#009600" stroke-width=".18"/>
<circle cx="175.3" cy="200.7" r=".46" fill="#009600"/>
<circle cx="175.3" cy="200.7" r=".46" fill="none" stroke="#009600" stroke-width=".18"/>
<circle cx="129.5" cy="132.1" r=".46" fill="#009600"/>
<circle cx="129.5" cy="132.1" r=".46" fill="none" stroke="#009600" stroke-width=".18"/>
<circle cx="129.5" cy="198.1" r=".46" fill="#009600"/>
<circle cx="129.5" cy="198.1" r=".46" fill="none" stroke="#009600" stroke-width=".18"/>
<circle cx="110.5" cy="198.1" r=".46" fill="#009600"/>
<circle cx="110.5" cy="198.1" r=".46" fill="none" stroke="#009600" stroke-width=".18"/>
<circle cx="142.2" cy="198.1" r=".46" fill="#009600"/>
<circle cx="142.2" cy="198.1" r=".46" fill="none" stroke="#009600" stroke-width=".18"/>
<circle cx="129.5" cy="132.1" r=".46" fill="#009600"/>
<circle cx="129.5" cy="132.1" r=".46" fill="none" stroke="#009600" stroke-width=".18"/>
<circle cx="110.5" cy="132.1" r=".46" fill="#009600"/>
<circle cx="110.5" cy="132.1" r=".46" fill="none" stroke="#009600" stroke-width=".18"/>
<circle cx="129.5" cy="198.1" r=".46" fill="#009600"/>
<circle cx="129.5" cy="198.1" r=".46" fill="none" stroke="#009600" stroke-width=".18"/>
<circle cx="110.5" cy="66" r=".46" fill="#009600"/>
<circle cx="110.5" cy="66" r=".46" fill="none" stroke="#009600" stroke-width=".18"/>
<circle cx="129.5" cy="66" r=".46" fill="#009600"/>
<circle cx="129.5" cy="66" r=".46" fill="none" stroke="#009600" stroke-width=".18"/>
<circle cx="129.5" cy="66" r=".46" fill="#009600"/>
<circle cx="129.5" cy="66" r=".46" fill="none" stroke="#009600" stroke-width=".18"/>
<circle cx="142.2" cy="132.1" r=".46" fill="#009600"/>
<circle cx="142.2" cy="132.1" r=".46" fill="none" stroke="#009600" stroke-width=".18"/>
<use href="#words"/>
</svg>
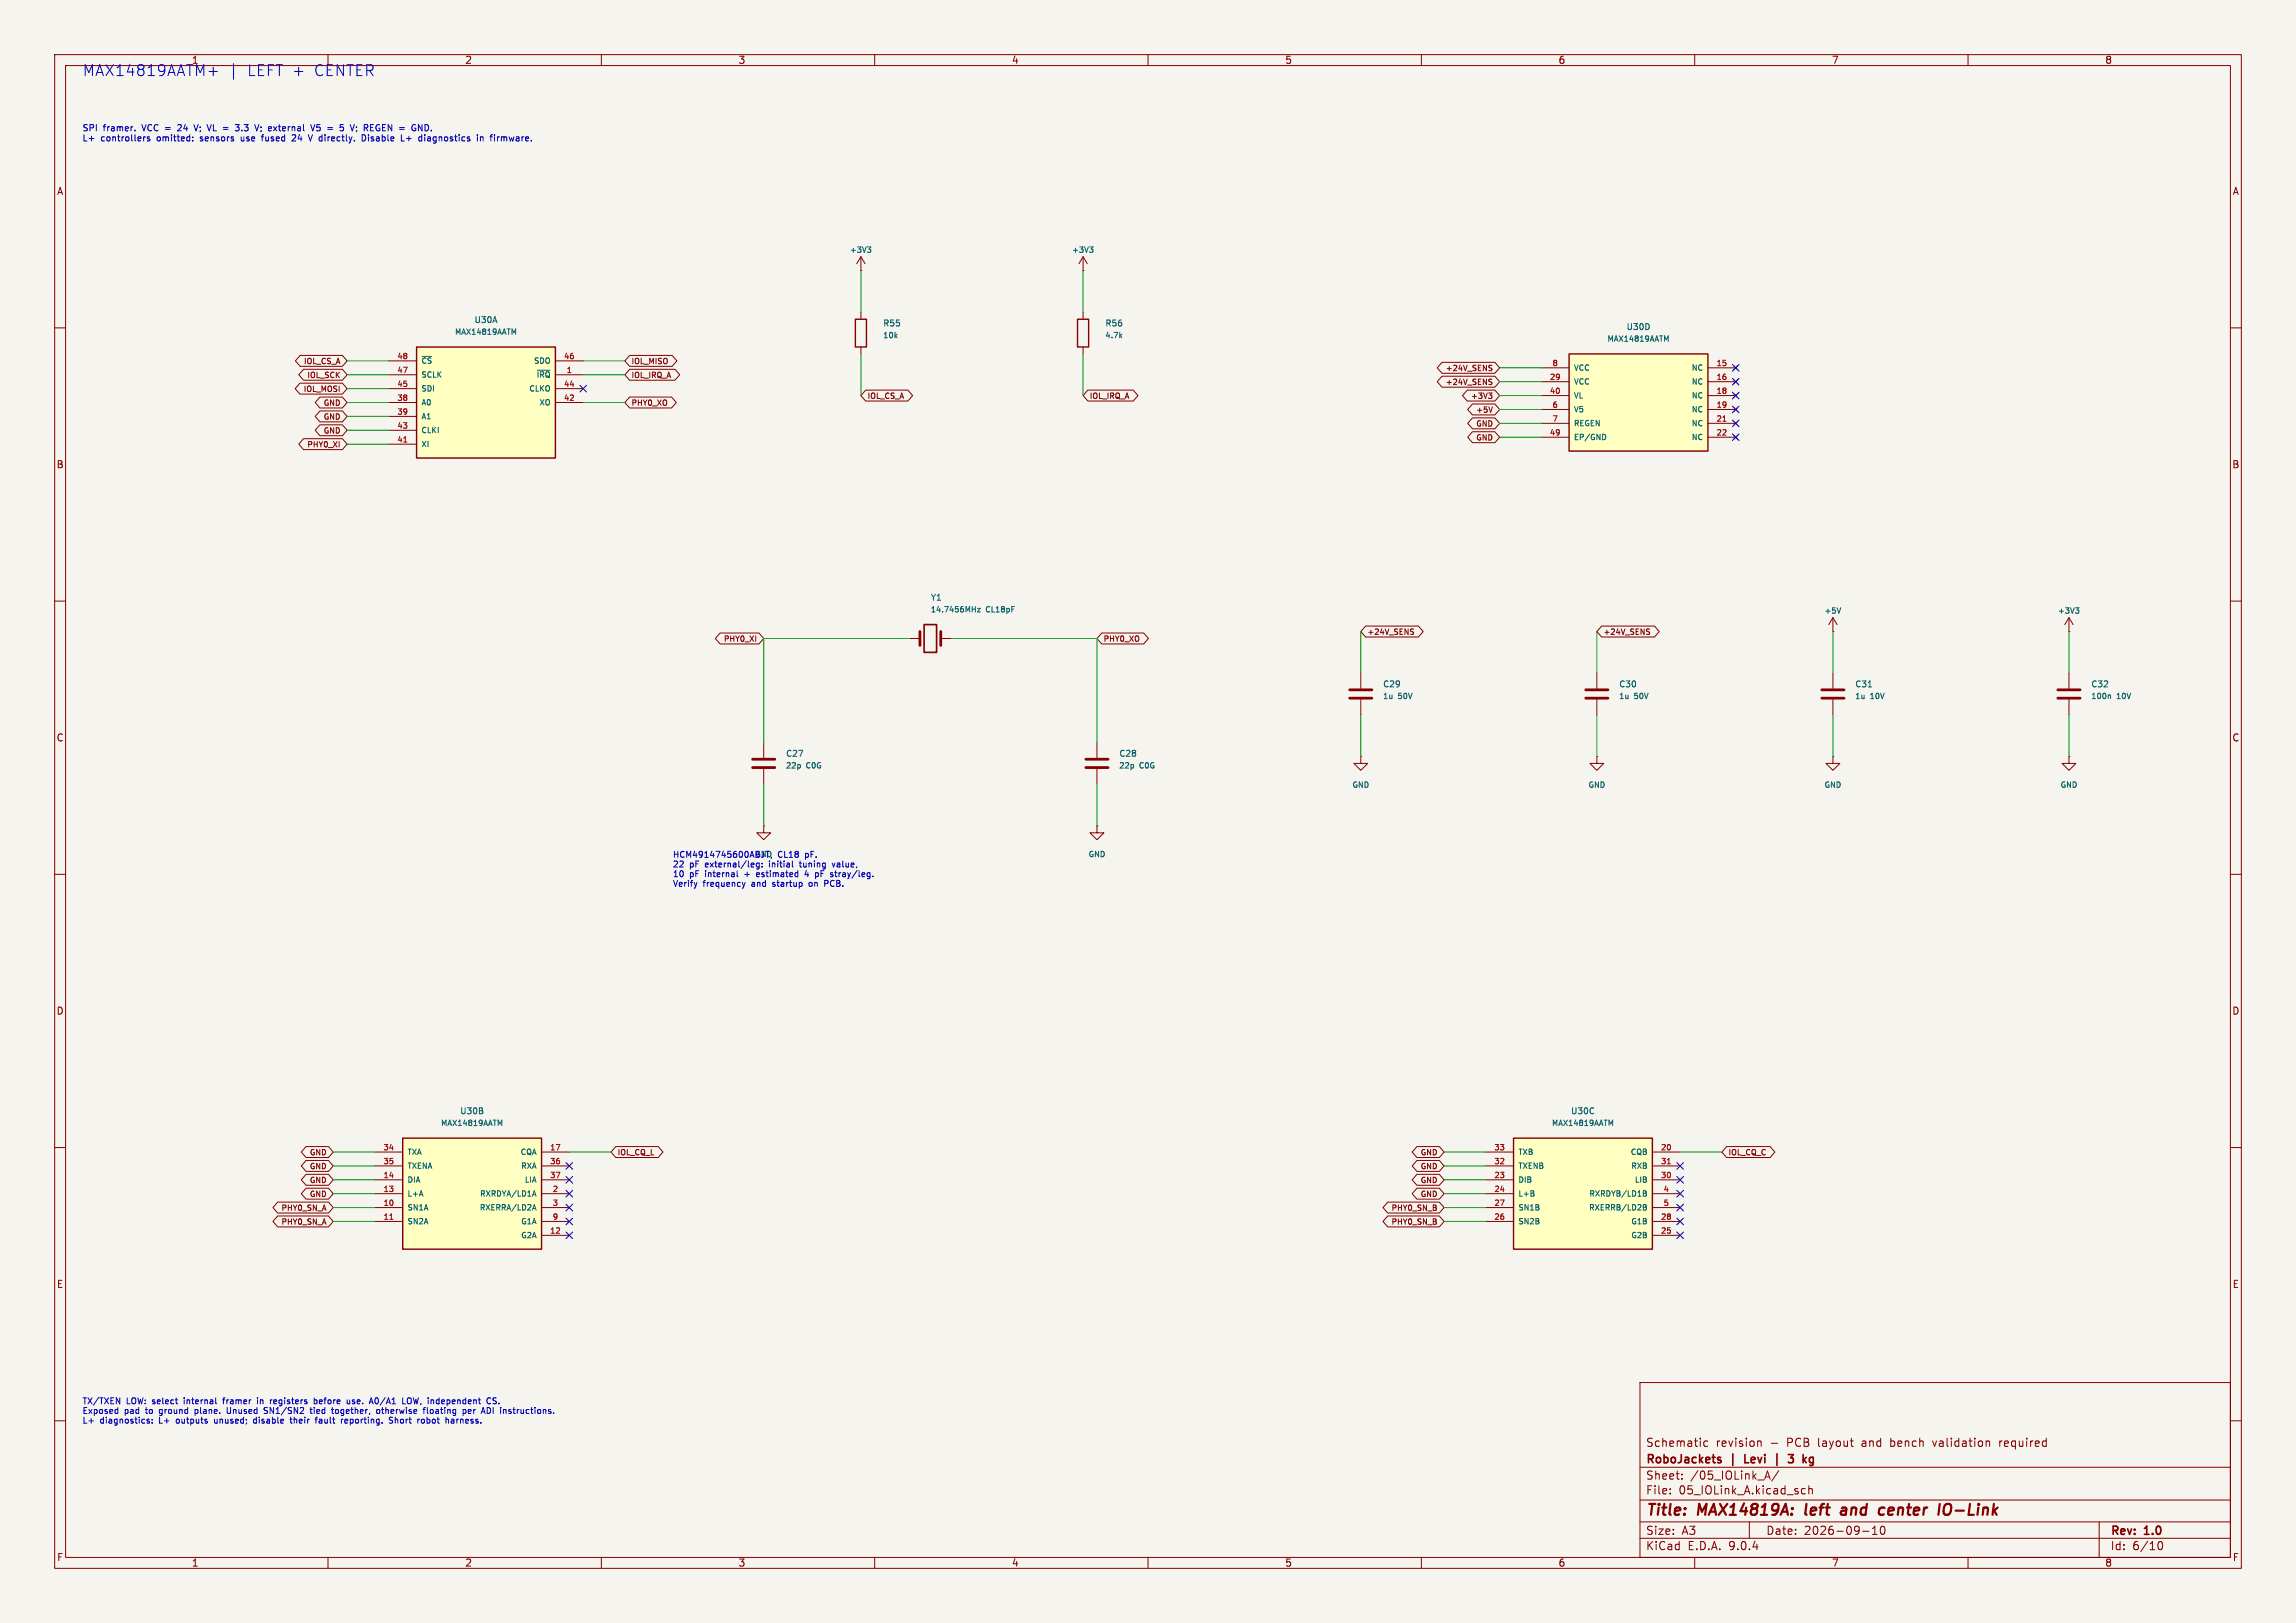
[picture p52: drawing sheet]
(kicad_sch
 (version 20250114)
 (generator "eeschema")
 (generator_version "9.0")
 (paper "A3")
 (title_block
  (title "MAX14819A: left and center IO-Link")
  (date "2026-09-10")
  (rev "1.0")
  (company "RoboJackets | Levi | 3 kg")
  (comment 1 "Schematic revision - PCB layout and bench validation required"))
 (lib_symbols
  (symbol "Device:C"
   (pin_numbers (hide yes))
   (pin_names
    (offset 0.254)) (exclude_from_sim no) (in_bom yes) (on_board yes)
   (property "Reference" "C" (at 0.635 2.54 0) (effects (font (size 1.27 1.27)) (justify left)))
   (property "Value" "C" (at 0.635 -2.54 0) (effects (font (size 1.27 1.27)) (justify left)))
   (property "Footprint" "" (at 0.9652 -3.81 0) (effects (font (size 1.27 1.27)) (hide yes)))
   (property "Datasheet" "~" (at 0 0 0) (effects (font (size 1.27 1.27)) (hide yes)))
   (property "Description" "Unpolarized capacitor" (at 0 0 0) (effects (font (size 1.27 1.27)) (hide yes)))
   (symbol "C_0_1"
    (polyline (pts (xy -2.032 0.762) (xy 2.032 0.762)) (stroke (width 0.508) (type default)) (fill (type none)))
    (polyline (pts (xy -2.032 -0.762) (xy 2.032 -0.762)) (stroke (width 0.508) (type default)) (fill (type none))))
   (symbol "C_1_1"
    (pin passive line (at 0 3.81 270) (length 2.794) (name "~" (effects (font (size 1.27 1.27)))) (number "1" (effects (font (size 1.27 1.27)))))
    (pin passive line (at 0 -3.81 90) (length 2.794) (name "~" (effects (font (size 1.27 1.27)))) (number "2" (effects (font (size 1.27 1.27))))))
   (embedded_fonts no))
  (symbol "Device:Crystal"
   (pin_numbers (hide yes))
   (pin_names
    (offset 1.016) (hide yes)) (exclude_from_sim no) (in_bom yes) (on_board yes)
   (property "Reference" "Y" (at 0 3.81 0) (effects (font (size 1.27 1.27))))
   (property "Value" "Crystal" (at 0 -3.81 0) (effects (font (size 1.27 1.27))))
   (property "Footprint" "" (at 0 0 0) (effects (font (size 1.27 1.27)) (hide yes)))
   (property "Datasheet" "~" (at 0 0 0) (effects (font (size 1.27 1.27)) (hide yes)))
   (property "Description" "Two pin crystal" (at 0 0 0) (effects (font (size 1.27 1.27)) (hide yes)))
   (symbol "Crystal_0_1"
    (polyline (pts (xy -2.54 0) (xy -1.905 0)) (stroke (width 0) (type default)) (fill (type none)))
    (polyline (pts (xy -1.905 -1.27) (xy -1.905 1.27)) (stroke (width 0.508) (type default)) (fill (type none)))
    (rectangle (start -1.143 2.54) (end 1.143 -2.54) (stroke (width 0.3048) (type default)) (fill (type none)))
    (polyline (pts (xy 1.905 -1.27) (xy 1.905 1.27)) (stroke (width 0.508) (type default)) (fill (type none)))
    (polyline (pts (xy 2.54 0) (xy 1.905 0)) (stroke (width 0) (type default)) (fill (type none))))
   (symbol "Crystal_1_1"
    (pin passive line (at -3.81 0 0) (length 1.27) (name "1" (effects (font (size 1.27 1.27)))) (number "1" (effects (font (size 1.27 1.27)))))
    (pin passive line (at 3.81 0 180) (length 1.27) (name "2" (effects (font (size 1.27 1.27)))) (number "2" (effects (font (size 1.27 1.27))))))
   (embedded_fonts no))
  (symbol "Device:R"
   (pin_numbers (hide yes))
   (pin_names
    (offset 0)) (exclude_from_sim no) (in_bom yes) (on_board yes)
   (property "Reference" "R" (at 2.032 0 90) (effects (font (size 1.27 1.27))))
   (property "Value" "R" (at 0 0 90) (effects (font (size 1.27 1.27))))
   (property "Footprint" "" (at -1.778 0 90) (effects (font (size 1.27 1.27)) (hide yes)))
   (property "Datasheet" "~" (at 0 0 0) (effects (font (size 1.27 1.27)) (hide yes)))
   (property "Description" "Resistor" (at 0 0 0) (effects (font (size 1.27 1.27)) (hide yes)))
   (symbol "R_0_1"
    (rectangle (start -1.016 -2.54) (end 1.016 2.54) (stroke (width 0.254) (type default)) (fill (type none))))
   (symbol "R_1_1"
    (pin passive line (at 0 3.81 270) (length 1.27) (name "~" (effects (font (size 1.27 1.27)))) (number "1" (effects (font (size 1.27 1.27)))))
    (pin passive line (at 0 -3.81 90) (length 1.27) (name "~" (effects (font (size 1.27 1.27)))) (number "2" (effects (font (size 1.27 1.27))))))
   (embedded_fonts no))
  (symbol "Levi:MAX14819AATM"
   (pin_names
    (offset 0.8)) (in_bom yes) (on_board yes)
   (property "Reference" "U" (at 0 0 0) (effects (font (size 1.1 1.1))))
   (property "Value" "MAX14819AATM" (at 0 0 0) (effects (font (size 1.1 1.1))))
   (property "Footprint" "Levi:MAX14819_T4877_4C_EP5.5" (at 0 0 0) (effects (font (size 1.1 1.1))))
   (property "Datasheet" "https://www.analog.com/media/en/technical-documentation/data-sheets/max14819.pdf" (at 0 0 0) (effects (font (size 1.1 1.1))))
   (property "Description" "Dual IO-Link master, complete 48 pins + exposed pad. ADI Rev 3 pp18-21." (at 0 0 0) (effects (font (size 1.1 1.1))))
   (symbol "MAX14819AATM_1_1"
    (rectangle (start -12.7 10.16) (end 12.7 -10.16) (stroke (width 0.254) (type default)) (fill (type background)))
    (pin input line (at -17.78 7.62 0) (length 5.08) (name "~{CS}" (effects (font (size 1 1)))) (number "48" (effects (font (size 1 1)))))
    (pin input line (at -17.78 5.08 0) (length 5.08) (name "SCLK" (effects (font (size 1 1)))) (number "47" (effects (font (size 1 1)))))
    (pin input line (at -17.78 2.54 0) (length 5.08) (name "SDI" (effects (font (size 1 1)))) (number "45" (effects (font (size 1 1)))))
    (pin input line (at -17.78 0 0) (length 5.08) (name "A0" (effects (font (size 1 1)))) (number "38" (effects (font (size 1 1)))))
    (pin input line (at -17.78 -2.54 0) (length 5.08) (name "A1" (effects (font (size 1 1)))) (number "39" (effects (font (size 1 1)))))
    (pin input line (at -17.78 -5.08 0) (length 5.08) (name "CLKI" (effects (font (size 1 1)))) (number "43" (effects (font (size 1 1)))))
    (pin input line (at -17.78 -7.62 0) (length 5.08) (name "XI" (effects (font (size 1 1)))) (number "41" (effects (font (size 1 1)))))
    (pin tri_state line (at 17.78 7.62 180) (length 5.08) (name "SDO" (effects (font (size 1 1)))) (number "46" (effects (font (size 1 1)))))
    (pin open_collector line (at 17.78 5.08 180) (length 5.08) (name "~{IRQ}" (effects (font (size 1 1)))) (number "1" (effects (font (size 1 1)))))
    (pin output line (at 17.78 2.54 180) (length 5.08) (name "CLKO" (effects (font (size 1 1)))) (number "44" (effects (font (size 1 1)))))
    (pin output line (at 17.78 0 180) (length 5.08) (name "XO" (effects (font (size 1 1)))) (number "42" (effects (font (size 1 1))))))
   (symbol "MAX14819AATM_2_1"
    (rectangle (start -12.7 10.16) (end 12.7 -10.16) (stroke (width 0.254) (type default)) (fill (type background)))
    (pin input line (at -17.78 7.62 0) (length 5.08) (name "TXA" (effects (font (size 1 1)))) (number "34" (effects (font (size 1 1)))))
    (pin input line (at -17.78 5.08 0) (length 5.08) (name "TXENA" (effects (font (size 1 1)))) (number "35" (effects (font (size 1 1)))))
    (pin input line (at -17.78 2.54 0) (length 5.08) (name "DIA" (effects (font (size 1 1)))) (number "14" (effects (font (size 1 1)))))
    (pin input line (at -17.78 0 0) (length 5.08) (name "L+A" (effects (font (size 1 1)))) (number "13" (effects (font (size 1 1)))))
    (pin passive line (at -17.78 -2.54 0) (length 5.08) (name "SN1A" (effects (font (size 1 1)))) (number "10" (effects (font (size 1 1)))))
    (pin passive line (at -17.78 -5.08 0) (length 5.08) (name "SN2A" (effects (font (size 1 1)))) (number "11" (effects (font (size 1 1)))))
    (pin bidirectional line (at 17.78 7.62 180) (length 5.08) (name "CQA" (effects (font (size 1 1)))) (number "17" (effects (font (size 1 1)))))
    (pin output line (at 17.78 5.08 180) (length 5.08) (name "RXA" (effects (font (size 1 1)))) (number "36" (effects (font (size 1 1)))))
    (pin output line (at 17.78 2.54 180) (length 5.08) (name "LIA" (effects (font (size 1 1)))) (number "37" (effects (font (size 1 1)))))
    (pin open_collector line (at 17.78 0 180) (length 5.08) (name "RXRDYA/LD1A" (effects (font (size 1 1)))) (number "2" (effects (font (size 1 1)))))
    (pin open_collector line (at 17.78 -2.54 180) (length 5.08) (name "RXERRA/LD2A" (effects (font (size 1 1)))) (number "3" (effects (font (size 1 1)))))
    (pin output line (at 17.78 -5.08 180) (length 5.08) (name "G1A" (effects (font (size 1 1)))) (number "9" (effects (font (size 1 1)))))
    (pin output line (at 17.78 -7.62 180) (length 5.08) (name "G2A" (effects (font (size 1 1)))) (number "12" (effects (font (size 1 1))))))
   (symbol "MAX14819AATM_3_1"
    (rectangle (start -12.7 10.16) (end 12.7 -10.16) (stroke (width 0.254) (type default)) (fill (type background)))
    (pin input line (at -17.78 7.62 0) (length 5.08) (name "TXB" (effects (font (size 1 1)))) (number "33" (effects (font (size 1 1)))))
    (pin input line (at -17.78 5.08 0) (length 5.08) (name "TXENB" (effects (font (size 1 1)))) (number "32" (effects (font (size 1 1)))))
    (pin input line (at -17.78 2.54 0) (length 5.08) (name "DIB" (effects (font (size 1 1)))) (number "23" (effects (font (size 1 1)))))
    (pin input line (at -17.78 0 0) (length 5.08) (name "L+B" (effects (font (size 1 1)))) (number "24" (effects (font (size 1 1)))))
    (pin passive line (at -17.78 -2.54 0) (length 5.08) (name "SN1B" (effects (font (size 1 1)))) (number "27" (effects (font (size 1 1)))))
    (pin passive line (at -17.78 -5.08 0) (length 5.08) (name "SN2B" (effects (font (size 1 1)))) (number "26" (effects (font (size 1 1)))))
    (pin bidirectional line (at 17.78 7.62 180) (length 5.08) (name "CQB" (effects (font (size 1 1)))) (number "20" (effects (font (size 1 1)))))
    (pin output line (at 17.78 5.08 180) (length 5.08) (name "RXB" (effects (font (size 1 1)))) (number "31" (effects (font (size 1 1)))))
    (pin output line (at 17.78 2.54 180) (length 5.08) (name "LIB" (effects (font (size 1 1)))) (number "30" (effects (font (size 1 1)))))
    (pin open_collector line (at 17.78 0 180) (length 5.08) (name "RXRDYB/LD1B" (effects (font (size 1 1)))) (number "4" (effects (font (size 1 1)))))
    (pin open_collector line (at 17.78 -2.54 180) (length 5.08) (name "RXERRB/LD2B" (effects (font (size 1 1)))) (number "5" (effects (font (size 1 1)))))
    (pin output line (at 17.78 -5.08 180) (length 5.08) (name "G1B" (effects (font (size 1 1)))) (number "28" (effects (font (size 1 1)))))
    (pin output line (at 17.78 -7.62 180) (length 5.08) (name "G2B" (effects (font (size 1 1)))) (number "25" (effects (font (size 1 1))))))
   (symbol "MAX14819AATM_4_1"
    (rectangle (start -12.7 8.89) (end 12.7 -8.89) (stroke (width 0.254) (type default)) (fill (type background)))
    (pin power_in line (at -17.78 6.35 0) (length 5.08) (name "VCC" (effects (font (size 1 1)))) (number "8" (effects (font (size 1 1)))))
    (pin power_in line (at -17.78 3.81 0) (length 5.08) (name "VCC" (effects (font (size 1 1)))) (number "29" (effects (font (size 1 1)))))
    (pin power_in line (at -17.78 1.27 0) (length 5.08) (name "VL" (effects (font (size 1 1)))) (number "40" (effects (font (size 1 1)))))
    (pin power_in line (at -17.78 -1.27 0) (length 5.08) (name "V5" (effects (font (size 1 1)))) (number "6" (effects (font (size 1 1)))))
    (pin input line (at -17.78 -3.81 0) (length 5.08) (name "REGEN" (effects (font (size 1 1)))) (number "7" (effects (font (size 1 1)))))
    (pin power_in line (at -17.78 -6.35 0) (length 5.08) (name "EP/GND" (effects (font (size 1 1)))) (number "49" (effects (font (size 1 1)))))
    (pin no_connect line (at 17.78 6.35 180) (length 5.08) (name "NC" (effects (font (size 1 1)))) (number "15" (effects (font (size 1 1)))))
    (pin no_connect line (at 17.78 3.81 180) (length 5.08) (name "NC" (effects (font (size 1 1)))) (number "16" (effects (font (size 1 1)))))
    (pin no_connect line (at 17.78 1.27 180) (length 5.08) (name "NC" (effects (font (size 1 1)))) (number "18" (effects (font (size 1 1)))))
    (pin no_connect line (at 17.78 -1.27 180) (length 5.08) (name "NC" (effects (font (size 1 1)))) (number "19" (effects (font (size 1 1)))))
    (pin no_connect line (at 17.78 -3.81 180) (length 5.08) (name "NC" (effects (font (size 1 1)))) (number "21" (effects (font (size 1 1)))))
    (pin no_connect line (at 17.78 -6.35 180) (length 5.08) (name "NC" (effects (font (size 1 1)))) (number "22" (effects (font (size 1 1)))))))
  (symbol "power:+3V3"
   (power)
   (pin_numbers (hide yes))
   (pin_names
    (offset 0) (hide yes)) (exclude_from_sim no) (in_bom yes) (on_board yes)
   (property "Reference" "#PWR" (at 0 -3.81 0) (effects (font (size 1.27 1.27)) (hide yes)))
   (property "Value" "+3V3" (at 0 3.556 0) (effects (font (size 1.27 1.27))))
   (property "Footprint" "" (at 0 0 0) (effects (font (size 1.27 1.27)) (hide yes)))
   (property "Datasheet" "" (at 0 0 0) (effects (font (size 1.27 1.27)) (hide yes)))
   (property "Description" "Power symbol creates a global label with name \"+3V3\"" (at 0 0 0) (effects (font (size 1.27 1.27)) (hide yes)))
   (symbol "+3V3_0_1"
    (polyline (pts (xy -0.762 1.27) (xy 0 2.54)) (stroke (width 0) (type default)) (fill (type none)))
    (polyline (pts (xy 0 2.54) (xy 0.762 1.27)) (stroke (width 0) (type default)) (fill (type none)))
    (polyline (pts (xy 0 0) (xy 0 2.54)) (stroke (width 0) (type default)) (fill (type none))))
   (symbol "+3V3_1_1"
    (pin power_in line (at 0 0 90) (length 0) (name "~" (effects (font (size 1.27 1.27)))) (number "1" (effects (font (size 1.27 1.27))))))
   (embedded_fonts no))
  (symbol "power:+5V"
   (power)
   (pin_numbers (hide yes))
   (pin_names
    (offset 0) (hide yes)) (exclude_from_sim no) (in_bom yes) (on_board yes)
   (property "Reference" "#PWR" (at 0 -3.81 0) (effects (font (size 1.27 1.27)) (hide yes)))
   (property "Value" "+5V" (at 0 3.556 0) (effects (font (size 1.27 1.27))))
   (property "Footprint" "" (at 0 0 0) (effects (font (size 1.27 1.27)) (hide yes)))
   (property "Datasheet" "" (at 0 0 0) (effects (font (size 1.27 1.27)) (hide yes)))
   (property "Description" "Power symbol creates a global label with name \"+5V\"" (at 0 0 0) (effects (font (size 1.27 1.27)) (hide yes)))
   (symbol "+5V_0_1"
    (polyline (pts (xy -0.762 1.27) (xy 0 2.54)) (stroke (width 0) (type default)) (fill (type none)))
    (polyline (pts (xy 0 2.54) (xy 0.762 1.27)) (stroke (width 0) (type default)) (fill (type none)))
    (polyline (pts (xy 0 0) (xy 0 2.54)) (stroke (width 0) (type default)) (fill (type none))))
   (symbol "+5V_1_1"
    (pin power_in line (at 0 0 90) (length 0) (name "~" (effects (font (size 1.27 1.27)))) (number "1" (effects (font (size 1.27 1.27))))))
   (embedded_fonts no))
  (symbol "power:GND"
   (power)
   (pin_numbers (hide yes))
   (pin_names
    (offset 0) (hide yes)) (exclude_from_sim no) (in_bom yes) (on_board yes)
   (property "Reference" "#PWR" (at 0 -6.35 0) (effects (font (size 1.27 1.27)) (hide yes)))
   (property "Value" "GND" (at 0 -3.81 0) (effects (font (size 1.27 1.27))))
   (property "Footprint" "" (at 0 0 0) (effects (font (size 1.27 1.27)) (hide yes)))
   (property "Datasheet" "" (at 0 0 0) (effects (font (size 1.27 1.27)) (hide yes)))
   (property "Description" "Power symbol creates a global label with name \"GND\" , ground" (at 0 0 0) (effects (font (size 1.27 1.27)) (hide yes)))
   (symbol "GND_0_1"
    (polyline (pts (xy 0 0) (xy 0 -1.27) (xy 1.27 -1.27) (xy 0 -2.54) (xy -1.27 -1.27) (xy 0 -1.27)) (stroke (width 0) (type default)) (fill (type none))))
   (symbol "GND_1_1"
    (pin power_in line (at 0 0 270) (length 0) (name "~" (effects (font (size 1.27 1.27)))) (number "1" (effects (font (size 1.27 1.27))))))
   (embedded_fonts no)))
 (text "MAX14819AATM+ | LEFT + CENTER"
  (at 15 12 0)
  (effects (font (size 2 2)) (justify left top)))
 (text "SPI framer. VCC = 24 V; VL = 3.3 V; external V5 = 5 V; REGEN = GND.\nL+ controllers omitted: sensors use fused 24 V directly. Disable L+ diagnostics in firmware."
  (at 15 23 0)
  (effects (font (size 1.15 1.15)) (justify left top)))
 (global_label "IOL_CS_A"
  (shape bidirectional)
  (at 63.5 66.04 180)
  (effects (font (size 1 1)) (justify right))
  (property "Intersheetrefs" "${INTERSHEET_REFS}" (at 63.5 66.04 0) (effects (font (size 1 1)) (hide yes))))
 (global_label "IOL_SCK"
  (shape bidirectional)
  (at 63.5 68.58 180)
  (effects (font (size 1 1)) (justify right))
  (property "Intersheetrefs" "${INTERSHEET_REFS}" (at 63.5 68.58 0) (effects (font (size 1 1)) (hide yes))))
 (global_label "IOL_MOSI"
  (shape bidirectional)
  (at 63.5 71.12 180)
  (effects (font (size 1 1)) (justify right))
  (property "Intersheetrefs" "${INTERSHEET_REFS}" (at 63.5 71.12 0) (effects (font (size 1 1)) (hide yes))))
 (global_label "GND"
  (shape bidirectional)
  (at 63.5 73.66 180)
  (effects (font (size 1 1)) (justify right))
  (property "Intersheetrefs" "${INTERSHEET_REFS}" (at 63.5 73.66 0) (effects (font (size 1 1)) (hide yes))))
 (global_label "GND"
  (shape bidirectional)
  (at 63.5 76.2 180)
  (effects (font (size 1 1)) (justify right))
  (property "Intersheetrefs" "${INTERSHEET_REFS}" (at 63.5 76.2 0) (effects (font (size 1 1)) (hide yes))))
 (global_label "GND"
  (shape bidirectional)
  (at 63.5 78.74 180)
  (effects (font (size 1 1)) (justify right))
  (property "Intersheetrefs" "${INTERSHEET_REFS}" (at 63.5 78.74 0) (effects (font (size 1 1)) (hide yes))))
 (global_label "PHY0_XI"
  (shape bidirectional)
  (at 63.5 81.28 180)
  (effects (font (size 1 1)) (justify right))
  (property "Intersheetrefs" "${INTERSHEET_REFS}" (at 63.5 81.28 0) (effects (font (size 1 1)) (hide yes))))
 (global_label "IOL_MISO"
  (shape bidirectional)
  (at 114.3 66.04 0)
  (effects (font (size 1 1)) (justify left))
  (property "Intersheetrefs" "${INTERSHEET_REFS}" (at 114.3 66.04 0) (effects (font (size 1 1)) (hide yes))))
 (global_label "IOL_IRQ_A"
  (shape bidirectional)
  (at 114.3 68.58 0)
  (effects (font (size 1 1)) (justify left))
  (property "Intersheetrefs" "${INTERSHEET_REFS}" (at 114.3 68.58 0) (effects (font (size 1 1)) (hide yes))))
 (no_connect
  (at 106.68 71.12))
 (global_label "PHY0_XO"
  (shape bidirectional)
  (at 114.3 73.66 0)
  (effects (font (size 1 1)) (justify left))
  (property "Intersheetrefs" "${INTERSHEET_REFS}" (at 114.3 73.66 0) (effects (font (size 1 1)) (hide yes))))
 (global_label "IOL_CS_A"
  (shape bidirectional)
  (at 157.48 72.39 0)
  (effects (font (size 1 1)) (justify left))
  (property "Intersheetrefs" "${INTERSHEET_REFS}" (at 157.48 72.39 0) (effects (font (size 1 1)) (hide yes))))
 (global_label "IOL_IRQ_A"
  (shape bidirectional)
  (at 198.12 72.39 0)
  (effects (font (size 1 1)) (justify left))
  (property "Intersheetrefs" "${INTERSHEET_REFS}" (at 198.12 72.39 0) (effects (font (size 1 1)) (hide yes))))
 (global_label "PHY0_XI"
  (shape bidirectional)
  (at 139.7 116.84 180)
  (effects (font (size 1 1)) (justify right))
  (property "Intersheetrefs" "${INTERSHEET_REFS}" (at 139.7 116.84 0) (effects (font (size 1 1)) (hide yes))))
 (global_label "PHY0_XO"
  (shape bidirectional)
  (at 200.66 116.84 0)
  (effects (font (size 1 1)) (justify left))
  (property "Intersheetrefs" "${INTERSHEET_REFS}" (at 200.66 116.84 0) (effects (font (size 1 1)) (hide yes))))
 (text "HCM4914745600ABJT, CL18 pF.\n22 pF external/leg: initial tuning value,\n10 pF internal + estimated 4 pF stray/leg.\nVerify frequency and startup on PCB."
  (at 123 156 0)
  (effects (font (size 1.1 1.1)) (justify left top)))
 (global_label "+24V_SENS"
  (shape bidirectional)
  (at 274.32 67.31 180)
  (effects (font (size 1 1)) (justify right))
  (property "Intersheetrefs" "${INTERSHEET_REFS}" (at 274.32 67.31 0) (effects (font (size 1 1)) (hide yes))))
 (global_label "+24V_SENS"
  (shape bidirectional)
  (at 274.32 69.85 180)
  (effects (font (size 1 1)) (justify right))
  (property "Intersheetrefs" "${INTERSHEET_REFS}" (at 274.32 69.85 0) (effects (font (size 1 1)) (hide yes))))
 (global_label "+3V3"
  (shape bidirectional)
  (at 274.32 72.39 180)
  (effects (font (size 1 1)) (justify right))
  (property "Intersheetrefs" "${INTERSHEET_REFS}" (at 274.32 72.39 0) (effects (font (size 1 1)) (hide yes))))
 (global_label "+5V"
  (shape bidirectional)
  (at 274.32 74.93 180)
  (effects (font (size 1 1)) (justify right))
  (property "Intersheetrefs" "${INTERSHEET_REFS}" (at 274.32 74.93 0) (effects (font (size 1 1)) (hide yes))))
 (global_label "GND"
  (shape bidirectional)
  (at 274.32 77.47 180)
  (effects (font (size 1 1)) (justify right))
  (property "Intersheetrefs" "${INTERSHEET_REFS}" (at 274.32 77.47 0) (effects (font (size 1 1)) (hide yes))))
 (global_label "GND"
  (shape bidirectional)
  (at 274.32 80.01 180)
  (effects (font (size 1 1)) (justify right))
  (property "Intersheetrefs" "${INTERSHEET_REFS}" (at 274.32 80.01 0) (effects (font (size 1 1)) (hide yes))))
 (no_connect
  (at 317.5 67.31))
 (no_connect
  (at 317.5 69.85))
 (no_connect
  (at 317.5 72.39))
 (no_connect
  (at 317.5 74.93))
 (no_connect
  (at 317.5 77.47))
 (no_connect
  (at 317.5 80.01))
 (global_label "+24V_SENS"
  (shape bidirectional)
  (at 248.92 115.57 0)
  (effects (font (size 1 1)) (justify left))
  (property "Intersheetrefs" "${INTERSHEET_REFS}" (at 248.92 115.57 0) (effects (font (size 1 1)) (hide yes))))
 (global_label "+24V_SENS"
  (shape bidirectional)
  (at 292.1 115.57 0)
  (effects (font (size 1 1)) (justify left))
  (property "Intersheetrefs" "${INTERSHEET_REFS}" (at 292.1 115.57 0) (effects (font (size 1 1)) (hide yes))))
 (global_label "GND"
  (shape bidirectional)
  (at 60.96 210.82 180)
  (effects (font (size 1 1)) (justify right))
  (property "Intersheetrefs" "${INTERSHEET_REFS}" (at 60.96 210.82 0) (effects (font (size 1 1)) (hide yes))))
 (global_label "GND"
  (shape bidirectional)
  (at 60.96 213.36 180)
  (effects (font (size 1 1)) (justify right))
  (property "Intersheetrefs" "${INTERSHEET_REFS}" (at 60.96 213.36 0) (effects (font (size 1 1)) (hide yes))))
 (global_label "GND"
  (shape bidirectional)
  (at 60.96 215.9 180)
  (effects (font (size 1 1)) (justify right))
  (property "Intersheetrefs" "${INTERSHEET_REFS}" (at 60.96 215.9 0) (effects (font (size 1 1)) (hide yes))))
 (global_label "GND"
  (shape bidirectional)
  (at 60.96 218.44 180)
  (effects (font (size 1 1)) (justify right))
  (property "Intersheetrefs" "${INTERSHEET_REFS}" (at 60.96 218.44 0) (effects (font (size 1 1)) (hide yes))))
 (global_label "PHY0_SN_A"
  (shape bidirectional)
  (at 60.96 220.98 180)
  (effects (font (size 1 1)) (justify right))
  (property "Intersheetrefs" "${INTERSHEET_REFS}" (at 60.96 220.98 0) (effects (font (size 1 1)) (hide yes))))
 (global_label "PHY0_SN_A"
  (shape bidirectional)
  (at 60.96 223.52 180)
  (effects (font (size 1 1)) (justify right))
  (property "Intersheetrefs" "${INTERSHEET_REFS}" (at 60.96 223.52 0) (effects (font (size 1 1)) (hide yes))))
 (global_label "IOL_CQ_L"
  (shape bidirectional)
  (at 111.76 210.82 0)
  (effects (font (size 1 1)) (justify left))
  (property "Intersheetrefs" "${INTERSHEET_REFS}" (at 111.76 210.82 0) (effects (font (size 1 1)) (hide yes))))
 (no_connect
  (at 104.14 213.36))
 (no_connect
  (at 104.14 215.9))
 (no_connect
  (at 104.14 218.44))
 (no_connect
  (at 104.14 220.98))
 (no_connect
  (at 104.14 223.52))
 (no_connect
  (at 104.14 226.06))
 (global_label "GND"
  (shape bidirectional)
  (at 264.16 210.82 180)
  (effects (font (size 1 1)) (justify right))
  (property "Intersheetrefs" "${INTERSHEET_REFS}" (at 264.16 210.82 0) (effects (font (size 1 1)) (hide yes))))
 (global_label "GND"
  (shape bidirectional)
  (at 264.16 213.36 180)
  (effects (font (size 1 1)) (justify right))
  (property "Intersheetrefs" "${INTERSHEET_REFS}" (at 264.16 213.36 0) (effects (font (size 1 1)) (hide yes))))
 (global_label "GND"
  (shape bidirectional)
  (at 264.16 215.9 180)
  (effects (font (size 1 1)) (justify right))
  (property "Intersheetrefs" "${INTERSHEET_REFS}" (at 264.16 215.9 0) (effects (font (size 1 1)) (hide yes))))
 (global_label "GND"
  (shape bidirectional)
  (at 264.16 218.44 180)
  (effects (font (size 1 1)) (justify right))
  (property "Intersheetrefs" "${INTERSHEET_REFS}" (at 264.16 218.44 0) (effects (font (size 1 1)) (hide yes))))
 (global_label "PHY0_SN_B"
  (shape bidirectional)
  (at 264.16 220.98 180)
  (effects (font (size 1 1)) (justify right))
  (property "Intersheetrefs" "${INTERSHEET_REFS}" (at 264.16 220.98 0) (effects (font (size 1 1)) (hide yes))))
 (global_label "PHY0_SN_B"
  (shape bidirectional)
  (at 264.16 223.52 180)
  (effects (font (size 1 1)) (justify right))
  (property "Intersheetrefs" "${INTERSHEET_REFS}" (at 264.16 223.52 0) (effects (font (size 1 1)) (hide yes))))
 (global_label "IOL_CQ_C"
  (shape bidirectional)
  (at 314.96 210.82 0)
  (effects (font (size 1 1)) (justify left))
  (property "Intersheetrefs" "${INTERSHEET_REFS}" (at 314.96 210.82 0) (effects (font (size 1 1)) (hide yes))))
 (no_connect
  (at 307.34 213.36))
 (no_connect
  (at 307.34 215.9))
 (no_connect
  (at 307.34 218.44))
 (no_connect
  (at 307.34 220.98))
 (no_connect
  (at 307.34 223.52))
 (no_connect
  (at 307.34 226.06))
 (text "TX/TXEN LOW: select internal framer in registers before use. A0/A1 LOW, independent CS.\nExposed pad to ground plane. Unused SN1/SN2 tied together, otherwise floating per ADI instructions.\nL+ diagnostics: L+ outputs unused; disable their fault reporting. Short robot harness."
  (at 15 256 0)
  (effects (font (size 1.1 1.1)) (justify left top)))
 (wire
  (pts (xy 71.12 66.04) (xy 63.5 66.04))
  (stroke (width 0) (type default)))
 (wire
  (pts (xy 71.12 68.58) (xy 63.5 68.58))
  (stroke (width 0) (type default)))
 (wire
  (pts (xy 71.12 71.12) (xy 63.5 71.12))
  (stroke (width 0) (type default)))
 (wire
  (pts (xy 71.12 73.66) (xy 63.5 73.66))
  (stroke (width 0) (type default)))
 (wire
  (pts (xy 71.12 76.2) (xy 63.5 76.2))
  (stroke (width 0) (type default)))
 (wire
  (pts (xy 71.12 78.74) (xy 63.5 78.74))
  (stroke (width 0) (type default)))
 (wire
  (pts (xy 71.12 81.28) (xy 63.5 81.28))
  (stroke (width 0) (type default)))
 (wire
  (pts (xy 106.68 66.04) (xy 114.3 66.04))
  (stroke (width 0) (type default)))
 (wire
  (pts (xy 106.68 68.58) (xy 114.3 68.58))
  (stroke (width 0) (type default)))
 (wire
  (pts (xy 106.68 73.66) (xy 114.3 73.66))
  (stroke (width 0) (type default)))
 (wire
  (pts (xy 157.48 57.15) (xy 157.48 49.53))
  (stroke (width 0) (type default)))
 (wire
  (pts (xy 157.48 64.77) (xy 157.48 72.39))
  (stroke (width 0) (type default)))
 (wire
  (pts (xy 198.12 57.15) (xy 198.12 49.53))
  (stroke (width 0) (type default)))
 (wire
  (pts (xy 198.12 64.77) (xy 198.12 72.39))
  (stroke (width 0) (type default)))
 (wire
  (pts (xy 139.7 143.51) (xy 139.7 151.13))
  (stroke (width 0) (type default)))
 (wire
  (pts (xy 166.37 116.84) (xy 139.7 116.84))
  (stroke (width 0) (type default)))
 (wire
  (pts (xy 139.7 116.84) (xy 139.7 135.89))
  (stroke (width 0) (type default)))
 (wire
  (pts (xy 200.66 143.51) (xy 200.66 151.13))
  (stroke (width 0) (type default)))
 (wire
  (pts (xy 173.99 116.84) (xy 200.66 116.84))
  (stroke (width 0) (type default)))
 (wire
  (pts (xy 200.66 116.84) (xy 200.66 135.89))
  (stroke (width 0) (type default)))
 (wire
  (pts (xy 281.94 67.31) (xy 274.32 67.31))
  (stroke (width 0) (type default)))
 (wire
  (pts (xy 281.94 69.85) (xy 274.32 69.85))
  (stroke (width 0) (type default)))
 (wire
  (pts (xy 281.94 72.39) (xy 274.32 72.39))
  (stroke (width 0) (type default)))
 (wire
  (pts (xy 281.94 74.93) (xy 274.32 74.93))
  (stroke (width 0) (type default)))
 (wire
  (pts (xy 281.94 77.47) (xy 274.32 77.47))
  (stroke (width 0) (type default)))
 (wire
  (pts (xy 281.94 80.01) (xy 274.32 80.01))
  (stroke (width 0) (type default)))
 (wire
  (pts (xy 248.92 123.19) (xy 248.92 115.57))
  (stroke (width 0) (type default)))
 (wire
  (pts (xy 248.92 130.81) (xy 248.92 138.43))
  (stroke (width 0) (type default)))
 (wire
  (pts (xy 292.1 123.19) (xy 292.1 115.57))
  (stroke (width 0) (type default)))
 (wire
  (pts (xy 292.1 130.81) (xy 292.1 138.43))
  (stroke (width 0) (type default)))
 (wire
  (pts (xy 335.28 123.19) (xy 335.28 115.57))
  (stroke (width 0) (type default)))
 (wire
  (pts (xy 335.28 130.81) (xy 335.28 138.43))
  (stroke (width 0) (type default)))
 (wire
  (pts (xy 378.46 123.19) (xy 378.46 115.57))
  (stroke (width 0) (type default)))
 (wire
  (pts (xy 378.46 130.81) (xy 378.46 138.43))
  (stroke (width 0) (type default)))
 (wire
  (pts (xy 68.58 210.82) (xy 60.96 210.82))
  (stroke (width 0) (type default)))
 (wire
  (pts (xy 68.58 213.36) (xy 60.96 213.36))
  (stroke (width 0) (type default)))
 (wire
  (pts (xy 68.58 215.9) (xy 60.96 215.9))
  (stroke (width 0) (type default)))
 (wire
  (pts (xy 68.58 218.44) (xy 60.96 218.44))
  (stroke (width 0) (type default)))
 (wire
  (pts (xy 68.58 220.98) (xy 60.96 220.98))
  (stroke (width 0) (type default)))
 (wire
  (pts (xy 68.58 223.52) (xy 60.96 223.52))
  (stroke (width 0) (type default)))
 (wire
  (pts (xy 104.14 210.82) (xy 111.76 210.82))
  (stroke (width 0) (type default)))
 (wire
  (pts (xy 271.78 210.82) (xy 264.16 210.82))
  (stroke (width 0) (type default)))
 (wire
  (pts (xy 271.78 213.36) (xy 264.16 213.36))
  (stroke (width 0) (type default)))
 (wire
  (pts (xy 271.78 215.9) (xy 264.16 215.9))
  (stroke (width 0) (type default)))
 (wire
  (pts (xy 271.78 218.44) (xy 264.16 218.44))
  (stroke (width 0) (type default)))
 (wire
  (pts (xy 271.78 220.98) (xy 264.16 220.98))
  (stroke (width 0) (type default)))
 (wire
  (pts (xy 271.78 223.52) (xy 264.16 223.52))
  (stroke (width 0) (type default)))
 (wire
  (pts (xy 307.34 210.82) (xy 314.96 210.82))
  (stroke (width 0) (type default)))
 (symbol
  (lib_id "Levi:MAX14819AATM")
  (at 88.9 73.66 0)
  (unit 1)
  (exclude_from_sim no)
  (in_bom yes)
  (on_board yes)
  (dnp no)
  (property "Reference" "U30" (at 88.9 58.54 0) (effects (font (size 1.1 1.1))))
  (property "Value" "MAX14819AATM" (at 88.9 60.74 0) (effects (font (size 1 1))))
  (property "Footprint" "Levi:MAX14819_T4877_4C_EP5.5" (at 88.9 73.66 0) (effects (font (size 1.1 1.1)) (hide yes)))
  (property "Datasheet" "https://www.analog.com/media/en/technical-documentation/data-sheets/max14819.pdf" (at 88.9 73.66 0) (effects (font (size 1.1 1.1)) (hide yes)))
  (pin "48")
  (pin "47")
  (pin "45")
  (pin "38")
  (pin "39")
  (pin "43")
  (pin "41")
  (pin "46")
  (pin "1")
  (pin "44")
  (pin "42"))
 (symbol
  (lib_id "Device:R")
  (at 157.48 60.96 0)
  (unit 1)
  (exclude_from_sim no)
  (in_bom yes)
  (on_board yes)
  (dnp no)
  (property "Reference" "R55" (at 161.48 59.16 0) (effects (font (size 1.1 1.1)) (justify left)))
  (property "Value" "10k" (at 161.48 61.36 0) (effects (font (size 1 1)) (justify left)))
  (property "Footprint" "Resistor_SMD:R_0805_2012Metric" (at 157.48 60.96 0) (effects (font (size 1.1 1.1)) (hide yes) (justify left)))
  (property "Datasheet" "~" (at 157.48 60.96 0) (effects (font (size 1.1 1.1)) (hide yes) (justify left)))
  (pin "1")
  (pin "2"))
 (symbol
  (lib_id "power:+3V3")
  (at 157.48 49.53 0)
  (unit 1)
  (exclude_from_sim no)
  (in_bom no)
  (on_board no)
  (dnp no)
  (property "Reference" "#PWR68" (at 157.48 43.53 0) (effects (font (size 1.1 1.1)) (hide yes)))
  (property "Value" "+3V3" (at 157.48 45.73 0) (effects (font (size 1 1))))
  (property "Footprint" "" (at 157.48 49.53 0) (effects (font (size 1.1 1.1)) (hide yes)))
  (property "Datasheet" "" (at 157.48 49.53 0) (effects (font (size 1.1 1.1)) (hide yes)))
  (pin "1"))
 (symbol
  (lib_id "Device:R")
  (at 198.12 60.96 0)
  (unit 1)
  (exclude_from_sim no)
  (in_bom yes)
  (on_board yes)
  (dnp no)
  (property "Reference" "R56" (at 202.12 59.16 0) (effects (font (size 1.1 1.1)) (justify left)))
  (property "Value" "4.7k" (at 202.12 61.36 0) (effects (font (size 1 1)) (justify left)))
  (property "Footprint" "Resistor_SMD:R_0805_2012Metric" (at 198.12 60.96 0) (effects (font (size 1.1 1.1)) (hide yes) (justify left)))
  (property "Datasheet" "~" (at 198.12 60.96 0) (effects (font (size 1.1 1.1)) (hide yes) (justify left)))
  (pin "1")
  (pin "2"))
 (symbol
  (lib_id "power:+3V3")
  (at 198.12 49.53 0)
  (unit 1)
  (exclude_from_sim no)
  (in_bom no)
  (on_board no)
  (dnp no)
  (property "Reference" "#PWR69" (at 198.12 43.53 0) (effects (font (size 1.1 1.1)) (hide yes)))
  (property "Value" "+3V3" (at 198.12 45.73 0) (effects (font (size 1 1))))
  (property "Footprint" "" (at 198.12 49.53 0) (effects (font (size 1.1 1.1)) (hide yes)))
  (property "Datasheet" "" (at 198.12 49.53 0) (effects (font (size 1.1 1.1)) (hide yes)))
  (pin "1"))
 (symbol
  (lib_id "Device:Crystal")
  (at 170.18 116.84 0)
  (unit 1)
  (exclude_from_sim no)
  (in_bom yes)
  (on_board yes)
  (dnp no)
  (property "Reference" "Y1" (at 170.18 109.34 0) (effects (font (size 1.1 1.1)) (justify left)))
  (property "Value" "14.7456MHz CL18pF" (at 170.18 111.54 0) (effects (font (size 1 1)) (justify left)))
  (property "Footprint" "Crystal:Crystal_SMD_HC49-SD" (at 170.18 116.84 0) (effects (font (size 1.1 1.1)) (hide yes) (justify left)))
  (property "Datasheet" "https://www.digikey.com/en/products/detail/citizen-finedevice-co-ltd/HCM4914745600ABJT/284279" (at 170.18 116.84 0) (effects (font (size 1.1 1.1)) (hide yes) (justify left)))
  (pin "1")
  (pin "2"))
 (symbol
  (lib_id "Device:C")
  (at 139.7 139.7 0)
  (unit 1)
  (exclude_from_sim no)
  (in_bom yes)
  (on_board yes)
  (dnp no)
  (property "Reference" "C27" (at 143.7 137.9 0) (effects (font (size 1.1 1.1)) (justify left)))
  (property "Value" "22p C0G" (at 143.7 140.1 0) (effects (font (size 1 1)) (justify left)))
  (property "Footprint" "Capacitor_SMD:C_0805_2012Metric" (at 139.7 139.7 0) (effects (font (size 1.1 1.1)) (hide yes) (justify left)))
  (property "Datasheet" "~" (at 139.7 139.7 0) (effects (font (size 1.1 1.1)) (hide yes) (justify left)))
  (pin "1")
  (pin "2"))
 (symbol
  (lib_id "power:GND")
  (at 139.7 151.13 0)
  (unit 1)
  (exclude_from_sim no)
  (in_bom no)
  (on_board no)
  (dnp no)
  (property "Reference" "#PWR70" (at 139.7 154.13 0) (effects (font (size 1.1 1.1)) (hide yes)))
  (property "Value" "GND" (at 139.7 156.33 0) (effects (font (size 1 1))))
  (property "Footprint" "" (at 139.7 151.13 0) (effects (font (size 1.1 1.1)) (hide yes)))
  (property "Datasheet" "" (at 139.7 151.13 0) (effects (font (size 1.1 1.1)) (hide yes)))
  (pin "1"))
 (symbol
  (lib_id "Device:C")
  (at 200.66 139.7 0)
  (unit 1)
  (exclude_from_sim no)
  (in_bom yes)
  (on_board yes)
  (dnp no)
  (property "Reference" "C28" (at 204.66 137.9 0) (effects (font (size 1.1 1.1)) (justify left)))
  (property "Value" "22p C0G" (at 204.66 140.1 0) (effects (font (size 1 1)) (justify left)))
  (property "Footprint" "Capacitor_SMD:C_0805_2012Metric" (at 200.66 139.7 0) (effects (font (size 1.1 1.1)) (hide yes) (justify left)))
  (property "Datasheet" "~" (at 200.66 139.7 0) (effects (font (size 1.1 1.1)) (hide yes) (justify left)))
  (pin "1")
  (pin "2"))
 (symbol
  (lib_id "power:GND")
  (at 200.66 151.13 0)
  (unit 1)
  (exclude_from_sim no)
  (in_bom no)
  (on_board no)
  (dnp no)
  (property "Reference" "#PWR71" (at 200.66 154.13 0) (effects (font (size 1.1 1.1)) (hide yes)))
  (property "Value" "GND" (at 200.66 156.33 0) (effects (font (size 1 1))))
  (property "Footprint" "" (at 200.66 151.13 0) (effects (font (size 1.1 1.1)) (hide yes)))
  (property "Datasheet" "" (at 200.66 151.13 0) (effects (font (size 1.1 1.1)) (hide yes)))
  (pin "1"))
 (symbol
  (lib_id "Levi:MAX14819AATM")
  (at 299.72 73.66 0)
  (unit 4)
  (exclude_from_sim no)
  (in_bom yes)
  (on_board yes)
  (dnp no)
  (property "Reference" "U30" (at 299.72 59.81 0) (effects (font (size 1.1 1.1))))
  (property "Value" "MAX14819AATM" (at 299.72 62.01 0) (effects (font (size 1 1))))
  (property "Footprint" "Levi:MAX14819_T4877_4C_EP5.5" (at 299.72 73.66 0) (effects (font (size 1.1 1.1)) (hide yes)))
  (property "Datasheet" "https://www.analog.com/media/en/technical-documentation/data-sheets/max14819.pdf" (at 299.72 73.66 0) (effects (font (size 1.1 1.1)) (hide yes)))
  (pin "8")
  (pin "29")
  (pin "40")
  (pin "6")
  (pin "7")
  (pin "49")
  (pin "15")
  (pin "16")
  (pin "18")
  (pin "19")
  (pin "21")
  (pin "22"))
 (symbol
  (lib_id "Device:C")
  (at 248.92 127 0)
  (unit 1)
  (exclude_from_sim no)
  (in_bom yes)
  (on_board yes)
  (dnp no)
  (property "Reference" "C29" (at 252.92 125.2 0) (effects (font (size 1.1 1.1)) (justify left)))
  (property "Value" "1u 50V" (at 252.92 127.4 0) (effects (font (size 1 1)) (justify left)))
  (property "Footprint" "Capacitor_SMD:C_0805_2012Metric" (at 248.92 127 0) (effects (font (size 1.1 1.1)) (hide yes) (justify left)))
  (property "Datasheet" "~" (at 248.92 127 0) (effects (font (size 1.1 1.1)) (hide yes) (justify left)))
  (pin "1")
  (pin "2"))
 (symbol
  (lib_id "power:GND")
  (at 248.92 138.43 0)
  (unit 1)
  (exclude_from_sim no)
  (in_bom no)
  (on_board no)
  (dnp no)
  (property "Reference" "#PWR72" (at 248.92 141.43 0) (effects (font (size 1.1 1.1)) (hide yes)))
  (property "Value" "GND" (at 248.92 143.63 0) (effects (font (size 1 1))))
  (property "Footprint" "" (at 248.92 138.43 0) (effects (font (size 1.1 1.1)) (hide yes)))
  (property "Datasheet" "" (at 248.92 138.43 0) (effects (font (size 1.1 1.1)) (hide yes)))
  (pin "1"))
 (symbol
  (lib_id "Device:C")
  (at 292.1 127 0)
  (unit 1)
  (exclude_from_sim no)
  (in_bom yes)
  (on_board yes)
  (dnp no)
  (property "Reference" "C30" (at 296.1 125.2 0) (effects (font (size 1.1 1.1)) (justify left)))
  (property "Value" "1u 50V" (at 296.1 127.4 0) (effects (font (size 1 1)) (justify left)))
  (property "Footprint" "Capacitor_SMD:C_0805_2012Metric" (at 292.1 127 0) (effects (font (size 1.1 1.1)) (hide yes) (justify left)))
  (property "Datasheet" "~" (at 292.1 127 0) (effects (font (size 1.1 1.1)) (hide yes) (justify left)))
  (pin "1")
  (pin "2"))
 (symbol
  (lib_id "power:GND")
  (at 292.1 138.43 0)
  (unit 1)
  (exclude_from_sim no)
  (in_bom no)
  (on_board no)
  (dnp no)
  (property "Reference" "#PWR73" (at 292.1 141.43 0) (effects (font (size 1.1 1.1)) (hide yes)))
  (property "Value" "GND" (at 292.1 143.63 0) (effects (font (size 1 1))))
  (property "Footprint" "" (at 292.1 138.43 0) (effects (font (size 1.1 1.1)) (hide yes)))
  (property "Datasheet" "" (at 292.1 138.43 0) (effects (font (size 1.1 1.1)) (hide yes)))
  (pin "1"))
 (symbol
  (lib_id "Device:C")
  (at 335.28 127 0)
  (unit 1)
  (exclude_from_sim no)
  (in_bom yes)
  (on_board yes)
  (dnp no)
  (property "Reference" "C31" (at 339.28 125.2 0) (effects (font (size 1.1 1.1)) (justify left)))
  (property "Value" "1u 10V" (at 339.28 127.4 0) (effects (font (size 1 1)) (justify left)))
  (property "Footprint" "Capacitor_SMD:C_0805_2012Metric" (at 335.28 127 0) (effects (font (size 1.1 1.1)) (hide yes) (justify left)))
  (property "Datasheet" "~" (at 335.28 127 0) (effects (font (size 1.1 1.1)) (hide yes) (justify left)))
  (pin "1")
  (pin "2"))
 (symbol
  (lib_id "power:+5V")
  (at 335.28 115.57 0)
  (unit 1)
  (exclude_from_sim no)
  (in_bom no)
  (on_board no)
  (dnp no)
  (property "Reference" "#PWR74" (at 335.28 109.57 0) (effects (font (size 1.1 1.1)) (hide yes)))
  (property "Value" "+5V" (at 335.28 111.77 0) (effects (font (size 1 1))))
  (property "Footprint" "" (at 335.28 115.57 0) (effects (font (size 1.1 1.1)) (hide yes)))
  (property "Datasheet" "" (at 335.28 115.57 0) (effects (font (size 1.1 1.1)) (hide yes)))
  (pin "1"))
 (symbol
  (lib_id "power:GND")
  (at 335.28 138.43 0)
  (unit 1)
  (exclude_from_sim no)
  (in_bom no)
  (on_board no)
  (dnp no)
  (property "Reference" "#PWR75" (at 335.28 141.43 0) (effects (font (size 1.1 1.1)) (hide yes)))
  (property "Value" "GND" (at 335.28 143.63 0) (effects (font (size 1 1))))
  (property "Footprint" "" (at 335.28 138.43 0) (effects (font (size 1.1 1.1)) (hide yes)))
  (property "Datasheet" "" (at 335.28 138.43 0) (effects (font (size 1.1 1.1)) (hide yes)))
  (pin "1"))
 (symbol
  (lib_id "Device:C")
  (at 378.46 127 0)
  (unit 1)
  (exclude_from_sim no)
  (in_bom yes)
  (on_board yes)
  (dnp no)
  (property "Reference" "C32" (at 382.46 125.2 0) (effects (font (size 1.1 1.1)) (justify left)))
  (property "Value" "100n 10V" (at 382.46 127.4 0) (effects (font (size 1 1)) (justify left)))
  (property "Footprint" "Capacitor_SMD:C_0805_2012Metric" (at 378.46 127 0) (effects (font (size 1.1 1.1)) (hide yes) (justify left)))
  (property "Datasheet" "~" (at 378.46 127 0) (effects (font (size 1.1 1.1)) (hide yes) (justify left)))
  (pin "1")
  (pin "2"))
 (symbol
  (lib_id "power:+3V3")
  (at 378.46 115.57 0)
  (unit 1)
  (exclude_from_sim no)
  (in_bom no)
  (on_board no)
  (dnp no)
  (property "Reference" "#PWR76" (at 378.46 109.57 0) (effects (font (size 1.1 1.1)) (hide yes)))
  (property "Value" "+3V3" (at 378.46 111.77 0) (effects (font (size 1 1))))
  (property "Footprint" "" (at 378.46 115.57 0) (effects (font (size 1.1 1.1)) (hide yes)))
  (property "Datasheet" "" (at 378.46 115.57 0) (effects (font (size 1.1 1.1)) (hide yes)))
  (pin "1"))
 (symbol
  (lib_id "power:GND")
  (at 378.46 138.43 0)
  (unit 1)
  (exclude_from_sim no)
  (in_bom no)
  (on_board no)
  (dnp no)
  (property "Reference" "#PWR77" (at 378.46 141.43 0) (effects (font (size 1.1 1.1)) (hide yes)))
  (property "Value" "GND" (at 378.46 143.63 0) (effects (font (size 1 1))))
  (property "Footprint" "" (at 378.46 138.43 0) (effects (font (size 1.1 1.1)) (hide yes)))
  (property "Datasheet" "" (at 378.46 138.43 0) (effects (font (size 1.1 1.1)) (hide yes)))
  (pin "1"))
 (symbol
  (lib_id "Levi:MAX14819AATM")
  (at 86.36 218.44 0)
  (unit 2)
  (exclude_from_sim no)
  (in_bom yes)
  (on_board yes)
  (dnp no)
  (property "Reference" "U30" (at 86.36 203.32 0) (effects (font (size 1.1 1.1))))
  (property "Value" "MAX14819AATM" (at 86.36 205.52 0) (effects (font (size 1 1))))
  (property "Footprint" "Levi:MAX14819_T4877_4C_EP5.5" (at 86.36 218.44 0) (effects (font (size 1.1 1.1)) (hide yes)))
  (property "Datasheet" "https://www.analog.com/media/en/technical-documentation/data-sheets/max14819.pdf" (at 86.36 218.44 0) (effects (font (size 1.1 1.1)) (hide yes)))
  (pin "34")
  (pin "35")
  (pin "14")
  (pin "13")
  (pin "10")
  (pin "11")
  (pin "17")
  (pin "36")
  (pin "37")
  (pin "2")
  (pin "3")
  (pin "9")
  (pin "12"))
 (symbol
  (lib_id "Levi:MAX14819AATM")
  (at 289.56 218.44 0)
  (unit 3)
  (exclude_from_sim no)
  (in_bom yes)
  (on_board yes)
  (dnp no)
  (property "Reference" "U30" (at 289.56 203.32 0) (effects (font (size 1.1 1.1))))
  (property "Value" "MAX14819AATM" (at 289.56 205.52 0) (effects (font (size 1 1))))
  (property "Footprint" "Levi:MAX14819_T4877_4C_EP5.5" (at 289.56 218.44 0) (effects (font (size 1.1 1.1)) (hide yes)))
  (property "Datasheet" "https://www.analog.com/media/en/technical-documentation/data-sheets/max14819.pdf" (at 289.56 218.44 0) (effects (font (size 1.1 1.1)) (hide yes)))
  (pin "33")
  (pin "32")
  (pin "23")
  (pin "24")
  (pin "27")
  (pin "26")
  (pin "20")
  (pin "31")
  (pin "30")
  (pin "4")
  (pin "5")
  (pin "28")
  (pin "25"))
 (embedded_fonts no))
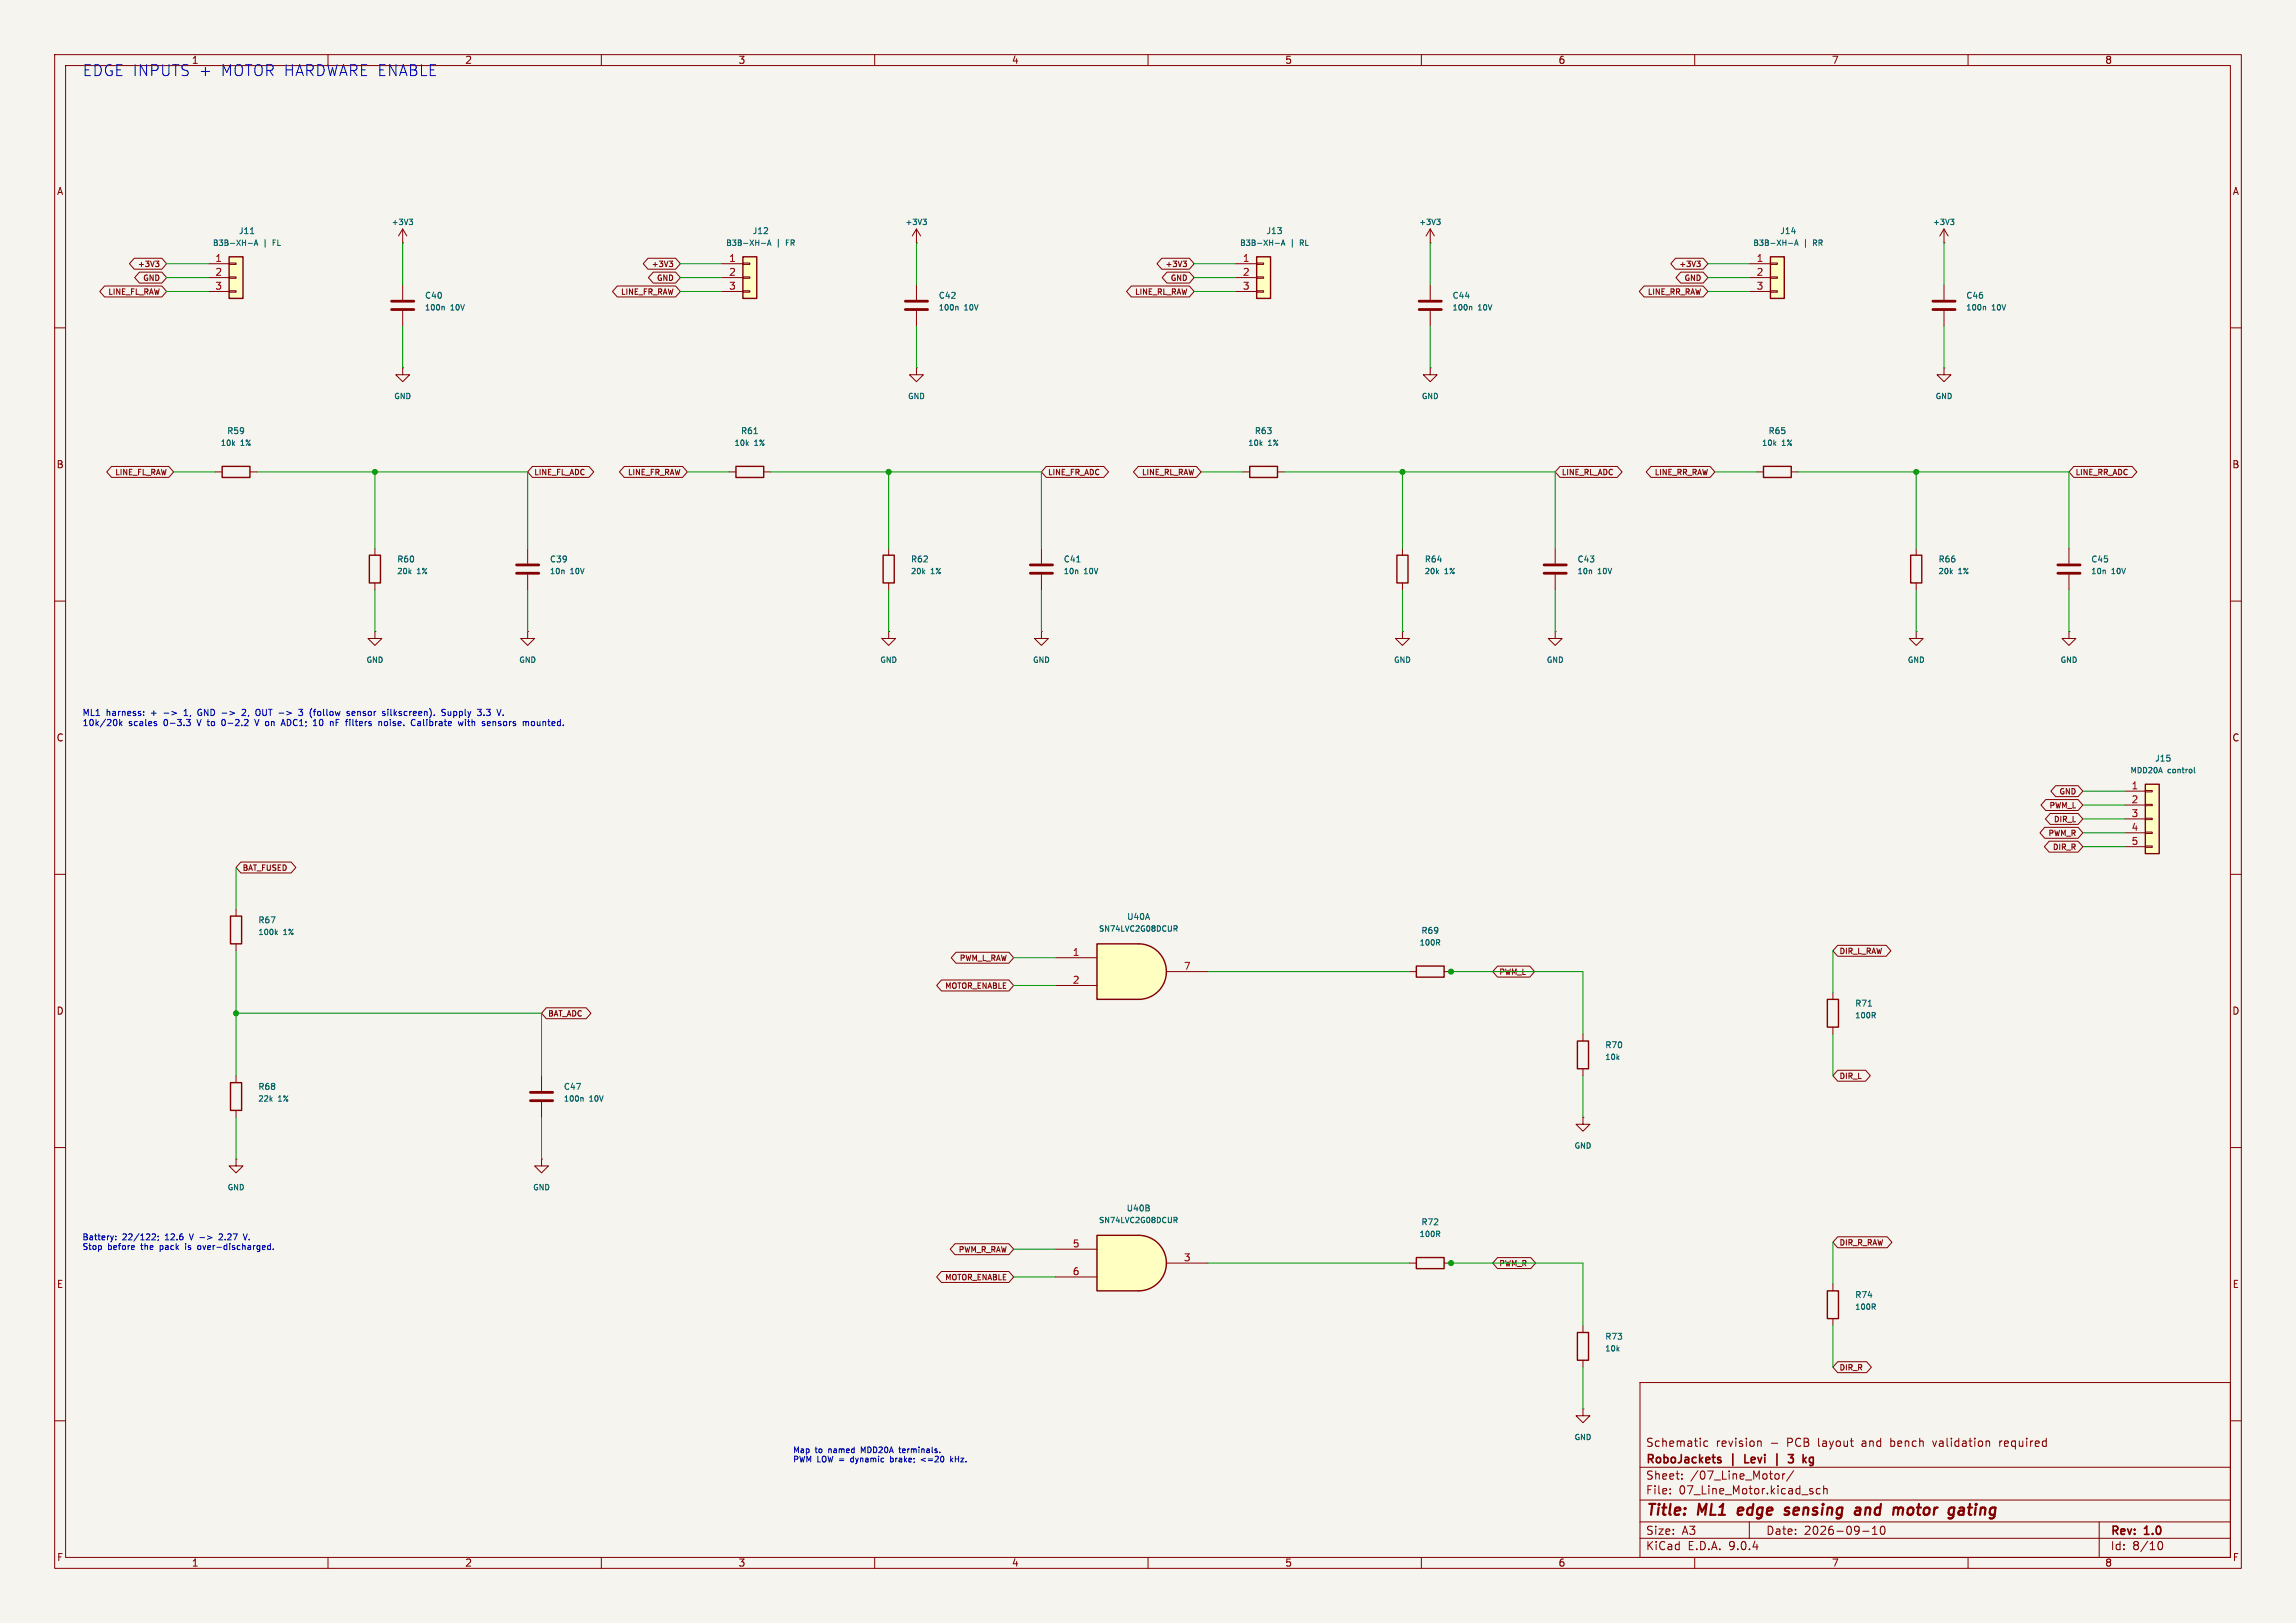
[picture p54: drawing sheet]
<svg xmlns="http://www.w3.org/2000/svg" width="420mm" height="297mm" viewBox="0 0 420 297" stroke-linecap="round" stroke-linejoin="round" font-family="sans-serif">
<defs><g id="words">
<text font-size="2.7" fill="#0000c2" x="15" y="13.8">EDGE INPUTS + MOTOR HARDWARE ENABLE</text>
<text font-size="2.7" fill="#840000" x="301" y="277.3">Title: ML1 edge sensing and motor gating</text>
<g font-size="2" fill="#840000">
<text x="301" y="267.8">RoboJackets | Levi | 3 kg</text>
<text x="301" y="264.8">Schematic revision - PCB layout and bench validation required</text>
<text x="301" y="273.5">File: 07_Line_Motor.kicad_sch</text>
<text x="301" y="270.8">Sheet: /07_Line_Motor/</text>
<text x="301" y="280.9">Size: A3</text>
<text x="323" y="280.9">Date: 2026-09-10</text>
<text x="386" y="280.9">Rev: 1.0</text>
<text x="301" y="283.7">KiCad E.D.A. 9.0.4</text>
<text x="386" y="283.7">Id: 8/10</text>
</g>
<g font-size="1.7" fill="#840000">
<text x="35" y="11.6">1</text>
<text x="85" y="11.6">2</text>
<text x="135" y="11.6">3</text>
<text x="185" y="11.6">4</text>
<text x="235" y="11.6">5</text>
<text x="285" y="11.6">6</text>
<text x="335" y="11.6">7</text>
<text x="385" y="11.6">8</text>
<text x="10.4" y="35.6">A</text>
<text x="408.4" y="35.6">A</text>
<text x="10.4" y="85.7">B</text>
<text x="408.4" y="85.7">B</text>
<text x="10.4" y="135.6">C</text>
<text x="408.4" y="135.6">C</text>
<text x="10.4" y="185.6">D</text>
<text x="408.4" y="185.6">D</text>
<text x="10.5" y="235.6">E</text>
<text x="408.5" y="235.6">E</text>
<text x="10.5" y="285.6">F</text>
<text x="35" y="286.7">1</text>
<text x="85" y="286.7">2</text>
<text x="135" y="286.7">3</text>
<text x="185" y="286.7">4</text>
<text x="235" y="286.7">5</text>
<text x="285" y="286.7">6</text>
<text x="335" y="286.7">7</text>
<text x="385" y="286.7">8</text>
<text x="408.5" y="285.6">F</text>
</g>
<g font-size="1.7" fill="#a90000">
<text x="39.6" y="48">1</text>
<text x="39.6" y="50.5">2</text>
<text x="39.6" y="53.1">3</text>
<text x="133.6" y="48">1</text>
<text x="133.6" y="50.5">2</text>
<text x="133.6" y="53.1">3</text>
<text x="227.5" y="48">1</text>
<text x="227.5" y="50.5">2</text>
<text x="227.5" y="53.1">3</text>
<text x="321.5" y="48">1</text>
<text x="321.5" y="50.5">2</text>
<text x="321.5" y="53.1">3</text>
<text x="390.1" y="144.5">1</text>
<text x="390.1" y="147.1">2</text>
<text x="390.1" y="149.6">3</text>
<text x="390.1" y="152.1">4</text>
<text x="390.1" y="154.7">5</text>
<text x="196.4" y="175">1</text>
<text x="216.7" y="177.5">7</text>
<text x="196.4" y="180.1">2</text>
<text x="196.4" y="228.3">5</text>
<text x="196.4" y="233.4">6</text>
<text x="216.7" y="230.9">3</text>
</g>
<g font-size="1.5" fill="#006464">
<text x="44.2" y="42.8">J11</text>
<text x="138.1" y="42.8">J12</text>
<text x="232.1" y="42.8">J13</text>
<text x="326.1" y="42.8">J14</text>
<text x="78.1" y="54.6">C40</text>
<text x="172.1" y="54.6">C42</text>
<text x="266.1" y="54.6">C44</text>
<text x="360.1" y="54.6">C46</text>
<text x="42" y="79.4">R59</text>
<text x="135.9" y="79.4">R61</text>
<text x="229.9" y="79.4">R63</text>
<text x="323.9" y="79.4">R65</text>
<text x="73.1" y="102.9">R60</text>
<text x="101" y="102.9">C39</text>
<text x="167" y="102.9">R62</text>
<text x="195" y="102.9">C41</text>
<text x="261" y="102.9">R64</text>
<text x="289" y="102.9">C43</text>
<text x="355" y="102.9">R66</text>
<text x="382.9" y="102.9">C45</text>
<text x="394.7" y="139.3">J15</text>
<text x="47.7" y="168.9">R67</text>
<text x="206.5" y="168.3">U40A</text>
<text x="260.4" y="170.8">R69</text>
<text x="339.8" y="184.2">R71</text>
<text x="294" y="191.8">R70</text>
<text x="47.7" y="199.4">R68</text>
<text x="103.5" y="199.4">C47</text>
<text x="206.5" y="221.6">U40B</text>
<text x="260.4" y="224.2">R72</text>
<text x="339.8" y="237.5">R74</text>
<text x="294" y="245.1">R73</text>
</g>
<g font-size="1.5" fill="#0000c2">
<text x="15" y="130.9">ML1 harness: + -&gt; 1, GND -&gt; 2, OUT -&gt; 3 (follow sensor silkscreen). Supply 3.3 V.</text>
<text x="15" y="132.8">10k/20k scales 0-3.3 V to 0-2.2 V on ADC1; 10 nF filters noise. Calibrate with sensors mounted.</text>
<text x="15" y="226.8">Battery: 22/122; 12.6 V -&gt; 2.27 V.</text>
<text x="15" y="228.6">Stop before the pack is over-discharged.</text>
</g>
<g font-size="1.4" fill="#0000c2">
<text x="145" y="265.8">Map to named MDD20A terminals.</text>
<text x="145" y="267.5">PWM LOW = dynamic brake; &lt;=20 kHz.</text>
</g>
<g font-size="1.3" fill="#006464">
<text x="72.1" y="41.2">+3V3</text>
<text x="166.1" y="41.2">+3V3</text>
<text x="260.1" y="41.2">+3V3</text>
<text x="354.1" y="41.2">+3V3</text>
<text x="40.8" y="45">B3B-XH-A | FL</text>
<text x="134.8" y="45">B3B-XH-A | FR</text>
<text x="228.7" y="45">B3B-XH-A | RL</text>
<text x="322.7" y="45">B3B-XH-A | RR</text>
<text x="78.7" y="56.8">100n 10V</text>
<text x="172.7" y="56.8">100n 10V</text>
<text x="266.7" y="56.8">100n 10V</text>
<text x="360.7" y="56.8">100n 10V</text>
<text x="72.2" y="73">GND</text>
<text x="166.2" y="73">GND</text>
<text x="260.2" y="73">GND</text>
<text x="354.2" y="73">GND</text>
<text x="41.1" y="81.6">10k 1%</text>
<text x="135.1" y="81.6">10k 1%</text>
<text x="229.1" y="81.6">10k 1%</text>
<text x="323.1" y="81.6">10k 1%</text>
<text x="73.4" y="105">20k 1%</text>
<text x="101.5" y="105">10n 10V</text>
<text x="167.4" y="105">20k 1%</text>
<text x="195.4" y="105">10n 10V</text>
<text x="261.4" y="105">20k 1%</text>
<text x="289.4" y="105">10n 10V</text>
<text x="355.3" y="105">20k 1%</text>
<text x="383.4" y="105">10n 10V</text>
<text x="67.1" y="121.3">GND</text>
<text x="95.1" y="121.3">GND</text>
<text x="161.1" y="121.3">GND</text>
<text x="189.1" y="121.3">GND</text>
<text x="255.1" y="121.3">GND</text>
<text x="283" y="121.3">GND</text>
<text x="349.1" y="121.3">GND</text>
<text x="377" y="121.3">GND</text>
<text x="390.9" y="141.5">MDD20A control</text>
<text x="48.1" y="171.1">100k 1%</text>
<text x="202.1" y="170.5">SN74LVC2G08DCUR</text>
<text x="260.2" y="173">100R</text>
<text x="339.9" y="186.3">100R</text>
<text x="294" y="193.9">10k</text>
<text x="48" y="201.6">22k 1%</text>
<text x="104.1" y="201.6">100n 10V</text>
<text x="288.1" y="210.2">GND</text>
<text x="41.7" y="217.8">GND</text>
<text x="97.6" y="217.8">GND</text>
<text x="202.1" y="223.8">SN74LVC2G08DCUR</text>
<text x="260.2" y="226.3">100R</text>
<text x="339.9" y="239.7">100R</text>
<text x="294" y="247.3">10k</text>
<text x="288.1" y="263.5">GND</text>
</g>
<g font-size="1.3" fill="#840000">
<text x="20.3" y="53.9">LINE_FL_RAW</text>
<text x="26.3" y="48.8">+3V3</text>
<text x="26.5" y="51.4">GND</text>
<text x="114.2" y="53.9">LINE_FR_RAW</text>
<text x="120.3" y="48.8">+3V3</text>
<text x="120.4" y="51.4">GND</text>
<text x="208.1" y="53.9">LINE_RL_RAW</text>
<text x="214.3" y="48.8">+3V3</text>
<text x="214.4" y="51.4">GND</text>
<text x="302" y="53.9">LINE_RR_RAW</text>
<text x="308.2" y="48.8">+3V3</text>
<text x="308.4" y="51.4">GND</text>
<text x="21.6" y="86.9">LINE_FL_RAW</text>
<text x="97.6" y="86.9">LINE_FL_ADC</text>
<text x="115.5" y="86.9">LINE_FR_RAW</text>
<text x="191.6" y="86.9">LINE_FR_ADC</text>
<text x="209.4" y="86.9">LINE_RL_RAW</text>
<text x="285.6" y="86.9">LINE_RL_ADC</text>
<text x="303.3" y="86.9">LINE_RR_RAW</text>
<text x="379.6" y="86.9">LINE_RR_ADC</text>
<text x="375.2" y="147.9">PWM_L</text>
<text x="377" y="145.4">GND</text>
<text x="375.1" y="153">PWM_R</text>
<text x="376" y="155.5">DIR_R</text>
<text x="376.1" y="150.4">DIR_L</text>
<text x="44.3" y="159.3">BAT_FUSED</text>
<text x="175.9" y="175.8">PWM_L_RAW</text>
<text x="274.2" y="178.4">PWM_L</text>
<text x="336.4" y="174.6">DIR_L_RAW</text>
<text x="100.2" y="186">BAT_ADC</text>
<text x="173.6" y="180.9">MOTOR_ENABLE</text>
<text x="336.4" y="197.4">DIR_L</text>
<text x="336.4" y="227.9">DIR_R_RAW</text>
<text x="175.8" y="229.2">PWM_R_RAW</text>
<text x="274.2" y="231.7">PWM_R</text>
<text x="173.6" y="234.3">MOTOR_ENABLE</text>
<text x="336.4" y="250.8">DIR_R</text>
</g>
</g></defs>
<path d="M0 0h420v297h-420z" fill="#f5f4ef"/>
<path d="M0 0h420v297h-420z" fill="none" stroke="#f5f4ef" stroke-width=".18"/>
<g fill="none" stroke="#840000" stroke-width=".18">
<path d="M10 10h400v277h-400zM12 12h396v273h-396zM60 10v2M110 10v2M160 10v2M210 10v2M260 10v2M310 10v2M360 10v2M10 60h2M408 60h2M10 110h2"/>
<path d="M68.6 100.3v1.3M68.6 106.7v1.2M162.6 115.6v1.2h1.2l-1.2 1.3-1.3-1.3h1.3M162.6 115.6h.1M162.6 100.3v1.3M162.6 106.7v1.2M408 110h2M10 160h2M408 160h2M10 210h2M43.2 212.1v1.3h1.2l-1.2 1.2-1.3-1.2h1.3M43.2 212.1h.1"/>
<path d="M408 210h2M10 260h2M289.6 257.8v1.3h1.2l-1.2 1.2-1.3-1.2h1.3M289.6 257.8h.1M300 253h108v32h-108zM408 260h2M300 278.5h108M300 274.5h108M300 268.5h108M308.2 279.3l.5 1.5M309.1 279.3h.9l-.5 .6 .4 .1v.6l-.2 .2h-.4l-.2-.2M320 278.5v3"/>
<path d="M320.8 269.2l.5 1.1 .5-1.1v1.5M322.5 269.8l.2-.1 .5 .1v.6l-.1 .2-.4 .1-.2-.2zM323.7 269.7h.5M323.9 269.2v1.3l.3 .2M324.7 269.8l.2-.1 .5 .1v.6l-.1 .2-.4 .1-.2-.2zM326.1 269.7v1M326.5 269.7l-.3 .1-.1 .2M327.2 272.5h.6l.1 .9M327.9 272.7l-.5 .1a.29 .29 0 0 0-.2 .3 .29 .29 0 0 0 .2 .3l.5-.1M328.1 269.1l-1.3 1.9M329.2 272.5l-.4-.1-.3 .3v.4l.2 .2h.5M329.2 271.9v1.5"/>
<path d="M329.6 273.5h1.1M331.6 272.5l-.4-.1-.2 .2 .1 .2 .5 .2v.3h-.6M332.9 272.5l-.4-.1-.3 .3v.4l.2 .2h.5M333.6 272.5l.2-.1 .4 .1v.9M333.6 271.9v1.5M337.8 279.9l.1-.5 .3-.1a.8 .8 0 0 1 .5 .7 .8 .8 0 0 1-.5 .8l-.3-.2-.1-.4M340.1 279.9l-.3 .3h-.3l-.3-.3 .2-.5 .4-.1 .2 .1a.99 .99 0 0 1-.3 1.4h-.3M342.5 279.7l.4-.4v1.5M344.1 279.4l.2-.1a.8 .8 0 0 1 .5 .7 .8 .8 0 0 1-.5 .8l-.2-.2-.2-.4zM353.5 263.7l.4 1 .3-1M354.8 263.8h.6v.9M355.4 264l-.5 .1a.29 .29 0 0 0-.2 .3 .29 .29 0 0 0 .2 .3l.5-.1"/>
<path d="M356.2 263.2v1.3l.2 .2M356.9 263.2v.1M356.9 263.7v1M358.3 263.8l-.4-.1-.3 .3v.4l.1 .2h.6M358.3 263.2v1.5M359 263.8h.6l.1 .9M359.7 264l-.5 .1a.29 .29 0 0 0-.3 .3 .29 .29 0 0 0 .3 .3l.5-.1M360.2 263.7h.5M360.4 263.2v1.3l.3 .2M361.2 263.2v.1M361.2 263.7v1M361.9 263.8l.3-.1 .4 .1 .1 .6-.2 .2-.3 .1-.3-.2z"/>
<path d="M363.3 263.8l.2-.1 .4 .1v.9M363.3 263.7v1M365.8 263.7v1M366.2 263.7l-.3 .1-.1 .2M366.7 264.2l.7-.2-.1-.2-.4-.1-.2 .2v.7h.6M368.7 263.8l-.5-.1-.3 .3v.4l.2 .2h.6M368.7 263.7v1.5M369.4 263.7v.9l.4 .1 .2-.2M370 263.7v1M370.7 263.2v.1M370.7 263.7v1M371.4 263.7v1"/>
<path d="M371.9 263.7l-.3 .1-.2 .2M372.3 264.2l.7-.2-.1-.2-.4-.1-.2 .2 .1 .7h.5M374.3 263.8l-.4-.1-.3 .3v.4l.1 .2h.6M374.3 263.2v1.5M384 278.5v6.5M60 285v2M110 285v2M160 285v2M210 285v2M260 285v2M300 281.5h108M307.9 280.4h.7"/>
<path d="M310 285v2M317.9 283.4v.2M318.7 282.2l.2-.1a.8 .8 0 0 1 .5 .7 .8 .8 0 0 1-.5 .8l-.2-.2-.2-.4zM320 283.4v.2M321 282l-.3 1.1h.9M321.4 282.6v1M340.7 280.2h1.2M342.5 280.8h.9M360 285v2M393.3 283.6h.9M393.3 282.5l.4-.4v1.5M394.9 282.2l.2-.1a.8 .8 0 0 1 .5 .7 .8 .8 0 0 1-.5 .8l-.2-.2-.2-.4z"/>
</g>
<path d="M321.5 266.7l.4 1 .4-1M322.8 266.2v.1M322.8 266.7v1M325 266v2.2M327.1 266.2h.9l-.5 .6 .5 .1v.6l-.2 .2h-.5l-.2-.2M329.8 266.2v1.5M330 267.1l.4 .6M330.4 266.7l-.6 .6M331.7 266.8l-.4-.1-.3 .3v.4l.1 .2h.6M331.7 266.7v1.2l-.3 .3-.4-.1M394.5 279.4l.3-.1a.8 .8 0 0 1 .5 .7 .8 .8 0 0 1-.5 .8l-.3-.2-.1-.4zM393.8 280.6v.2" fill="none" stroke="#840000" stroke-width=".3"/>
<g fill="none" stroke="#840000" stroke-width=".4">
<path d="M346.7 275.9l.5 .1 .1 .2M347.3 276.2a.5 .5 0 0 1 .8-.2l-.1 1.2M347.3 276.2l-.2 1M349.1 276.1a.52 .52 0 0 1 .5-.2 .52 .52 0 0 1 .4 .4v.5a.55 .55 0 0 1-.6 .4 .55 .55 0 0 1-.5-.4zM350.6 275.9h.8M351 275.2l-.2 1.7 .1 .2 .3 .1M352 276.1a.52 .52 0 0 1 .6-.2 .52 .52 0 0 1 .4 .4l-.1 .5a.55 .55 0 0 1-.5 .4 .55 .55 0 0 1-.5-.4zM353.9 275.9l-.2 1.3M354.5 275.9l-.4 .1-.3 .3M357.5 276a.66 .66 0 0 0-1 .3l-.1 .5 .2 .3 .2 .1 .5-.1M357.5 275.9l-.2 1.6a.6 .6 0 0 1-.9 .3M358.4 276l.2-.1 .6 .1-.1 1.2"/>
<path d="M359.3 276.3l-.7 .1a.4 .4 0 0 0-.4 .4 .4 .4 0 0 0 .3 .4l.7-.1M360 275.9h.7M360.3 275.2l-.2 1.7 .1 .2 .4 .1M361.4 275.9l-.2 1.3M361.5 275.2v.2M361.5 275.2l-.1 .1 .1 .1M361.5 275.2l.1 .1-.1 .1M362.3 276.1a.49 .49 0 0 1 .9 .1l-.2 1M362.4 275.9l-.2 1.3M365 276a.66 .66 0 0 0-1 .3v.5l.1 .3 .2 .1 .6-.1M365 275.9l-.2 1.6a.6 .6 0 0 1-.9 .3"/>
</g>
<path d="M67.6 101.6h2v5.1h-2zM161.5 101.6h2.1v5.1h-2.1z" fill="none" stroke="#840000" stroke-width=".25"/>
<path d="M73 104l-.1 .1M73.4 104.4l-.6 .6h.6M77.8 104.8l.2 .1h-.2M78 104l-.7 1M167 104l-.2 .1M167.4 104.4l-.6 .6h.6M171.8 104.8l.2 .1h-.2M172 104l-.7 1" fill="none" stroke="#006464" stroke-width=".18"/>
<path d="M41.9 47h2.5v7.6h-2.5z" fill="#ffffc2"/>
<path d="M41.9 47h2.5v7.6h-2.5zM322.6 85.3h5.1v2.1h-5.1zM255.5 101.6h2.1v5.1h-2.1z" fill="none" stroke="#840000" stroke-width=".25"/>
<g fill="none" stroke="#840000" stroke-width=".18">
<path d="M38.1 48.3h3.8M38.1 50.8h3.8M38.1 53.3h3.8M41.9 48.1h1.3v.3h-1.3zM41.9 50.7h1.3v.2h-1.3zM41.9 53.2h1.3v.3h-1.3zM73.7 44.4h.1M73.7 41.9l-.8 1.3M73.7 41.9l.7 1.3M73.7 41.9v2.5M321.3 86.4h1.3M327.7 86.4h1.2"/>
<path d="M190.5 100.3v2.8M190.5 105.2v2.7M256.5 115.6v1.2h1.3l-1.3 1.3-1.2-1.3h1.2M256.5 115.6h.1M256.5 100.3v1.3M256.5 106.7v1.2M284.5 115.6v1.2h1.2l-1.2 1.3-1.3-1.3h1.3M284.5 115.6h.1M284.5 100.3v2.8M284.5 105.2v2.7"/>
</g>
<g fill="none" stroke="#006464" stroke-width=".18">
<path d="M39.2 43.9h.3l.2 .2-.2 .3 .2 .1 .1 .2-.2 .2h-.4zM39.2 44.4h.3M40.1 44.8l.4 .1M40.1 43.9h.6M50 43.9h.4M50 44.4h.3M50.8 43.9v1h.5M322.5 81.5h.6M322.8 80.5l-.3 .3M327.5 81.3l.2 .1-.2 .1M327.7 80.5l-.7 1M194.8 105h.5"/>
<path d="M194.8 104.3l.3-.3v1M200.8 104l-.3 1M261 104l-.2 .1M261.3 104.4l-.5 .6h.6M265.8 104.8l.2 .1h-.2M266 104l-.8 1M288.8 105h.5M288.8 104.3l.2-.3v1M294.8 104l-.3 1"/>
</g>
<path d="M188.5 103.4h4M188.5 104.9h4M282.4 103.4h4.1M282.4 104.9h4.1" fill="none" stroke="#840000" stroke-width=".51"/>
<path d="M229.9 47h2.5v7.6h-2.5z" fill="#ffffc2"/>
<path d="M229.9 47h2.5v7.6h-2.5z" fill="none" stroke="#840000" stroke-width=".25"/>
<path d="M226.1 48.3h3.8M226.1 50.8h3.8M226.1 53.3h3.8M229.9 48.1h1.2v.3h-1.2zM229.9 50.7h1.2v.2h-1.2zM229.9 53.2h1.2v.3h-1.2z" fill="none" stroke="#840000" stroke-width=".18"/>
<path d="M227.1 43.9h.3l.2 .2-.2 .3 .2 .1 .1 .2-.2 .2h-.4zM227.1 44.4h.3M228 44.8l.4 .1M228 43.9h.6M237.9 43.9h.3l.2 .2-.1 .3h-.4M238.1 44.4l.3 .5M238.9 43.9v1h.4" fill="none" stroke="#006464" stroke-width=".18"/>
<g fill="#ffffc2">
<path d="M208.3 226.1l.9 .1 1 .2 .8 .5 .9 .6 .6 .8 .5 .9 .2 .9 .2 1-.1 1-.3 .9-.5 .9-.6 .8-.8 .7-.8 .4-1 .3-1 .1z"/>
<path d="M200.7 226.1h7.6v10.1h-7.6z"/>
</g>
<path d="M40.6 85.3h5.1v2.1h-5.1zM228.6 85.3h5.1v2.1h-5.1zM200.7 226.1h8l1.2 .2 1.2 .6 .8 .6 .6 .8 .5 .9 .3 1 .1 .9-.1 1-.3 .9-.5 1-.7 .8-.8 .6-.8 .5-1 .2-8.5 .1zM259.1 230.1h5.1v2.1h-5.1z" fill="none" stroke="#840000" stroke-width=".25"/>
<path d="M261.6 52.1v2.8M261.6 56.9v2.8M39.4 86.4h1.2M45.7 86.4h1.3M227.3 86.4h1.3M233.7 86.4h1.2M193 228.6h7.7M193 233.7h7.7M213.4 231.1h7.6M257.8 231.1h1.3M264.2 231.1h1.2" fill="none" stroke="#840000" stroke-width=".18"/>
<g fill="none" stroke="#006464" stroke-width=".18">
<path d="M265.9 56.7h.6M265.9 56l.3-.3v1M272.2 55.7l.4 1 .3-1M40.6 81.5h.6M40.9 80.5l-.3 .3M45.5 81.3l.3 .1-.3 .1M45.8 80.5l-.8 1M228.5 81.5h.6M228.8 80.5l-.3 .3M233.5 81.3l.2 .1-.2 .1M233.7 80.5l-.7 1M201.2 223.7h.5"/>
<path d="M201.8 222.8h-.4l-.2 .1 .1 .3 .4 .1M214.8 222.8h.3l.2 .1-.1 .3-.4 .1M215 223.3l.3 .5"/>
</g>
<path d="M259.6 55.1h4.1M259.6 56.6h4.1" fill="none" stroke="#840000" stroke-width=".51"/>
<g fill="#ffffc2">
<path d="M208.3 172.7l.9 .1 1 .3 .8 .4 .9 .7 .6 .8 .5 .8 .2 .9 .2 1.1-.1 1-.3 .9-.5 .9-.6 .8-.8 .6-.8 .5-1 .3-1 .1z"/>
<path d="M200.7 172.7h7.6v10.2h-7.6z"/>
</g>
<path d="M200.7 172.7h8l1.2 .3 1.2 .6 .8 .6 .6 .8 .5 .8 .3 1 .1 1-.1 1-.3 .9-.5 .9-.7 .9-.8 .6-.8 .4-1 .3-8.5 .1zM288.5 190.5h2.1v5.1h-2.1z" fill="none" stroke="#840000" stroke-width=".25"/>
<g fill="none" stroke="#840000" stroke-width=".18">
<path d="M261.6 44.4h.1M261.6 41.9l-.7 1.3M261.6 41.9l.8 1.3M261.6 41.9v2.5M355.6 44.4h.1M355.6 41.9l-.8 1.3M355.6 41.9l.8 1.3M355.6 41.9v2.5M261.6 67.3v1.3h1.3l-1.3 1.2-1.3-1.2h1.3M261.6 67.3h.1M96.5 100.3v2.8M96.5 105.2v2.7"/>
<path d="M193 175.3h7.7M213.4 177.8h7.6M193 180.3h7.7M289.6 189.2v1.3M289.6 195.6v1.2M289.6 204.5v1.2h1.2l-1.2 1.3-1.3-1.3h1.3M289.6 204.5h.1"/>
</g>
<path d="M100.8 105h.6M100.8 104.3l.3-.3v1M106.8 104l-.3 1M201.2 170.4h.5M201.8 169.5l-.4-.1-.2 .2 .1 .2 .4 .2M214.8 169.4h.3l.2 .2-.1 .3h-.4M215 169.9l.3 .5" fill="none" stroke="#006464" stroke-width=".18"/>
<path d="M94.5 103.4h4.1M94.5 104.9h4.1" fill="none" stroke="#840000" stroke-width=".51"/>
<path d="M323.8 47h2.6v7.6h-2.6z" fill="#ffffc2"/>
<path d="M323.8 47h2.6v7.6h-2.6zM134.6 85.3h5.1v2.1h-5.1zM334.3 236.2h2v5.1h-2z" fill="none" stroke="#840000" stroke-width=".25"/>
<g fill="none" stroke="#840000" stroke-width=".18">
<path d="M320 48.3h3.8M320 50.8h3.8M320 53.3h3.8M323.8 48.1h1.3v.3h-1.3zM323.8 50.7h1.3v.2h-1.3zM323.8 53.2h1.3v.3h-1.3zM355.6 52.1v2.8M355.6 56.9v2.8M355.6 67.3v1.3h1.3l-1.3 1.2-1.3-1.2h1.3M355.6 67.3h.1M133.3 86.4h1.3M139.7 86.4h1.3"/>
<path d="M190.5 115.6v1.2h1.3l-1.3 1.3-1.3-1.3h1.3M190.5 115.6h.1M350.5 115.6v1.2h1.3l-1.3 1.3-1.3-1.3h1.3M350.5 115.6h.1M335.3 234.9v1.3M335.3 241.3v1.3"/>
</g>
<g fill="none" stroke="#006464" stroke-width=".18">
<path d="M321 43.9h.3l.2 .2-.2 .3 .2 .1v.2l-.1 .2h-.4zM321 44.4h.3M321.9 44.8l.4 .1M321.9 43.9h.6l-.3 .4h.1M331.7 43.9h.4l.2 .2-.1 .3h-.5M332 44.4l.3 .5M332.7 44.4h.5l.1-.4-.6-.1v1M333 44.4l.3 .5M359.9 56.7h.5M359.9 56l.3-.3v1M366.2 55.7l.3 1 .4-1M134.6 81.5h.5"/>
<path d="M134.9 80.5l-.3 .3M139.5 81.3l.3 .1-.3 .1M139.8 80.5l-.8 1"/>
</g>
<path d="M353.6 55.1h4M353.6 56.6h4" fill="none" stroke="#840000" stroke-width=".51"/>
<path d="M135.9 47h2.5v7.6h-2.5z" fill="#ffffc2"/>
<path d="M135.9 47h2.5v7.6h-2.5zM349.5 101.6h2v5.1h-2z" fill="none" stroke="#840000" stroke-width=".25"/>
<g fill="none" stroke="#840000" stroke-width=".18">
<path d="M73.7 52.1v2.8M73.7 56.9v2.8M132.1 48.3h3.8M132.1 50.8h3.8M132.1 53.3h3.8M135.9 48.1h1.3v.3h-1.3zM135.9 50.7h1.3v.2h-1.3zM135.9 53.2h1.3v.3h-1.3zM167.6 44.4h.1M167.6 41.9l-.7 1.3M167.6 41.9l.8 1.3M167.6 41.9v2.5"/>
<path d="M73.7 67.3v1.3h1.2l-1.2 1.2-1.3-1.2h1.3M73.7 67.3h.1M167.6 67.3v1.3h1.3l-1.3 1.2-1.2-1.2h1.2M167.6 67.3h.1M350.5 100.3v1.3M350.5 106.7v1.2M378.5 115.6v1.2h1.2l-1.2 1.3-1.3-1.3h1.3M378.5 115.6h.1"/>
</g>
<g fill="none" stroke="#006464" stroke-width=".18">
<path d="M77.9 56.7h.6M77.9 56l.3-.3v1M84.3 55.7l.3 1 .3-1M133.1 43.9h.3l.2 .2-.2 .3 .2 .1 .1 .2-.2 .2h-.4zM133.1 44.4h.3M134 44.8l.4 .1M134 43.9h.6l-.3 .4h.1M143.9 43.9h.4M143.9 44.4h.3M144.7 44.4h.5v-.4l-.5-.1v1M144.9 44.4l.4 .5M354.9 104l-.1 .1"/>
<path d="M355.3 104.4l-.5 .6h.6M359.8 104.8l.2 .1h-.2M360 104l-.8 1"/>
</g>
<path d="M71.6 55.1h4.1M71.6 56.6h4.1" fill="none" stroke="#840000" stroke-width=".51"/>
<path d="M392.4 143.5h2.6v12.7h-2.6z" fill="#ffffc2"/>
<path d="M392.4 143.5h2.6v12.7h-2.6zM42.2 167.6h2v5.1h-2zM259.1 176.8h5.1v2h-5.1zM42.2 198.1h2v5.1h-2zM334.3 182.9h2v5.1h-2zM288.5 243.8h2.1v5.1h-2.1z" fill="none" stroke="#840000" stroke-width=".25"/>
<g fill="none" stroke="#840000" stroke-width=".18">
<path d="M19.1 52.3h10.5l.9 1-.9 1h-10.5l-.8-1zM24.6 47.3h5l.9 1-.9 1h-5l-.9-1zM25.5 48.4h.8M25.5 49.8h4.1l.9 1-.9 1h-4.1l-.9-1zM25.9 48v.8M112.9 52.3h10.7l.9 1-.9 1h-10.7l-.9-1zM118.5 47.3h5.1l.9 1-.9 1h-5.1l-.8-1zM119.5 48.4h.7M119.5 49.8h4.1l.9 1-.9 1h-4.1l-.9-1zM119.9 48v.8M167.6 52.1v2.8M167.6 56.9v2.8"/>
<path d="M206.9 52.3h10.7l.8 1-.8 1h-10.7l-.8-1zM212.5 47.3h5.1l.8 1-.8 1h-5.1l-.9-1zM213.5 48.4h.7M213.5 49.8h4.1l.8 1-.8 1h-4.1l-.9-1zM213.8 48v.8M300.7 52.3h10.8l.9 1-.9 1h-10.8l-.8-1zM306.5 47.3h5l.9 1-.9 1h-5l-.9-1zM307.4 48.4h.8M307.4 49.8h4.1l.9 1-.9 1h-4.1l-.8-1zM307.8 48v.8M20.4 85.4h10.5l.8 1-.8 1h-10.5l-.9-1zM97.4 85.4h10.3l.9 1-.9 1h-10.3l-.9-1z"/>
<path d="M106.8 85.9v.1M106.8 86.8h.1M114.2 85.4h10.7l.8 1-.8 1h-10.7l-.9-1zM191.4 85.4h10.5l.9 1-.9 1h-10.5l-.9-1zM200.8 85.9l.2 .1M201 86.8l-.2 .1M208.2 85.4h10.6l.9 1-.9 1h-10.6l-.9-1zM285.4 85.4h10.4l.9 1-.9 1h-10.4l-.9-1zM294.9 85.9v.1M294.9 86.8h.1M302 85.4h10.8l.9 1-.9 1h-10.8l-.9-1zM379.3 85.4h10.7l.9 1-.9 1h-10.7l-.8-1z"/>
<path d="M388.9 85.9l.2 .1M389.1 86.8l-.2 .1M68.6 115.6v1.2h1.2l-1.2 1.3-1.3-1.3h1.3M68.6 115.6h.1M96.5 115.6v1.2h1.3l-1.3 1.3-1.3-1.3h1.3M96.5 115.6h.1M378.5 100.3v2.8M378.5 105.2v2.7M44.1 157.7h9.1l.9 1-.9 1.1h-9.1l-.9-1.1zM52.3 158.4l.1 .3-.1 .4M374 151.4h6.1l.9 1-.9 1h-6.1l-.8-1zM374.2 146.3h5.9l.9 1-.9 1h-5.9l-.9-1z"/>
<path d="M374.8 153.9h5.3l.9 1-.9 1h-5.3l-.8-1zM375 148.9h5.1l.9 1-.9 1h-5.1l-.8-1zM376 143.8h4.1l.9 1-.9 1h-4.1l-.8-1zM388.6 144.8h3.8M388.6 147.3h3.8M388.6 149.9h3.8M388.6 152.4h3.8M388.6 154.9h3.8M392.4 144.7h1.3v.2h-1.3zM392.4 147.2h1.3v.2h-1.3zM392.4 149.7h1.3v.3h-1.3zM392.4 152.3h1.3v.2h-1.3z"/>
<path d="M392.4 154.8h1.3v.3h-1.3zM43.2 166.4v1.2M43.2 172.7v1.3M172.2 179.3h12.3l.9 1-.9 1h-12.3l-.9-1zM174.9 174.3h9.6l.9 1-.9 1h-9.6l-.9-1zM257.8 177.8h1.3M264.2 177.8h1.2M273.9 176.8h5.9l.9 1-.9 1h-5.9l-.9-1zM336.2 173h8.8l.9 1-.9 1h-8.8l-.9-1zM43.2 196.8v1.3M99.1 196.8v2.8M99.9 184.4h7.3l.9 1-.9 1h-7.3l-.8-1z"/>
<path d="M335.3 181.6v1.3M335.3 188v1.2M336.2 195.8h5.1l.8 1-.8 1.1h-5.1l-.9-1.1zM43.2 203.2v1.3M99.1 212.1v1.3h1.2l-1.2 1.2-1.3-1.2h1.3M99.1 212.1h.1M99.1 201.7v2.8M172.2 232.7h12.3l.9 1-.9 1h-12.3l-.9-1zM174.7 227.6h9.8l.9 1-.9 1h-9.8l-.9-1zM273.9 230.1h6.1l.9 1-.9 1h-6.1l-.9-1zM336.2 226.3h9l.9 1-.9 1h-9l-.9-1zM289.6 242.6v1.2"/>
<path d="M289.6 248.9v1.3M336.2 249.2h5.2l.9 1-.9 1h-5.2l-.9-1z"/>
</g>
<g fill="none" stroke="#006464" stroke-width=".18">
<path d="M171.9 56.7h.6M171.9 56l.3-.3v1M178.3 55.7l.3 1 .3-1M382.7 105h.6M382.7 104.3l.3-.3v1M388.8 104l-.3 1M390.6 140.4l-.3 .7-.3-.7v1M400.9 140.8l.1 .2-.1 .4M401.4 140.4v.9l.1 .1M47.5 171h.5M47.5 170.3l.2-.3v1M53.6 170l-.8 1"/>
<path d="M47.6 200.5l-.1 .1M48 200.9l-.6 .6h.6M52.4 201.3l.2 .1-.2 .1M52.6 200.5l-.7 1M103.3 201.5h.6M103.3 200.8l.3-.3v1M109.7 200.5l.3 1 .3-1"/>
<circle cx="53.5" cy="170.9" r=".14"/>
</g>
<path d="M165.6 55.1h4.1M165.6 56.6h4.1M376.4 103.4h4.1M376.4 104.9h4.1M97 199.9h4.1M97 201.4h4.1" fill="none" stroke="#840000" stroke-width=".51"/>
<g fill="none" stroke="#009600" stroke-width=".18">
<path d="M30.5 53.3h7.6M30.5 50.8h7.6M30.5 48.3h7.6M73.7 44.4v7.7M73.7 59.7v7.6M124.5 53.3h7.6M124.5 50.8h7.6M124.5 48.3h7.6M167.6 44.4v7.7M167.6 59.7v7.6M218.4 53.3h7.7M218.4 50.8h7.7"/>
<path d="M218.4 48.3h7.7M261.6 44.4v7.7M261.6 59.7v7.6M312.4 53.3h7.6M312.4 50.8h7.6M312.4 48.3h7.6M355.6 44.4v7.7M355.6 59.7v7.6M31.7 86.4h7.7M47 86.4h49.5v13.9M68.6 86.4v13.9M125.7 86.4h7.6"/>
<path d="M141 86.4h49.5v13.9M162.6 86.4v13.9M219.7 86.4h7.6M234.9 86.4h49.6v13.9M256.5 86.4v13.9M313.7 86.4h7.6M328.9 86.4h49.6v13.9M350.5 86.4v13.9M68.6 107.9v7.7M96.5 107.9v7.7M162.6 107.9v7.7M190.5 107.9v7.7"/>
<path d="M256.5 107.9v7.7M284.5 107.9v7.7M350.5 107.9v7.7M378.5 107.9v7.7M43.2 158.7v7.7M381 144.8h7.6M381 147.3h7.6M381 149.9h7.6M381 152.4h7.6M381 154.9h7.6M43.2 174v22.8M185.4 175.3h7.6"/>
<path d="M221 177.8h36.8M265.4 177.8h24.2v11.4M335.3 174v7.6M43.2 185.4h55.9v11.4M185.4 180.3h7.6M289.6 196.8v7.7M335.3 189.2v7.6M43.2 204.5v7.6M99.1 204.5v7.6M185.4 228.6h7.6M185.4 233.7h7.6M221 231.1h36.8"/>
<path d="M265.4 231.1h24.2v11.5M335.3 227.3v7.6M289.6 250.2v7.6M335.3 242.6v7.6"/>
</g>
<g fill="none" stroke="#0000c2" stroke-width=".18">
<path d="M73.1 13.8l.7-2 .6 2M73.3 13.3h.9M75.1 11.8l.9 .1a.48 .48 0 0 1 .1 .5 .48 .48 0 0 1-.3 .4 .53 .53 0 0 1 .5 .5 .53 .53 0 0 1-.4 .5h-.8zM75.1 12.8h.7M77.1 11.8v2h1M78.7 12.8h.7M79.7 11.8h-1v2h1M67.3 130.4l.3-.2 .3 .2-.1 .5h-.2l-.3-.2M68.4 130.2v.7M68.8 130.2l-.4 .2M70.4 130.2h-.3l-.1 .1v.2l.4 .1v.3h-.4M71 129.8v.1"/>
<path d="M71 130.2v.7M71.5 129.8v1l.2 .1M72.1 129.8v1.1M72.2 130.5l.3 .4M72.5 130.2l-.4 .4M73.4 130.2h-.3l-.1 .1v.2l.4 .1v.3h-.4M74.5 130.2h-.4l-.2 .2 .1 .5h.5M75 130.2v.7M75.3 130.2l-.3 .2M75.6 130.6l.6-.1-.1-.3h-.3l-.2 .1 .1 .6h.4M75.9 131.8a.51 .51 0 0 0-.7 .4 .51 .51 0 0 0 .7 .5M76.4 132.1h.5v.7"/>
<path d="M76.6 130.6l.5-.1v-.3h-.3l-.2 .1 .1 .6h.4M76.9 132.3l-.4 .1-.1 .1 .1 .3 .4-.1M77.5 131.6v1l.1 .2M77.6 130.3l.5-.1v.7M77.6 130.2v.7M78.1 131.6v.2M78.1 132v.8M78.6 129.6a1.32 1.32 0 0 1 0 1.8M78.6 132.1l.4-.1 .2 .3-.1 .4h-.5M78.6 131.6v1.2M79.4 130.8v.1M79.7 132v.8"/>
<path d="M80 132l-.3 .3M80.4 132.1h.4l.1 .7M80.9 132.3l-.4 .1-.2 .1 .2 .3 .4-.1M81.3 132h.4M81.4 131.6v1l.3 .2M81.5 129.9l-.5-.1-.2 .2 .1 .3 .5 .2v.3l-.1 .1h-.5M82 130.2v.7l.5-.1M82 132.4l.6-.1-.1-.2-.3-.1-.2 .2 .1 .5h.4M82.5 130.2v.7M83 130.2h.3l.3 .2-.2 .5h-.4M83 130.2v1.1M83.8 132l.2 .8 .3-.5 .2 .5 .2-.8"/>
<path d="M84 130.2h.4l.2 .2-.1 .5h-.5M84 130.2v1.1M85.1 129.8v1l.2 .1M85.1 131.6v.2M85.1 132v.8M85.5 132h.5M85.6 130.2l.3 .7M85.7 131.6v1l.3 .2M85.9 130.9l-.3 .4M86.1 130.2l-.2 .7M86.3 132.1h.5v.7M86.3 131.6v1.2"/>
<path d="M87.3 129.8h.7l-.3 .4 .3 .1v.5l-.2 .1-.5-.1M88.5 130.8v.1M88.6 132.1l-.2-.1-.2 .2 .1 .2 .3 .1v.2h-.4M89 129.8h.7l-.4 .4 .3 .1v.5l-.1 .1-.5-.1M89.1 132.4l.6-.1-.1-.2-.3-.1-.2 .2 .1 .5h.4M90.2 132.1h.4l.1 .7M90.2 132v.8M90.9 129.8l.4 1.1 .4-1.1M91.6 132.1l-.3-.1-.1 .2v.2l.4 .1v.2h-.4M92 130.8v.1M92.2 132.1l.3-.1 .2 .3v.3l-.2 .2-.4-.2zM93.2 132v.8"/>
<path d="M93.5 132l-.3 .3M94.3 132.1l-.3-.1-.2 .2 .1 .2 .4 .1v.2h-.5M95.7 132.1l.3-.1 .2 .2M95.7 132v.8M96.2 132.2l.2-.2 .2 .1 .1 .7M96.2 132.2v.6M97.3 132.1l.3-.1 .2 .3v.3l-.2 .2-.4-.2zM98.3 132v.7h.5M98.8 132v.8M99.3 132.1h.5v.7M99.3 132v.8M100.2 132h.4"/>
<path d="M100.4 131.6v1l.2 .2M101 132.4l.5-.1v-.2l-.4-.1-.1 .2v.5h.5M102.5 132.1l-.3-.1-.2 .3 .1 .4h.4M102.5 131.6v1.2M103 132.7v.1M36.6 226.5h.8M37.9 226.2l.9 .3-.9 .3M39.3 227.9l-.3 .2M39.7 228.2h.8M40.1 225.9l.4-.1 .2 .3-.7 .8h.7M41.2 226.8v.1M41.5 228l-.3-.1-.2 .2 .1 .5h.4"/>
<path d="M41.5 227.6v1.1M41.7 225.9l.4-.1 .2 .3-.7 .8h.7M42 227.6v.1M42 227.9v.8M42.7 225.8h.7l-.5 1.1M42.9 228l-.2-.1-.2 .2v.1l.4 .2v.2h-.4M43.9 228l-.3-.1-.2 .2 .1 .5h.4M44.4 228h.4l.1 .7M44.4 227.6v1.1M44.5 225.8l.4 1.1 .3-1.1M45.4 228h.4v.7M45.6 226.8v.1"/>
<path d="M45.8 228.2l-.5 .2 .2 .3 .3-.1M46.4 227.9v.8M46.7 227.9l-.3 .2M47.5 228l-.3-.1-.2 .2 .1 .5h.4M47.5 227.9v.9l-.2 .2h-.2M48 228.3l.5-.1v-.2l-.3-.1-.2 .2v.5h.5M49.5 228l-.4-.1-.2 .2 .1 .5h.5M49.5 227.6v1.1M50 228.6v.1M165.3 265.1l.3 .1v.2l-.5 .1M165.6 265.8h-.3M166.1 265.1v.7"/>
<path d="M166.4 265.1l-.3 .2M166.7 265.2l.3-.1 .2 .2M166.7 265.1v.7M167.2 265.3l.1-.2 .3 .1v.6M167.2 265.3v.5M168.1 264.8v.1M168.1 265.1v.7M168.6 265.2h.4l.1 .6M168.6 265.1v.7M169.3 266.8l-.8 .3 .8 .3M169.6 265.2h.4v.6M169.8 267h.8"/>
<path d="M169.8 267.3h.8M170 265.4l-.5 .2 .2 .2h.3M170.5 264.8v.9l.2 .1M171.1 266.6l.4-.1 .2 .3-.7 .7h.7M171.4 265.2l-.2-.1-.2 .2 .1 .1 .3 .1v.3h-.4M171.9 265.7v.1M172.2 266.6l.1-.1a.56 .56 0 0 1 .4 .5 .56 .56 0 0 1-.4 .5l-.2-.4zM173.9 266.5v1M174 267.1l.3 .4M174.3 266.8l-.4 .4M174.8 267h.6M174.8 266.5v1"/>
<path d="M175.4 266.5v1M175.8 266.8h.5l-.5 .7h.5M176.7 267.4v.1"/>
</g>
<circle cx="68.6" cy="86.4" r=".46" fill="#009600"/>
<circle cx="68.6" cy="86.4" r=".46" fill="none" stroke="#009600" stroke-width=".18"/>
<circle cx="265.4" cy="231.1" r=".46" fill="#009600"/>
<circle cx="265.4" cy="231.1" r=".46" fill="none" stroke="#009600" stroke-width=".18"/>
<circle cx="265.4" cy="177.8" r=".46" fill="#009600"/>
<circle cx="265.4" cy="177.8" r=".46" fill="none" stroke="#009600" stroke-width=".18"/>
<circle cx="43.2" cy="185.4" r=".46" fill="#009600"/>
<circle cx="43.2" cy="185.4" r=".46" fill="none" stroke="#009600" stroke-width=".18"/>
<circle cx="162.6" cy="86.4" r=".46" fill="#009600"/>
<circle cx="162.6" cy="86.4" r=".46" fill="none" stroke="#009600" stroke-width=".18"/>
<circle cx="256.5" cy="86.4" r=".46" fill="#009600"/>
<circle cx="256.5" cy="86.4" r=".46" fill="none" stroke="#009600" stroke-width=".18"/>
<circle cx="350.5" cy="86.4" r=".46" fill="#009600"/>
<circle cx="350.5" cy="86.4" r=".46" fill="none" stroke="#009600" stroke-width=".18"/>
<use href="#words"/>
</svg>
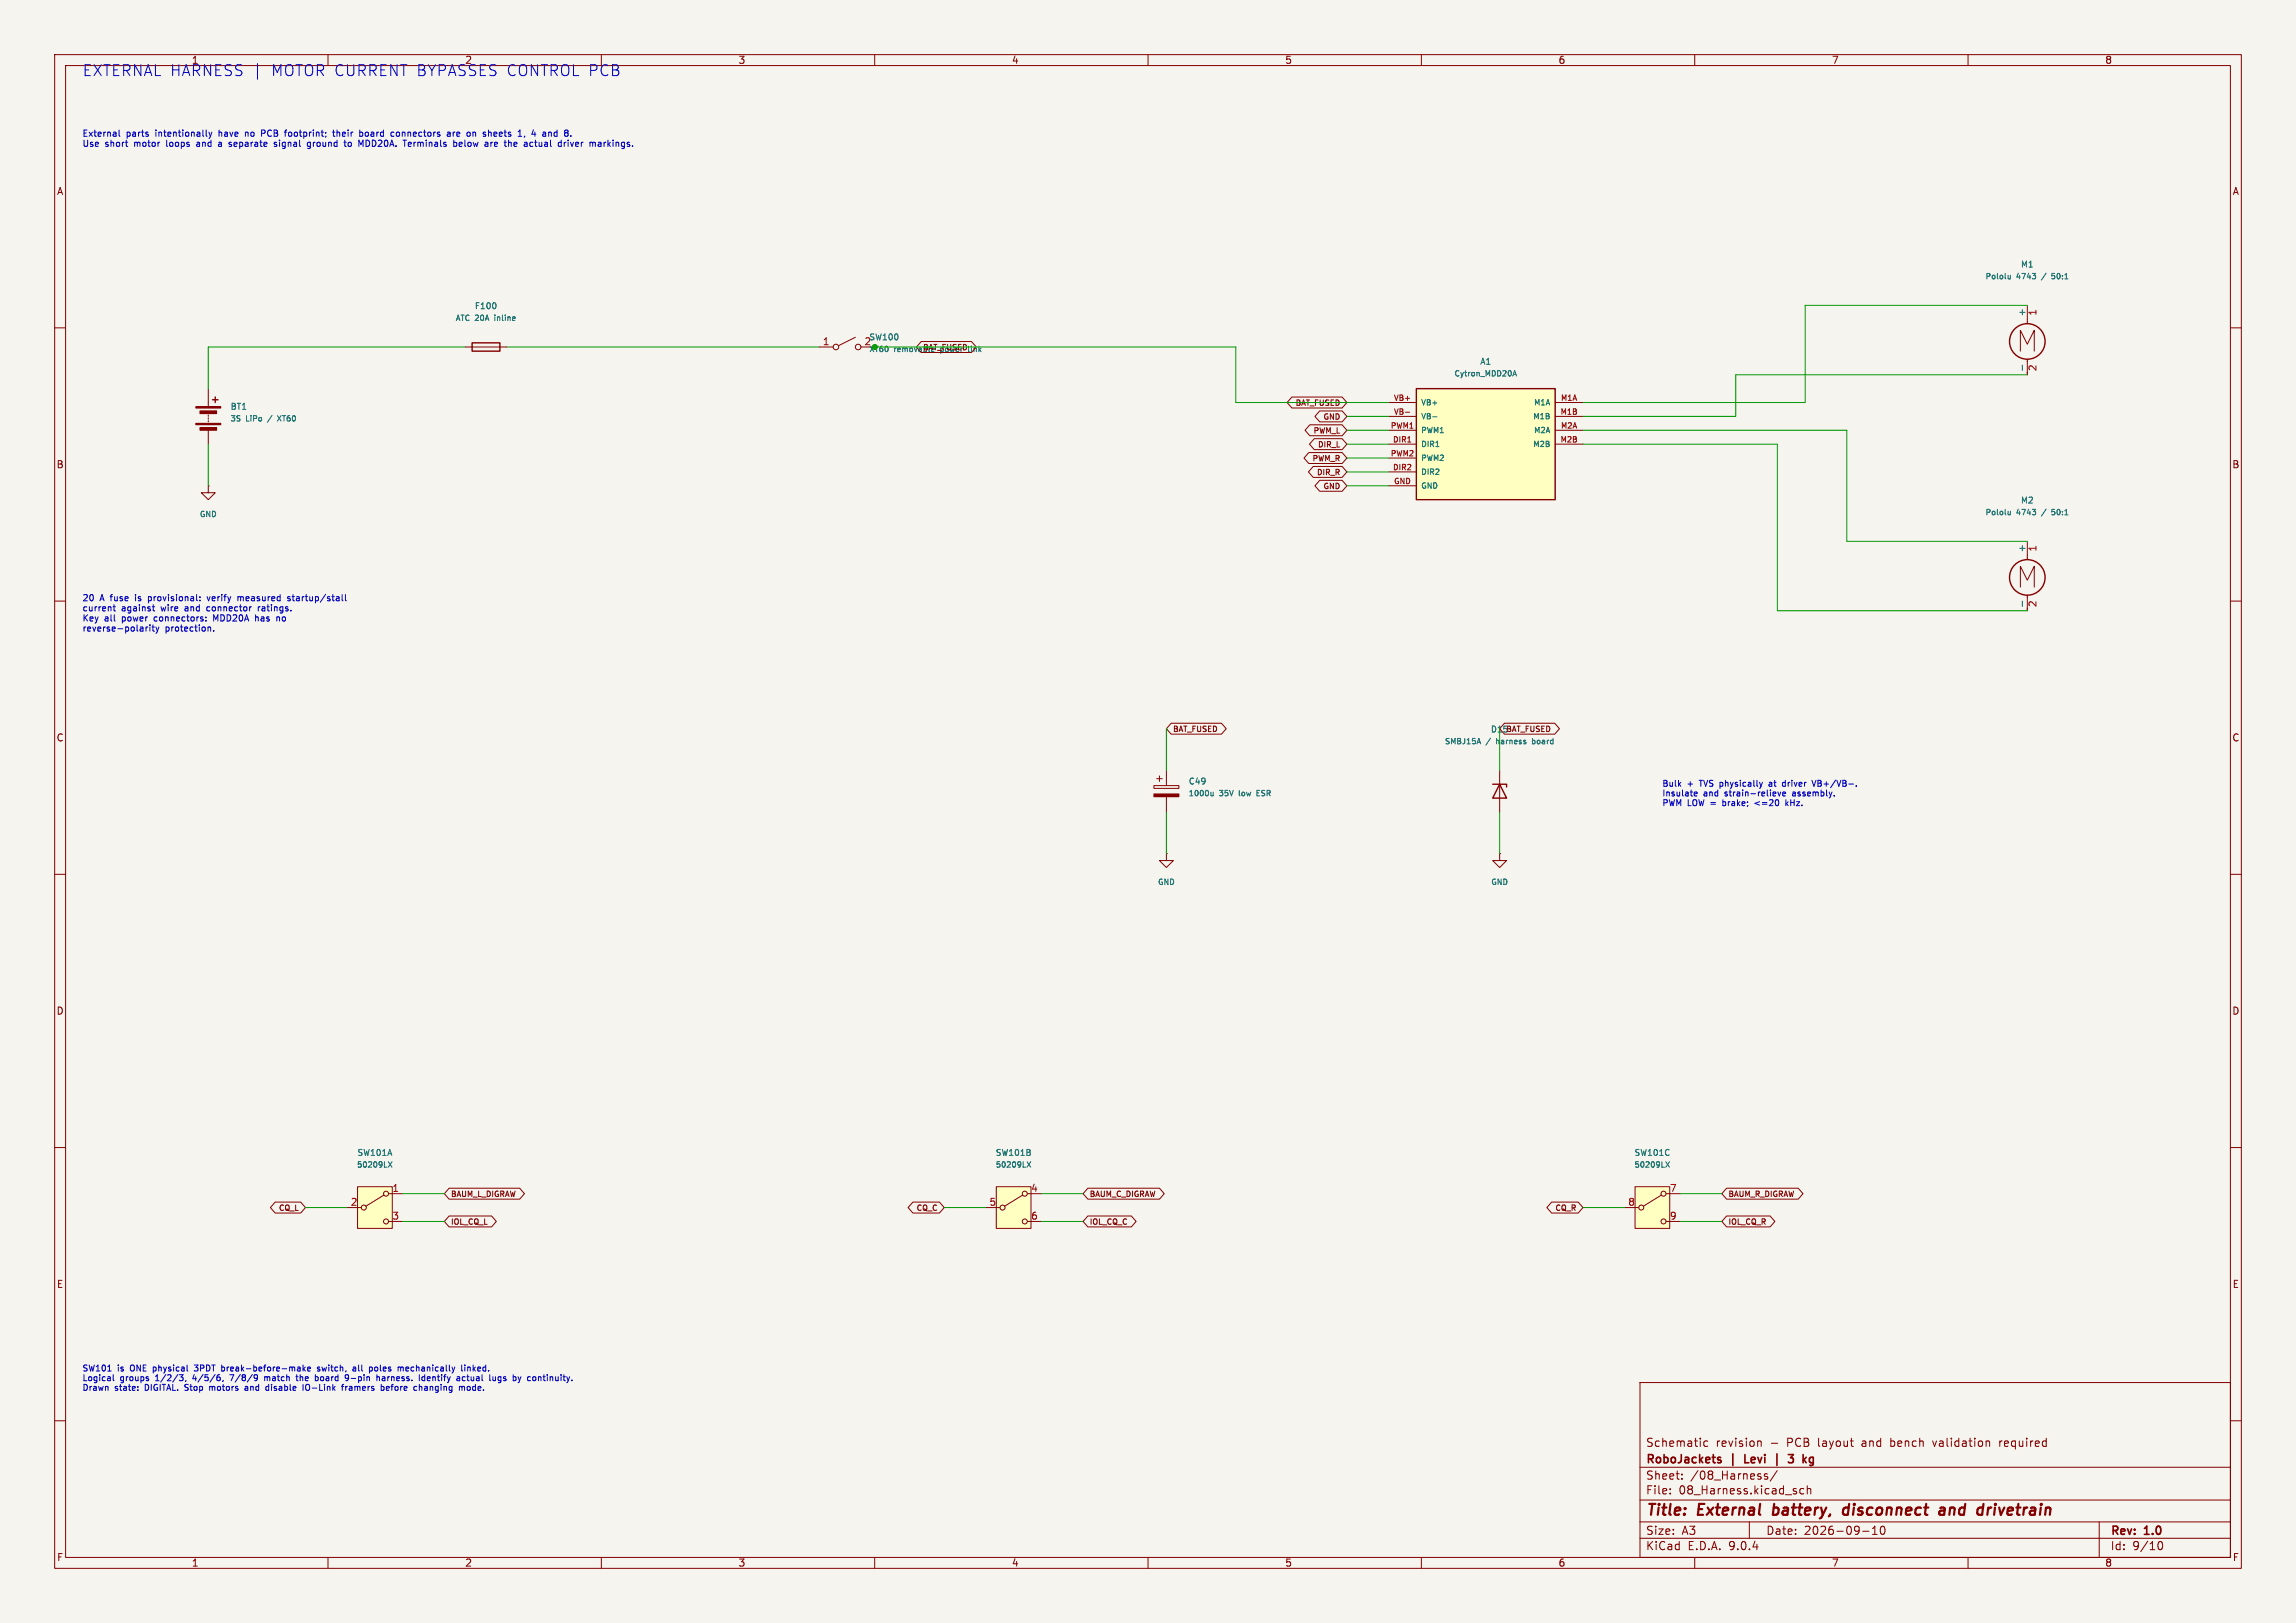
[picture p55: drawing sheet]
(kicad_sch
 (version 20250114)
 (generator "eeschema")
 (generator_version "9.0")
 (paper "A3")
 (title_block
  (title "External battery, disconnect and drivetrain")
  (date "2026-09-10")
  (rev "1.0")
  (company "RoboJackets | Levi | 3 kg")
  (comment 1 "Schematic revision - PCB layout and bench validation required"))
 (lib_symbols
  (symbol "Device:Battery"
   (pin_numbers (hide yes))
   (pin_names
    (offset 0) (hide yes)) (exclude_from_sim no) (in_bom yes) (on_board yes)
   (property "Reference" "BT" (at 2.54 2.54 0) (effects (font (size 1.27 1.27)) (justify left)))
   (property "Value" "Battery" (at 2.54 0 0) (effects (font (size 1.27 1.27)) (justify left)))
   (property "Footprint" "" (at 0 1.524 90) (effects (font (size 1.27 1.27)) (hide yes)))
   (property "Datasheet" "~" (at 0 1.524 90) (effects (font (size 1.27 1.27)) (hide yes)))
   (property "Description" "Multiple-cell battery" (at 0 0 0) (effects (font (size 1.27 1.27)) (hide yes)))
   (symbol "Battery_0_1"
    (rectangle (start -2.286 1.778) (end 2.286 1.524) (stroke (width 0) (type default)) (fill (type outline)))
    (rectangle (start -2.286 -1.27) (end 2.286 -1.524) (stroke (width 0) (type default)) (fill (type outline)))
    (rectangle (start -1.524 1.016) (end 1.524 0.508) (stroke (width 0) (type default)) (fill (type outline)))
    (rectangle (start -1.524 -2.032) (end 1.524 -2.54) (stroke (width 0) (type default)) (fill (type outline)))
    (polyline (pts (xy 0 1.778) (xy 0 2.54)) (stroke (width 0) (type default)) (fill (type none)))
    (polyline (pts (xy 0 0) (xy 0 0.254)) (stroke (width 0) (type default)) (fill (type none)))
    (polyline (pts (xy 0 -0.508) (xy 0 -0.254)) (stroke (width 0) (type default)) (fill (type none)))
    (polyline (pts (xy 0 -1.016) (xy 0 -0.762)) (stroke (width 0) (type default)) (fill (type none)))
    (polyline (pts (xy 0.762 3.048) (xy 1.778 3.048)) (stroke (width 0.254) (type default)) (fill (type none)))
    (polyline (pts (xy 1.27 3.556) (xy 1.27 2.54)) (stroke (width 0.254) (type default)) (fill (type none))))
   (symbol "Battery_1_1"
    (pin passive line (at 0 5.08 270) (length 2.54) (name "+" (effects (font (size 1.27 1.27)))) (number "1" (effects (font (size 1.27 1.27)))))
    (pin passive line (at 0 -5.08 90) (length 2.54) (name "-" (effects (font (size 1.27 1.27)))) (number "2" (effects (font (size 1.27 1.27))))))
   (embedded_fonts no))
  (symbol "Device:C_Polarized"
   (pin_numbers (hide yes))
   (pin_names
    (offset 0.254)) (exclude_from_sim no) (in_bom yes) (on_board yes)
   (property "Reference" "C" (at 0.635 2.54 0) (effects (font (size 1.27 1.27)) (justify left)))
   (property "Value" "C_Polarized" (at 0.635 -2.54 0) (effects (font (size 1.27 1.27)) (justify left)))
   (property "Footprint" "" (at 0.9652 -3.81 0) (effects (font (size 1.27 1.27)) (hide yes)))
   (property "Datasheet" "~" (at 0 0 0) (effects (font (size 1.27 1.27)) (hide yes)))
   (property "Description" "Polarized capacitor" (at 0 0 0) (effects (font (size 1.27 1.27)) (hide yes)))
   (symbol "C_Polarized_0_1"
    (rectangle (start -2.286 0.508) (end 2.286 1.016) (stroke (width 0) (type default)) (fill (type none)))
    (polyline (pts (xy -1.778 2.286) (xy -0.762 2.286)) (stroke (width 0) (type default)) (fill (type none)))
    (polyline (pts (xy -1.27 2.794) (xy -1.27 1.778)) (stroke (width 0) (type default)) (fill (type none)))
    (rectangle (start 2.286 -0.508) (end -2.286 -1.016) (stroke (width 0) (type default)) (fill (type outline))))
   (symbol "C_Polarized_1_1"
    (pin passive line (at 0 3.81 270) (length 2.794) (name "~" (effects (font (size 1.27 1.27)))) (number "1" (effects (font (size 1.27 1.27)))))
    (pin passive line (at 0 -3.81 90) (length 2.794) (name "~" (effects (font (size 1.27 1.27)))) (number "2" (effects (font (size 1.27 1.27))))))
   (embedded_fonts no))
  (symbol "Device:D_Zener"
   (pin_numbers (hide yes))
   (pin_names
    (offset 1.016) (hide yes)) (exclude_from_sim no) (in_bom yes) (on_board yes)
   (property "Reference" "D" (at 0 2.54 0) (effects (font (size 1.27 1.27))))
   (property "Value" "D_Zener" (at 0 -2.54 0) (effects (font (size 1.27 1.27))))
   (property "Footprint" "" (at 0 0 0) (effects (font (size 1.27 1.27)) (hide yes)))
   (property "Datasheet" "~" (at 0 0 0) (effects (font (size 1.27 1.27)) (hide yes)))
   (property "Description" "Zener diode" (at 0 0 0) (effects (font (size 1.27 1.27)) (hide yes)))
   (symbol "D_Zener_0_1"
    (polyline (pts (xy -1.27 -1.27) (xy -1.27 1.27) (xy -0.762 1.27)) (stroke (width 0.254) (type default)) (fill (type none)))
    (polyline (pts (xy 1.27 0) (xy -1.27 0)) (stroke (width 0) (type default)) (fill (type none)))
    (polyline (pts (xy 1.27 -1.27) (xy 1.27 1.27) (xy -1.27 0) (xy 1.27 -1.27)) (stroke (width 0.254) (type default)) (fill (type none))))
   (symbol "D_Zener_1_1"
    (pin passive line (at -3.81 0 0) (length 2.54) (name "K" (effects (font (size 1.27 1.27)))) (number "1" (effects (font (size 1.27 1.27)))))
    (pin passive line (at 3.81 0 180) (length 2.54) (name "A" (effects (font (size 1.27 1.27)))) (number "2" (effects (font (size 1.27 1.27))))))
   (embedded_fonts no))
  (symbol "Device:Fuse"
   (pin_numbers (hide yes))
   (pin_names
    (offset 0)) (exclude_from_sim no) (in_bom yes) (on_board yes)
   (property "Reference" "F" (at 2.032 0 90) (effects (font (size 1.27 1.27))))
   (property "Value" "Fuse" (at -1.905 0 90) (effects (font (size 1.27 1.27))))
   (property "Footprint" "" (at -1.778 0 90) (effects (font (size 1.27 1.27)) (hide yes)))
   (property "Datasheet" "~" (at 0 0 0) (effects (font (size 1.27 1.27)) (hide yes)))
   (property "Description" "Fuse" (at 0 0 0) (effects (font (size 1.27 1.27)) (hide yes)))
   (symbol "Fuse_0_1"
    (rectangle (start -0.762 -2.54) (end 0.762 2.54) (stroke (width 0.254) (type default)) (fill (type none)))
    (polyline (pts (xy 0 2.54) (xy 0 -2.54)) (stroke (width 0) (type default)) (fill (type none))))
   (symbol "Fuse_1_1"
    (pin passive line (at 0 3.81 270) (length 1.27) (name "~" (effects (font (size 1.27 1.27)))) (number "1" (effects (font (size 1.27 1.27)))))
    (pin passive line (at 0 -3.81 90) (length 1.27) (name "~" (effects (font (size 1.27 1.27)))) (number "2" (effects (font (size 1.27 1.27))))))
   (embedded_fonts no))
  (symbol "Levi:50209LX_Harness"
   (pin_names
    (offset 0) (hide yes)) (exclude_from_sim no) (in_bom yes) (on_board yes)
   (property "Reference" "SW" (at 0 5.08 0) (effects (font (size 1.27 1.27))))
   (property "Value" "SW_SPDT" (at 0 -5.08 0) (effects (font (size 1.27 1.27))))
   (property "Footprint" "" (at 0 0 0) (effects (font (size 1.27 1.27)) (hide yes)))
   (property "Datasheet" "~" (at 0 -7.62 0) (effects (font (size 1.27 1.27)) (hide yes)))
   (property "Description" "Switch, single pole double throw" (at 0 0 0) (effects (font (size 1.27 1.27)) (hide yes)))
   (embedded_fonts no)
   (symbol "50209LX_Harness_1_0"
    (circle (center -2.032 0) (radius 0.4572) (stroke (width 0) (type default)) (fill (type none)))
    (polyline (pts (xy -1.651 0.254) (xy 1.651 2.286)) (stroke (width 0) (type default)) (fill (type none)))
    (circle (center 2.032 2.54) (radius 0.4572) (stroke (width 0) (type default)) (fill (type none)))
    (circle (center 2.032 -2.54) (radius 0.4572) (stroke (width 0) (type default)) (fill (type none))))
   (symbol "50209LX_Harness_1_1"
    (rectangle (start -3.175 3.81) (end 3.175 -3.81) (stroke (width 0) (type default)) (fill (type background)))
    (pin passive line (at -5.08 0 0) (length 2.54) (name "B" (effects (font (size 1.27 1.27)))) (number "2" (effects (font (size 1.27 1.27)))))
    (pin passive line (at 5.08 2.54 180) (length 2.54) (name "A" (effects (font (size 1.27 1.27)))) (number "1" (effects (font (size 1.27 1.27)))))
    (pin passive line (at 5.08 -2.54 180) (length 2.54) (name "C" (effects (font (size 1.27 1.27)))) (number "3" (effects (font (size 1.27 1.27))))))
   (symbol "50209LX_Harness_2_0"
    (circle (center -2.032 0) (radius 0.4572) (stroke (width 0) (type default)) (fill (type none)))
    (polyline (pts (xy -1.651 0.254) (xy 1.651 2.286)) (stroke (width 0) (type default)) (fill (type none)))
    (circle (center 2.032 2.54) (radius 0.4572) (stroke (width 0) (type default)) (fill (type none)))
    (circle (center 2.032 -2.54) (radius 0.4572) (stroke (width 0) (type default)) (fill (type none))))
   (symbol "50209LX_Harness_2_1"
    (rectangle (start -3.175 3.81) (end 3.175 -3.81) (stroke (width 0) (type default)) (fill (type background)))
    (pin passive line (at -5.08 0 0) (length 2.54) (name "B" (effects (font (size 1.27 1.27)))) (number "5" (effects (font (size 1.27 1.27)))))
    (pin passive line (at 5.08 2.54 180) (length 2.54) (name "A" (effects (font (size 1.27 1.27)))) (number "4" (effects (font (size 1.27 1.27)))))
    (pin passive line (at 5.08 -2.54 180) (length 2.54) (name "C" (effects (font (size 1.27 1.27)))) (number "6" (effects (font (size 1.27 1.27))))))
   (symbol "50209LX_Harness_3_0"
    (circle (center -2.032 0) (radius 0.4572) (stroke (width 0) (type default)) (fill (type none)))
    (polyline (pts (xy -1.651 0.254) (xy 1.651 2.286)) (stroke (width 0) (type default)) (fill (type none)))
    (circle (center 2.032 2.54) (radius 0.4572) (stroke (width 0) (type default)) (fill (type none)))
    (circle (center 2.032 -2.54) (radius 0.4572) (stroke (width 0) (type default)) (fill (type none))))
   (symbol "50209LX_Harness_3_1"
    (rectangle (start -3.175 3.81) (end 3.175 -3.81) (stroke (width 0) (type default)) (fill (type background)))
    (pin passive line (at -5.08 0 0) (length 2.54) (name "B" (effects (font (size 1.27 1.27)))) (number "8" (effects (font (size 1.27 1.27)))))
    (pin passive line (at 5.08 2.54 180) (length 2.54) (name "A" (effects (font (size 1.27 1.27)))) (number "7" (effects (font (size 1.27 1.27)))))
    (pin passive line (at 5.08 -2.54 180) (length 2.54) (name "C" (effects (font (size 1.27 1.27)))) (number "9" (effects (font (size 1.27 1.27)))))))
  (symbol "Levi:Cytron_MDD20A"
   (pin_names
    (offset 0.8)) (in_bom yes) (on_board yes)
   (property "Reference" "U" (at 0 0 0) (effects (font (size 1.1 1.1))))
   (property "Value" "Cytron_MDD20A" (at 0 0 0) (effects (font (size 1.1 1.1))))
   (property "Footprint" "" (at 0 0 0) (effects (font (size 1.1 1.1))))
   (property "Datasheet" "https://docs.google.com/document/d/1YHKcs8N0UBrRI4r2OaIqHs6m_B_NaVBF7EB5C3fPTG4/edit" (at 0 0 0) (effects (font (size 1.1 1.1))))
   (property "Description" "External complete driver; actual named terminals." (at 0 0 0) (effects (font (size 1.1 1.1))))
   (symbol "Cytron_MDD20A_1_1"
    (rectangle (start -12.7 10.16) (end 12.7 -10.16) (stroke (width 0.254) (type default)) (fill (type background)))
    (pin passive line (at -17.78 7.62 0) (length 5.08) (name "VB+" (effects (font (size 1 1)))) (number "VB+" (effects (font (size 1 1)))))
    (pin passive line (at -17.78 5.08 0) (length 5.08) (name "VB-" (effects (font (size 1 1)))) (number "VB-" (effects (font (size 1 1)))))
    (pin input line (at -17.78 2.54 0) (length 5.08) (name "PWM1" (effects (font (size 1 1)))) (number "PWM1" (effects (font (size 1 1)))))
    (pin input line (at -17.78 0 0) (length 5.08) (name "DIR1" (effects (font (size 1 1)))) (number "DIR1" (effects (font (size 1 1)))))
    (pin input line (at -17.78 -2.54 0) (length 5.08) (name "PWM2" (effects (font (size 1 1)))) (number "PWM2" (effects (font (size 1 1)))))
    (pin input line (at -17.78 -5.08 0) (length 5.08) (name "DIR2" (effects (font (size 1 1)))) (number "DIR2" (effects (font (size 1 1)))))
    (pin passive line (at -17.78 -7.62 0) (length 5.08) (name "GND" (effects (font (size 1 1)))) (number "GND" (effects (font (size 1 1)))))
    (pin passive line (at 17.78 7.62 180) (length 5.08) (name "M1A" (effects (font (size 1 1)))) (number "M1A" (effects (font (size 1 1)))))
    (pin passive line (at 17.78 5.08 180) (length 5.08) (name "M1B" (effects (font (size 1 1)))) (number "M1B" (effects (font (size 1 1)))))
    (pin passive line (at 17.78 2.54 180) (length 5.08) (name "M2A" (effects (font (size 1 1)))) (number "M2A" (effects (font (size 1 1)))))
    (pin passive line (at 17.78 0 180) (length 5.08) (name "M2B" (effects (font (size 1 1)))) (number "M2B" (effects (font (size 1 1)))))))
  (symbol "Motor:Motor_DC"
   (pin_names
    (offset 0)) (exclude_from_sim no) (in_bom yes) (on_board yes)
   (property "Reference" "M" (at 2.54 2.54 0) (effects (font (size 1.27 1.27)) (justify left)))
   (property "Value" "Motor_DC" (at 2.54 -5.08 0) (effects (font (size 1.27 1.27)) (justify left top)))
   (property "Footprint" "" (at 0 -2.286 0) (effects (font (size 1.27 1.27)) (hide yes)))
   (property "Datasheet" "~" (at 0 -2.286 0) (effects (font (size 1.27 1.27)) (hide yes)))
   (property "Description" "DC Motor" (at 0 0 0) (effects (font (size 1.27 1.27)) (hide yes)))
   (symbol "Motor_DC_0_0"
    (polyline (pts (xy -1.27 -3.302) (xy -1.27 0.508) (xy 0 -2.032) (xy 1.27 0.508) (xy 1.27 -3.302)) (stroke (width 0) (type default)) (fill (type none))))
   (symbol "Motor_DC_0_1"
    (polyline (pts (xy 0 2.032) (xy 0 2.54)) (stroke (width 0) (type default)) (fill (type none)))
    (polyline (pts (xy 0 1.7272) (xy 0 2.0828)) (stroke (width 0) (type default)) (fill (type none)))
    (circle (center 0 -1.524) (radius 3.2512) (stroke (width 0.254) (type default)) (fill (type none)))
    (polyline (pts (xy 0 -4.7752) (xy 0 -5.1816)) (stroke (width 0) (type default)) (fill (type none)))
    (polyline (pts (xy 0 -7.62) (xy 0 -7.112)) (stroke (width 0) (type default)) (fill (type none))))
   (symbol "Motor_DC_1_1"
    (pin passive line (at 0 5.08 270) (length 2.54) (name "+" (effects (font (size 1.27 1.27)))) (number "1" (effects (font (size 1.27 1.27)))))
    (pin passive line (at 0 -7.62 90) (length 2.54) (name "-" (effects (font (size 1.27 1.27)))) (number "2" (effects (font (size 1.27 1.27))))))
   (embedded_fonts no))
  (symbol "Switch:SW_SPST"
   (pin_names
    (offset 0) (hide yes)) (exclude_from_sim no) (in_bom yes) (on_board yes)
   (property "Reference" "SW" (at 0 3.175 0) (effects (font (size 1.27 1.27))))
   (property "Value" "SW_SPST" (at 0 -2.54 0) (effects (font (size 1.27 1.27))))
   (property "Footprint" "" (at 0 0 0) (effects (font (size 1.27 1.27)) (hide yes)))
   (property "Datasheet" "~" (at 0 0 0) (effects (font (size 1.27 1.27)) (hide yes)))
   (property "Description" "Single Pole Single Throw (SPST) switch" (at 0 0 0) (effects (font (size 1.27 1.27)) (hide yes)))
   (symbol "SW_SPST_0_0"
    (circle (center -2.032 0) (radius 0.508) (stroke (width 0) (type default)) (fill (type none)))
    (polyline (pts (xy -1.524 0.254) (xy 1.524 1.778)) (stroke (width 0) (type default)) (fill (type none)))
    (circle (center 2.032 0) (radius 0.508) (stroke (width 0) (type default)) (fill (type none))))
   (symbol "SW_SPST_1_1"
    (pin passive line (at -5.08 0 0) (length 2.54) (name "A" (effects (font (size 1.27 1.27)))) (number "1" (effects (font (size 1.27 1.27)))))
    (pin passive line (at 5.08 0 180) (length 2.54) (name "B" (effects (font (size 1.27 1.27)))) (number "2" (effects (font (size 1.27 1.27))))))
   (embedded_fonts no))
  (symbol "power:GND"
   (power)
   (pin_numbers (hide yes))
   (pin_names
    (offset 0) (hide yes)) (exclude_from_sim no) (in_bom yes) (on_board yes)
   (property "Reference" "#PWR" (at 0 -6.35 0) (effects (font (size 1.27 1.27)) (hide yes)))
   (property "Value" "GND" (at 0 -3.81 0) (effects (font (size 1.27 1.27))))
   (property "Footprint" "" (at 0 0 0) (effects (font (size 1.27 1.27)) (hide yes)))
   (property "Datasheet" "" (at 0 0 0) (effects (font (size 1.27 1.27)) (hide yes)))
   (property "Description" "Power symbol creates a global label with name \"GND\" , ground" (at 0 0 0) (effects (font (size 1.27 1.27)) (hide yes)))
   (symbol "GND_0_1"
    (polyline (pts (xy 0 0) (xy 0 -1.27) (xy 1.27 -1.27) (xy 0 -2.54) (xy -1.27 -1.27) (xy 0 -1.27)) (stroke (width 0) (type default)) (fill (type none))))
   (symbol "GND_1_1"
    (pin power_in line (at 0 0 270) (length 0) (name "~" (effects (font (size 1.27 1.27)))) (number "1" (effects (font (size 1.27 1.27))))))
   (embedded_fonts no)))
 (text "EXTERNAL HARNESS | MOTOR CURRENT BYPASSES CONTROL PCB"
  (at 15 12 0)
  (effects (font (size 2 2)) (justify left top)))
 (text "External parts intentionally have no PCB footprint; their board connectors are on sheets 1, 4 and 8.\nUse short motor loops and a separate signal ground to MDD20A. Terminals below are the actual driver markings."
  (at 15 24 0)
  (effects (font (size 1.15 1.15)) (justify left top)))
 (global_label "BAT_FUSED"
  (shape bidirectional)
  (at 167.64 63.5 0)
  (effects (font (size 1 1)) (justify left))
  (property "Intersheetrefs" "${INTERSHEET_REFS}" (at 167.64 63.5 0) (effects (font (size 1 1)) (hide yes))))
 (text "20 A fuse is provisional: verify measured startup/stall\ncurrent against wire and connector ratings.\nKey all power connectors: MDD20A has no\nreverse-polarity protection."
  (at 15 109 0)
  (effects (font (size 1.15 1.15)) (justify left top)))
 (global_label "BAT_FUSED"
  (shape bidirectional)
  (at 246.38 73.66 180)
  (effects (font (size 1 1)) (justify right))
  (property "Intersheetrefs" "${INTERSHEET_REFS}" (at 246.38 73.66 0) (effects (font (size 1 1)) (hide yes))))
 (global_label "GND"
  (shape bidirectional)
  (at 246.38 76.2 180)
  (effects (font (size 1 1)) (justify right))
  (property "Intersheetrefs" "${INTERSHEET_REFS}" (at 246.38 76.2 0) (effects (font (size 1 1)) (hide yes))))
 (global_label "PWM_L"
  (shape bidirectional)
  (at 246.38 78.74 180)
  (effects (font (size 1 1)) (justify right))
  (property "Intersheetrefs" "${INTERSHEET_REFS}" (at 246.38 78.74 0) (effects (font (size 1 1)) (hide yes))))
 (global_label "DIR_L"
  (shape bidirectional)
  (at 246.38 81.28 180)
  (effects (font (size 1 1)) (justify right))
  (property "Intersheetrefs" "${INTERSHEET_REFS}" (at 246.38 81.28 0) (effects (font (size 1 1)) (hide yes))))
 (global_label "PWM_R"
  (shape bidirectional)
  (at 246.38 83.82 180)
  (effects (font (size 1 1)) (justify right))
  (property "Intersheetrefs" "${INTERSHEET_REFS}" (at 246.38 83.82 0) (effects (font (size 1 1)) (hide yes))))
 (global_label "DIR_R"
  (shape bidirectional)
  (at 246.38 86.36 180)
  (effects (font (size 1 1)) (justify right))
  (property "Intersheetrefs" "${INTERSHEET_REFS}" (at 246.38 86.36 0) (effects (font (size 1 1)) (hide yes))))
 (global_label "GND"
  (shape bidirectional)
  (at 246.38 88.9 180)
  (effects (font (size 1 1)) (justify right))
  (property "Intersheetrefs" "${INTERSHEET_REFS}" (at 246.38 88.9 0) (effects (font (size 1 1)) (hide yes))))
 (junction
  (at 160.02 63.5)
  (diameter 0)
  (color 0 0 0 0))
 (global_label "BAT_FUSED"
  (shape bidirectional)
  (at 213.36 133.35 0)
  (effects (font (size 1 1)) (justify left))
  (property "Intersheetrefs" "${INTERSHEET_REFS}" (at 213.36 133.35 0) (effects (font (size 1 1)) (hide yes))))
 (global_label "BAT_FUSED"
  (shape bidirectional)
  (at 274.32 133.35 0)
  (effects (font (size 1 1)) (justify left))
  (property "Intersheetrefs" "${INTERSHEET_REFS}" (at 274.32 133.35 0) (effects (font (size 1 1)) (hide yes))))
 (text "Bulk + TVS physically at driver VB+/VB-.\nInsulate and strain-relieve assembly.\nPWM LOW = brake; <=20 kHz."
  (at 304 143 0)
  (effects (font (size 1.1 1.1)) (justify left top)))
 (global_label "CQ_L"
  (shape bidirectional)
  (at 55.88 220.98 180)
  (effects (font (size 1 1)) (justify right))
  (property "Intersheetrefs" "${INTERSHEET_REFS}" (at 55.88 220.98 0) (effects (font (size 1 1)) (hide yes))))
 (global_label "BAUM_L_DIGRAW"
  (shape bidirectional)
  (at 81.28 218.44 0)
  (effects (font (size 1 1)) (justify left))
  (property "Intersheetrefs" "${INTERSHEET_REFS}" (at 81.28 218.44 0) (effects (font (size 1 1)) (hide yes))))
 (global_label "IOL_CQ_L"
  (shape bidirectional)
  (at 81.28 223.52 0)
  (effects (font (size 1 1)) (justify left))
  (property "Intersheetrefs" "${INTERSHEET_REFS}" (at 81.28 223.52 0) (effects (font (size 1 1)) (hide yes))))
 (global_label "CQ_C"
  (shape bidirectional)
  (at 172.72 220.98 180)
  (effects (font (size 1 1)) (justify right))
  (property "Intersheetrefs" "${INTERSHEET_REFS}" (at 172.72 220.98 0) (effects (font (size 1 1)) (hide yes))))
 (global_label "BAUM_C_DIGRAW"
  (shape bidirectional)
  (at 198.12 218.44 0)
  (effects (font (size 1 1)) (justify left))
  (property "Intersheetrefs" "${INTERSHEET_REFS}" (at 198.12 218.44 0) (effects (font (size 1 1)) (hide yes))))
 (global_label "IOL_CQ_C"
  (shape bidirectional)
  (at 198.12 223.52 0)
  (effects (font (size 1 1)) (justify left))
  (property "Intersheetrefs" "${INTERSHEET_REFS}" (at 198.12 223.52 0) (effects (font (size 1 1)) (hide yes))))
 (global_label "CQ_R"
  (shape bidirectional)
  (at 289.56 220.98 180)
  (effects (font (size 1 1)) (justify right))
  (property "Intersheetrefs" "${INTERSHEET_REFS}" (at 289.56 220.98 0) (effects (font (size 1 1)) (hide yes))))
 (global_label "BAUM_R_DIGRAW"
  (shape bidirectional)
  (at 314.96 218.44 0)
  (effects (font (size 1 1)) (justify left))
  (property "Intersheetrefs" "${INTERSHEET_REFS}" (at 314.96 218.44 0) (effects (font (size 1 1)) (hide yes))))
 (global_label "IOL_CQ_R"
  (shape bidirectional)
  (at 314.96 223.52 0)
  (effects (font (size 1 1)) (justify left))
  (property "Intersheetrefs" "${INTERSHEET_REFS}" (at 314.96 223.52 0) (effects (font (size 1 1)) (hide yes))))
 (text "SW101 is ONE physical 3PDT break-before-make switch, all poles mechanically linked.\nLogical groups 1/2/3, 4/5/6, 7/8/9 match the board 9-pin harness. Identify actual lugs by continuity.\nDrawn state: DIGITAL. Stop motors and disable IO-Link framers before changing mode."
  (at 15 250 0)
  (effects (font (size 1.1 1.1)) (justify left top)))
 (wire
  (pts (xy 38.1 81.28) (xy 38.1 88.9))
  (stroke (width 0) (type default)))
 (wire
  (pts (xy 38.1 71.12) (xy 38.1 63.5))
  (stroke (width 0) (type default)))
 (wire
  (pts (xy 38.1 63.5) (xy 85.09 63.5))
  (stroke (width 0) (type default)))
 (wire
  (pts (xy 92.71 63.5) (xy 149.86 63.5))
  (stroke (width 0) (type default)))
 (wire
  (pts (xy 160.02 63.5) (xy 167.64 63.5))
  (stroke (width 0) (type default)))
 (wire
  (pts (xy 254 73.66) (xy 246.38 73.66))
  (stroke (width 0) (type default)))
 (wire
  (pts (xy 254 76.2) (xy 246.38 76.2))
  (stroke (width 0) (type default)))
 (wire
  (pts (xy 254 78.74) (xy 246.38 78.74))
  (stroke (width 0) (type default)))
 (wire
  (pts (xy 254 81.28) (xy 246.38 81.28))
  (stroke (width 0) (type default)))
 (wire
  (pts (xy 254 83.82) (xy 246.38 83.82))
  (stroke (width 0) (type default)))
 (wire
  (pts (xy 254 86.36) (xy 246.38 86.36))
  (stroke (width 0) (type default)))
 (wire
  (pts (xy 254 88.9) (xy 246.38 88.9))
  (stroke (width 0) (type default)))
 (wire
  (pts (xy 289.56 73.66) (xy 330.2 73.66))
  (stroke (width 0) (type default)))
 (wire
  (pts (xy 330.2 73.66) (xy 330.2 55.88))
  (stroke (width 0) (type default)))
 (wire
  (pts (xy 330.2 55.88) (xy 370.84 55.88))
  (stroke (width 0) (type default)))
 (wire
  (pts (xy 289.56 76.2) (xy 317.5 76.2))
  (stroke (width 0) (type default)))
 (wire
  (pts (xy 317.5 76.2) (xy 317.5 68.58))
  (stroke (width 0) (type default)))
 (wire
  (pts (xy 317.5 68.58) (xy 370.84 68.58))
  (stroke (width 0) (type default)))
 (wire
  (pts (xy 289.56 78.74) (xy 337.82 78.74))
  (stroke (width 0) (type default)))
 (wire
  (pts (xy 337.82 78.74) (xy 337.82 99.06))
  (stroke (width 0) (type default)))
 (wire
  (pts (xy 337.82 99.06) (xy 370.84 99.06))
  (stroke (width 0) (type default)))
 (wire
  (pts (xy 289.56 81.28) (xy 325.12 81.28))
  (stroke (width 0) (type default)))
 (wire
  (pts (xy 325.12 81.28) (xy 325.12 111.76))
  (stroke (width 0) (type default)))
 (wire
  (pts (xy 325.12 111.76) (xy 370.84 111.76))
  (stroke (width 0) (type default)))
 (wire
  (pts (xy 167.64 63.5) (xy 226.06 63.5))
  (stroke (width 0) (type default)))
 (wire
  (pts (xy 226.06 63.5) (xy 226.06 73.66))
  (stroke (width 0) (type default)))
 (wire
  (pts (xy 226.06 73.66) (xy 246.38 73.66))
  (stroke (width 0) (type default)))
 (wire
  (pts (xy 213.36 140.97) (xy 213.36 133.35))
  (stroke (width 0) (type default)))
 (wire
  (pts (xy 213.36 148.59) (xy 213.36 156.21))
  (stroke (width 0) (type default)))
 (wire
  (pts (xy 274.32 140.97) (xy 274.32 133.35))
  (stroke (width 0) (type default)))
 (wire
  (pts (xy 274.32 148.59) (xy 274.32 156.21))
  (stroke (width 0) (type default)))
 (wire
  (pts (xy 63.5 220.98) (xy 55.88 220.98))
  (stroke (width 0) (type default)))
 (wire
  (pts (xy 73.66 218.44) (xy 81.28 218.44))
  (stroke (width 0) (type default)))
 (wire
  (pts (xy 73.66 223.52) (xy 81.28 223.52))
  (stroke (width 0) (type default)))
 (wire
  (pts (xy 180.34 220.98) (xy 172.72 220.98))
  (stroke (width 0) (type default)))
 (wire
  (pts (xy 190.5 218.44) (xy 198.12 218.44))
  (stroke (width 0) (type default)))
 (wire
  (pts (xy 190.5 223.52) (xy 198.12 223.52))
  (stroke (width 0) (type default)))
 (wire
  (pts (xy 297.18 220.98) (xy 289.56 220.98))
  (stroke (width 0) (type default)))
 (wire
  (pts (xy 307.34 218.44) (xy 314.96 218.44))
  (stroke (width 0) (type default)))
 (wire
  (pts (xy 307.34 223.52) (xy 314.96 223.52))
  (stroke (width 0) (type default)))
 (symbol
  (lib_id "Device:Battery")
  (at 38.1 76.2 0)
  (unit 1)
  (exclude_from_sim no)
  (in_bom yes)
  (on_board no)
  (dnp no)
  (property "Reference" "BT1" (at 42.1 74.4 0) (effects (font (size 1.1 1.1)) (justify left)))
  (property "Value" "3S LiPo / XT60" (at 42.1 76.6 0) (effects (font (size 1 1)) (justify left)))
  (property "Footprint" "" (at 38.1 76.2 0) (effects (font (size 1.1 1.1)) (hide yes) (justify left)))
  (property "Datasheet" "~" (at 38.1 76.2 0) (effects (font (size 1.1 1.1)) (hide yes) (justify left)))
  (pin "1")
  (pin "2"))
 (symbol
  (lib_id "power:GND")
  (at 38.1 88.9 0)
  (unit 1)
  (exclude_from_sim no)
  (in_bom no)
  (on_board no)
  (dnp no)
  (property "Reference" "#PWR127" (at 38.1 91.9 0) (effects (font (size 1.1 1.1)) (hide yes)))
  (property "Value" "GND" (at 38.1 94.1 0) (effects (font (size 1 1))))
  (property "Footprint" "" (at 38.1 88.9 0) (effects (font (size 1.1 1.1)) (hide yes)))
  (property "Datasheet" "" (at 38.1 88.9 0) (effects (font (size 1.1 1.1)) (hide yes)))
  (pin "1"))
 (symbol
  (lib_id "Device:Fuse")
  (at 88.9 63.5 270)
  (unit 1)
  (exclude_from_sim no)
  (in_bom yes)
  (on_board no)
  (dnp no)
  (property "Reference" "F100" (at 88.9 56 90) (effects (font (size 1.1 1.1))))
  (property "Value" "ATC 20A inline" (at 88.9 58.2 90) (effects (font (size 1 1))))
  (property "Footprint" "" (at 88.9 63.5 90) (effects (font (size 1.1 1.1)) (hide yes)))
  (property "Datasheet" "~" (at 88.9 63.5 90) (effects (font (size 1.1 1.1)) (hide yes)))
  (pin "1")
  (pin "2"))
 (symbol
  (lib_id "Switch:SW_SPST")
  (at 154.94 63.5 0)
  (unit 1)
  (exclude_from_sim no)
  (in_bom yes)
  (on_board no)
  (dnp no)
  (property "Reference" "SW100" (at 158.94 61.7 0) (effects (font (size 1.1 1.1)) (justify left)))
  (property "Value" "XT60 removable power link" (at 158.94 63.9 0) (effects (font (size 1 1)) (justify left)))
  (property "Footprint" "" (at 154.94 63.5 0) (effects (font (size 1.1 1.1)) (hide yes) (justify left)))
  (property "Datasheet" "~" (at 154.94 63.5 0) (effects (font (size 1.1 1.1)) (hide yes) (justify left)))
  (pin "1")
  (pin "2"))
 (symbol
  (lib_id "Levi:Cytron_MDD20A")
  (at 271.78 81.28 0)
  (unit 1)
  (exclude_from_sim no)
  (in_bom yes)
  (on_board no)
  (dnp no)
  (property "Reference" "A1" (at 271.78 66.16 0) (effects (font (size 1.1 1.1))))
  (property "Value" "Cytron_MDD20A" (at 271.78 68.36 0) (effects (font (size 1 1))))
  (property "Footprint" "" (at 271.78 81.28 0) (effects (font (size 1.1 1.1)) (hide yes)))
  (property "Datasheet" "https://docs.google.com/document/d/1YHKcs8N0UBrRI4r2OaIqHs6m_B_NaVBF7EB5C3fPTG4/edit" (at 271.78 81.28 0) (effects (font (size 1.1 1.1)) (hide yes)))
  (pin "VB+")
  (pin "VB-")
  (pin "PWM1")
  (pin "DIR1")
  (pin "PWM2")
  (pin "DIR2")
  (pin "GND")
  (pin "M1A")
  (pin "M1B")
  (pin "M2A")
  (pin "M2B"))
 (symbol
  (lib_id "Motor:Motor_DC")
  (at 370.84 60.96 0)
  (unit 1)
  (exclude_from_sim no)
  (in_bom yes)
  (on_board no)
  (dnp no)
  (property "Reference" "M1" (at 370.84 48.38 0) (effects (font (size 1.1 1.1))))
  (property "Value" "Pololu 4743 / 50:1" (at 370.84 50.58 0) (effects (font (size 1 1))))
  (property "Footprint" "" (at 370.84 60.96 0) (effects (font (size 1.1 1.1)) (hide yes)))
  (property "Datasheet" "~" (at 370.84 60.96 0) (effects (font (size 1.1 1.1)) (hide yes)))
  (pin "1")
  (pin "2"))
 (symbol
  (lib_id "Motor:Motor_DC")
  (at 370.84 104.14 0)
  (unit 1)
  (exclude_from_sim no)
  (in_bom yes)
  (on_board no)
  (dnp no)
  (property "Reference" "M2" (at 370.84 91.56 0) (effects (font (size 1.1 1.1))))
  (property "Value" "Pololu 4743 / 50:1" (at 370.84 93.76 0) (effects (font (size 1 1))))
  (property "Footprint" "" (at 370.84 104.14 0) (effects (font (size 1.1 1.1)) (hide yes)))
  (property "Datasheet" "~" (at 370.84 104.14 0) (effects (font (size 1.1 1.1)) (hide yes)))
  (pin "1")
  (pin "2"))
 (symbol
  (lib_id "Device:C_Polarized")
  (at 213.36 144.78 0)
  (unit 1)
  (exclude_from_sim no)
  (in_bom yes)
  (on_board no)
  (dnp no)
  (property "Reference" "C49" (at 217.36 142.98 0) (effects (font (size 1.1 1.1)) (justify left)))
  (property "Value" "1000u 35V low ESR" (at 217.36 145.18 0) (effects (font (size 1 1)) (justify left)))
  (property "Footprint" "" (at 213.36 144.78 0) (effects (font (size 1.1 1.1)) (hide yes) (justify left)))
  (property "Datasheet" "~" (at 213.36 144.78 0) (effects (font (size 1.1 1.1)) (hide yes) (justify left)))
  (pin "1")
  (pin "2"))
 (symbol
  (lib_id "power:GND")
  (at 213.36 156.21 0)
  (unit 1)
  (exclude_from_sim no)
  (in_bom no)
  (on_board no)
  (dnp no)
  (property "Reference" "#PWR128" (at 213.36 159.21 0) (effects (font (size 1.1 1.1)) (hide yes)))
  (property "Value" "GND" (at 213.36 161.41 0) (effects (font (size 1 1))))
  (property "Footprint" "" (at 213.36 156.21 0) (effects (font (size 1.1 1.1)) (hide yes)))
  (property "Datasheet" "" (at 213.36 156.21 0) (effects (font (size 1.1 1.1)) (hide yes)))
  (pin "1"))
 (symbol
  (lib_id "Device:D_Zener")
  (at 274.32 144.78 270)
  (unit 1)
  (exclude_from_sim no)
  (in_bom yes)
  (on_board no)
  (dnp no)
  (property "Reference" "D15" (at 274.32 133.47 90) (effects (font (size 1.1 1.1))))
  (property "Value" "SMBJ15A / harness board" (at 274.32 135.67 90) (effects (font (size 1 1))))
  (property "Footprint" "" (at 274.32 144.78 90) (effects (font (size 1.1 1.1)) (hide yes)))
  (property "Datasheet" "~" (at 274.32 144.78 90) (effects (font (size 1.1 1.1)) (hide yes)))
  (pin "1")
  (pin "2"))
 (symbol
  (lib_id "power:GND")
  (at 274.32 156.21 0)
  (unit 1)
  (exclude_from_sim no)
  (in_bom no)
  (on_board no)
  (dnp no)
  (property "Reference" "#PWR129" (at 274.32 159.21 0) (effects (font (size 1.1 1.1)) (hide yes)))
  (property "Value" "GND" (at 274.32 161.41 0) (effects (font (size 1 1))))
  (property "Footprint" "" (at 274.32 156.21 0) (effects (font (size 1.1 1.1)) (hide yes)))
  (property "Datasheet" "" (at 274.32 156.21 0) (effects (font (size 1.1 1.1)) (hide yes)))
  (pin "1"))
 (symbol
  (lib_id "Levi:50209LX_Harness")
  (at 68.58 220.98 0)
  (unit 1)
  (exclude_from_sim no)
  (in_bom yes)
  (on_board no)
  (dnp no)
  (property "Reference" "SW101" (at 68.58 210.94 0) (effects (font (size 1.1 1.1))))
  (property "Value" "50209LX" (at 68.58 213.14 0) (effects (font (size 1 1))))
  (property "Footprint" "" (at 68.58 220.98 0) (effects (font (size 1.1 1.1)) (hide yes)))
  (property "Datasheet" "~" (at 68.58 220.98 0) (effects (font (size 1.1 1.1)) (hide yes)))
  (pin "2")
  (pin "1")
  (pin "3"))
 (symbol
  (lib_id "Levi:50209LX_Harness")
  (at 185.42 220.98 0)
  (unit 2)
  (exclude_from_sim no)
  (in_bom yes)
  (on_board no)
  (dnp no)
  (property "Reference" "SW101" (at 185.42 210.94 0) (effects (font (size 1.1 1.1))))
  (property "Value" "50209LX" (at 185.42 213.14 0) (effects (font (size 1 1))))
  (property "Footprint" "" (at 185.42 220.98 0) (effects (font (size 1.1 1.1)) (hide yes)))
  (property "Datasheet" "~" (at 185.42 220.98 0) (effects (font (size 1.1 1.1)) (hide yes)))
  (pin "5")
  (pin "4")
  (pin "6"))
 (symbol
  (lib_id "Levi:50209LX_Harness")
  (at 302.26 220.98 0)
  (unit 3)
  (exclude_from_sim no)
  (in_bom yes)
  (on_board no)
  (dnp no)
  (property "Reference" "SW101" (at 302.26 210.94 0) (effects (font (size 1.1 1.1))))
  (property "Value" "50209LX" (at 302.26 213.14 0) (effects (font (size 1 1))))
  (property "Footprint" "" (at 302.26 220.98 0) (effects (font (size 1.1 1.1)) (hide yes)))
  (property "Datasheet" "~" (at 302.26 220.98 0) (effects (font (size 1.1 1.1)) (hide yes)))
  (pin "8")
  (pin "7")
  (pin "9"))
 (embedded_fonts no))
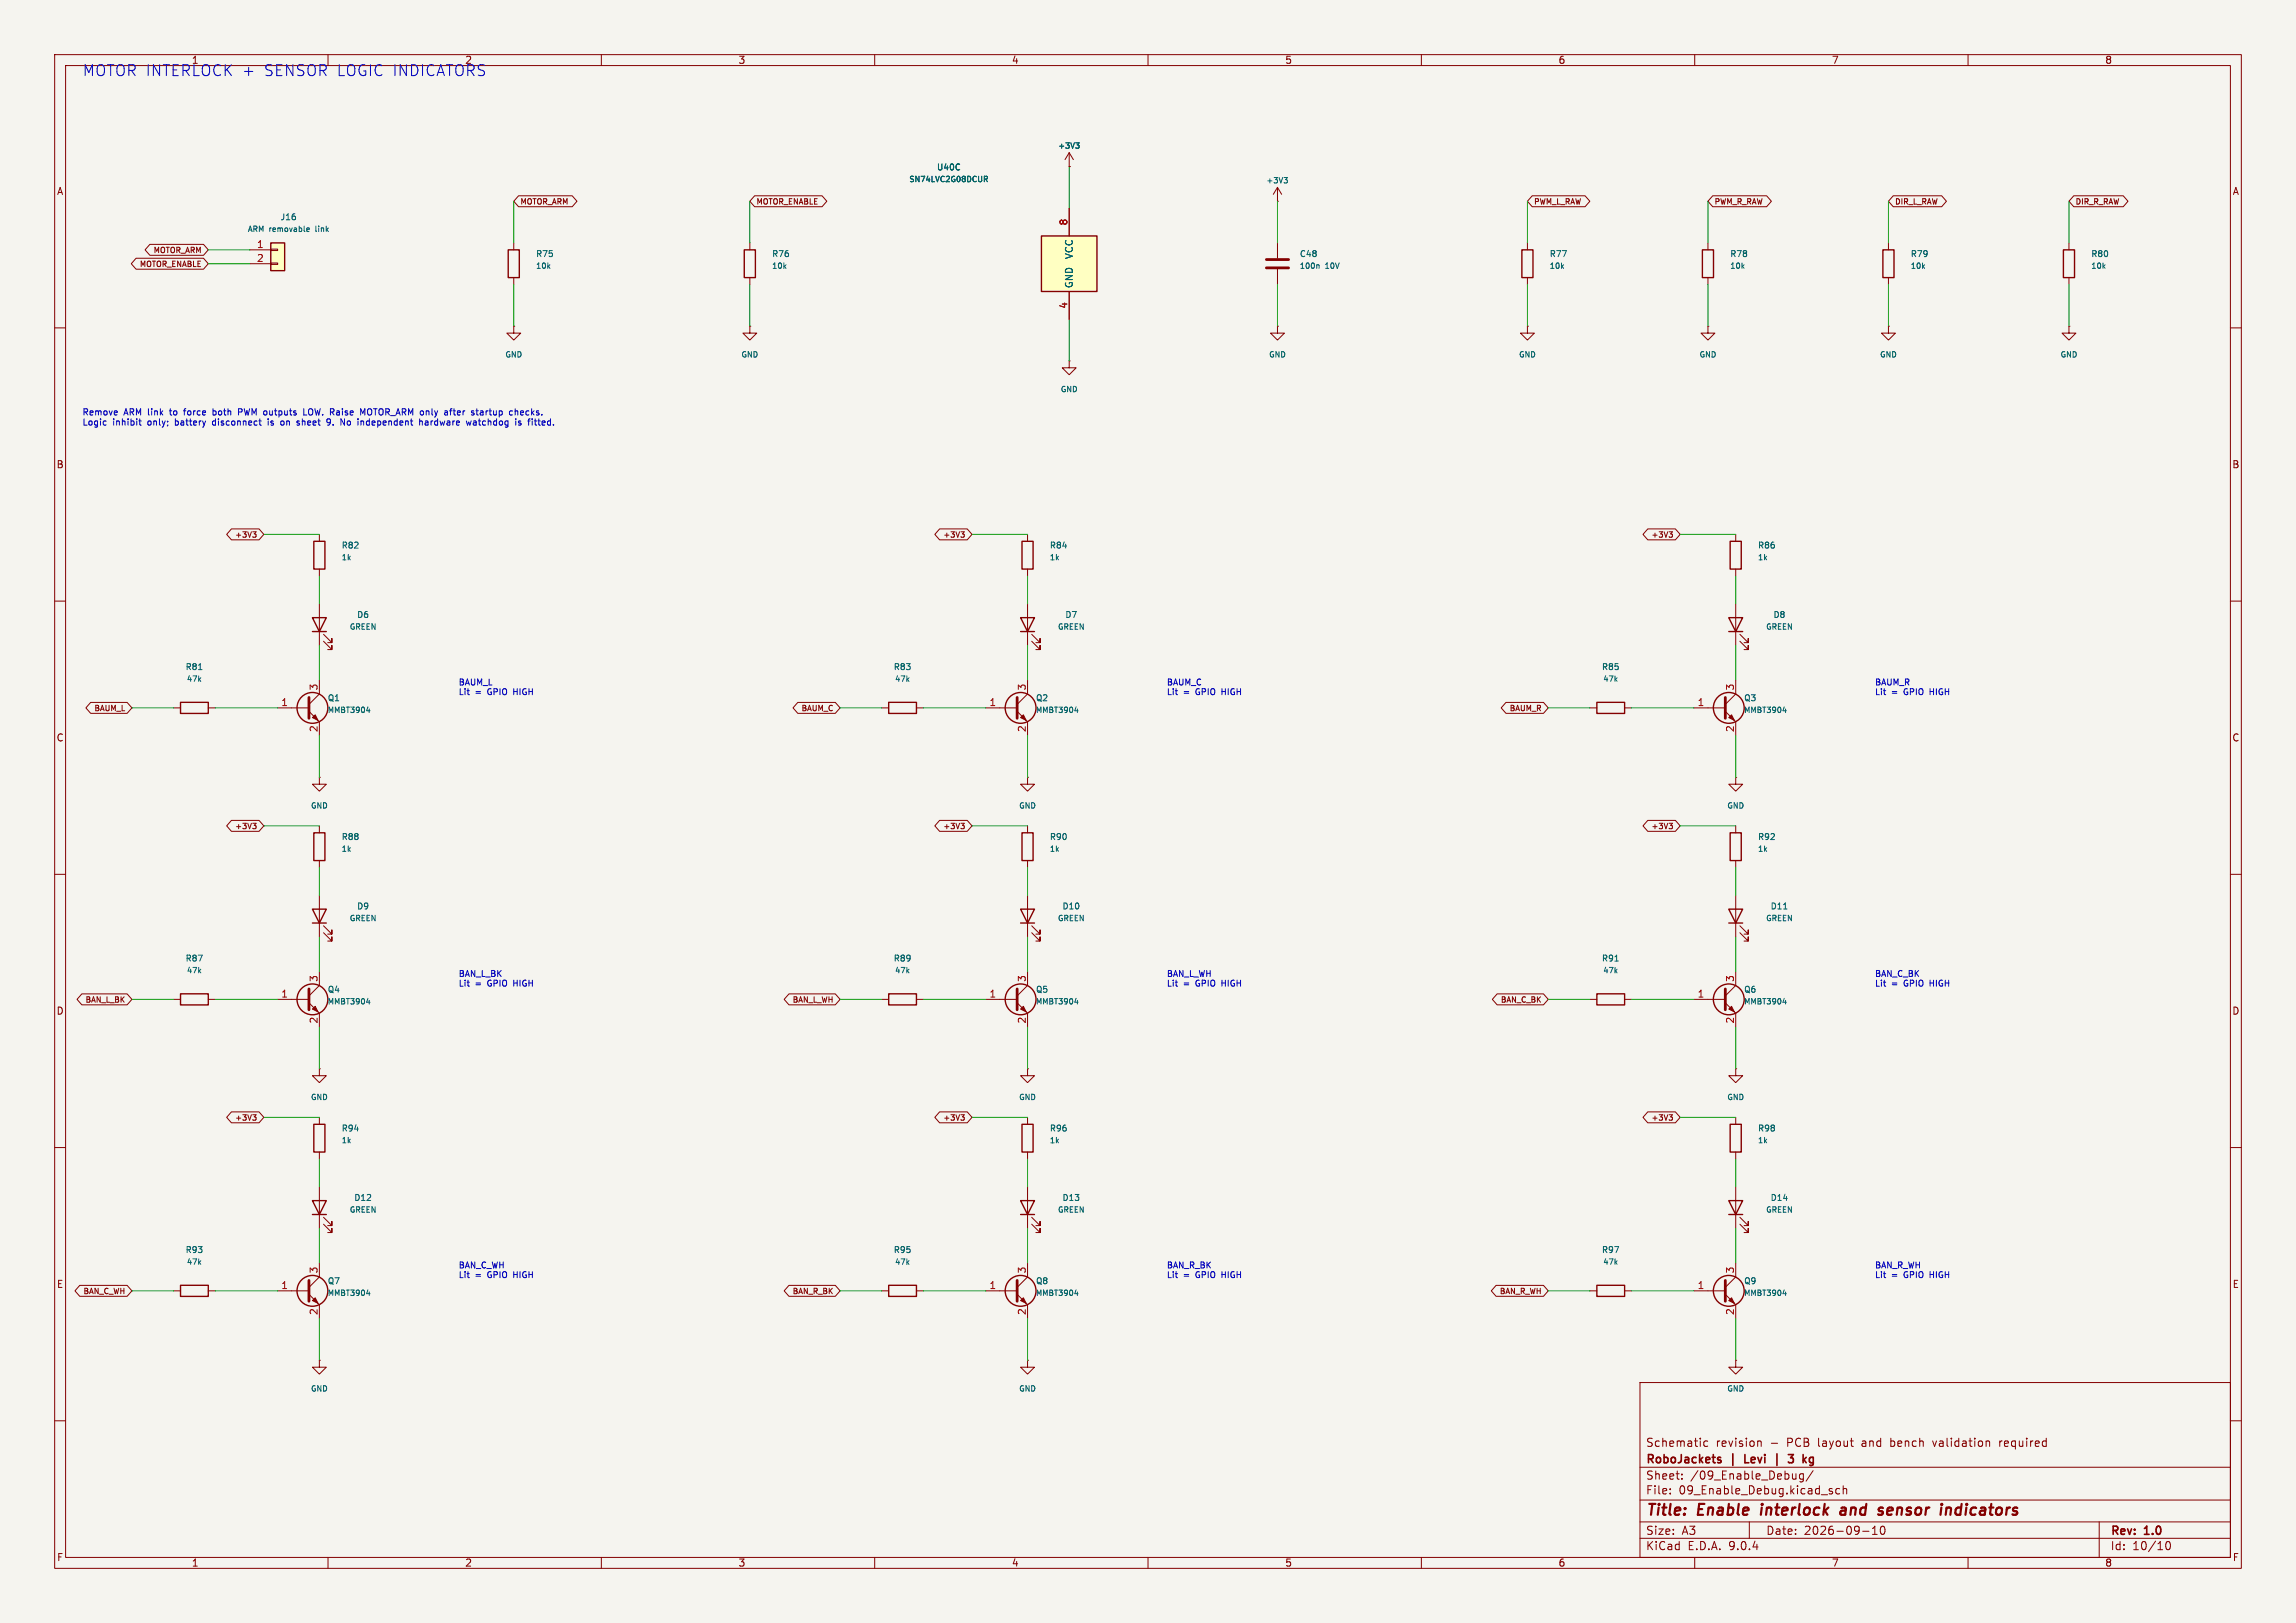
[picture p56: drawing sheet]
<svg xmlns="http://www.w3.org/2000/svg" width="420mm" height="297mm" viewBox="0 0 420 297" stroke-linecap="round" stroke-linejoin="round" font-family="sans-serif">
<defs><g id="words">
<text font-size="2.7" fill="#0000c2" x="15" y="13.8">MOTOR INTERLOCK + SENSOR LOGIC INDICATORS</text>
<text font-size="2.7" fill="#840000" x="301" y="277.3">Title: Enable interlock and sensor indicators</text>
<g font-size="2" fill="#840000">
<text x="301" y="267.8">RoboJackets | Levi | 3 kg</text>
<text x="301" y="264.8">Schematic revision - PCB layout and bench validation required</text>
<text x="301" y="273.5">File: 09_Enable_Debug.kicad_sch</text>
<text x="301" y="270.8">Sheet: /09_Enable_Debug/</text>
<text x="301" y="280.9">Size: A3</text>
<text x="323" y="280.9">Date: 2026-09-10</text>
<text x="386" y="280.9">Rev: 1.0</text>
<text x="301" y="283.7">KiCad E.D.A. 9.0.4</text>
<text x="386" y="283.7">Id: 10/10</text>
</g>
<g font-size="1.7" fill="#840000">
<text x="35" y="11.6">1</text>
<text x="135" y="11.6">3</text>
<text x="185" y="11.6">4</text>
<text x="235" y="11.6">5</text>
<text x="285" y="11.6">6</text>
<text x="335" y="11.6">7</text>
<text x="385" y="11.6">8</text>
<text x="10.4" y="35.6">A</text>
<text x="408.4" y="35.6">A</text>
<text x="10.4" y="85.7">B</text>
<text x="408.4" y="85.7">B</text>
<text x="10.4" y="135.6">C</text>
<text x="408.4" y="135.6">C</text>
<text x="10.4" y="185.6">D</text>
<text x="408.4" y="185.6">D</text>
<text x="10.5" y="235.6">E</text>
<text x="408.5" y="235.6">E</text>
<text x="10.5" y="285.6">F</text>
<text x="35" y="286.7">1</text>
<text x="85" y="286.7">2</text>
<text x="135" y="286.7">3</text>
<text x="185" y="286.7">4</text>
<text x="235" y="286.7">5</text>
<text x="285" y="286.7">6</text>
<text x="335" y="286.7">7</text>
<text x="385" y="286.7">8</text>
<text x="408.5" y="285.6">F</text>
</g>
<text font-size="1.7" fill="#0000c2" x="85" y="11.6">2</text>
<g font-size="1.7" fill="#a90000">
<text x="195.3" y="41.1" transform="rotate(-90 195.3 41.1)">8</text>
<text x="47.2" y="45.5">1</text>
<text x="47.2" y="48">2</text>
<text x="195.3" y="56.3" transform="rotate(-90 195.3 56.3)">4</text>
<text x="51.6" y="129.3">1</text>
<text x="58.2" y="126.2" transform="rotate(-90 58.2 126.2)">3</text>
<text x="181.2" y="129.3">1</text>
<text x="187.7" y="126.2" transform="rotate(-90 187.7 126.2)">3</text>
<text x="310.7" y="129.3">1</text>
<text x="317.2" y="126.2" transform="rotate(-90 317.2 126.2)">3</text>
<text x="58.2" y="133.8" transform="rotate(-90 58.2 133.8)">2</text>
<text x="187.7" y="133.8" transform="rotate(-90 187.7 133.8)">2</text>
<text x="317.2" y="133.8" transform="rotate(-90 317.2 133.8)">2</text>
<text x="58.2" y="179.5" transform="rotate(-90 58.2 179.5)">3</text>
<text x="187.7" y="179.5" transform="rotate(-90 187.7 179.5)">3</text>
<text x="317.2" y="179.5" transform="rotate(-90 317.2 179.5)">3</text>
<text x="51.6" y="182.6">1</text>
<text x="181.2" y="182.6">1</text>
<text x="310.7" y="182.6">1</text>
<text x="58.2" y="187.1" transform="rotate(-90 58.2 187.1)">2</text>
<text x="187.7" y="187.1" transform="rotate(-90 187.7 187.1)">2</text>
<text x="317.2" y="187.1" transform="rotate(-90 317.2 187.1)">2</text>
<text x="58.2" y="232.8" transform="rotate(-90 58.2 232.8)">3</text>
<text x="187.7" y="232.8" transform="rotate(-90 187.7 232.8)">3</text>
<text x="317.2" y="232.8" transform="rotate(-90 317.2 232.8)">3</text>
<text x="51.6" y="236">1</text>
<text x="181.2" y="236">1</text>
<text x="310.7" y="236">1</text>
<text x="58.2" y="240.5" transform="rotate(-90 58.2 240.5)">2</text>
<text x="187.7" y="240.5" transform="rotate(-90 187.7 240.5)">2</text>
<text x="317.2" y="240.5" transform="rotate(-90 317.2 240.5)">2</text>
</g>
<g font-size="1.7" fill="#006464">
<text x="196.2" y="47.2" transform="rotate(-90 196.2 47.2)">VCC</text>
<text x="196.2" y="52.8" transform="rotate(-90 196.2 52.8)">GND</text>
</g>
<g font-size="1.5" fill="#006464">
<text x="171.8" y="31.2">U40C</text>
<text x="51.8" y="40.3">J16</text>
<text x="98.5" y="47">R75</text>
<text x="141.6" y="47">R76</text>
<text x="238.2" y="47">C48</text>
<text x="283.9" y="47">R77</text>
<text x="316.9" y="47">R78</text>
<text x="349.9" y="47">R79</text>
<text x="382.9" y="47">R80</text>
<text x="62.9" y="100.4">R82</text>
<text x="192.4" y="100.4">R84</text>
<text x="322" y="100.4">R86</text>
<text x="65.5" y="113">D6</text>
<text x="195.1" y="113">D7</text>
<text x="324.6" y="113">D8</text>
<text x="34.3" y="122.6">R81</text>
<text x="163.9" y="122.6">R83</text>
<text x="293.4" y="122.6">R85</text>
<text x="60.2" y="128.3">Q1</text>
<text x="189.7" y="128.3">Q2</text>
<text x="319.3" y="128.3">Q3</text>
<text x="62.9" y="153.7">R88</text>
<text x="192.4" y="153.7">R90</text>
<text x="322" y="153.7">R92</text>
<text x="65.5" y="166.4">D9</text>
<text x="194.7" y="166.4">D10</text>
<text x="324.2" y="166.4">D11</text>
<text x="34.3" y="175.9">R87</text>
<text x="163.9" y="175.9">R89</text>
<text x="293.4" y="175.9">R91</text>
<text x="60.2" y="181.6">Q4</text>
<text x="189.7" y="181.6">Q5</text>
<text x="319.3" y="181.6">Q6</text>
<text x="62.9" y="207">R94</text>
<text x="192.4" y="207">R96</text>
<text x="322" y="207">R98</text>
<text x="65.2" y="219.7">D12</text>
<text x="194.7" y="219.7">D13</text>
<text x="324.2" y="219.7">D14</text>
<text x="34.3" y="229.3">R93</text>
<text x="163.9" y="229.3">R95</text>
<text x="293.4" y="229.3">R97</text>
<text x="60.2" y="235">Q7</text>
<text x="189.7" y="235">Q8</text>
<text x="319.3" y="235">Q9</text>
</g>
<g font-size="1.5" fill="#0000c2">
<text x="15" y="75.9">Remove ARM link to force both PWM outputs LOW. Raise MOTOR_ARM only after startup checks.</text>
<text x="15" y="77.8">Logic inhibit only; battery disconnect is on sheet 9. No independent hardware watchdog is fitted.</text>
<text x="83.8" y="125.3">BAUM_L</text>
<text x="213.4" y="125.3">BAUM_C</text>
<text x="342.9" y="125.3">BAUM_R</text>
<text x="83.8" y="127.1">Lit = GPIO HIGH</text>
<text x="213.4" y="127.1">Lit = GPIO HIGH</text>
<text x="342.9" y="127.1">Lit = GPIO HIGH</text>
<text x="83.8" y="178.7">BAN_L_BK</text>
<text x="213.4" y="178.7">BAN_L_WH</text>
<text x="342.9" y="178.7">BAN_C_BK</text>
<text x="83.8" y="180.4">Lit = GPIO HIGH</text>
<text x="213.4" y="180.4">Lit = GPIO HIGH</text>
<text x="342.9" y="180.4">Lit = GPIO HIGH</text>
<text x="83.8" y="232">BAN_C_WH</text>
<text x="83.8" y="233.8">Lit = GPIO HIGH</text>
<text x="213.4" y="232">BAN_R_BK</text>
<text x="213.4" y="233.8">Lit = GPIO HIGH</text>
<text x="342.9" y="232">BAN_R_WH</text>
<text x="342.9" y="233.8">Lit = GPIO HIGH</text>
</g>
<g font-size="1.3" fill="#006464">
<text x="194.1" y="27.2">+3V3</text>
<text x="167.4" y="33.3">SN74LVC2G08DCUR</text>
<text x="232.2" y="33.5">+3V3</text>
<text x="47.1" y="42.4">ARM removable link</text>
<text x="98.4" y="49.2">10k</text>
<text x="141.6" y="49.2">10k</text>
<text x="238.8" y="49.2">100n 10V</text>
<text x="283.8" y="49.2">10k</text>
<text x="316.9" y="49.2">10k</text>
<text x="349.9" y="49.2">10k</text>
<text x="382.9" y="49.2">10k</text>
<text x="92.5" y="65.4">GND</text>
<text x="135.7" y="65.4">GND</text>
<text x="232.2" y="65.4">GND</text>
<text x="278" y="65.4">GND</text>
<text x="311" y="65.4">GND</text>
<text x="344" y="65.4">GND</text>
<text x="377" y="65.4">GND</text>
<text x="194.1" y="71.7">GND</text>
<text x="62.7" y="102.5">1k</text>
<text x="192.3" y="102.5">1k</text>
<text x="321.8" y="102.5">1k</text>
<text x="64.2" y="115.2">GREEN</text>
<text x="193.7" y="115.2">GREEN</text>
<text x="323.3" y="115.2">GREEN</text>
<text x="34.6" y="124.7">47k</text>
<text x="164.1" y="124.7">47k</text>
<text x="293.6" y="124.7">47k</text>
<text x="60.5" y="130.4">MMBT3904</text>
<text x="190.1" y="130.4">MMBT3904</text>
<text x="319.6" y="130.4">MMBT3904</text>
<text x="57" y="147.9">GND</text>
<text x="186.5" y="147.9">GND</text>
<text x="316.1" y="147.9">GND</text>
<text x="62.7" y="155.8">1k</text>
<text x="192.3" y="155.8">1k</text>
<text x="321.8" y="155.8">1k</text>
<text x="64.2" y="168.5">GREEN</text>
<text x="193.7" y="168.5">GREEN</text>
<text x="323.3" y="168.5">GREEN</text>
<text x="34.6" y="178.1">47k</text>
<text x="164.1" y="178.1">47k</text>
<text x="293.6" y="178.1">47k</text>
<text x="60.5" y="183.8">MMBT3904</text>
<text x="190.1" y="183.8">MMBT3904</text>
<text x="319.6" y="183.8">MMBT3904</text>
<text x="57" y="201.3">GND</text>
<text x="186.5" y="201.3">GND</text>
<text x="316.1" y="201.3">GND</text>
<text x="62.7" y="209.2">1k</text>
<text x="192.3" y="209.2">1k</text>
<text x="321.8" y="209.2">1k</text>
<text x="64.2" y="221.9">GREEN</text>
<text x="193.7" y="221.9">GREEN</text>
<text x="323.3" y="221.9">GREEN</text>
<text x="34.6" y="231.4">47k</text>
<text x="164.1" y="231.4">47k</text>
<text x="293.6" y="231.4">47k</text>
<text x="60.5" y="237.1">MMBT3904</text>
<text x="190.1" y="237.1">MMBT3904</text>
<text x="319.6" y="237.1">MMBT3904</text>
<text x="57" y="254.6">GND</text>
<text x="186.5" y="254.6">GND</text>
<text x="316.1" y="254.6">GND</text>
</g>
<g font-size="1.3" fill="#840000">
<text x="95.1" y="37.4">MOTOR_ARM</text>
<text x="138.3" y="37.4">MOTOR_ENABLE</text>
<text x="280.5" y="37.4">PWM_L_RAW</text>
<text x="313.5" y="37.4">PWM_R_RAW</text>
<text x="346.6" y="37.4">DIR_L_RAW</text>
<text x="379.6" y="37.4">DIR_R_RAW</text>
<text x="28.5" y="46.3">MOTOR_ARM</text>
<text x="26.2" y="48.8">MOTOR_ENABLE</text>
<text x="44.1" y="98.4">+3V3</text>
<text x="173.6" y="98.4">+3V3</text>
<text x="303.2" y="98.4">+3V3</text>
<text x="17.5" y="130.1">BAUM_L</text>
<text x="147" y="130.1">BAUM_C</text>
<text x="276.5" y="130.1">BAUM_R</text>
<text x="44.1" y="151.7">+3V3</text>
<text x="173.6" y="151.7">+3V3</text>
<text x="303.2" y="151.7">+3V3</text>
<text x="16.2" y="183.5">BAN_L_BK</text>
<text x="145.4" y="183.5">BAN_L_WH</text>
<text x="275.2" y="183.5">BAN_C_BK</text>
<text x="44.1" y="205">+3V3</text>
<text x="173.6" y="205">+3V3</text>
<text x="303.2" y="205">+3V3</text>
<text x="15.7" y="236.8">BAN_C_WH</text>
<text x="145.7" y="236.8">BAN_R_BK</text>
<text x="274.8" y="236.8">BAN_R_WH</text>
</g>
</g></defs>
<path d="M0 0h420v297h-420z" fill="#f5f4ef"/>
<path d="M0 0h420v297h-420z" fill="none" stroke="#f5f4ef" stroke-width=".18"/>
<g fill="none" stroke="#840000" stroke-width=".18">
<path d="M10 10h400v277h-400zM12 12h396v273h-396zM60 10v2M110 10v2M160 10v2M210 10v2M260 10v2M310 10v2M360 10v2M10 60h2M408 60h2M10 110h2"/>
<path d="M408 110h2M10 160h2M408 160h2M10 210h2M408 210h2M10 260h2M300 253h108v32h-108zM408 260h2M300 278.5h108M300 274.5h108M300 268.5h108M308.2 279.3l.5 1.5"/>
<path d="M309.1 279.3h.9l-.5 .6 .4 .1v.6l-.2 .2h-.4l-.2-.2M320 278.5v3M322.2 270.8h1.2M323.7 269.2a.76 .76 0 0 1 .9 .7 .76 .76 0 0 1-.9 .8zM325.2 270.2l.7-.2-.1-.2-.4-.1-.2 .2v.7h.6M326.5 269.8l.4-.1 .3 .3v.4l-.1 .2h-.6M326.5 269.2v1.5M327.9 269.7v.9l.4 .1 .2-.2M328.5 269.7v1M329.9 269.7v1.2l-.3 .3-.4-.1M329.9 269.8l-.5-.1-.2 .3v.4l.1 .2h.6M330.2 272.5l-.5-.1-.3 .3v.4l.2 .2h.6"/>
<path d="M330.8 272.5h.6v.9M331.4 272.7l-.5 .1a.29 .29 0 0 0-.2 .3 .29 .29 0 0 0 .2 .3l.5-.1M331.7 269.1l-1.3 1.9M332.8 272.5l-.4-.1-.3 .3v.4l.1 .2h.6M332.8 271.9v1.5M333.2 273.5h1.1M335.2 272.5l-.4-.1-.2 .2 .1 .2 .5 .2v.3h-.6M336.5 272.5l-.4-.1-.3 .3v.4l.1 .2h.6M337.2 272.5l.2-.1 .3 .1 .1 .9M337.2 271.9v1.5M337.8 279.9l.1-.5 .3-.1a.8 .8 0 0 1 .5 .7 .8 .8 0 0 1-.5 .8l-.3-.2-.1-.4M340.1 279.9l-.3 .3h-.3l-.3-.3 .2-.5 .4-.1 .2 .1a.99 .99 0 0 1-.3 1.4h-.3"/>
<path d="M342.5 279.7l.4-.4v1.5M344.1 279.4l.2-.1a.8 .8 0 0 1 .5 .7 .8 .8 0 0 1-.5 .8l-.2-.2-.2-.4zM353.5 263.7l.4 1 .3-1M354.8 263.8h.6v.9M355.4 264l-.5 .1a.29 .29 0 0 0-.2 .3 .29 .29 0 0 0 .2 .3l.5-.1M356.2 263.2v1.3l.2 .2M356.9 263.2v.1M356.9 263.7v1M358.3 263.8l-.4-.1-.3 .3v.4l.1 .2h.6M358.3 263.2v1.5M359 263.8h.6l.1 .9M359.7 264l-.5 .1a.29 .29 0 0 0-.3 .3 .29 .29 0 0 0 .3 .3l.5-.1"/>
<path d="M360.2 263.7h.5M360.4 263.2v1.3l.3 .2M361.2 263.2v.1M361.2 263.7v1M361.9 263.8l.3-.1 .4 .1 .1 .6-.2 .2-.3 .1-.3-.2zM363.3 263.8l.2-.1 .4 .1v.9M363.3 263.7v1M365.8 263.7v1M366.2 263.7l-.3 .1-.1 .2M366.7 264.2l.7-.2-.1-.2-.4-.1-.2 .2v.7h.6M368.7 263.8l-.5-.1-.3 .3v.4l.2 .2h.6M368.7 263.7v1.5"/>
<path d="M369.4 263.7v.9l.4 .1 .2-.2M370 263.7v1M370.7 263.2v.1M370.7 263.7v1M371.4 263.7v1M371.9 263.7l-.3 .1-.2 .2M372.3 264.2l.7-.2-.1-.2-.4-.1-.2 .2 .1 .7h.5M374.3 263.8l-.4-.1-.3 .3v.4l.1 .2h.6M374.3 263.2v1.5M384 278.5v6.5M60 285v2M110 285v2"/>
<path d="M160 285v2M210 285v2M260 285v2M300 281.5h108M307.9 280.4h.7M310 285v2M317.9 283.4v.2M318.7 282.2l.2-.1a.8 .8 0 0 1 .5 .7 .8 .8 0 0 1-.5 .8l-.2-.2-.2-.4zM320 283.4v.2M321 282l-.3 1.1h.9M321.4 282.6v1M340.7 280.2h1.2"/>
<path d="M342.5 280.8h.9M360 285v2M394.3 282l-1.3 1.9M394.7 283.6h.9M394.7 282.5l.5-.4v1.5M396.3 282.2l.2-.1a.8 .8 0 0 1 .5 .7 .8 .8 0 0 1-.5 .8l-.2-.2-.1-.4z"/>
</g>
<path d="M321.5 266.7l.4 1 .4-1M322.8 266.2v.1M322.8 266.7v1M325 266v2.2M327.1 266.2h.9l-.5 .6 .5 .1v.6l-.2 .2h-.5l-.2-.2M329.8 266.2v1.5M330 267.1l.4 .6M330.4 266.7l-.6 .6M331.7 266.8l-.4-.1-.3 .3v.4l.1 .2h.6M331.7 266.7v1.2l-.3 .3-.4-.1M394.5 279.4l.3-.1a.8 .8 0 0 1 .5 .7 .8 .8 0 0 1-.5 .8l-.3-.2-.1-.4zM393.8 280.6v.2" fill="none" stroke="#840000" stroke-width=".3"/>
<g fill="none" stroke="#840000" stroke-width=".4">
<path d="M348.9 276.4l.4 .1 .3 .3-.2 .3-.5 .1M348.9 276l.2-.1 .5 .1M350.5 276.1a.52 .52 0 0 1 .6-.2 .52 .52 0 0 1 .4 .4l-.1 .5a.55 .55 0 0 1-.5 .4 .55 .55 0 0 1-.6-.4zM352.4 275.9l-.2 1.3M352.9 275.9l-.4 .1-.2 .3M355.1 275.9l-.1 1.3M355.2 275.2v.2M355.2 275.2l-.1 .1 .1 .1M355.2 275.2l.1 .1-.1 .1M356 276.1a.49 .49 0 0 1 .9 .1l-.1 1M356.1 275.9l-.2 1.3M358.7 276a.66 .66 0 0 0-1 .3v.5l.1 .3 .2 .1 .6-.1"/>
<path d="M358.8 275.2l-.2 2M359.7 275.9l-.2 1.3M359.8 275.2v.2M359.8 275.2l-.1 .1 .1 .1M359.8 275.2l.1 .1-.1 .1M361.5 276a.66 .66 0 0 0-1 .3l-.1 .5 .2 .3 .2 .1 .5-.1M362.3 276l.2-.1 .6 .1-.1 1.2M363.2 276.3l-.7 .1a.4 .4 0 0 0-.4 .4 .4 .4 0 0 0 .3 .4l.7-.1M363.9 275.9h.7M364.3 275.2l-.3 1.7 .1 .2 .4 .1M365.3 276.1a.52 .52 0 0 1 .5-.2 .52 .52 0 0 1 .4 .4l-.1 .5a.55 .55 0 0 1-.5 .4 .55 .55 0 0 1-.5-.4zM367.1 275.9l-.1 1.3"/>
<path d="M367.7 275.9l-.4 .1-.2 .3M369 276a.49 .49 0 0 0-.8 .3l.1 .1 .6 .2 .1 .3-.3 .3-.6-.1"/>
</g>
<path d="M49.5 44.4h2.6v5.1h-2.6z" fill="#ffffc2"/>
<g fill="none" stroke="#840000" stroke-width=".25">
<path d="M49.5 44.4h2.6v5.1h-2.6zM93 45.7h2v5.1h-2zM344.4 45.7h2.1v5.1h-2.1zM377.4 45.7h2.1v5.1h-2.1zM316.2 113h2.6l-1.3 2.6zM316.2 115.6h2.6M33 181.9h5.1v2h-5.1zM316.5 205.7h2v5.1h-2z"/>
<circle cx="57.2" cy="236.2" r="2.82"/>
</g>
<g fill="none" stroke="#840000" stroke-width=".18">
<path d="M45.7 45.7h3.8M45.7 48.3h3.8M49.5 45.6h1.3v.2h-1.3zM49.5 48.1h1.3v.3h-1.3zM94 44.4v1.3M94 50.8v1.3M345.4 59.7v1.3h1.3l-1.3 1.2-1.2-1.2h1.2M345.4 59.7h.1M345.4 44.4v1.3M345.4 50.8v1.3M378.5 59.7v1.3h1.2l-1.2 1.2-1.3-1.2h1.3M378.5 59.7h.1"/>
<path d="M378.5 44.4v1.3M378.5 50.8v1.3M317.5 110.5v7.6M318.3 117.3l1.5 1.6v-.8v.8h-.8M318.3 116.1l1.5 1.5v-.8v.8h-.8M31.7 182.9h1.3M38.1 182.9h1.3M317.5 204.5v1.2M317.5 210.8v1.3M53.3 236.2h3.2M56.5 236.9l1.9 1.9M58.4 233.7l-1.9 1.9"/>
</g>
<path d="M45.4 42.4l.4-1 .3 1M45.5 42.1h.5M46.4 41.9h.4M46.8 41.4h-.4v1M58.9 41.7l.3 .2v.5M59.7 41.4v1M59.8 42l.3 .4M60.1 41.7l-.4 .4" fill="none" stroke="#006464" stroke-width=".18"/>
<path d="M56.5 234.3v3.8" fill="none" stroke="#840000" stroke-width=".51"/>
<path d="M57.1 238l.6-.5 .5 1z" fill="#840000"/>
<g fill="none" stroke="#840000" stroke-width=".18">
<path d="M279.4 59.7v1.3h1.3l-1.3 1.2-1.3-1.2h1.3M279.4 59.7h.1M279.4 44.5v1.2M279.4 50.8v1.3M312.4 59.7v1.3h1.3l-1.3 1.2-1.3-1.2h1.3M312.4 59.7h.1M312.4 44.5v1.2M312.4 50.8v1.3M58.4 151.1v1.3M58.4 157.5v1.3M317.5 151.1v1.3M317.5 157.5v1.3"/>
<path d="M58.4 163.8v7.7M59.2 170.7l1.5 1.5v-.7v.7h-.8M59.2 169.4l1.5 1.5v-.7v.7h-.8M317.5 217.2v7.6M31.7 236.2h1.3M38.1 236.2h1.3M50.8 236.2h2.5M57.1 238l.6-.5 .5 1zM58.4 231.1v2.6M58.4 238.8v2.5M182.9 236.2h3.2M186.1 236.9l1.9 1.9"/>
<path d="M188 233.7l-1.9 1.9M318.3 224l1.5 1.6v-.8v.8h-.8M318.3 222.8l1.5 1.5v-.8v.8h-.8M188 248.9v1.3h1.2l-1.2 1.3-1.3-1.3h1.3M188 248.9h.1"/>
</g>
<g fill="none" stroke="#840000" stroke-width=".25">
<path d="M278.4 45.7h2v5.1h-2zM311.4 45.7h2v5.1h-2zM57.4 152.4h2v5.1h-2zM316.5 152.4h2v5.1h-2zM57.1 166.4h2.6l-1.3 2.5zM57.1 168.9h2.6M316.2 219.7h2.6l-1.3 2.6zM33 235.2h5.1v2h-5.1zM316.2 222.3h2.6"/>
<circle cx="186.7" cy="236.2" r="2.82"/>
</g>
<path d="M186.1 234.3v3.8" fill="none" stroke="#840000" stroke-width=".51"/>
<path d="M186.7 238l.5-.5 .5 1z" fill="#840000"/>
<path d="M312.4 129.5h3.2M315.6 130.2l1.9 1.9M317.5 127l-1.9 1.9M180.3 236.2h2.6M186.7 238l.5-.5 .5 1zM188 231.1v2.6M188 238.8v2.5" fill="none" stroke="#840000" stroke-width=".18"/>
<path d="M315.6 127.6v3.8" fill="none" stroke="#840000" stroke-width=".51"/>
<circle cx="316.2" cy="129.5" r="2.82" fill="none" stroke="#840000" stroke-width=".25"/>
<path d="M316.2 131.3l.5-.5 .5 1z" fill="#840000"/>
<g fill="none" stroke="#840000" stroke-width=".18">
<path d="M233.7 36.8h.1M233.7 34.3v2.5M233.7 34.3l-.8 1.3M233.7 34.3l.7 1.3M233.7 59.7v1.3h1.3l-1.3 1.2-1.3-1.2h1.3M233.7 59.7h.1M233.7 44.5v2.7M233.7 49.3v2.8M188 97.8v1.3M188 104.1v1.3M188 110.5v7.6M188.7 117.3l1.5 1.6v-.8v.8h-.7"/>
<path d="M188.7 116.1l1.5 1.5v-.8v.8h-.7M161.3 129.5h1.3M167.6 129.5h1.3M309.9 129.5h2.5M316.2 131.3l.5-.5 .5 1zM317.5 124.5v2.5M317.5 132.1v2.5M317.5 142.2v1.3h1.3l-1.3 1.3-1.3-1.3h1.3M317.5 142.2h.1M188 163.8v7.7M188.7 170.7l1.5 1.5v-.7v.7h-.7M188.7 169.4l1.5 1.5v-.7v.7h-.7"/>
<path d="M182.9 182.9h3.2M186.1 183.5l1.9 1.9M188 195.6v1.3h1.2l-1.2 1.2-1.3-1.2h1.3M188 195.6h.1M188 180.3l-1.9 1.9M161.3 236.2h1.3M167.6 236.2h1.3"/>
</g>
<path d="M231.6 47.5h4.1M231.6 49h4.1M186.1 181v3.8" fill="none" stroke="#840000" stroke-width=".51"/>
<path d="M238 49.1h.5M238 48.4l.2-.3v1M244.3 48.1l.3 1 .4-1" fill="none" stroke="#006464" stroke-width=".18"/>
<g fill="none" stroke="#840000" stroke-width=".25">
<path d="M186.9 99.1h2.1v5h-2.1zM186.7 113h2.5l-1.2 2.6zM186.7 115.6h2.5M162.6 128.5h5v2.1h-5zM186.7 166.4h2.5l-1.2 2.5zM186.7 168.9h2.5M162.6 235.2h5v2h-5z"/>
<circle cx="186.7" cy="182.9" r="2.82"/>
</g>
<path d="M187.2 184.2l.5 1-1-.5z" fill="#840000"/>
<g fill="none" stroke="#840000" stroke-width=".18">
<path d="M182.9 129.5h3.2M186.1 130.2l1.9 1.9M188 127l-1.9 1.9M188 142.2v1.3h1.2l-1.2 1.3-1.3-1.3h1.3M188 142.2h.1M188 151.1v1.3M188 157.5v1.3M188 177.8v2.5M58.4 195.6v1.3h1.3l-1.3 1.2-1.2-1.2h1.2M58.4 195.6h.1M180.3 182.9h2.6M187.2 184.2l.5 1-1-.5z"/>
<path d="M188 185.4v2.6M58.4 204.5v1.2M58.4 210.8v1.3M188 204.5v1.2M188 210.8v1.3M188 217.2v7.6M188.7 224l1.5 1.6v-.8v.8h-.7M188.7 222.8l1.5 1.5v-.8v.8h-.7"/>
</g>
<g fill="none" stroke="#840000" stroke-width=".25">
<path d="M186.9 152.4h2.1v5.1h-2.1zM57.4 205.7h2v5.1h-2zM186.7 219.7h2.5l-1.2 2.6zM186.9 205.7h2.1v5.1h-2.1zM186.7 222.3h2.5"/>
<circle cx="186.7" cy="129.5" r="2.82"/>
</g>
<path d="M186.1 127.6v3.8" fill="none" stroke="#840000" stroke-width=".51"/>
<path d="M186.7 131.3l.5-.5 .5 1z" fill="#840000"/>
<g fill="none" stroke="#840000" stroke-width=".18">
<path d="M58.4 110.5v7.6M59.2 117.3l1.5 1.6v-.8v.8h-.8M59.2 116.1l1.5 1.5v-.8v.8h-.8M31.8 129.5h1.2M38.1 129.5h1.3M53.3 129.5h3.2M56.5 130.2l1.9 1.9M58.4 127l-1.9 1.9M180.3 129.5h2.6M186.7 131.3l.5-.5 .5 1zM188 132.1v2.5M188 124.5v2.5"/>
<path d="M290.8 129.5h1.3M297.2 129.5h1.3M58.4 142.2v1.3h1.3l-1.3 1.3-1.2-1.3h1.2M58.4 142.2h.1M161.3 182.9h1.3M167.6 182.9h1.3M290.8 182.9h1.3M297.2 182.9h1.3"/>
</g>
<g fill="none" stroke="#840000" stroke-width=".25">
<path d="M57.2 113h2.5l-1.3 2.6zM57.2 115.6h2.5M33 128.5h5.1v2.1h-5.1zM292.1 128.5h5.1v2.1h-5.1zM162.6 181.9h5v2h-5zM292.1 181.9h5.1v2h-5.1z"/>
<circle cx="57.2" cy="129.5" r="2.82"/>
</g>
<path d="M56.5 127.6v3.8" fill="none" stroke="#840000" stroke-width=".51"/>
<path d="M57.2 131.3l.5-.5 .5 1z" fill="#840000"/>
<g fill="none" stroke="#840000" stroke-width=".18">
<path d="M58.4 97.8v1.3M58.4 104.1v1.3M50.8 129.5h2.5M57.2 131.3l.5-.5 .5 1zM58.4 132.1v2.5M58.4 124.5v2.5M58.4 217.2v7.6M59.2 224l1.5 1.6v-.8v.8h-.8M59.2 222.8l1.5 1.5v-.8v.8h-.8M312.4 236.2h3.2M315.6 236.9l1.9 1.9M317.5 233.7l-1.9 1.9"/>
<path d="M58.4 248.9v1.3h1.3l-1.3 1.3-1.2-1.3h1.2M58.4 248.9h.1M317.5 248.9v1.3h1.3l-1.3 1.3-1.3-1.3h1.3M317.5 248.9h.1"/>
</g>
<g fill="none" stroke="#840000" stroke-width=".25">
<path d="M57.4 99.1h2v5h-2zM57.2 219.7h2.5l-1.3 2.6zM57.2 222.3h2.5"/>
<circle cx="316.2" cy="236.2" r="2.82"/>
</g>
<path d="M315.6 234.3v3.8" fill="none" stroke="#840000" stroke-width=".51"/>
<path d="M316.2 238l.5-.5 .5 1z" fill="#840000"/>
<path d="M317.5 163.8v7.7M318.3 170.7l1.5 1.5v-.7v.7h-.8M318.3 169.4l1.5 1.5v-.7v.7h-.8M290.8 236.2h1.3M297.2 236.2h1.3M309.9 236.2h2.5M316.2 238l.5-.5 .5 1zM317.5 231.1v2.6M317.5 238.8v2.5" fill="none" stroke="#840000" stroke-width=".18"/>
<path d="M316.2 166.4h2.6l-1.3 2.5zM316.2 168.9h2.6M292.1 235.2h5.1v2h-5.1z" fill="none" stroke="#840000" stroke-width=".25"/>
<path d="M190.5 43.2h10.2v10.1h-10.2z" fill="#ffffc2"/>
<g fill="none" stroke="#840000" stroke-width=".25">
<path d="M190.5 43.2h10.2v10.1h-10.2z"/>
<circle cx="57.2" cy="182.9" r="2.82"/>
</g>
<path d="M195.6 38.1v5.1M195.6 30.5h.1M195.6 27.9v2.6M195.6 27.9l-.8 1.3M195.6 27.9l.7 1.3M195.6 53.3v5.1M195.6 66v1.3h1.3l-1.3 1.3-1.3-1.3h1.3M195.6 66h.1M53.3 182.9h3.2M56.5 183.5l1.9 1.9M58.4 180.3l-1.9 1.9" fill="none" stroke="#840000" stroke-width=".18"/>
<path d="M166.5 33.2h.5M167.1 32.3h-.4l-.2 .1 .1 .3 .4 .1M180.1 32.3h.3l.2 .1-.1 .3-.4 .1M180.3 32.8l.3 .5" fill="none" stroke="#006464" stroke-width=".18"/>
<path d="M56.5 181v3.8" fill="none" stroke="#840000" stroke-width=".51"/>
<path d="M57.7 184.2l.5 1-1-.5z" fill="#840000"/>
<path d="M58.4 177.8v2.5M50.8 182.9h2.5M57.7 184.2l.5 1-1-.5zM58.4 185.4v2.6M312.4 182.9h3.2M315.6 183.5l1.9 1.9M317.5 195.6v1.3h1.3l-1.3 1.2-1.3-1.2h1.3M317.5 195.6h.1M317.5 180.3l-1.9 1.9" fill="none" stroke="#840000" stroke-width=".18"/>
<path d="M315.6 181v3.8" fill="none" stroke="#840000" stroke-width=".51"/>
<circle cx="316.2" cy="182.9" r="2.82" fill="none" stroke="#840000" stroke-width=".25"/>
<path d="M316.7 184.2l.5 1-1-.5z" fill="#840000"/>
<g fill="none" stroke="#840000" stroke-width=".18">
<path d="M94.9 35.8h9.8l.8 1-.8 1h-9.8l-.9-1zM138 35.8h12.4l.8 1-.8 1h-12.4l-.8-1zM149 37.4h.5M149 36.4h.5M195.6 38.1v5.1M195.6 30.5h.1M280.3 35.8h9.6l.9 1-.9 1h-9.6l-.9-1zM313.3 35.8h9.9l.8 1-.8 1h-9.9l-.9-1zM346.3 35.8h8.9l.8 1-.8 1h-8.9l-.9-1zM379.3 35.8h9.1l.9 1-.9 1h-9.1l-.8-1zM24.9 47.3h12.3l.9 1-.9 1h-12.3l-.9-1zM27.4 44.7h9.8l.9 1-.9 1h-9.8l-.9-1z"/>
<path d="M94 59.7v1.3h1.3l-1.3 1.2-1.3-1.2h1.3M94 59.7h.1M137.2 59.7v1.3h1.2l-1.2 1.2-1.3-1.2h1.3M137.2 59.7h.1M137.2 44.5v1.2M137.2 50.8v1.3M195.6 53.3v5.1M42.3 96.8h5.1l.9 1-.9 1h-5.1l-.8-1zM43.3 97.9h.7M43.7 97.6v.7M171.9 96.8h5l.9 1-.9 1h-5l-.9-1zM172.8 97.9h.8"/>
<path d="M173.2 97.6v.7M301.4 96.8h5.1l.8 1-.8 1h-5.1l-.9-1zM302.4 97.9h.7M302.7 97.6v.7M317.5 97.8v1.3M317.5 104.1v1.3M16.6 128.5h6.7l.8 1-.8 1h-6.7l-.9-1zM145.9 128.5h6.9l.9 1-.9 1h-6.9l-.8-1zM275.5 128.5h6.8l.9 1-.9 1h-6.8l-.9-1zM42.3 150.1h5.1l.9 1-.9 1h-5.1l-.8-1zM43.3 151.3h.7M43.7 150.9v.8"/>
<path d="M171.9 150.1h5l.9 1-.9 1h-5l-.9-1zM172.8 151.3h.8M173.2 150.9v.8M301.4 150.1h5.1l.8 1-.8 1h-5.1l-.9-1zM302.4 151.3h.7M302.7 150.9v.8M317.5 177.8v2.5M15 181.9h8.3l.8 1-.8 1h-8.3l-.9-1zM144.3 181.9h8.5l.9 1-.9 1h-8.5l-.9-1zM273.9 181.9h8.4l.9 1-.9 1h-8.4l-.9-1zM309.9 182.9h2.5M316.7 184.2l.5 1-1-.5z"/>
<path d="M317.5 185.4v2.6M42.3 203.5h5.1l.9 1-.9 1h-5.1l-.8-1zM43.3 204.6h.7M43.7 204.2v.8M171.9 203.5h5l.9 1-.9 1h-5l-.9-1zM172.8 204.6h.8M173.2 204.2v.8M301.4 203.5h5.1l.8 1-.8 1h-5.1l-.9-1zM302.4 204.6h.7M302.7 204.2v.8M14.6 235.2h8.7l.8 1-.8 1h-8.7l-.9-1zM144.3 235.2h8.5l.9 1-.9 1h-8.5l-.9-1z"/>
<path d="M273.7 235.2h8.6l.9 1-.9 1h-8.6l-.9-1z"/>
</g>
<path d="M136.1 45.7h2.1v5.1h-2.1zM316.5 99.1h2v5h-2z" fill="none" stroke="#840000" stroke-width=".25"/>
<g fill="none" stroke="#009600" stroke-width=".18">
<path d="M94 36.8v7.7M137.2 36.8v7.7M195.6 30.5v7.6M233.7 36.8v7.7M279.4 36.8v7.7M312.4 36.8v7.7M345.4 36.8v7.7M378.5 36.8v7.7M38.1 45.7h7.6M38.1 48.3h7.6M94 52.1v7.6M137.2 52.1v7.6"/>
<path d="M195.6 58.4v7.6M233.7 52.1v7.6M279.4 52.1v7.6M312.4 52.1v7.6M345.4 52.1v7.6M378.5 52.1v7.6M48.3 97.8h10.1M177.8 97.8h10.2M307.3 97.8h10.2M58.4 105.4v5.1M58.4 118.1v6.4M188 105.4v5.1"/>
<path d="M188 118.1v6.4M317.5 105.4v5.1M317.5 118.1v6.4M24.1 129.5h7.7M39.4 129.5h11.4M58.4 134.6v7.6M153.7 129.5h7.6M168.9 129.5h11.4M188 134.6v7.6M283.2 129.5h7.6M298.5 129.5h11.4M317.5 134.6v7.6"/>
<path d="M48.3 151.1h10.1M58.4 158.8v5M177.8 151.1h10.2M188 158.8v5M307.3 151.1h10.2M317.5 158.8v5M58.4 171.5v6.3M188 171.5v6.3M317.5 171.5v6.3M24.1 182.9h7.7M39.4 182.9h11.4M58.4 188v7.6"/>
<path d="M153.7 182.9h7.6M168.9 182.9h11.4M188 188v7.6M283.2 182.9h7.6M298.5 182.9h11.4M317.5 188v7.6M48.3 204.5h10.1M58.4 212.1v5.1M177.8 204.5h10.2M188 212.1v5.1M307.3 204.5h10.2M317.5 212.1v5.1"/>
<path d="M24.1 236.2h7.7M39.4 236.2h11.4M58.4 224.8v6.3M153.7 236.2h7.6M168.9 236.2h11.4M188 224.8v6.3M283.2 236.2h7.6M298.5 236.2h11.4M317.5 224.8v6.3M58.4 241.3v7.6M188 241.3v7.6M317.5 241.3v7.6"/>
</g>
<g fill="none" stroke="#0000c2" stroke-width=".18">
<path d="M80 13.8l.6-2 .7 2M80.1 13.3h1M81.7 11.8h1.1M82.2 11.8v2M83.5 12.1a.67 .67 0 0 1 .7-.3 .67 .67 0 0 1 .5 .7v.7a.67 .67 0 0 1-.6 .7 .67 .67 0 0 1-.7-.7zM85.6 11.8v2M86.1 12.9l.6 .9M86.3 11.8a.54 .54 0 0 1 .4 .6 .54 .54 0 0 1-.4 .5h-.7M88.6 11.9l-.3-.1-.6 .1a.48 .48 0 0 0-.2 .5 .48 .48 0 0 0 .4 .4 .73 .73 0 0 1 .7 .5l-.1 .3-.3 .2-.7-.1M75.1 77h.4M75.2 76.6v1l.3 .2M76.8 77.1h.4l.1 .7"/>
<path d="M76.8 76.6v1.2M77.8 77.1h.4l.1 .7M78.3 77.3l-.4 .1-.2 .1 .2 .3 .4-.1M78.3 75.2l.2 .1v.6M78.8 77v.8M79 74.8v1l.2 .1M79.2 77l-.4 .3M79.5 75.2l.3 .7M79.8 75.9l-.3 .4M80 77.1l-.3-.1-.2 .3 .1 .4h.4M80 76.6v1.2M80 75.2l-.2 .7"/>
<path d="M80.5 77l.2 .8 .2-.5 .2 .5 .3-.8M81.4 75.2h.4l.1 .7M81.8 77.1h.4l.1 .7M81.9 75.5h-.4l-.2 .2 .2 .2h.4M82.2 75.2h.5M82.3 77.3l-.4 .1-.2 .1 .2 .3 .4-.1M82.7 74.8l-.3 .2v.9M82.8 77v.8M82.9 75.2h.4M83.1 74.8v1l.2 .1M83.2 77l-.4 .3M83.5 77.4l.5-.1v-.2l-.3-.1-.2 .2 .1 .5h.4"/>
<path d="M83.7 75.6l.5-.1v-.3h-.4l-.1 .1v.6h.5M84.7 75.2v.7M85 75.2l-.3 .2M85.3 77l.2 .8 .2-.5 .3 .5 .2-.8M86.6 77.1h.5v.7M86.7 75.2h-.3l-.2 .1 .1 .2 .4 .1v.3h-.5M87.1 75.2h.4M87.1 77.3l-.4 .1-.1 .1 .1 .3 .4-.1M87.2 74.8v1l.3 .1M87.5 77h.4M87.7 76.6v1l.2 .2M87.9 75.2h.4l.1 .7"/>
<path d="M88.4 75.5h-.4l-.2 .2 .2 .2h.4M88.8 77.1l-.3-.1-.2 .3 .1 .4h.4M88.9 75.2v.7M89.2 75.2l-.3 .2M89.3 77.1h.4l.1 .7M89.3 76.6v1.2M89.5 75.2h.4M89.6 74.8v1l.3 .1M90.3 75.2v.7l.5-.1M90.8 75.2v.7M90.8 77.1l-.3-.1-.2 .3 .1 .4h.4M90.8 76.6v1.2"/>
<path d="M91.3 75.2h.4l.2 .2-.1 .5h-.5M91.3 75.2v1.1M91.4 77.1l.3-.1 .2 .3v.3l-.2 .2-.4-.2zM92.9 77v1l-.2 .2-.3-.1M92.9 77.1l-.3-.1-.2 .3 .1 .4h.4M93.7 75.2h-.3l-.2 .2 .1 .5h.4M94.2 75.3l.5-.1v.7M94.2 74.8v1.1M94.3 76.6v.2M94.3 77v.8M95.2 75.6l.6-.1-.1-.3h-.3l-.2 .1 .1 .6h.4M95.3 77.1l-.3-.1-.2 .2 .1 .2 .4 .1v.2h-.5"/>
<path d="M96.5 77h.5M96.8 75.2h-.4l-.2 .2 .1 .5h.5M97 76.6l-.3 .2v1M97.2 74.8v1.1M97.4 75.5l.3 .4M97.4 76.6v.2M97.4 77v.8M97.7 75.2l-.5 .4M97.7 77h.5M97.9 76.6v1l.3 .2M98.4 77h.4M98.6 75.2h-.3l-.2 .1 .1 .2 .4 .1v.3h-.5"/>
<path d="M98.6 76.6v1l.2 .2M99.1 75.8v.1M99.2 77.4l.5-.1v-.2l-.4-.1-.1 .2v.5h.5M100.7 77.1l-.3-.1-.3 .3 .2 .4h.4M100.7 76.6v1.2M101.2 77.7v.1M95.1 126v1.1M96.2 126.1a.5 .5 0 0 0-.6 .5 .5 .5 0 0 0 .7 .4v-.3h-.2M96.8 126.5h.6M96.8 126v1.1M97.4 126v1.1M224.7 126v1.1"/>
<path d="M225.8 126.1a.5 .5 0 0 0-.7 .5 .5 .5 0 0 0 .7 .4v-.3h-.2M226.3 126.5h.6M226.3 126v1.1M226.9 126v1.1M354.2 126v1.1M355.3 126.1a.5 .5 0 0 0-.6 .5 .5 .5 0 0 0 .7 .4v-.3h-.2M355.8 126v1.1M355.8 126.5h.7M356.5 126v1.1M95.1 179.4v1.1M96.2 179.4a.5 .5 0 0 0-.6 .5 .5 .5 0 0 0 .7 .5v-.4h-.2M96.8 179.9h.6"/>
<path d="M96.8 179.4v1.1M97.4 179.4v1.1M224.7 179.4v1.1M225.8 179.4a.5 .5 0 0 0-.7 .5 .5 .5 0 0 0 .7 .5v-.4h-.2M226.3 179.9h.6M226.3 179.4v1.1M226.9 179.4v1.1M354.2 179.4v1.1M355.3 179.4a.5 .5 0 0 0-.6 .5 .5 .5 0 0 0 .7 .5v-.4h-.2M355.8 179.4v1.1M355.8 179.9h.7M356.5 179.4v1.1"/>
<path d="M95.1 232.7v1.1M96.2 232.8a.5 .5 0 0 0-.6 .5 .5 .5 0 0 0 .7 .4v-.4h-.2M96.8 233.2h.6M96.8 232.7v1.1M97.4 232.7v1.1M224.7 232.7v1.1M225.8 232.8a.5 .5 0 0 0-.7 .5 .5 .5 0 0 0 .7 .4v-.4h-.2M226.3 233.2h.6M226.3 232.7v1.1M226.9 232.7v1.1M354.2 232.7v1.1M355.3 232.8a.5 .5 0 0 0-.6 .5 .5 .5 0 0 0 .7 .4v-.4h-.2"/>
<path d="M355.8 232.7v1.1M355.8 233.2h.7M356.5 232.7v1.1"/>
</g>
<path d="M166.5 33.2h.5M167.1 32.3h-.4l-.2 .1 .1 .3 .4 .1M180.1 32.3h.3l.2 .1-.1 .3-.4 .1M180.3 32.8l.3 .5" fill="none" stroke="#006464" stroke-width=".18"/>
<use href="#words"/>
</svg>
